VERSION 5.7 ;
  NOWIREEXTENSIONATPIN ON ;
  DIVIDERCHAR "/" ;
  BUSBITCHARS "[]" ;
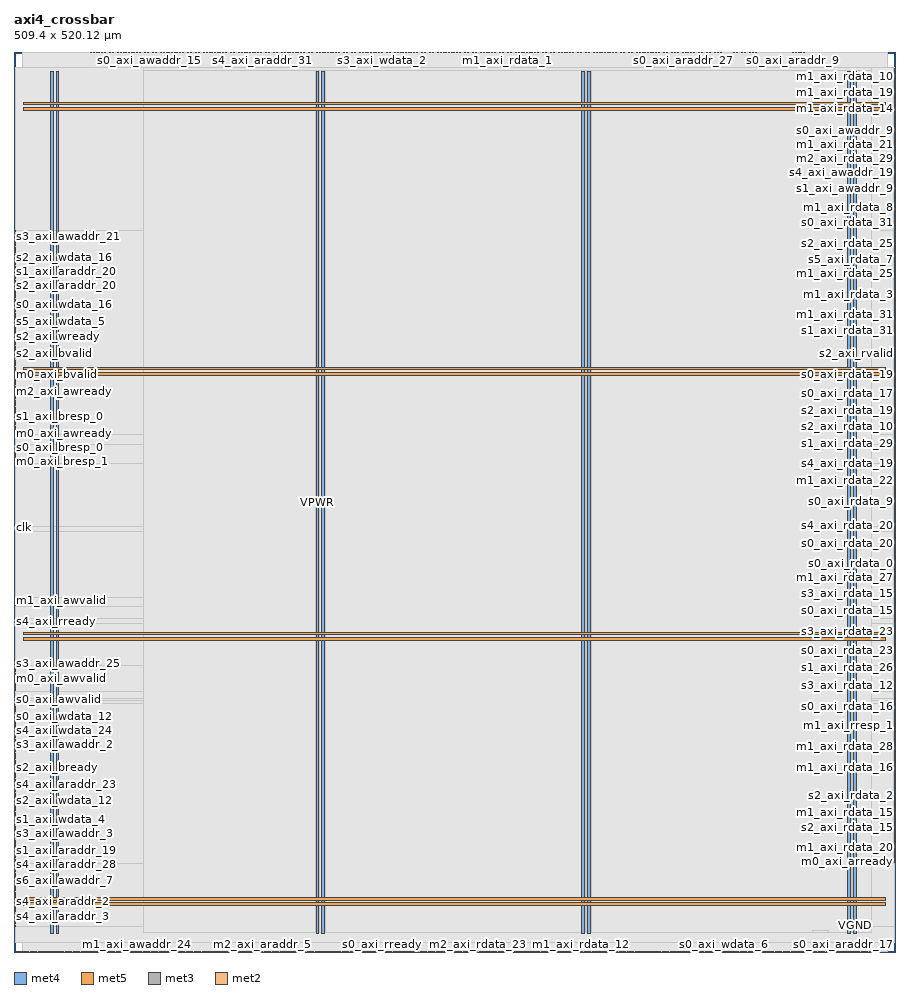
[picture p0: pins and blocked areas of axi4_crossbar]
MACRO axi4_crossbar
  CLASS BLOCK ;
  FOREIGN axi4_crossbar ;
  ORIGIN 0.000 0.000 ;
  SIZE 509.400 BY 520.120 ;
  PIN VGND
    DIRECTION INOUT ;
    USE GROUND ;
    PORT
      LAYER met4 ;
        RECT 24.340 10.640 25.940 508.880 ;
    END
    PORT
      LAYER met4 ;
        RECT 177.940 10.640 179.540 508.880 ;
    END
    PORT
      LAYER met4 ;
        RECT 331.540 10.640 333.140 508.880 ;
    END
    PORT
      LAYER met4 ;
        RECT 485.140 10.640 486.740 508.880 ;
    END
    PORT
      LAYER met5 ;
        RECT 5.520 30.030 503.700 31.630 ;
    END
    PORT
      LAYER met5 ;
        RECT 5.520 183.210 503.700 184.810 ;
    END
    PORT
      LAYER met5 ;
        RECT 5.520 336.390 503.700 337.990 ;
    END
    PORT
      LAYER met5 ;
        RECT 5.520 489.570 503.700 491.170 ;
    END
  END VGND
  PIN VPWR
    DIRECTION INOUT ;
    USE POWER ;
    PORT
      LAYER met4 ;
        RECT 21.040 10.640 22.640 508.880 ;
    END
    PORT
      LAYER met4 ;
        RECT 174.640 10.640 176.240 508.880 ;
    END
    PORT
      LAYER met4 ;
        RECT 328.240 10.640 329.840 508.880 ;
    END
    PORT
      LAYER met4 ;
        RECT 481.840 10.640 483.440 508.880 ;
    END
    PORT
      LAYER met5 ;
        RECT 5.520 26.730 503.700 28.330 ;
    END
    PORT
      LAYER met5 ;
        RECT 5.520 179.910 503.700 181.510 ;
    END
    PORT
      LAYER met5 ;
        RECT 5.520 333.090 503.700 334.690 ;
    END
    PORT
      LAYER met5 ;
        RECT 5.520 486.270 503.700 487.870 ;
    END
  END VPWR
  PIN clk
    DIRECTION INPUT ;
    USE SIGNAL ;
    ANTENNAGATEAREA 1.286700 ;
    ANTENNADIFFAREA 0.434700 ;
    PORT
      LAYER met3 ;
        RECT 0.000 244.840 0.600 245.440 ;
    END
  END clk
  PIN m0_axi_araddr_0
    DIRECTION INPUT ;
    USE SIGNAL ;
    PORT
      LAYER met2 ;
        RECT 1.930 0.000 2.210 0.280 ;
    END
  END m0_axi_araddr_0
  PIN m0_axi_araddr_1
    DIRECTION INPUT ;
    USE SIGNAL ;
    PORT
      LAYER met2 ;
        RECT 2.850 0.000 3.130 0.280 ;
    END
  END m0_axi_araddr_1
  PIN m0_axi_araddr_10
    DIRECTION INPUT ;
    USE SIGNAL ;
    PORT
      LAYER met2 ;
        RECT 3.770 0.000 4.050 0.280 ;
    END
  END m0_axi_araddr_10
  PIN m0_axi_araddr_11
    DIRECTION INPUT ;
    USE SIGNAL ;
    PORT
      LAYER met2 ;
        RECT 4.690 0.000 4.970 0.280 ;
    END
  END m0_axi_araddr_11
  PIN m0_axi_araddr_12
    DIRECTION INPUT ;
    USE SIGNAL ;
    PORT
      LAYER met2 ;
        RECT 5.610 0.000 5.890 0.280 ;
    END
  END m0_axi_araddr_12
  PIN m0_axi_araddr_13
    DIRECTION INPUT ;
    USE SIGNAL ;
    PORT
      LAYER met2 ;
        RECT 6.530 0.000 6.810 0.280 ;
    END
  END m0_axi_araddr_13
  PIN m0_axi_araddr_14
    DIRECTION INPUT ;
    USE SIGNAL ;
    PORT
      LAYER met2 ;
        RECT 7.450 0.000 7.730 0.280 ;
    END
  END m0_axi_araddr_14
  PIN m0_axi_araddr_15
    DIRECTION INPUT ;
    USE SIGNAL ;
    PORT
      LAYER met2 ;
        RECT 8.370 0.000 8.650 0.280 ;
    END
  END m0_axi_araddr_15
  PIN m0_axi_araddr_16
    DIRECTION INPUT ;
    USE SIGNAL ;
    PORT
      LAYER met2 ;
        RECT 9.290 0.000 9.570 0.280 ;
    END
  END m0_axi_araddr_16
  PIN m0_axi_araddr_17
    DIRECTION INPUT ;
    USE SIGNAL ;
    PORT
      LAYER met2 ;
        RECT 10.210 0.000 10.490 0.280 ;
    END
  END m0_axi_araddr_17
  PIN m0_axi_araddr_18
    DIRECTION INPUT ;
    USE SIGNAL ;
    PORT
      LAYER met2 ;
        RECT 11.130 0.000 11.410 0.280 ;
    END
  END m0_axi_araddr_18
  PIN m0_axi_araddr_19
    DIRECTION INPUT ;
    USE SIGNAL ;
    PORT
      LAYER met2 ;
        RECT 12.050 0.000 12.330 0.280 ;
    END
  END m0_axi_araddr_19
  PIN m0_axi_araddr_2
    DIRECTION INPUT ;
    USE SIGNAL ;
    PORT
      LAYER met2 ;
        RECT 12.970 0.000 13.250 0.280 ;
    END
  END m0_axi_araddr_2
  PIN m0_axi_araddr_20
    DIRECTION INPUT ;
    USE SIGNAL ;
    PORT
      LAYER met2 ;
        RECT 13.890 0.000 14.170 0.280 ;
    END
  END m0_axi_araddr_20
  PIN m0_axi_araddr_21
    DIRECTION INPUT ;
    USE SIGNAL ;
    PORT
      LAYER met2 ;
        RECT 14.810 0.000 15.090 0.280 ;
    END
  END m0_axi_araddr_21
  PIN m0_axi_araddr_22
    DIRECTION INPUT ;
    USE SIGNAL ;
    PORT
      LAYER met2 ;
        RECT 15.730 0.000 16.010 0.280 ;
    END
  END m0_axi_araddr_22
  PIN m0_axi_araddr_23
    DIRECTION INPUT ;
    USE SIGNAL ;
    PORT
      LAYER met2 ;
        RECT 16.650 0.000 16.930 0.280 ;
    END
  END m0_axi_araddr_23
  PIN m0_axi_araddr_24
    DIRECTION INPUT ;
    USE SIGNAL ;
    PORT
      LAYER met2 ;
        RECT 17.570 0.000 17.850 0.280 ;
    END
  END m0_axi_araddr_24
  PIN m0_axi_araddr_25
    DIRECTION INPUT ;
    USE SIGNAL ;
    PORT
      LAYER met2 ;
        RECT 18.490 0.000 18.770 0.280 ;
    END
  END m0_axi_araddr_25
  PIN m0_axi_araddr_26
    DIRECTION INPUT ;
    USE SIGNAL ;
    PORT
      LAYER met2 ;
        RECT 19.410 0.000 19.690 0.280 ;
    END
  END m0_axi_araddr_26
  PIN m0_axi_araddr_27
    DIRECTION INPUT ;
    USE SIGNAL ;
    PORT
      LAYER met2 ;
        RECT 20.330 0.000 20.610 0.280 ;
    END
  END m0_axi_araddr_27
  PIN m0_axi_araddr_28
    DIRECTION INPUT ;
    USE SIGNAL ;
    PORT
      LAYER met2 ;
        RECT 21.250 0.000 21.530 0.280 ;
    END
  END m0_axi_araddr_28
  PIN m0_axi_araddr_29
    DIRECTION INPUT ;
    USE SIGNAL ;
    PORT
      LAYER met2 ;
        RECT 22.170 0.000 22.450 0.280 ;
    END
  END m0_axi_araddr_29
  PIN m0_axi_araddr_3
    DIRECTION INPUT ;
    USE SIGNAL ;
    PORT
      LAYER met2 ;
        RECT 23.090 0.000 23.370 0.280 ;
    END
  END m0_axi_araddr_3
  PIN m0_axi_araddr_30
    DIRECTION INPUT ;
    USE SIGNAL ;
    PORT
      LAYER met2 ;
        RECT 24.010 0.000 24.290 0.280 ;
    END
  END m0_axi_araddr_30
  PIN m0_axi_araddr_31
    DIRECTION INPUT ;
    USE SIGNAL ;
    PORT
      LAYER met2 ;
        RECT 24.930 0.000 25.210 0.280 ;
    END
  END m0_axi_araddr_31
  PIN m0_axi_araddr_4
    DIRECTION INPUT ;
    USE SIGNAL ;
    PORT
      LAYER met2 ;
        RECT 25.850 0.000 26.130 0.280 ;
    END
  END m0_axi_araddr_4
  PIN m0_axi_araddr_5
    DIRECTION INPUT ;
    USE SIGNAL ;
    PORT
      LAYER met2 ;
        RECT 26.770 0.000 27.050 0.280 ;
    END
  END m0_axi_araddr_5
  PIN m0_axi_araddr_6
    DIRECTION INPUT ;
    USE SIGNAL ;
    PORT
      LAYER met2 ;
        RECT 27.690 0.000 27.970 0.280 ;
    END
  END m0_axi_araddr_6
  PIN m0_axi_araddr_7
    DIRECTION INPUT ;
    USE SIGNAL ;
    PORT
      LAYER met2 ;
        RECT 28.610 0.000 28.890 0.280 ;
    END
  END m0_axi_araddr_7
  PIN m0_axi_araddr_8
    DIRECTION INPUT ;
    USE SIGNAL ;
    PORT
      LAYER met2 ;
        RECT 29.530 0.000 29.810 0.280 ;
    END
  END m0_axi_araddr_8
  PIN m0_axi_araddr_9
    DIRECTION INPUT ;
    USE SIGNAL ;
    PORT
      LAYER met2 ;
        RECT 30.450 0.000 30.730 0.280 ;
    END
  END m0_axi_araddr_9
  PIN m0_axi_arready
    DIRECTION OUTPUT ;
    USE SIGNAL ;
    ANTENNAGATEAREA 0.434700 ;
    ANTENNADIFFAREA 0.434700 ;
    PORT
      LAYER met3 ;
        RECT 508.800 51.720 509.400 52.320 ;
    END
  END m0_axi_arready
  PIN m0_axi_arvalid
    DIRECTION INPUT ;
    USE SIGNAL ;
    ANTENNAGATEAREA 0.647700 ;
    ANTENNADIFFAREA 0.434700 ;
    PORT
      LAYER met2 ;
        RECT 167.530 519.840 167.810 520.120 ;
    END
  END m0_axi_arvalid
  PIN m0_axi_awready
    DIRECTION OUTPUT ;
    USE SIGNAL ;
    ANTENNAGATEAREA 0.434700 ;
    ANTENNADIFFAREA 1.137600 ;
    PORT
      LAYER met3 ;
        RECT 0.000 299.240 0.600 299.840 ;
    END
  END m0_axi_awready
  PIN m0_axi_awvalid
    DIRECTION INPUT ;
    USE SIGNAL ;
    ANTENNAGATEAREA 0.647700 ;
    ANTENNADIFFAREA 0.434700 ;
    PORT
      LAYER met3 ;
        RECT 0.000 157.800 0.600 158.400 ;
    END
  END m0_axi_awvalid
  PIN m0_axi_bresp_0
    DIRECTION OUTPUT ;
    USE SIGNAL ;
    ANTENNAGATEAREA 0.434700 ;
    ANTENNADIFFAREA 1.137600 ;
    PORT
      LAYER met3 ;
        RECT 0.000 292.440 0.600 293.040 ;
    END
  END m0_axi_bresp_0
  PIN m0_axi_bresp_1
    DIRECTION OUTPUT ;
    USE SIGNAL ;
    ANTENNAGATEAREA 0.434700 ;
    ANTENNADIFFAREA 1.137600 ;
    PORT
      LAYER met3 ;
        RECT 0.000 282.920 0.600 283.520 ;
    END
  END m0_axi_bresp_1
  PIN m0_axi_bvalid
    DIRECTION OUTPUT ;
    USE SIGNAL ;
    ANTENNAGATEAREA 0.434700 ;
    ANTENNADIFFAREA 1.137600 ;
    PORT
      LAYER met3 ;
        RECT 0.000 333.240 0.600 333.840 ;
    END
  END m0_axi_bvalid
  PIN m0_axi_rdata_0
    DIRECTION OUTPUT ;
    USE SIGNAL ;
    PORT
      LAYER met2 ;
        RECT 31.370 0.000 31.650 0.280 ;
    END
  END m0_axi_rdata_0
  PIN m0_axi_rdata_1
    DIRECTION OUTPUT ;
    USE SIGNAL ;
    PORT
      LAYER met2 ;
        RECT 32.290 0.000 32.570 0.280 ;
    END
  END m0_axi_rdata_1
  PIN m0_axi_rdata_10
    DIRECTION OUTPUT ;
    USE SIGNAL ;
    PORT
      LAYER met2 ;
        RECT 33.210 0.000 33.490 0.280 ;
    END
  END m0_axi_rdata_10
  PIN m0_axi_rdata_11
    DIRECTION OUTPUT ;
    USE SIGNAL ;
    PORT
      LAYER met2 ;
        RECT 34.130 0.000 34.410 0.280 ;
    END
  END m0_axi_rdata_11
  PIN m0_axi_rdata_12
    DIRECTION OUTPUT ;
    USE SIGNAL ;
    PORT
      LAYER met2 ;
        RECT 35.050 0.000 35.330 0.280 ;
    END
  END m0_axi_rdata_12
  PIN m0_axi_rdata_13
    DIRECTION OUTPUT ;
    USE SIGNAL ;
    PORT
      LAYER met2 ;
        RECT 35.970 0.000 36.250 0.280 ;
    END
  END m0_axi_rdata_13
  PIN m0_axi_rdata_14
    DIRECTION OUTPUT ;
    USE SIGNAL ;
    ANTENNAGATEAREA 0.434700 ;
    ANTENNADIFFAREA 0.775300 ;
    PORT
      LAYER met2 ;
        RECT 254.930 519.840 255.210 520.120 ;
    END
  END m0_axi_rdata_14
  PIN m0_axi_rdata_15
    DIRECTION OUTPUT ;
    USE SIGNAL ;
    PORT
      LAYER met2 ;
        RECT 36.890 0.000 37.170 0.280 ;
    END
  END m0_axi_rdata_15
  PIN m0_axi_rdata_16
    DIRECTION OUTPUT ;
    USE SIGNAL ;
    PORT
      LAYER met2 ;
        RECT 37.810 0.000 38.090 0.280 ;
    END
  END m0_axi_rdata_16
  PIN m0_axi_rdata_17
    DIRECTION OUTPUT ;
    USE SIGNAL ;
    ANTENNAGATEAREA 0.434700 ;
    ANTENNADIFFAREA 0.775300 ;
    PORT
      LAYER met2 ;
        RECT 249.410 519.840 249.690 520.120 ;
    END
  END m0_axi_rdata_17
  PIN m0_axi_rdata_18
    DIRECTION OUTPUT ;
    USE SIGNAL ;
    PORT
      LAYER met2 ;
        RECT 38.730 0.000 39.010 0.280 ;
    END
  END m0_axi_rdata_18
  PIN m0_axi_rdata_19
    DIRECTION OUTPUT ;
    USE SIGNAL ;
    PORT
      LAYER met2 ;
        RECT 39.650 0.000 39.930 0.280 ;
    END
  END m0_axi_rdata_19
  PIN m0_axi_rdata_2
    DIRECTION OUTPUT ;
    USE SIGNAL ;
    PORT
      LAYER met2 ;
        RECT 40.570 0.000 40.850 0.280 ;
    END
  END m0_axi_rdata_2
  PIN m0_axi_rdata_20
    DIRECTION OUTPUT ;
    USE SIGNAL ;
    ANTENNAGATEAREA 0.434700 ;
    ANTENNADIFFAREA 0.775300 ;
    PORT
      LAYER met2 ;
        RECT 247.570 519.840 247.850 520.120 ;
    END
  END m0_axi_rdata_20
  PIN m0_axi_rdata_21
    DIRECTION OUTPUT ;
    USE SIGNAL ;
    PORT
      LAYER met2 ;
        RECT 41.490 0.000 41.770 0.280 ;
    END
  END m0_axi_rdata_21
  PIN m0_axi_rdata_22
    DIRECTION OUTPUT ;
    USE SIGNAL ;
    ANTENNAGATEAREA 0.434700 ;
    ANTENNADIFFAREA 0.775300 ;
    PORT
      LAYER met2 ;
        RECT 243.890 519.840 244.170 520.120 ;
    END
  END m0_axi_rdata_22
  PIN m0_axi_rdata_23
    DIRECTION OUTPUT ;
    USE SIGNAL ;
    PORT
      LAYER met2 ;
        RECT 42.410 0.000 42.690 0.280 ;
    END
  END m0_axi_rdata_23
  PIN m0_axi_rdata_24
    DIRECTION OUTPUT ;
    USE SIGNAL ;
    ANTENNAGATEAREA 0.434700 ;
    ANTENNADIFFAREA 0.775300 ;
    PORT
      LAYER met2 ;
        RECT 245.730 519.840 246.010 520.120 ;
    END
  END m0_axi_rdata_24
  PIN m0_axi_rdata_25
    DIRECTION OUTPUT ;
    USE SIGNAL ;
    PORT
      LAYER met2 ;
        RECT 43.330 0.000 43.610 0.280 ;
    END
  END m0_axi_rdata_25
  PIN m0_axi_rdata_26
    DIRECTION OUTPUT ;
    USE SIGNAL ;
    PORT
      LAYER met2 ;
        RECT 44.250 0.000 44.530 0.280 ;
    END
  END m0_axi_rdata_26
  PIN m0_axi_rdata_27
    DIRECTION OUTPUT ;
    USE SIGNAL ;
    PORT
      LAYER met2 ;
        RECT 45.170 0.000 45.450 0.280 ;
    END
  END m0_axi_rdata_27
  PIN m0_axi_rdata_28
    DIRECTION OUTPUT ;
    USE SIGNAL ;
    PORT
      LAYER met2 ;
        RECT 46.090 0.000 46.370 0.280 ;
    END
  END m0_axi_rdata_28
  PIN m0_axi_rdata_29
    DIRECTION OUTPUT ;
    USE SIGNAL ;
    ANTENNAGATEAREA 0.434700 ;
    ANTENNADIFFAREA 0.775300 ;
    PORT
      LAYER met2 ;
        RECT 242.050 519.840 242.330 520.120 ;
    END
  END m0_axi_rdata_29
  PIN m0_axi_rdata_3
    DIRECTION OUTPUT ;
    USE SIGNAL ;
    PORT
      LAYER met2 ;
        RECT 47.010 0.000 47.290 0.280 ;
    END
  END m0_axi_rdata_3
  PIN m0_axi_rdata_30
    DIRECTION OUTPUT ;
    USE SIGNAL ;
    PORT
      LAYER met2 ;
        RECT 47.930 0.000 48.210 0.280 ;
    END
  END m0_axi_rdata_30
  PIN m0_axi_rdata_31
    DIRECTION OUTPUT ;
    USE SIGNAL ;
    PORT
      LAYER met2 ;
        RECT 48.850 0.000 49.130 0.280 ;
    END
  END m0_axi_rdata_31
  PIN m0_axi_rdata_4
    DIRECTION OUTPUT ;
    USE SIGNAL ;
    ANTENNAGATEAREA 0.434700 ;
    ANTENNADIFFAREA 0.775300 ;
    PORT
      LAYER met2 ;
        RECT 252.170 519.840 252.450 520.120 ;
    END
  END m0_axi_rdata_4
  PIN m0_axi_rdata_5
    DIRECTION OUTPUT ;
    USE SIGNAL ;
    PORT
      LAYER met2 ;
        RECT 49.770 0.000 50.050 0.280 ;
    END
  END m0_axi_rdata_5
  PIN m0_axi_rdata_6
    DIRECTION OUTPUT ;
    USE SIGNAL ;
    PORT
      LAYER met2 ;
        RECT 50.690 0.000 50.970 0.280 ;
    END
  END m0_axi_rdata_6
  PIN m0_axi_rdata_7
    DIRECTION OUTPUT ;
    USE SIGNAL ;
    PORT
      LAYER met2 ;
        RECT 51.610 0.000 51.890 0.280 ;
    END
  END m0_axi_rdata_7
  PIN m0_axi_rdata_8
    DIRECTION OUTPUT ;
    USE SIGNAL ;
    ANTENNAGATEAREA 0.434700 ;
    ANTENNADIFFAREA 0.775300 ;
    PORT
      LAYER met2 ;
        RECT 246.650 519.840 246.930 520.120 ;
    END
  END m0_axi_rdata_8
  PIN m0_axi_rdata_9
    DIRECTION OUTPUT ;
    USE SIGNAL ;
    PORT
      LAYER met2 ;
        RECT 52.530 0.000 52.810 0.280 ;
    END
  END m0_axi_rdata_9
  PIN m0_axi_rready
    DIRECTION INPUT ;
    USE SIGNAL ;
    ANTENNAGATEAREA 0.647700 ;
    ANTENNADIFFAREA 0.434700 ;
    PORT
      LAYER met2 ;
        RECT 236.530 0.000 236.810 0.280 ;
    END
  END m0_axi_rready
  PIN m0_axi_rresp_0
    DIRECTION OUTPUT ;
    USE SIGNAL ;
    PORT
      LAYER met2 ;
        RECT 53.450 0.000 53.730 0.280 ;
    END
  END m0_axi_rresp_0
  PIN m0_axi_rresp_1
    DIRECTION OUTPUT ;
    USE SIGNAL ;
    PORT
      LAYER met2 ;
        RECT 54.370 0.000 54.650 0.280 ;
    END
  END m0_axi_rresp_1
  PIN m0_axi_rvalid
    DIRECTION OUTPUT ;
    USE SIGNAL ;
    ANTENNAGATEAREA 0.434700 ;
    ANTENNADIFFAREA 1.137600 ;
    PORT
      LAYER met2 ;
        RECT 249.410 0.000 249.690 0.280 ;
    END
  END m0_axi_rvalid
  PIN m0_axi_wready
    DIRECTION OUTPUT ;
    USE SIGNAL ;
    ANTENNAGATEAREA 0.434700 ;
    ANTENNADIFFAREA 1.137600 ;
    PORT
      LAYER met3 ;
        RECT 0.000 346.840 0.600 347.440 ;
    END
  END m0_axi_wready
  PIN m0_axi_wvalid
    DIRECTION INPUT ;
    USE SIGNAL ;
    ANTENNAGATEAREA 0.647700 ;
    ANTENNADIFFAREA 0.434700 ;
    PORT
      LAYER met3 ;
        RECT 0.000 155.080 0.600 155.680 ;
    END
  END m0_axi_wvalid
  PIN m1_axi_arready
    DIRECTION OUTPUT ;
    USE SIGNAL ;
    ANTENNAGATEAREA 0.434700 ;
    ANTENNADIFFAREA 1.137600 ;
    PORT
      LAYER met2 ;
        RECT 255.850 519.840 256.130 520.120 ;
    END
  END m1_axi_arready
  PIN m1_axi_awaddr_0
    DIRECTION INPUT ;
    USE SIGNAL ;
    PORT
      LAYER met2 ;
        RECT 55.290 0.000 55.570 0.280 ;
    END
  END m1_axi_awaddr_0
  PIN m1_axi_awaddr_1
    DIRECTION INPUT ;
    USE SIGNAL ;
    PORT
      LAYER met2 ;
        RECT 56.210 0.000 56.490 0.280 ;
    END
  END m1_axi_awaddr_1
  PIN m1_axi_awaddr_10
    DIRECTION INPUT ;
    USE SIGNAL ;
    PORT
      LAYER met2 ;
        RECT 57.130 0.000 57.410 0.280 ;
    END
  END m1_axi_awaddr_10
  PIN m1_axi_awaddr_11
    DIRECTION INPUT ;
    USE SIGNAL ;
    PORT
      LAYER met2 ;
        RECT 58.050 0.000 58.330 0.280 ;
    END
  END m1_axi_awaddr_11
  PIN m1_axi_awaddr_12
    DIRECTION INPUT ;
    USE SIGNAL ;
    PORT
      LAYER met2 ;
        RECT 58.970 0.000 59.250 0.280 ;
    END
  END m1_axi_awaddr_12
  PIN m1_axi_awaddr_13
    DIRECTION INPUT ;
    USE SIGNAL ;
    PORT
      LAYER met2 ;
        RECT 59.890 0.000 60.170 0.280 ;
    END
  END m1_axi_awaddr_13
  PIN m1_axi_awaddr_14
    DIRECTION INPUT ;
    USE SIGNAL ;
    PORT
      LAYER met2 ;
        RECT 60.810 0.000 61.090 0.280 ;
    END
  END m1_axi_awaddr_14
  PIN m1_axi_awaddr_15
    DIRECTION INPUT ;
    USE SIGNAL ;
    PORT
      LAYER met2 ;
        RECT 61.730 0.000 62.010 0.280 ;
    END
  END m1_axi_awaddr_15
  PIN m1_axi_awaddr_16
    DIRECTION INPUT ;
    USE SIGNAL ;
    PORT
      LAYER met2 ;
        RECT 62.650 0.000 62.930 0.280 ;
    END
  END m1_axi_awaddr_16
  PIN m1_axi_awaddr_17
    DIRECTION INPUT ;
    USE SIGNAL ;
    PORT
      LAYER met2 ;
        RECT 63.570 0.000 63.850 0.280 ;
    END
  END m1_axi_awaddr_17
  PIN m1_axi_awaddr_18
    DIRECTION INPUT ;
    USE SIGNAL ;
    PORT
      LAYER met2 ;
        RECT 64.490 0.000 64.770 0.280 ;
    END
  END m1_axi_awaddr_18
  PIN m1_axi_awaddr_19
    DIRECTION INPUT ;
    USE SIGNAL ;
    PORT
      LAYER met2 ;
        RECT 65.410 0.000 65.690 0.280 ;
    END
  END m1_axi_awaddr_19
  PIN m1_axi_awaddr_2
    DIRECTION INPUT ;
    USE SIGNAL ;
    PORT
      LAYER met2 ;
        RECT 66.330 0.000 66.610 0.280 ;
    END
  END m1_axi_awaddr_2
  PIN m1_axi_awaddr_20
    DIRECTION INPUT ;
    USE SIGNAL ;
    PORT
      LAYER met2 ;
        RECT 67.250 0.000 67.530 0.280 ;
    END
  END m1_axi_awaddr_20
  PIN m1_axi_awaddr_21
    DIRECTION INPUT ;
    USE SIGNAL ;
    PORT
      LAYER met2 ;
        RECT 68.170 0.000 68.450 0.280 ;
    END
  END m1_axi_awaddr_21
  PIN m1_axi_awaddr_22
    DIRECTION INPUT ;
    USE SIGNAL ;
    PORT
      LAYER met2 ;
        RECT 69.090 0.000 69.370 0.280 ;
    END
  END m1_axi_awaddr_22
  PIN m1_axi_awaddr_23
    DIRECTION INPUT ;
    USE SIGNAL ;
    PORT
      LAYER met2 ;
        RECT 70.010 0.000 70.290 0.280 ;
    END
  END m1_axi_awaddr_23
  PIN m1_axi_awaddr_24
    DIRECTION INPUT ;
    USE SIGNAL ;
    PORT
      LAYER met2 ;
        RECT 70.930 0.000 71.210 0.280 ;
    END
  END m1_axi_awaddr_24
  PIN m1_axi_awaddr_25
    DIRECTION INPUT ;
    USE SIGNAL ;
    PORT
      LAYER met2 ;
        RECT 71.850 0.000 72.130 0.280 ;
    END
  END m1_axi_awaddr_25
  PIN m1_axi_awaddr_26
    DIRECTION INPUT ;
    USE SIGNAL ;
    PORT
      LAYER met2 ;
        RECT 72.770 0.000 73.050 0.280 ;
    END
  END m1_axi_awaddr_26
  PIN m1_axi_awaddr_27
    DIRECTION INPUT ;
    USE SIGNAL ;
    PORT
      LAYER met2 ;
        RECT 73.690 0.000 73.970 0.280 ;
    END
  END m1_axi_awaddr_27
  PIN m1_axi_awaddr_28
    DIRECTION INPUT ;
    USE SIGNAL ;
    PORT
      LAYER met2 ;
        RECT 74.610 0.000 74.890 0.280 ;
    END
  END m1_axi_awaddr_28
  PIN m1_axi_awaddr_29
    DIRECTION INPUT ;
    USE SIGNAL ;
    PORT
      LAYER met2 ;
        RECT 75.530 0.000 75.810 0.280 ;
    END
  END m1_axi_awaddr_29
  PIN m1_axi_awaddr_3
    DIRECTION INPUT ;
    USE SIGNAL ;
    PORT
      LAYER met2 ;
        RECT 76.450 0.000 76.730 0.280 ;
    END
  END m1_axi_awaddr_3
  PIN m1_axi_awaddr_30
    DIRECTION INPUT ;
    USE SIGNAL ;
    PORT
      LAYER met2 ;
        RECT 77.370 0.000 77.650 0.280 ;
    END
  END m1_axi_awaddr_30
  PIN m1_axi_awaddr_31
    DIRECTION INPUT ;
    USE SIGNAL ;
    PORT
      LAYER met2 ;
        RECT 78.290 0.000 78.570 0.280 ;
    END
  END m1_axi_awaddr_31
  PIN m1_axi_awaddr_4
    DIRECTION INPUT ;
    USE SIGNAL ;
    PORT
      LAYER met2 ;
        RECT 79.210 0.000 79.490 0.280 ;
    END
  END m1_axi_awaddr_4
  PIN m1_axi_awaddr_5
    DIRECTION INPUT ;
    USE SIGNAL ;
    PORT
      LAYER met2 ;
        RECT 80.130 0.000 80.410 0.280 ;
    END
  END m1_axi_awaddr_5
  PIN m1_axi_awaddr_6
    DIRECTION INPUT ;
    USE SIGNAL ;
    PORT
      LAYER met2 ;
        RECT 81.050 0.000 81.330 0.280 ;
    END
  END m1_axi_awaddr_6
  PIN m1_axi_awaddr_7
    DIRECTION INPUT ;
    USE SIGNAL ;
    PORT
      LAYER met2 ;
        RECT 81.970 0.000 82.250 0.280 ;
    END
  END m1_axi_awaddr_7
  PIN m1_axi_awaddr_8
    DIRECTION INPUT ;
    USE SIGNAL ;
    PORT
      LAYER met2 ;
        RECT 82.890 0.000 83.170 0.280 ;
    END
  END m1_axi_awaddr_8
  PIN m1_axi_awaddr_9
    DIRECTION INPUT ;
    USE SIGNAL ;
    PORT
      LAYER met2 ;
        RECT 83.810 0.000 84.090 0.280 ;
    END
  END m1_axi_awaddr_9
  PIN m1_axi_awready
    DIRECTION OUTPUT ;
    USE SIGNAL ;
    ANTENNAGATEAREA 0.434700 ;
    ANTENNADIFFAREA 1.137600 ;
    PORT
      LAYER met3 ;
        RECT 0.000 344.120 0.600 344.720 ;
    END
  END m1_axi_awready
  PIN m1_axi_awvalid
    DIRECTION INPUT ;
    USE SIGNAL ;
    ANTENNAGATEAREA 0.647700 ;
    ANTENNADIFFAREA 0.434700 ;
    PORT
      LAYER met3 ;
        RECT 0.000 202.680 0.600 203.280 ;
    END
  END m1_axi_awvalid
  PIN m1_axi_bready
    DIRECTION INPUT ;
    USE SIGNAL ;
    PORT
      LAYER met2 ;
        RECT 84.730 0.000 85.010 0.280 ;
    END
  END m1_axi_bready
  PIN m1_axi_bresp_0
    DIRECTION OUTPUT ;
    USE SIGNAL ;
    ANTENNAGATEAREA 0.434700 ;
    ANTENNADIFFAREA 1.137600 ;
    PORT
      LAYER met3 ;
        RECT 0.000 287.000 0.600 287.600 ;
    END
  END m1_axi_bresp_0
  PIN m1_axi_bresp_1
    DIRECTION OUTPUT ;
    USE SIGNAL ;
    ANTENNAGATEAREA 0.434700 ;
    ANTENNADIFFAREA 1.137600 ;
    PORT
      LAYER met3 ;
        RECT 0.000 284.280 0.600 284.880 ;
    END
  END m1_axi_bresp_1
  PIN m1_axi_bvalid
    DIRECTION OUTPUT ;
    USE SIGNAL ;
    ANTENNAGATEAREA 0.434700 ;
    ANTENNADIFFAREA 1.137600 ;
    PORT
      LAYER met3 ;
        RECT 0.000 331.880 0.600 332.480 ;
    END
  END m1_axi_bvalid
  PIN m1_axi_rdata_0
    DIRECTION OUTPUT ;
    USE SIGNAL ;
    ANTENNAGATEAREA 0.434700 ;
    ANTENNADIFFAREA 0.880200 ;
    PORT
      LAYER met3 ;
        RECT 508.800 65.320 509.400 65.920 ;
    END
  END m1_axi_rdata_0
  PIN m1_axi_rdata_1
    DIRECTION OUTPUT ;
    USE SIGNAL ;
    ANTENNAGATEAREA 0.434700 ;
    ANTENNADIFFAREA 1.137600 ;
    PORT
      LAYER met2 ;
        RECT 285.290 519.840 285.570 520.120 ;
    END
  END m1_axi_rdata_1
  PIN m1_axi_rdata_10
    DIRECTION OUTPUT ;
    USE SIGNAL ;
    ANTENNAGATEAREA 0.560700 ;
    ANTENNADIFFAREA 0.863700 ;
    PORT
      LAYER met3 ;
        RECT 508.800 510.040 509.400 510.640 ;
    END
  END m1_axi_rdata_10
  PIN m1_axi_rdata_11
    DIRECTION OUTPUT ;
    USE SIGNAL ;
    ANTENNAGATEAREA 0.560700 ;
    ANTENNADIFFAREA 0.863700 ;
    PORT
      LAYER met2 ;
        RECT 283.450 0.000 283.730 0.280 ;
    END
  END m1_axi_rdata_11
  PIN m1_axi_rdata_12
    DIRECTION OUTPUT ;
    USE SIGNAL ;
    ANTENNAGATEAREA 0.560700 ;
    ANTENNADIFFAREA 0.863700 ;
    PORT
      LAYER met2 ;
        RECT 327.610 0.000 327.890 0.280 ;
    END
  END m1_axi_rdata_12
  PIN m1_axi_rdata_13
    DIRECTION OUTPUT ;
    USE SIGNAL ;
    ANTENNAGATEAREA 0.560700 ;
    ANTENNADIFFAREA 0.863700 ;
    PORT
      LAYER met3 ;
        RECT 508.800 62.600 509.400 63.200 ;
    END
  END m1_axi_rdata_13
  PIN m1_axi_rdata_14
    DIRECTION OUTPUT ;
    USE SIGNAL ;
    ANTENNAGATEAREA 0.434700 ;
    ANTENNADIFFAREA 1.137600 ;
    PORT
      LAYER met3 ;
        RECT 508.800 486.920 509.400 487.520 ;
    END
  END m1_axi_rdata_14
  PIN m1_axi_rdata_15
    DIRECTION OUTPUT ;
    USE SIGNAL ;
    ANTENNAGATEAREA 0.560700 ;
    ANTENNADIFFAREA 0.863700 ;
    PORT
      LAYER met3 ;
        RECT 508.800 80.280 509.400 80.880 ;
    END
  END m1_axi_rdata_15
  PIN m1_axi_rdata_16
    DIRECTION OUTPUT ;
    USE SIGNAL ;
    ANTENNAGATEAREA 0.560700 ;
    ANTENNADIFFAREA 0.863700 ;
    PORT
      LAYER met3 ;
        RECT 508.800 106.120 509.400 106.720 ;
    END
  END m1_axi_rdata_16
  PIN m1_axi_rdata_17
    DIRECTION OUTPUT ;
    USE SIGNAL ;
    ANTENNAGATEAREA 0.434700 ;
    ANTENNADIFFAREA 1.137600 ;
    PORT
      LAYER met3 ;
        RECT 508.800 503.240 509.400 503.840 ;
    END
  END m1_axi_rdata_17
  PIN m1_axi_rdata_18
    DIRECTION OUTPUT ;
    USE SIGNAL ;
    ANTENNAGATEAREA 0.560700 ;
    ANTENNADIFFAREA 0.863700 ;
    PORT
      LAYER met2 ;
        RECT 275.170 0.000 275.450 0.280 ;
    END
  END m1_axi_rdata_18
  PIN m1_axi_rdata_19
    DIRECTION OUTPUT ;
    USE SIGNAL ;
    ANTENNAGATEAREA 0.434700 ;
    ANTENNADIFFAREA 0.832300 ;
    PORT
      LAYER met3 ;
        RECT 508.800 492.360 509.400 492.960 ;
    END
  END m1_axi_rdata_19
  PIN m1_axi_rdata_2
    DIRECTION OUTPUT ;
    USE SIGNAL ;
    ANTENNAGATEAREA 0.560700 ;
    ANTENNADIFFAREA 0.863700 ;
    PORT
      LAYER met3 ;
        RECT 508.800 88.440 509.400 89.040 ;
    END
  END m1_axi_rdata_2
  PIN m1_axi_rdata_20
    DIRECTION OUTPUT ;
    USE SIGNAL ;
    ANTENNAGATEAREA 0.560700 ;
    ANTENNADIFFAREA 0.863700 ;
    PORT
      LAYER met3 ;
        RECT 508.800 59.880 509.400 60.480 ;
    END
  END m1_axi_rdata_20
  PIN m1_axi_rdata_21
    DIRECTION OUTPUT ;
    USE SIGNAL ;
    ANTENNAGATEAREA 0.560700 ;
    ANTENNADIFFAREA 0.863700 ;
    PORT
      LAYER met3 ;
        RECT 508.800 466.520 509.400 467.120 ;
    END
  END m1_axi_rdata_21
  PIN m1_axi_rdata_22
    DIRECTION OUTPUT ;
    USE SIGNAL ;
    ANTENNAGATEAREA 0.434700 ;
    ANTENNADIFFAREA 1.137600 ;
    PORT
      LAYER met3 ;
        RECT 508.800 272.040 509.400 272.640 ;
    END
  END m1_axi_rdata_22
  PIN m1_axi_rdata_23
    DIRECTION OUTPUT ;
    USE SIGNAL ;
    ANTENNAGATEAREA 0.560700 ;
    ANTENNADIFFAREA 0.863700 ;
    PORT
      LAYER met3 ;
        RECT 508.800 89.800 509.400 90.400 ;
    END
  END m1_axi_rdata_23
  PIN m1_axi_rdata_24
    DIRECTION OUTPUT ;
    USE SIGNAL ;
    ANTENNAGATEAREA 0.560700 ;
    ANTENNADIFFAREA 0.863700 ;
    PORT
      LAYER met2 ;
        RECT 286.210 0.000 286.490 0.280 ;
    END
  END m1_axi_rdata_24
  PIN m1_axi_rdata_25
    DIRECTION OUTPUT ;
    USE SIGNAL ;
    ANTENNAGATEAREA 0.560700 ;
    ANTENNADIFFAREA 0.863700 ;
    PORT
      LAYER met3 ;
        RECT 508.800 391.720 509.400 392.320 ;
    END
  END m1_axi_rdata_25
  PIN m1_axi_rdata_26
    DIRECTION OUTPUT ;
    USE SIGNAL ;
    ANTENNAGATEAREA 0.560700 ;
    ANTENNADIFFAREA 0.863700 ;
    PORT
      LAYER met3 ;
        RECT 508.800 97.960 509.400 98.560 ;
    END
  END m1_axi_rdata_26
  PIN m1_axi_rdata_27
    DIRECTION OUTPUT ;
    USE SIGNAL ;
    ANTENNAGATEAREA 0.560700 ;
    ANTENNADIFFAREA 0.863700 ;
    PORT
      LAYER met3 ;
        RECT 508.800 216.280 509.400 216.880 ;
    END
  END m1_axi_rdata_27
  PIN m1_axi_rdata_28
    DIRECTION OUTPUT ;
    USE SIGNAL ;
    ANTENNAGATEAREA 0.560700 ;
    ANTENNADIFFAREA 0.863700 ;
    PORT
      LAYER met3 ;
        RECT 508.800 118.360 509.400 118.960 ;
    END
  END m1_axi_rdata_28
  PIN m1_axi_rdata_29
    DIRECTION OUTPUT ;
    USE SIGNAL ;
    ANTENNAGATEAREA 0.434700 ;
    ANTENNADIFFAREA 1.137600 ;
    PORT
      LAYER met3 ;
        RECT 508.800 364.520 509.400 365.120 ;
    END
  END m1_axi_rdata_29
  PIN m1_axi_rdata_3
    DIRECTION OUTPUT ;
    USE SIGNAL ;
    ANTENNAGATEAREA 0.560700 ;
    ANTENNADIFFAREA 0.863700 ;
    PORT
      LAYER met3 ;
        RECT 508.800 379.480 509.400 380.080 ;
    END
  END m1_axi_rdata_3
  PIN m1_axi_rdata_30
    DIRECTION OUTPUT ;
    USE SIGNAL ;
    ANTENNAGATEAREA 0.560700 ;
    ANTENNADIFFAREA 0.863700 ;
    PORT
      LAYER met3 ;
        RECT 508.800 121.080 509.400 121.680 ;
    END
  END m1_axi_rdata_30
  PIN m1_axi_rdata_31
    DIRECTION OUTPUT ;
    USE SIGNAL ;
    ANTENNAGATEAREA 0.434700 ;
    ANTENNADIFFAREA 1.137600 ;
    PORT
      LAYER met3 ;
        RECT 508.800 372.680 509.400 373.280 ;
    END
  END m1_axi_rdata_31
  PIN m1_axi_rdata_4
    DIRECTION OUTPUT ;
    USE SIGNAL ;
    ANTENNAGATEAREA 0.434700 ;
    ANTENNADIFFAREA 1.137600 ;
    PORT
      LAYER met2 ;
        RECT 272.410 519.840 272.690 520.120 ;
    END
  END m1_axi_rdata_4
  PIN m1_axi_rdata_5
    DIRECTION OUTPUT ;
    USE SIGNAL ;
    ANTENNAGATEAREA 0.434700 ;
    ANTENNADIFFAREA 0.880200 ;
    PORT
      LAYER met3 ;
        RECT 508.800 61.240 509.400 61.840 ;
    END
  END m1_axi_rdata_5
  PIN m1_axi_rdata_6
    DIRECTION OUTPUT ;
    USE SIGNAL ;
    ANTENNAGATEAREA 0.434700 ;
    ANTENNADIFFAREA 0.832300 ;
    PORT
      LAYER met3 ;
        RECT 508.800 496.440 509.400 497.040 ;
    END
  END m1_axi_rdata_6
  PIN m1_axi_rdata_7
    DIRECTION OUTPUT ;
    USE SIGNAL ;
    ANTENNAGATEAREA 0.560700 ;
    ANTENNADIFFAREA 0.863700 ;
    PORT
      LAYER met3 ;
        RECT 508.800 390.360 509.400 390.960 ;
    END
  END m1_axi_rdata_7
  PIN m1_axi_rdata_8
    DIRECTION OUTPUT ;
    USE SIGNAL ;
    ANTENNAGATEAREA 0.434700 ;
    ANTENNADIFFAREA 1.137600 ;
    PORT
      LAYER met3 ;
        RECT 508.800 429.800 509.400 430.400 ;
    END
  END m1_axi_rdata_8
  PIN m1_axi_rdata_9
    DIRECTION OUTPUT ;
    USE SIGNAL ;
    ANTENNAGATEAREA 0.434700 ;
    ANTENNADIFFAREA 0.832300 ;
    PORT
      LAYER met3 ;
        RECT 508.800 267.960 509.400 268.560 ;
    END
  END m1_axi_rdata_9
  PIN m1_axi_rresp_0
    DIRECTION OUTPUT ;
    USE SIGNAL ;
    ANTENNAGATEAREA 0.434700 ;
    ANTENNADIFFAREA 1.137600 ;
    PORT
      LAYER met3 ;
        RECT 508.800 318.280 509.400 318.880 ;
    END
  END m1_axi_rresp_0
  PIN m1_axi_rresp_1
    DIRECTION OUTPUT ;
    USE SIGNAL ;
    ANTENNAGATEAREA 0.560700 ;
    ANTENNADIFFAREA 0.863700 ;
    PORT
      LAYER met3 ;
        RECT 508.800 130.600 509.400 131.200 ;
    END
  END m1_axi_rresp_1
  PIN m1_axi_rvalid
    DIRECTION OUTPUT ;
    USE SIGNAL ;
    ANTENNAGATEAREA 0.434700 ;
    ANTENNADIFFAREA 1.137600 ;
    PORT
      LAYER met3 ;
        RECT 508.800 427.080 509.400 427.680 ;
    END
  END m1_axi_rvalid
  PIN m1_axi_wdata_0
    DIRECTION INPUT ;
    USE SIGNAL ;
    PORT
      LAYER met2 ;
        RECT 85.650 0.000 85.930 0.280 ;
    END
  END m1_axi_wdata_0
  PIN m1_axi_wdata_1
    DIRECTION INPUT ;
    USE SIGNAL ;
    PORT
      LAYER met2 ;
        RECT 86.570 0.000 86.850 0.280 ;
    END
  END m1_axi_wdata_1
  PIN m1_axi_wdata_10
    DIRECTION INPUT ;
    USE SIGNAL ;
    PORT
      LAYER met2 ;
        RECT 87.490 0.000 87.770 0.280 ;
    END
  END m1_axi_wdata_10
  PIN m1_axi_wdata_11
    DIRECTION INPUT ;
    USE SIGNAL ;
    PORT
      LAYER met2 ;
        RECT 88.410 0.000 88.690 0.280 ;
    END
  END m1_axi_wdata_11
  PIN m1_axi_wdata_12
    DIRECTION INPUT ;
    USE SIGNAL ;
    PORT
      LAYER met2 ;
        RECT 89.330 0.000 89.610 0.280 ;
    END
  END m1_axi_wdata_12
  PIN m1_axi_wdata_13
    DIRECTION INPUT ;
    USE SIGNAL ;
    PORT
      LAYER met2 ;
        RECT 90.250 0.000 90.530 0.280 ;
    END
  END m1_axi_wdata_13
  PIN m1_axi_wdata_14
    DIRECTION INPUT ;
    USE SIGNAL ;
    PORT
      LAYER met2 ;
        RECT 91.170 0.000 91.450 0.280 ;
    END
  END m1_axi_wdata_14
  PIN m1_axi_wdata_15
    DIRECTION INPUT ;
    USE SIGNAL ;
    PORT
      LAYER met2 ;
        RECT 92.090 0.000 92.370 0.280 ;
    END
  END m1_axi_wdata_15
  PIN m1_axi_wdata_16
    DIRECTION INPUT ;
    USE SIGNAL ;
    PORT
      LAYER met2 ;
        RECT 93.010 0.000 93.290 0.280 ;
    END
  END m1_axi_wdata_16
  PIN m1_axi_wdata_17
    DIRECTION INPUT ;
    USE SIGNAL ;
    PORT
      LAYER met2 ;
        RECT 93.930 0.000 94.210 0.280 ;
    END
  END m1_axi_wdata_17
  PIN m1_axi_wdata_18
    DIRECTION INPUT ;
    USE SIGNAL ;
    PORT
      LAYER met2 ;
        RECT 94.850 0.000 95.130 0.280 ;
    END
  END m1_axi_wdata_18
  PIN m1_axi_wdata_19
    DIRECTION INPUT ;
    USE SIGNAL ;
    PORT
      LAYER met2 ;
        RECT 95.770 0.000 96.050 0.280 ;
    END
  END m1_axi_wdata_19
  PIN m1_axi_wdata_2
    DIRECTION INPUT ;
    USE SIGNAL ;
    PORT
      LAYER met2 ;
        RECT 96.690 0.000 96.970 0.280 ;
    END
  END m1_axi_wdata_2
  PIN m1_axi_wdata_20
    DIRECTION INPUT ;
    USE SIGNAL ;
    PORT
      LAYER met2 ;
        RECT 97.610 0.000 97.890 0.280 ;
    END
  END m1_axi_wdata_20
  PIN m1_axi_wdata_21
    DIRECTION INPUT ;
    USE SIGNAL ;
    PORT
      LAYER met2 ;
        RECT 98.530 0.000 98.810 0.280 ;
    END
  END m1_axi_wdata_21
  PIN m1_axi_wdata_22
    DIRECTION INPUT ;
    USE SIGNAL ;
    PORT
      LAYER met2 ;
        RECT 99.450 0.000 99.730 0.280 ;
    END
  END m1_axi_wdata_22
  PIN m1_axi_wdata_23
    DIRECTION INPUT ;
    USE SIGNAL ;
    PORT
      LAYER met2 ;
        RECT 100.370 0.000 100.650 0.280 ;
    END
  END m1_axi_wdata_23
  PIN m1_axi_wdata_24
    DIRECTION INPUT ;
    USE SIGNAL ;
    PORT
      LAYER met2 ;
        RECT 101.290 0.000 101.570 0.280 ;
    END
  END m1_axi_wdata_24
  PIN m1_axi_wdata_25
    DIRECTION INPUT ;
    USE SIGNAL ;
    PORT
      LAYER met2 ;
        RECT 102.210 0.000 102.490 0.280 ;
    END
  END m1_axi_wdata_25
  PIN m1_axi_wdata_26
    DIRECTION INPUT ;
    USE SIGNAL ;
    PORT
      LAYER met2 ;
        RECT 103.130 0.000 103.410 0.280 ;
    END
  END m1_axi_wdata_26
  PIN m1_axi_wdata_27
    DIRECTION INPUT ;
    USE SIGNAL ;
    PORT
      LAYER met2 ;
        RECT 104.050 0.000 104.330 0.280 ;
    END
  END m1_axi_wdata_27
  PIN m1_axi_wdata_28
    DIRECTION INPUT ;
    USE SIGNAL ;
    PORT
      LAYER met2 ;
        RECT 104.970 0.000 105.250 0.280 ;
    END
  END m1_axi_wdata_28
  PIN m1_axi_wdata_29
    DIRECTION INPUT ;
    USE SIGNAL ;
    PORT
      LAYER met2 ;
        RECT 105.890 0.000 106.170 0.280 ;
    END
  END m1_axi_wdata_29
  PIN m1_axi_wdata_3
    DIRECTION INPUT ;
    USE SIGNAL ;
    PORT
      LAYER met2 ;
        RECT 106.810 0.000 107.090 0.280 ;
    END
  END m1_axi_wdata_3
  PIN m1_axi_wdata_30
    DIRECTION INPUT ;
    USE SIGNAL ;
    PORT
      LAYER met2 ;
        RECT 107.730 0.000 108.010 0.280 ;
    END
  END m1_axi_wdata_30
  PIN m1_axi_wdata_31
    DIRECTION INPUT ;
    USE SIGNAL ;
    PORT
      LAYER met2 ;
        RECT 108.650 0.000 108.930 0.280 ;
    END
  END m1_axi_wdata_31
  PIN m1_axi_wdata_4
    DIRECTION INPUT ;
    USE SIGNAL ;
    PORT
      LAYER met2 ;
        RECT 109.570 0.000 109.850 0.280 ;
    END
  END m1_axi_wdata_4
  PIN m1_axi_wdata_5
    DIRECTION INPUT ;
    USE SIGNAL ;
    PORT
      LAYER met2 ;
        RECT 110.490 0.000 110.770 0.280 ;
    END
  END m1_axi_wdata_5
  PIN m1_axi_wdata_6
    DIRECTION INPUT ;
    USE SIGNAL ;
    PORT
      LAYER met2 ;
        RECT 111.410 0.000 111.690 0.280 ;
    END
  END m1_axi_wdata_6
  PIN m1_axi_wdata_7
    DIRECTION INPUT ;
    USE SIGNAL ;
    PORT
      LAYER met2 ;
        RECT 112.330 0.000 112.610 0.280 ;
    END
  END m1_axi_wdata_7
  PIN m1_axi_wdata_8
    DIRECTION INPUT ;
    USE SIGNAL ;
    PORT
      LAYER met2 ;
        RECT 113.250 0.000 113.530 0.280 ;
    END
  END m1_axi_wdata_8
  PIN m1_axi_wdata_9
    DIRECTION INPUT ;
    USE SIGNAL ;
    PORT
      LAYER met2 ;
        RECT 114.170 0.000 114.450 0.280 ;
    END
  END m1_axi_wdata_9
  PIN m1_axi_wready
    DIRECTION OUTPUT ;
    USE SIGNAL ;
    ANTENNAGATEAREA 0.434700 ;
    ANTENNADIFFAREA 1.137600 ;
    PORT
      LAYER met3 ;
        RECT 0.000 301.960 0.600 302.560 ;
    END
  END m1_axi_wready
  PIN m1_axi_wstrb_0
    DIRECTION INPUT ;
    USE SIGNAL ;
    PORT
      LAYER met2 ;
        RECT 115.090 0.000 115.370 0.280 ;
    END
  END m1_axi_wstrb_0
  PIN m1_axi_wstrb_1
    DIRECTION INPUT ;
    USE SIGNAL ;
    PORT
      LAYER met2 ;
        RECT 116.010 0.000 116.290 0.280 ;
    END
  END m1_axi_wstrb_1
  PIN m1_axi_wstrb_2
    DIRECTION INPUT ;
    USE SIGNAL ;
    PORT
      LAYER met2 ;
        RECT 116.930 0.000 117.210 0.280 ;
    END
  END m1_axi_wstrb_2
  PIN m1_axi_wstrb_3
    DIRECTION INPUT ;
    USE SIGNAL ;
    PORT
      LAYER met2 ;
        RECT 117.850 0.000 118.130 0.280 ;
    END
  END m1_axi_wstrb_3
  PIN m1_axi_wvalid
    DIRECTION INPUT ;
    USE SIGNAL ;
    ANTENNAGATEAREA 0.647700 ;
    ANTENNADIFFAREA 0.434700 ;
    PORT
      LAYER met3 ;
        RECT 0.000 201.320 0.600 201.920 ;
    END
  END m1_axi_wvalid
  PIN m2_axi_araddr_0
    DIRECTION INPUT ;
    USE SIGNAL ;
    PORT
      LAYER met2 ;
        RECT 118.770 0.000 119.050 0.280 ;
    END
  END m2_axi_araddr_0
  PIN m2_axi_araddr_1
    DIRECTION INPUT ;
    USE SIGNAL ;
    PORT
      LAYER met2 ;
        RECT 119.690 0.000 119.970 0.280 ;
    END
  END m2_axi_araddr_1
  PIN m2_axi_araddr_10
    DIRECTION INPUT ;
    USE SIGNAL ;
    PORT
      LAYER met2 ;
        RECT 120.610 0.000 120.890 0.280 ;
    END
  END m2_axi_araddr_10
  PIN m2_axi_araddr_11
    DIRECTION INPUT ;
    USE SIGNAL ;
    PORT
      LAYER met2 ;
        RECT 121.530 0.000 121.810 0.280 ;
    END
  END m2_axi_araddr_11
  PIN m2_axi_araddr_12
    DIRECTION INPUT ;
    USE SIGNAL ;
    PORT
      LAYER met2 ;
        RECT 122.450 0.000 122.730 0.280 ;
    END
  END m2_axi_araddr_12
  PIN m2_axi_araddr_13
    DIRECTION INPUT ;
    USE SIGNAL ;
    PORT
      LAYER met2 ;
        RECT 123.370 0.000 123.650 0.280 ;
    END
  END m2_axi_araddr_13
  PIN m2_axi_araddr_14
    DIRECTION INPUT ;
    USE SIGNAL ;
    PORT
      LAYER met2 ;
        RECT 124.290 0.000 124.570 0.280 ;
    END
  END m2_axi_araddr_14
  PIN m2_axi_araddr_15
    DIRECTION INPUT ;
    USE SIGNAL ;
    PORT
      LAYER met2 ;
        RECT 125.210 0.000 125.490 0.280 ;
    END
  END m2_axi_araddr_15
  PIN m2_axi_araddr_16
    DIRECTION INPUT ;
    USE SIGNAL ;
    PORT
      LAYER met2 ;
        RECT 126.130 0.000 126.410 0.280 ;
    END
  END m2_axi_araddr_16
  PIN m2_axi_araddr_17
    DIRECTION INPUT ;
    USE SIGNAL ;
    PORT
      LAYER met2 ;
        RECT 127.050 0.000 127.330 0.280 ;
    END
  END m2_axi_araddr_17
  PIN m2_axi_araddr_18
    DIRECTION INPUT ;
    USE SIGNAL ;
    PORT
      LAYER met2 ;
        RECT 127.970 0.000 128.250 0.280 ;
    END
  END m2_axi_araddr_18
  PIN m2_axi_araddr_19
    DIRECTION INPUT ;
    USE SIGNAL ;
    PORT
      LAYER met2 ;
        RECT 128.890 0.000 129.170 0.280 ;
    END
  END m2_axi_araddr_19
  PIN m2_axi_araddr_2
    DIRECTION INPUT ;
    USE SIGNAL ;
    PORT
      LAYER met2 ;
        RECT 129.810 0.000 130.090 0.280 ;
    END
  END m2_axi_araddr_2
  PIN m2_axi_araddr_20
    DIRECTION INPUT ;
    USE SIGNAL ;
    PORT
      LAYER met2 ;
        RECT 130.730 0.000 131.010 0.280 ;
    END
  END m2_axi_araddr_20
  PIN m2_axi_araddr_21
    DIRECTION INPUT ;
    USE SIGNAL ;
    PORT
      LAYER met2 ;
        RECT 131.650 0.000 131.930 0.280 ;
    END
  END m2_axi_araddr_21
  PIN m2_axi_araddr_22
    DIRECTION INPUT ;
    USE SIGNAL ;
    PORT
      LAYER met2 ;
        RECT 132.570 0.000 132.850 0.280 ;
    END
  END m2_axi_araddr_22
  PIN m2_axi_araddr_23
    DIRECTION INPUT ;
    USE SIGNAL ;
    PORT
      LAYER met2 ;
        RECT 133.490 0.000 133.770 0.280 ;
    END
  END m2_axi_araddr_23
  PIN m2_axi_araddr_24
    DIRECTION INPUT ;
    USE SIGNAL ;
    PORT
      LAYER met2 ;
        RECT 134.410 0.000 134.690 0.280 ;
    END
  END m2_axi_araddr_24
  PIN m2_axi_araddr_25
    DIRECTION INPUT ;
    USE SIGNAL ;
    PORT
      LAYER met2 ;
        RECT 135.330 0.000 135.610 0.280 ;
    END
  END m2_axi_araddr_25
  PIN m2_axi_araddr_26
    DIRECTION INPUT ;
    USE SIGNAL ;
    PORT
      LAYER met2 ;
        RECT 136.250 0.000 136.530 0.280 ;
    END
  END m2_axi_araddr_26
  PIN m2_axi_araddr_27
    DIRECTION INPUT ;
    USE SIGNAL ;
    PORT
      LAYER met2 ;
        RECT 137.170 0.000 137.450 0.280 ;
    END
  END m2_axi_araddr_27
  PIN m2_axi_araddr_28
    DIRECTION INPUT ;
    USE SIGNAL ;
    PORT
      LAYER met2 ;
        RECT 138.090 0.000 138.370 0.280 ;
    END
  END m2_axi_araddr_28
  PIN m2_axi_araddr_29
    DIRECTION INPUT ;
    USE SIGNAL ;
    PORT
      LAYER met2 ;
        RECT 139.010 0.000 139.290 0.280 ;
    END
  END m2_axi_araddr_29
  PIN m2_axi_araddr_3
    DIRECTION INPUT ;
    USE SIGNAL ;
    PORT
      LAYER met2 ;
        RECT 139.930 0.000 140.210 0.280 ;
    END
  END m2_axi_araddr_3
  PIN m2_axi_araddr_30
    DIRECTION INPUT ;
    USE SIGNAL ;
    PORT
      LAYER met2 ;
        RECT 140.850 0.000 141.130 0.280 ;
    END
  END m2_axi_araddr_30
  PIN m2_axi_araddr_31
    DIRECTION INPUT ;
    USE SIGNAL ;
    PORT
      LAYER met2 ;
        RECT 141.770 0.000 142.050 0.280 ;
    END
  END m2_axi_araddr_31
  PIN m2_axi_araddr_4
    DIRECTION INPUT ;
    USE SIGNAL ;
    PORT
      LAYER met2 ;
        RECT 142.690 0.000 142.970 0.280 ;
    END
  END m2_axi_araddr_4
  PIN m2_axi_araddr_5
    DIRECTION INPUT ;
    USE SIGNAL ;
    PORT
      LAYER met2 ;
        RECT 143.610 0.000 143.890 0.280 ;
    END
  END m2_axi_araddr_5
  PIN m2_axi_araddr_6
    DIRECTION INPUT ;
    USE SIGNAL ;
    PORT
      LAYER met2 ;
        RECT 144.530 0.000 144.810 0.280 ;
    END
  END m2_axi_araddr_6
  PIN m2_axi_araddr_7
    DIRECTION INPUT ;
    USE SIGNAL ;
    PORT
      LAYER met2 ;
        RECT 145.450 0.000 145.730 0.280 ;
    END
  END m2_axi_araddr_7
  PIN m2_axi_araddr_8
    DIRECTION INPUT ;
    USE SIGNAL ;
    PORT
      LAYER met2 ;
        RECT 146.370 0.000 146.650 0.280 ;
    END
  END m2_axi_araddr_8
  PIN m2_axi_araddr_9
    DIRECTION INPUT ;
    USE SIGNAL ;
    PORT
      LAYER met2 ;
        RECT 147.290 0.000 147.570 0.280 ;
    END
  END m2_axi_araddr_9
  PIN m2_axi_arready
    DIRECTION OUTPUT ;
    USE SIGNAL ;
    ANTENNAGATEAREA 0.434700 ;
    ANTENNADIFFAREA 0.775300 ;
    PORT
      LAYER met2 ;
        RECT 248.490 519.840 248.770 520.120 ;
    END
  END m2_axi_arready
  PIN m2_axi_arvalid
    DIRECTION INPUT ;
    USE SIGNAL ;
    ANTENNAGATEAREA 0.647700 ;
    ANTENNADIFFAREA 0.434700 ;
    PORT
      LAYER met2 ;
        RECT 163.850 519.840 164.130 520.120 ;
    END
  END m2_axi_arvalid
  PIN m2_axi_awaddr_0
    DIRECTION INPUT ;
    USE SIGNAL ;
    PORT
      LAYER met2 ;
        RECT 148.210 0.000 148.490 0.280 ;
    END
  END m2_axi_awaddr_0
  PIN m2_axi_awaddr_1
    DIRECTION INPUT ;
    USE SIGNAL ;
    PORT
      LAYER met2 ;
        RECT 149.130 0.000 149.410 0.280 ;
    END
  END m2_axi_awaddr_1
  PIN m2_axi_awaddr_10
    DIRECTION INPUT ;
    USE SIGNAL ;
    PORT
      LAYER met2 ;
        RECT 150.050 0.000 150.330 0.280 ;
    END
  END m2_axi_awaddr_10
  PIN m2_axi_awaddr_11
    DIRECTION INPUT ;
    USE SIGNAL ;
    PORT
      LAYER met2 ;
        RECT 150.970 0.000 151.250 0.280 ;
    END
  END m2_axi_awaddr_11
  PIN m2_axi_awaddr_12
    DIRECTION INPUT ;
    USE SIGNAL ;
    PORT
      LAYER met2 ;
        RECT 151.890 0.000 152.170 0.280 ;
    END
  END m2_axi_awaddr_12
  PIN m2_axi_awaddr_13
    DIRECTION INPUT ;
    USE SIGNAL ;
    PORT
      LAYER met2 ;
        RECT 152.810 0.000 153.090 0.280 ;
    END
  END m2_axi_awaddr_13
  PIN m2_axi_awaddr_14
    DIRECTION INPUT ;
    USE SIGNAL ;
    PORT
      LAYER met2 ;
        RECT 153.730 0.000 154.010 0.280 ;
    END
  END m2_axi_awaddr_14
  PIN m2_axi_awaddr_15
    DIRECTION INPUT ;
    USE SIGNAL ;
    PORT
      LAYER met2 ;
        RECT 154.650 0.000 154.930 0.280 ;
    END
  END m2_axi_awaddr_15
  PIN m2_axi_awaddr_16
    DIRECTION INPUT ;
    USE SIGNAL ;
    PORT
      LAYER met2 ;
        RECT 155.570 0.000 155.850 0.280 ;
    END
  END m2_axi_awaddr_16
  PIN m2_axi_awaddr_17
    DIRECTION INPUT ;
    USE SIGNAL ;
    PORT
      LAYER met2 ;
        RECT 156.490 0.000 156.770 0.280 ;
    END
  END m2_axi_awaddr_17
  PIN m2_axi_awaddr_18
    DIRECTION INPUT ;
    USE SIGNAL ;
    PORT
      LAYER met2 ;
        RECT 157.410 0.000 157.690 0.280 ;
    END
  END m2_axi_awaddr_18
  PIN m2_axi_awaddr_19
    DIRECTION INPUT ;
    USE SIGNAL ;
    PORT
      LAYER met2 ;
        RECT 158.330 0.000 158.610 0.280 ;
    END
  END m2_axi_awaddr_19
  PIN m2_axi_awaddr_2
    DIRECTION INPUT ;
    USE SIGNAL ;
    PORT
      LAYER met2 ;
        RECT 159.250 0.000 159.530 0.280 ;
    END
  END m2_axi_awaddr_2
  PIN m2_axi_awaddr_20
    DIRECTION INPUT ;
    USE SIGNAL ;
    PORT
      LAYER met2 ;
        RECT 160.170 0.000 160.450 0.280 ;
    END
  END m2_axi_awaddr_20
  PIN m2_axi_awaddr_21
    DIRECTION INPUT ;
    USE SIGNAL ;
    PORT
      LAYER met2 ;
        RECT 161.090 0.000 161.370 0.280 ;
    END
  END m2_axi_awaddr_21
  PIN m2_axi_awaddr_22
    DIRECTION INPUT ;
    USE SIGNAL ;
    PORT
      LAYER met2 ;
        RECT 162.010 0.000 162.290 0.280 ;
    END
  END m2_axi_awaddr_22
  PIN m2_axi_awaddr_23
    DIRECTION INPUT ;
    USE SIGNAL ;
    PORT
      LAYER met2 ;
        RECT 162.930 0.000 163.210 0.280 ;
    END
  END m2_axi_awaddr_23
  PIN m2_axi_awaddr_24
    DIRECTION INPUT ;
    USE SIGNAL ;
    PORT
      LAYER met2 ;
        RECT 163.850 0.000 164.130 0.280 ;
    END
  END m2_axi_awaddr_24
  PIN m2_axi_awaddr_25
    DIRECTION INPUT ;
    USE SIGNAL ;
    PORT
      LAYER met2 ;
        RECT 164.770 0.000 165.050 0.280 ;
    END
  END m2_axi_awaddr_25
  PIN m2_axi_awaddr_26
    DIRECTION INPUT ;
    USE SIGNAL ;
    PORT
      LAYER met2 ;
        RECT 165.690 0.000 165.970 0.280 ;
    END
  END m2_axi_awaddr_26
  PIN m2_axi_awaddr_27
    DIRECTION INPUT ;
    USE SIGNAL ;
    PORT
      LAYER met2 ;
        RECT 166.610 0.000 166.890 0.280 ;
    END
  END m2_axi_awaddr_27
  PIN m2_axi_awaddr_28
    DIRECTION INPUT ;
    USE SIGNAL ;
    PORT
      LAYER met2 ;
        RECT 167.530 0.000 167.810 0.280 ;
    END
  END m2_axi_awaddr_28
  PIN m2_axi_awaddr_29
    DIRECTION INPUT ;
    USE SIGNAL ;
    PORT
      LAYER met2 ;
        RECT 168.450 0.000 168.730 0.280 ;
    END
  END m2_axi_awaddr_29
  PIN m2_axi_awaddr_3
    DIRECTION INPUT ;
    USE SIGNAL ;
    PORT
      LAYER met2 ;
        RECT 169.370 0.000 169.650 0.280 ;
    END
  END m2_axi_awaddr_3
  PIN m2_axi_awaddr_30
    DIRECTION INPUT ;
    USE SIGNAL ;
    PORT
      LAYER met2 ;
        RECT 170.290 0.000 170.570 0.280 ;
    END
  END m2_axi_awaddr_30
  PIN m2_axi_awaddr_31
    DIRECTION INPUT ;
    USE SIGNAL ;
    PORT
      LAYER met2 ;
        RECT 171.210 0.000 171.490 0.280 ;
    END
  END m2_axi_awaddr_31
  PIN m2_axi_awaddr_4
    DIRECTION INPUT ;
    USE SIGNAL ;
    PORT
      LAYER met2 ;
        RECT 172.130 0.000 172.410 0.280 ;
    END
  END m2_axi_awaddr_4
  PIN m2_axi_awaddr_5
    DIRECTION INPUT ;
    USE SIGNAL ;
    PORT
      LAYER met2 ;
        RECT 173.050 0.000 173.330 0.280 ;
    END
  END m2_axi_awaddr_5
  PIN m2_axi_awaddr_6
    DIRECTION INPUT ;
    USE SIGNAL ;
    PORT
      LAYER met2 ;
        RECT 173.970 0.000 174.250 0.280 ;
    END
  END m2_axi_awaddr_6
  PIN m2_axi_awaddr_7
    DIRECTION INPUT ;
    USE SIGNAL ;
    PORT
      LAYER met2 ;
        RECT 174.890 0.000 175.170 0.280 ;
    END
  END m2_axi_awaddr_7
  PIN m2_axi_awaddr_8
    DIRECTION INPUT ;
    USE SIGNAL ;
    PORT
      LAYER met2 ;
        RECT 175.810 0.000 176.090 0.280 ;
    END
  END m2_axi_awaddr_8
  PIN m2_axi_awaddr_9
    DIRECTION INPUT ;
    USE SIGNAL ;
    PORT
      LAYER met2 ;
        RECT 176.730 0.000 177.010 0.280 ;
    END
  END m2_axi_awaddr_9
  PIN m2_axi_awready
    DIRECTION OUTPUT ;
    USE SIGNAL ;
    ANTENNAGATEAREA 0.434700 ;
    ANTENNADIFFAREA 1.137600 ;
    PORT
      LAYER met3 ;
        RECT 0.000 323.720 0.600 324.320 ;
    END
  END m2_axi_awready
  PIN m2_axi_awvalid
    DIRECTION INPUT ;
    USE SIGNAL ;
    ANTENNAGATEAREA 0.647700 ;
    ANTENNADIFFAREA 0.434700 ;
    PORT
      LAYER met3 ;
        RECT 0.000 204.040 0.600 204.640 ;
    END
  END m2_axi_awvalid
  PIN m2_axi_bready
    DIRECTION INPUT ;
    USE SIGNAL ;
    PORT
      LAYER met2 ;
        RECT 177.650 0.000 177.930 0.280 ;
    END
  END m2_axi_bready
  PIN m2_axi_bresp_0
    DIRECTION OUTPUT ;
    USE SIGNAL ;
    ANTENNAGATEAREA 0.434700 ;
    ANTENNADIFFAREA 1.137600 ;
    PORT
      LAYER met3 ;
        RECT 0.000 288.360 0.600 288.960 ;
    END
  END m2_axi_bresp_0
  PIN m2_axi_bresp_1
    DIRECTION OUTPUT ;
    USE SIGNAL ;
    ANTENNAGATEAREA 0.434700 ;
    ANTENNADIFFAREA 1.137600 ;
    PORT
      LAYER met3 ;
        RECT 0.000 285.640 0.600 286.240 ;
    END
  END m2_axi_bresp_1
  PIN m2_axi_bvalid
    DIRECTION OUTPUT ;
    USE SIGNAL ;
    ANTENNAGATEAREA 0.434700 ;
    ANTENNADIFFAREA 1.137600 ;
    PORT
      LAYER met3 ;
        RECT 0.000 322.360 0.600 322.960 ;
    END
  END m2_axi_bvalid
  PIN m2_axi_rdata_0
    DIRECTION OUTPUT ;
    USE SIGNAL ;
    PORT
      LAYER met2 ;
        RECT 178.570 0.000 178.850 0.280 ;
    END
  END m2_axi_rdata_0
  PIN m2_axi_rdata_1
    DIRECTION OUTPUT ;
    USE SIGNAL ;
    PORT
      LAYER met2 ;
        RECT 179.490 0.000 179.770 0.280 ;
    END
  END m2_axi_rdata_1
  PIN m2_axi_rdata_10
    DIRECTION OUTPUT ;
    USE SIGNAL ;
    PORT
      LAYER met2 ;
        RECT 180.410 0.000 180.690 0.280 ;
    END
  END m2_axi_rdata_10
  PIN m2_axi_rdata_11
    DIRECTION OUTPUT ;
    USE SIGNAL ;
    PORT
      LAYER met2 ;
        RECT 181.330 0.000 181.610 0.280 ;
    END
  END m2_axi_rdata_11
  PIN m2_axi_rdata_12
    DIRECTION OUTPUT ;
    USE SIGNAL ;
    PORT
      LAYER met2 ;
        RECT 182.250 0.000 182.530 0.280 ;
    END
  END m2_axi_rdata_12
  PIN m2_axi_rdata_13
    DIRECTION OUTPUT ;
    USE SIGNAL ;
    PORT
      LAYER met2 ;
        RECT 183.170 0.000 183.450 0.280 ;
    END
  END m2_axi_rdata_13
  PIN m2_axi_rdata_14
    DIRECTION OUTPUT ;
    USE SIGNAL ;
    ANTENNAGATEAREA 0.434700 ;
    ANTENNADIFFAREA 0.775300 ;
    PORT
      LAYER met2 ;
        RECT 242.970 519.840 243.250 520.120 ;
    END
  END m2_axi_rdata_14
  PIN m2_axi_rdata_15
    DIRECTION OUTPUT ;
    USE SIGNAL ;
    PORT
      LAYER met2 ;
        RECT 184.090 0.000 184.370 0.280 ;
    END
  END m2_axi_rdata_15
  PIN m2_axi_rdata_16
    DIRECTION OUTPUT ;
    USE SIGNAL ;
    PORT
      LAYER met2 ;
        RECT 185.010 0.000 185.290 0.280 ;
    END
  END m2_axi_rdata_16
  PIN m2_axi_rdata_17
    DIRECTION OUTPUT ;
    USE SIGNAL ;
    ANTENNAGATEAREA 0.434700 ;
    ANTENNADIFFAREA 0.775300 ;
    PORT
      LAYER met2 ;
        RECT 241.130 519.840 241.410 520.120 ;
    END
  END m2_axi_rdata_17
  PIN m2_axi_rdata_18
    DIRECTION OUTPUT ;
    USE SIGNAL ;
    PORT
      LAYER met2 ;
        RECT 269.650 0.000 269.930 0.280 ;
    END
  END m2_axi_rdata_18
  PIN m2_axi_rdata_19
    DIRECTION OUTPUT ;
    USE SIGNAL ;
    PORT
      LAYER met2 ;
        RECT 350.610 0.000 350.890 0.280 ;
    END
  END m2_axi_rdata_19
  PIN m2_axi_rdata_2
    DIRECTION OUTPUT ;
    USE SIGNAL ;
    PORT
      LAYER met2 ;
        RECT 357.970 0.000 358.250 0.280 ;
    END
  END m2_axi_rdata_2
  PIN m2_axi_rdata_20
    DIRECTION OUTPUT ;
    USE SIGNAL ;
    ANTENNAGATEAREA 0.434700 ;
    ANTENNADIFFAREA 0.775300 ;
    PORT
      LAYER met2 ;
        RECT 244.810 519.840 245.090 520.120 ;
    END
  END m2_axi_rdata_20
  PIN m2_axi_rdata_21
    DIRECTION OUTPUT ;
    USE SIGNAL ;
    PORT
      LAYER met2 ;
        RECT 314.730 0.000 315.010 0.280 ;
    END
  END m2_axi_rdata_21
  PIN m2_axi_rdata_22
    DIRECTION OUTPUT ;
    USE SIGNAL ;
    ANTENNAGATEAREA 0.434700 ;
    ANTENNADIFFAREA 0.775300 ;
    PORT
      LAYER met2 ;
        RECT 254.010 519.840 254.290 520.120 ;
    END
  END m2_axi_rdata_22
  PIN m2_axi_rdata_23
    DIRECTION OUTPUT ;
    USE SIGNAL ;
    PORT
      LAYER met2 ;
        RECT 267.810 0.000 268.090 0.280 ;
    END
  END m2_axi_rdata_23
  PIN m2_axi_rdata_24
    DIRECTION OUTPUT ;
    USE SIGNAL ;
    ANTENNAGATEAREA 0.434700 ;
    ANTENNADIFFAREA 0.775300 ;
    PORT
      LAYER met2 ;
        RECT 250.330 519.840 250.610 520.120 ;
    END
  END m2_axi_rdata_24
  PIN m2_axi_rdata_25
    DIRECTION OUTPUT ;
    USE SIGNAL ;
    PORT
      LAYER met2 ;
        RECT 247.570 0.000 247.850 0.280 ;
    END
  END m2_axi_rdata_25
  PIN m2_axi_rdata_26
    DIRECTION OUTPUT ;
    USE SIGNAL ;
    PORT
      LAYER met2 ;
        RECT 258.610 0.000 258.890 0.280 ;
    END
  END m2_axi_rdata_26
  PIN m2_axi_rdata_27
    DIRECTION OUTPUT ;
    USE SIGNAL ;
    PORT
      LAYER met2 ;
        RECT 268.730 0.000 269.010 0.280 ;
    END
  END m2_axi_rdata_27
  PIN m2_axi_rdata_28
    DIRECTION OUTPUT ;
    USE SIGNAL ;
    PORT
      LAYER met2 ;
        RECT 259.530 0.000 259.810 0.280 ;
    END
  END m2_axi_rdata_28
  PIN m2_axi_rdata_29
    DIRECTION OUTPUT ;
    USE SIGNAL ;
    ANTENNAGATEAREA 0.434700 ;
    ANTENNADIFFAREA 0.775300 ;
    PORT
      LAYER met3 ;
        RECT 508.800 458.360 509.400 458.960 ;
    END
  END m2_axi_rdata_29
  PIN m2_axi_rdata_3
    DIRECTION OUTPUT ;
    USE SIGNAL ;
    PORT
      LAYER met2 ;
        RECT 334.970 0.000 335.250 0.280 ;
    END
  END m2_axi_rdata_3
  PIN m2_axi_rdata_30
    DIRECTION OUTPUT ;
    USE SIGNAL ;
    PORT
      LAYER met2 ;
        RECT 356.130 0.000 356.410 0.280 ;
    END
  END m2_axi_rdata_30
  PIN m2_axi_rdata_31
    DIRECTION OUTPUT ;
    USE SIGNAL ;
    PORT
      LAYER met2 ;
        RECT 332.210 0.000 332.490 0.280 ;
    END
  END m2_axi_rdata_31
  PIN m2_axi_rdata_4
    DIRECTION OUTPUT ;
    USE SIGNAL ;
    ANTENNAGATEAREA 0.434700 ;
    ANTENNADIFFAREA 0.775300 ;
    PORT
      LAYER met2 ;
        RECT 251.250 519.840 251.530 520.120 ;
    END
  END m2_axi_rdata_4
  PIN m2_axi_rdata_5
    DIRECTION OUTPUT ;
    USE SIGNAL ;
    PORT
      LAYER met2 ;
        RECT 366.250 0.000 366.530 0.280 ;
    END
  END m2_axi_rdata_5
  PIN m2_axi_rdata_6
    DIRECTION OUTPUT ;
    USE SIGNAL ;
    PORT
      LAYER met2 ;
        RECT 346.930 0.000 347.210 0.280 ;
    END
  END m2_axi_rdata_6
  PIN m2_axi_rdata_7
    DIRECTION OUTPUT ;
    USE SIGNAL ;
    PORT
      LAYER met2 ;
        RECT 349.690 0.000 349.970 0.280 ;
    END
  END m2_axi_rdata_7
  PIN m2_axi_rdata_8
    DIRECTION OUTPUT ;
    USE SIGNAL ;
    ANTENNAGATEAREA 0.434700 ;
    ANTENNADIFFAREA 0.775300 ;
    PORT
      LAYER met2 ;
        RECT 253.090 519.840 253.370 520.120 ;
    END
  END m2_axi_rdata_8
  PIN m2_axi_rdata_9
    DIRECTION OUTPUT ;
    USE SIGNAL ;
    PORT
      LAYER met2 ;
        RECT 334.050 0.000 334.330 0.280 ;
    END
  END m2_axi_rdata_9
  PIN m2_axi_rready
    DIRECTION INPUT ;
    USE SIGNAL ;
    ANTENNAGATEAREA 0.647700 ;
    ANTENNADIFFAREA 0.434700 ;
    PORT
      LAYER met2 ;
        RECT 226.410 0.000 226.690 0.280 ;
    END
  END m2_axi_rready
  PIN m2_axi_rresp_0
    DIRECTION OUTPUT ;
    USE SIGNAL ;
    PORT
      LAYER met2 ;
        RECT 325.770 0.000 326.050 0.280 ;
    END
  END m2_axi_rresp_0
  PIN m2_axi_rresp_1
    DIRECTION OUTPUT ;
    USE SIGNAL ;
    PORT
      LAYER met2 ;
        RECT 333.130 0.000 333.410 0.280 ;
    END
  END m2_axi_rresp_1
  PIN m2_axi_rvalid
    DIRECTION OUTPUT ;
    USE SIGNAL ;
    ANTENNAGATEAREA 0.434700 ;
    ANTENNADIFFAREA 1.137600 ;
    PORT
      LAYER met2 ;
        RECT 248.490 0.000 248.770 0.280 ;
    END
  END m2_axi_rvalid
  PIN m2_axi_wdata_0
    DIRECTION INPUT ;
    USE SIGNAL ;
    PORT
      LAYER met2 ;
        RECT 300.930 0.000 301.210 0.280 ;
    END
  END m2_axi_wdata_0
  PIN m2_axi_wdata_1
    DIRECTION INPUT ;
    USE SIGNAL ;
    PORT
      LAYER met2 ;
        RECT 257.690 0.000 257.970 0.280 ;
    END
  END m2_axi_wdata_1
  PIN m2_axi_wdata_10
    DIRECTION INPUT ;
    USE SIGNAL ;
    PORT
      LAYER met2 ;
        RECT 364.410 0.000 364.690 0.280 ;
    END
  END m2_axi_wdata_10
  PIN m2_axi_wdata_11
    DIRECTION INPUT ;
    USE SIGNAL ;
    PORT
      LAYER met2 ;
        RECT 263.210 0.000 263.490 0.280 ;
    END
  END m2_axi_wdata_11
  PIN m2_axi_wdata_12
    DIRECTION INPUT ;
    USE SIGNAL ;
    PORT
      LAYER met2 ;
        RECT 301.850 0.000 302.130 0.280 ;
    END
  END m2_axi_wdata_12
  PIN m2_axi_wdata_13
    DIRECTION INPUT ;
    USE SIGNAL ;
    PORT
      LAYER met2 ;
        RECT 359.810 0.000 360.090 0.280 ;
    END
  END m2_axi_wdata_13
  PIN m2_axi_wdata_14
    DIRECTION INPUT ;
    USE SIGNAL ;
    PORT
      LAYER met2 ;
        RECT 363.490 0.000 363.770 0.280 ;
    END
  END m2_axi_wdata_14
  PIN m2_axi_wdata_15
    DIRECTION INPUT ;
    USE SIGNAL ;
    PORT
      LAYER met2 ;
        RECT 264.130 0.000 264.410 0.280 ;
    END
  END m2_axi_wdata_15
  PIN m2_axi_wdata_16
    DIRECTION INPUT ;
    USE SIGNAL ;
    PORT
      LAYER met2 ;
        RECT 358.890 0.000 359.170 0.280 ;
    END
  END m2_axi_wdata_16
  PIN m2_axi_wdata_17
    DIRECTION INPUT ;
    USE SIGNAL ;
    PORT
      LAYER met2 ;
        RECT 345.090 0.000 345.370 0.280 ;
    END
  END m2_axi_wdata_17
  PIN m2_axi_wdata_18
    DIRECTION INPUT ;
    USE SIGNAL ;
    PORT
      LAYER met2 ;
        RECT 331.290 0.000 331.570 0.280 ;
    END
  END m2_axi_wdata_18
  PIN m2_axi_wdata_19
    DIRECTION INPUT ;
    USE SIGNAL ;
    PORT
      LAYER met2 ;
        RECT 323.930 0.000 324.210 0.280 ;
    END
  END m2_axi_wdata_19
  PIN m2_axi_wdata_2
    DIRECTION INPUT ;
    USE SIGNAL ;
    PORT
      LAYER met2 ;
        RECT 343.250 0.000 343.530 0.280 ;
    END
  END m2_axi_wdata_2
  PIN m2_axi_wdata_20
    DIRECTION INPUT ;
    USE SIGNAL ;
    PORT
      LAYER met2 ;
        RECT 246.650 0.000 246.930 0.280 ;
    END
  END m2_axi_wdata_20
  PIN m2_axi_wdata_21
    DIRECTION INPUT ;
    USE SIGNAL ;
    PORT
      LAYER met2 ;
        RECT 362.570 0.000 362.850 0.280 ;
    END
  END m2_axi_wdata_21
  PIN m2_axi_wdata_22
    DIRECTION INPUT ;
    USE SIGNAL ;
    PORT
      LAYER met2 ;
        RECT 344.170 0.000 344.450 0.280 ;
    END
  END m2_axi_wdata_22
  PIN m2_axi_wdata_23
    DIRECTION INPUT ;
    USE SIGNAL ;
    PORT
      LAYER met2 ;
        RECT 369.010 0.000 369.290 0.280 ;
    END
  END m2_axi_wdata_23
  PIN m2_axi_wdata_24
    DIRECTION INPUT ;
    USE SIGNAL ;
    PORT
      LAYER met2 ;
        RECT 338.650 0.000 338.930 0.280 ;
    END
  END m2_axi_wdata_24
  PIN m2_axi_wdata_25
    DIRECTION INPUT ;
    USE SIGNAL ;
    PORT
      LAYER met2 ;
        RECT 360.730 0.000 361.010 0.280 ;
    END
  END m2_axi_wdata_25
  PIN m2_axi_wdata_26
    DIRECTION INPUT ;
    USE SIGNAL ;
    PORT
      LAYER met2 ;
        RECT 367.170 0.000 367.450 0.280 ;
    END
  END m2_axi_wdata_26
  PIN m2_axi_wdata_27
    DIRECTION INPUT ;
    USE SIGNAL ;
    PORT
      LAYER met2 ;
        RECT 256.770 0.000 257.050 0.280 ;
    END
  END m2_axi_wdata_27
  PIN m2_axi_wdata_28
    DIRECTION INPUT ;
    USE SIGNAL ;
    PORT
      LAYER met2 ;
        RECT 321.170 0.000 321.450 0.280 ;
    END
  END m2_axi_wdata_28
  PIN m2_axi_wdata_29
    DIRECTION INPUT ;
    USE SIGNAL ;
    PORT
      LAYER met2 ;
        RECT 361.650 0.000 361.930 0.280 ;
    END
  END m2_axi_wdata_29
  PIN m2_axi_wdata_3
    DIRECTION INPUT ;
    USE SIGNAL ;
    PORT
      LAYER met2 ;
        RECT 365.330 0.000 365.610 0.280 ;
    END
  END m2_axi_wdata_3
  PIN m2_axi_wdata_30
    DIRECTION INPUT ;
    USE SIGNAL ;
    PORT
      LAYER met2 ;
        RECT 323.010 0.000 323.290 0.280 ;
    END
  END m2_axi_wdata_30
  PIN m2_axi_wdata_31
    DIRECTION INPUT ;
    USE SIGNAL ;
    PORT
      LAYER met2 ;
        RECT 355.210 0.000 355.490 0.280 ;
    END
  END m2_axi_wdata_31
  PIN m2_axi_wdata_4
    DIRECTION INPUT ;
    USE SIGNAL ;
    PORT
      LAYER met2 ;
        RECT 357.050 0.000 357.330 0.280 ;
    END
  END m2_axi_wdata_4
  PIN m2_axi_wdata_5
    DIRECTION INPUT ;
    USE SIGNAL ;
    PORT
      LAYER met2 ;
        RECT 274.250 0.000 274.530 0.280 ;
    END
  END m2_axi_wdata_5
  PIN m2_axi_wdata_6
    DIRECTION INPUT ;
    USE SIGNAL ;
    PORT
      LAYER met2 ;
        RECT 322.090 0.000 322.370 0.280 ;
    END
  END m2_axi_wdata_6
  PIN m2_axi_wdata_7
    DIRECTION INPUT ;
    USE SIGNAL ;
    PORT
      LAYER met2 ;
        RECT 320.250 0.000 320.530 0.280 ;
    END
  END m2_axi_wdata_7
  PIN m2_axi_wdata_8
    DIRECTION INPUT ;
    USE SIGNAL ;
    PORT
      LAYER met2 ;
        RECT 346.010 0.000 346.290 0.280 ;
    END
  END m2_axi_wdata_8
  PIN m2_axi_wdata_9
    DIRECTION INPUT ;
    USE SIGNAL ;
    PORT
      LAYER met2 ;
        RECT 347.850 0.000 348.130 0.280 ;
    END
  END m2_axi_wdata_9
  PIN m2_axi_wready
    DIRECTION OUTPUT ;
    USE SIGNAL ;
    ANTENNAGATEAREA 0.434700 ;
    ANTENNADIFFAREA 1.137600 ;
    PORT
      LAYER met3 ;
        RECT 0.000 300.600 0.600 301.200 ;
    END
  END m2_axi_wready
  PIN m2_axi_wstrb_0
    DIRECTION INPUT ;
    USE SIGNAL ;
    PORT
      LAYER met2 ;
        RECT 348.770 0.000 349.050 0.280 ;
    END
  END m2_axi_wstrb_0
  PIN m2_axi_wstrb_1
    DIRECTION INPUT ;
    USE SIGNAL ;
    PORT
      LAYER met2 ;
        RECT 315.650 0.000 315.930 0.280 ;
    END
  END m2_axi_wstrb_1
  PIN m2_axi_wstrb_2
    DIRECTION INPUT ;
    USE SIGNAL ;
    PORT
      LAYER met2 ;
        RECT 313.810 0.000 314.090 0.280 ;
    END
  END m2_axi_wstrb_2
  PIN m2_axi_wstrb_3
    DIRECTION INPUT ;
    USE SIGNAL ;
    PORT
      LAYER met2 ;
        RECT 368.090 0.000 368.370 0.280 ;
    END
  END m2_axi_wstrb_3
  PIN m2_axi_wvalid
    DIRECTION INPUT ;
    USE SIGNAL ;
    ANTENNAGATEAREA 0.647700 ;
    ANTENNADIFFAREA 0.434700 ;
    PORT
      LAYER met3 ;
        RECT 0.000 199.960 0.600 200.560 ;
    END
  END m2_axi_wvalid
  PIN rst_n
    DIRECTION INPUT ;
    USE SIGNAL ;
    ANTENNAGATEAREA 0.647700 ;
    ANTENNADIFFAREA 0.434700 ;
    PORT
      LAYER met3 ;
        RECT 0.000 243.480 0.600 244.080 ;
    END
  END rst_n
  PIN s0_axi_araddr_0
    DIRECTION OUTPUT ;
    USE SIGNAL ;
    ANTENNAGATEAREA 0.434700 ;
    ANTENNADIFFAREA 1.137600 ;
    PORT
      LAYER met2 ;
        RECT 351.530 0.000 351.810 0.280 ;
    END
  END s0_axi_araddr_0
  PIN s0_axi_araddr_1
    DIRECTION OUTPUT ;
    USE SIGNAL ;
    ANTENNAGATEAREA 0.434700 ;
    ANTENNADIFFAREA 1.137600 ;
    PORT
      LAYER met2 ;
        RECT 402.130 519.840 402.410 520.120 ;
    END
  END s0_axi_araddr_1
  PIN s0_axi_araddr_10
    DIRECTION OUTPUT ;
    USE SIGNAL ;
    ANTENNAGATEAREA 0.434700 ;
    ANTENNADIFFAREA 1.137600 ;
    PORT
      LAYER met2 ;
        RECT 196.050 519.840 196.330 520.120 ;
    END
  END s0_axi_araddr_10
  PIN s0_axi_araddr_11
    DIRECTION OUTPUT ;
    USE SIGNAL ;
    ANTENNAGATEAREA 0.434700 ;
    ANTENNADIFFAREA 1.137600 ;
    PORT
      LAYER met2 ;
        RECT 321.170 519.840 321.450 520.120 ;
    END
  END s0_axi_araddr_11
  PIN s0_axi_araddr_12
    DIRECTION OUTPUT ;
    USE SIGNAL ;
    ANTENNAGATEAREA 0.434700 ;
    ANTENNADIFFAREA 1.137600 ;
    PORT
      LAYER met2 ;
        RECT 73.690 519.840 73.970 520.120 ;
    END
  END s0_axi_araddr_12
  PIN s0_axi_araddr_13
    DIRECTION OUTPUT ;
    USE SIGNAL ;
    ANTENNAGATEAREA 0.434700 ;
    ANTENNADIFFAREA 1.137600 ;
    PORT
      LAYER met2 ;
        RECT 297.250 0.000 297.530 0.280 ;
    END
  END s0_axi_araddr_13
  PIN s0_axi_araddr_14
    DIRECTION OUTPUT ;
    USE SIGNAL ;
    ANTENNAGATEAREA 0.434700 ;
    ANTENNADIFFAREA 1.137600 ;
    PORT
      LAYER met2 ;
        RECT 227.330 0.000 227.610 0.280 ;
    END
  END s0_axi_araddr_14
  PIN s0_axi_araddr_15
    DIRECTION OUTPUT ;
    USE SIGNAL ;
    ANTENNAGATEAREA 0.434700 ;
    ANTENNADIFFAREA 1.137600 ;
    PORT
      LAYER met2 ;
        RECT 101.290 519.840 101.570 520.120 ;
    END
  END s0_axi_araddr_15
  PIN s0_axi_araddr_16
    DIRECTION OUTPUT ;
    USE SIGNAL ;
    ANTENNAGATEAREA 0.434700 ;
    ANTENNADIFFAREA 1.137600 ;
    PORT
      LAYER met2 ;
        RECT 141.770 519.840 142.050 520.120 ;
    END
  END s0_axi_araddr_16
  PIN s0_axi_araddr_17
    DIRECTION OUTPUT ;
    USE SIGNAL ;
    ANTENNAGATEAREA 0.434700 ;
    ANTENNADIFFAREA 1.137600 ;
    PORT
      LAYER met2 ;
        RECT 498.730 0.000 499.010 0.280 ;
    END
  END s0_axi_araddr_17
  PIN s0_axi_araddr_18
    DIRECTION OUTPUT ;
    USE SIGNAL ;
    ANTENNAGATEAREA 0.434700 ;
    ANTENNADIFFAREA 1.137600 ;
    PORT
      LAYER met2 ;
        RECT 245.730 0.000 246.010 0.280 ;
    END
  END s0_axi_araddr_18
  PIN s0_axi_araddr_19
    DIRECTION OUTPUT ;
    USE SIGNAL ;
    ANTENNAGATEAREA 0.434700 ;
    ANTENNADIFFAREA 1.137600 ;
    PORT
      LAYER met3 ;
        RECT 0.000 15.000 0.600 15.600 ;
    END
  END s0_axi_araddr_19
  PIN s0_axi_araddr_2
    DIRECTION OUTPUT ;
    USE SIGNAL ;
    ANTENNAGATEAREA 0.434700 ;
    ANTENNADIFFAREA 1.137600 ;
    PORT
      LAYER met2 ;
        RECT 222.730 0.000 223.010 0.280 ;
    END
  END s0_axi_araddr_2
  PIN s0_axi_araddr_20
    DIRECTION OUTPUT ;
    USE SIGNAL ;
    ANTENNAGATEAREA 0.434700 ;
    ANTENNADIFFAREA 1.137600 ;
    PORT
      LAYER met3 ;
        RECT 0.000 403.960 0.600 404.560 ;
    END
  END s0_axi_araddr_20
  PIN s0_axi_araddr_21
    DIRECTION OUTPUT ;
    USE SIGNAL ;
    ANTENNAGATEAREA 0.434700 ;
    ANTENNADIFFAREA 1.137600 ;
    PORT
      LAYER met2 ;
        RECT 185.930 519.840 186.210 520.120 ;
    END
  END s0_axi_araddr_21
  PIN s0_axi_araddr_22
    DIRECTION OUTPUT ;
    USE SIGNAL ;
    ANTENNAGATEAREA 0.434700 ;
    ANTENNADIFFAREA 1.137600 ;
    PORT
      LAYER met2 ;
        RECT 324.850 519.840 325.130 520.120 ;
    END
  END s0_axi_araddr_22
  PIN s0_axi_araddr_23
    DIRECTION OUTPUT ;
    USE SIGNAL ;
    ANTENNAGATEAREA 0.434700 ;
    ANTENNADIFFAREA 1.137600 ;
    PORT
      LAYER met2 ;
        RECT 250.330 0.000 250.610 0.280 ;
    END
  END s0_axi_araddr_23
  PIN s0_axi_araddr_24
    DIRECTION OUTPUT ;
    USE SIGNAL ;
    ANTENNAGATEAREA 0.434700 ;
    ANTENNADIFFAREA 1.137600 ;
    PORT
      LAYER met2 ;
        RECT 139.930 519.840 140.210 520.120 ;
    END
  END s0_axi_araddr_24
  PIN s0_axi_araddr_25
    DIRECTION OUTPUT ;
    USE SIGNAL ;
    ANTENNAGATEAREA 0.434700 ;
    ANTENNADIFFAREA 1.137600 ;
    PORT
      LAYER met2 ;
        RECT 44.250 519.840 44.530 520.120 ;
    END
  END s0_axi_araddr_25
  PIN s0_axi_araddr_26
    DIRECTION OUTPUT ;
    USE SIGNAL ;
    ANTENNAGATEAREA 0.434700 ;
    ANTENNADIFFAREA 1.137600 ;
    PORT
      LAYER met2 ;
        RECT 211.690 0.000 211.970 0.280 ;
    END
  END s0_axi_araddr_26
  PIN s0_axi_araddr_27
    DIRECTION OUTPUT ;
    USE SIGNAL ;
    ANTENNAGATEAREA 0.434700 ;
    ANTENNADIFFAREA 1.137600 ;
    PORT
      LAYER met2 ;
        RECT 386.490 519.840 386.770 520.120 ;
    END
  END s0_axi_araddr_27
  PIN s0_axi_araddr_28
    DIRECTION OUTPUT ;
    USE SIGNAL ;
    ANTENNAGATEAREA 0.434700 ;
    ANTENNADIFFAREA 1.137600 ;
    PORT
      LAYER met2 ;
        RECT 185.930 0.000 186.210 0.280 ;
    END
  END s0_axi_araddr_28
  PIN s0_axi_araddr_29
    DIRECTION OUTPUT ;
    USE SIGNAL ;
    ANTENNAGATEAREA 0.434700 ;
    ANTENNADIFFAREA 1.137600 ;
    PORT
      LAYER met2 ;
        RECT 90.250 519.840 90.530 520.120 ;
    END
  END s0_axi_araddr_29
  PIN s0_axi_araddr_3
    DIRECTION OUTPUT ;
    USE SIGNAL ;
    ANTENNAGATEAREA 0.434700 ;
    ANTENNADIFFAREA 1.137600 ;
    PORT
      LAYER met2 ;
        RECT 203.410 0.000 203.690 0.280 ;
    END
  END s0_axi_araddr_3
  PIN s0_axi_araddr_30
    DIRECTION OUTPUT ;
    USE SIGNAL ;
    ANTENNAGATEAREA 0.434700 ;
    ANTENNADIFFAREA 1.137600 ;
    PORT
      LAYER met2 ;
        RECT 66.330 519.840 66.610 520.120 ;
    END
  END s0_axi_araddr_30
  PIN s0_axi_araddr_31
    DIRECTION OUTPUT ;
    USE SIGNAL ;
    ANTENNAGATEAREA 0.434700 ;
    ANTENNADIFFAREA 1.137600 ;
    PORT
      LAYER met2 ;
        RECT 151.890 519.840 152.170 520.120 ;
    END
  END s0_axi_araddr_31
  PIN s0_axi_araddr_4
    DIRECTION OUTPUT ;
    USE SIGNAL ;
    ANTENNAGATEAREA 0.434700 ;
    ANTENNADIFFAREA 1.137600 ;
    PORT
      LAYER met2 ;
        RECT 310.130 519.840 310.410 520.120 ;
    END
  END s0_axi_araddr_4
  PIN s0_axi_araddr_5
    DIRECTION OUTPUT ;
    USE SIGNAL ;
    ANTENNAGATEAREA 0.434700 ;
    ANTENNADIFFAREA 1.137600 ;
    PORT
      LAYER met2 ;
        RECT 378.210 519.840 378.490 520.120 ;
    END
  END s0_axi_araddr_5
  PIN s0_axi_araddr_6
    DIRECTION OUTPUT ;
    USE SIGNAL ;
    ANTENNAGATEAREA 0.434700 ;
    ANTENNADIFFAREA 1.137600 ;
    PORT
      LAYER met2 ;
        RECT 306.450 0.000 306.730 0.280 ;
    END
  END s0_axi_araddr_6
  PIN s0_axi_araddr_7
    DIRECTION OUTPUT ;
    USE SIGNAL ;
    ANTENNAGATEAREA 0.434700 ;
    ANTENNADIFFAREA 1.137600 ;
    PORT
      LAYER met2 ;
        RECT 191.450 0.000 191.730 0.280 ;
    END
  END s0_axi_araddr_7
  PIN s0_axi_araddr_8
    DIRECTION OUTPUT ;
    USE SIGNAL ;
    ANTENNAGATEAREA 0.434700 ;
    ANTENNADIFFAREA 1.137600 ;
    PORT
      LAYER met2 ;
        RECT 196.050 0.000 196.330 0.280 ;
    END
  END s0_axi_araddr_8
  PIN s0_axi_araddr_9
    DIRECTION OUTPUT ;
    USE SIGNAL ;
    ANTENNAGATEAREA 0.434700 ;
    ANTENNADIFFAREA 1.137600 ;
    PORT
      LAYER met2 ;
        RECT 449.970 519.840 450.250 520.120 ;
    END
  END s0_axi_araddr_9
  PIN s0_axi_arready
    DIRECTION INPUT ;
    USE SIGNAL ;
    ANTENNAGATEAREA 0.647700 ;
    ANTENNADIFFAREA 0.434700 ;
    PORT
      LAYER met2 ;
        RECT 284.370 519.840 284.650 520.120 ;
    END
  END s0_axi_arready
  PIN s0_axi_arvalid
    DIRECTION OUTPUT ;
    USE SIGNAL ;
    ANTENNAGATEAREA 0.434700 ;
    ANTENNADIFFAREA 1.137600 ;
    PORT
      LAYER met2 ;
        RECT 162.930 519.840 163.210 520.120 ;
    END
  END s0_axi_arvalid
  PIN s0_axi_awaddr_0
    DIRECTION OUTPUT ;
    USE SIGNAL ;
    ANTENNAGATEAREA 0.434700 ;
    ANTENNADIFFAREA 1.137600 ;
    PORT
      LAYER met2 ;
        RECT 432.490 0.000 432.770 0.280 ;
    END
  END s0_axi_awaddr_0
  PIN s0_axi_awaddr_1
    DIRECTION OUTPUT ;
    USE SIGNAL ;
    ANTENNAGATEAREA 0.434700 ;
    ANTENNADIFFAREA 1.137600 ;
    PORT
      LAYER met2 ;
        RECT 270.570 0.000 270.850 0.280 ;
    END
  END s0_axi_awaddr_1
  PIN s0_axi_awaddr_10
    DIRECTION OUTPUT ;
    USE SIGNAL ;
    ANTENNAGATEAREA 0.434700 ;
    ANTENNADIFFAREA 1.137600 ;
    PORT
      LAYER met2 ;
        RECT 339.570 0.000 339.850 0.280 ;
    END
  END s0_axi_awaddr_10
  PIN s0_axi_awaddr_11
    DIRECTION OUTPUT ;
    USE SIGNAL ;
    ANTENNAGATEAREA 0.434700 ;
    ANTENNADIFFAREA 1.137600 ;
    PORT
      LAYER met2 ;
        RECT 316.570 0.000 316.850 0.280 ;
    END
  END s0_axi_awaddr_11
  PIN s0_axi_awaddr_12
    DIRECTION OUTPUT ;
    USE SIGNAL ;
    ANTENNAGATEAREA 0.434700 ;
    ANTENNADIFFAREA 1.137600 ;
    PORT
      LAYER met2 ;
        RECT 289.890 519.840 290.170 520.120 ;
    END
  END s0_axi_awaddr_12
  PIN s0_axi_awaddr_13
    DIRECTION OUTPUT ;
    USE SIGNAL ;
    ANTENNAGATEAREA 0.434700 ;
    ANTENNADIFFAREA 1.137600 ;
    PORT
      LAYER met2 ;
        RECT 302.770 0.000 303.050 0.280 ;
    END
  END s0_axi_awaddr_13
  PIN s0_axi_awaddr_14
    DIRECTION OUTPUT ;
    USE SIGNAL ;
    ANTENNAGATEAREA 0.434700 ;
    ANTENNADIFFAREA 1.137600 ;
    PORT
      LAYER met2 ;
        RECT 379.130 0.000 379.410 0.280 ;
    END
  END s0_axi_awaddr_14
  PIN s0_axi_awaddr_15
    DIRECTION OUTPUT ;
    USE SIGNAL ;
    ANTENNAGATEAREA 0.434700 ;
    ANTENNADIFFAREA 1.137600 ;
    PORT
      LAYER met2 ;
        RECT 78.290 519.840 78.570 520.120 ;
    END
  END s0_axi_awaddr_15
  PIN s0_axi_awaddr_16
    DIRECTION OUTPUT ;
    USE SIGNAL ;
    ANTENNAGATEAREA 0.434700 ;
    ANTENNADIFFAREA 1.137600 ;
    PORT
      LAYER met2 ;
        RECT 310.130 0.000 310.410 0.280 ;
    END
  END s0_axi_awaddr_16
  PIN s0_axi_awaddr_17
    DIRECTION OUTPUT ;
    USE SIGNAL ;
    ANTENNAGATEAREA 0.434700 ;
    ANTENNADIFFAREA 1.137600 ;
    PORT
      LAYER met2 ;
        RECT 354.290 519.840 354.570 520.120 ;
    END
  END s0_axi_awaddr_17
  PIN s0_axi_awaddr_18
    DIRECTION OUTPUT ;
    USE SIGNAL ;
    ANTENNAGATEAREA 0.434700 ;
    ANTENNADIFFAREA 1.137600 ;
    PORT
      LAYER met2 ;
        RECT 329.450 519.840 329.730 520.120 ;
    END
  END s0_axi_awaddr_18
  PIN s0_axi_awaddr_19
    DIRECTION OUTPUT ;
    USE SIGNAL ;
    ANTENNAGATEAREA 0.434700 ;
    ANTENNADIFFAREA 1.137600 ;
    PORT
      LAYER met3 ;
        RECT 508.800 448.840 509.400 449.440 ;
    END
  END s0_axi_awaddr_19
  PIN s0_axi_awaddr_2
    DIRECTION OUTPUT ;
    USE SIGNAL ;
    ANTENNAGATEAREA 0.434700 ;
    ANTENNADIFFAREA 1.137600 ;
    PORT
      LAYER met2 ;
        RECT 254.010 0.000 254.290 0.280 ;
    END
  END s0_axi_awaddr_2
  PIN s0_axi_awaddr_20
    DIRECTION OUTPUT ;
    USE SIGNAL ;
    ANTENNAGATEAREA 0.434700 ;
    ANTENNADIFFAREA 1.137600 ;
    PORT
      LAYER met2 ;
        RECT 221.810 0.000 222.090 0.280 ;
    END
  END s0_axi_awaddr_20
  PIN s0_axi_awaddr_21
    DIRECTION OUTPUT ;
    USE SIGNAL ;
    ANTENNAGATEAREA 0.434700 ;
    ANTENNADIFFAREA 1.137600 ;
    PORT
      LAYER met3 ;
        RECT 0.000 416.200 0.600 416.800 ;
    END
  END s0_axi_awaddr_21
  PIN s0_axi_awaddr_22
    DIRECTION OUTPUT ;
    USE SIGNAL ;
    ANTENNAGATEAREA 0.434700 ;
    ANTENNADIFFAREA 1.137600 ;
    PORT
      LAYER met2 ;
        RECT 473.890 0.000 474.170 0.280 ;
    END
  END s0_axi_awaddr_22
  PIN s0_axi_awaddr_23
    DIRECTION OUTPUT ;
    USE SIGNAL ;
    ANTENNAGATEAREA 0.434700 ;
    ANTENNADIFFAREA 1.137600 ;
    PORT
      LAYER met2 ;
        RECT 347.850 519.840 348.130 520.120 ;
    END
  END s0_axi_awaddr_23
  PIN s0_axi_awaddr_24
    DIRECTION OUTPUT ;
    USE SIGNAL ;
    ANTENNAGATEAREA 0.434700 ;
    ANTENNADIFFAREA 1.137600 ;
    PORT
      LAYER met2 ;
        RECT 171.210 519.840 171.490 520.120 ;
    END
  END s0_axi_awaddr_24
  PIN s0_axi_awaddr_25
    DIRECTION OUTPUT ;
    USE SIGNAL ;
    ANTENNAGATEAREA 0.434700 ;
    ANTENNADIFFAREA 1.137600 ;
    PORT
      LAYER met2 ;
        RECT 237.450 0.000 237.730 0.280 ;
    END
  END s0_axi_awaddr_25
  PIN s0_axi_awaddr_26
    DIRECTION OUTPUT ;
    USE SIGNAL ;
    ANTENNAGATEAREA 0.434700 ;
    ANTENNADIFFAREA 1.137600 ;
    PORT
      LAYER met2 ;
        RECT 196.970 519.840 197.250 520.120 ;
    END
  END s0_axi_awaddr_26
  PIN s0_axi_awaddr_27
    DIRECTION OUTPUT ;
    USE SIGNAL ;
    ANTENNAGATEAREA 0.434700 ;
    ANTENNADIFFAREA 1.137600 ;
    PORT
      LAYER met2 ;
        RECT 335.890 0.000 336.170 0.280 ;
    END
  END s0_axi_awaddr_27
  PIN s0_axi_awaddr_28
    DIRECTION OUTPUT ;
    USE SIGNAL ;
    ANTENNAGATEAREA 0.434700 ;
    ANTENNADIFFAREA 1.137600 ;
    PORT
      LAYER met2 ;
        RECT 207.090 0.000 207.370 0.280 ;
    END
  END s0_axi_awaddr_28
  PIN s0_axi_awaddr_29
    DIRECTION OUTPUT ;
    USE SIGNAL ;
    ANTENNAGATEAREA 0.434700 ;
    ANTENNADIFFAREA 1.137600 ;
    PORT
      LAYER met2 ;
        RECT 388.330 519.840 388.610 520.120 ;
    END
  END s0_axi_awaddr_29
  PIN s0_axi_awaddr_3
    DIRECTION OUTPUT ;
    USE SIGNAL ;
    ANTENNAGATEAREA 0.434700 ;
    ANTENNADIFFAREA 1.137600 ;
    PORT
      LAYER met2 ;
        RECT 199.730 0.000 200.010 0.280 ;
    END
  END s0_axi_awaddr_3
  PIN s0_axi_awaddr_30
    DIRECTION OUTPUT ;
    USE SIGNAL ;
    ANTENNAGATEAREA 0.434700 ;
    ANTENNADIFFAREA 1.137600 ;
    PORT
      LAYER met2 ;
        RECT 260.450 0.000 260.730 0.280 ;
    END
  END s0_axi_awaddr_30
  PIN s0_axi_awaddr_31
    DIRECTION OUTPUT ;
    USE SIGNAL ;
    ANTENNAGATEAREA 0.434700 ;
    ANTENNADIFFAREA 1.137600 ;
    PORT
      LAYER met2 ;
        RECT 257.690 519.840 257.970 520.120 ;
    END
  END s0_axi_awaddr_31
  PIN s0_axi_awaddr_4
    DIRECTION OUTPUT ;
    USE SIGNAL ;
    ANTENNAGATEAREA 0.434700 ;
    ANTENNADIFFAREA 1.137600 ;
    PORT
      LAYER met2 ;
        RECT 340.490 519.840 340.770 520.120 ;
    END
  END s0_axi_awaddr_4
  PIN s0_axi_awaddr_5
    DIRECTION OUTPUT ;
    USE SIGNAL ;
    ANTENNAGATEAREA 0.434700 ;
    ANTENNADIFFAREA 1.137600 ;
    PORT
      LAYER met2 ;
        RECT 293.570 0.000 293.850 0.280 ;
    END
  END s0_axi_awaddr_5
  PIN s0_axi_awaddr_6
    DIRECTION OUTPUT ;
    USE SIGNAL ;
    ANTENNAGATEAREA 0.434700 ;
    ANTENNADIFFAREA 1.137600 ;
    PORT
      LAYER met2 ;
        RECT 294.490 0.000 294.770 0.280 ;
    END
  END s0_axi_awaddr_6
  PIN s0_axi_awaddr_7
    DIRECTION OUTPUT ;
    USE SIGNAL ;
    ANTENNAGATEAREA 0.434700 ;
    ANTENNADIFFAREA 1.137600 ;
    PORT
      LAYER met2 ;
        RECT 217.210 0.000 217.490 0.280 ;
    END
  END s0_axi_awaddr_7
  PIN s0_axi_awaddr_8
    DIRECTION OUTPUT ;
    USE SIGNAL ;
    ANTENNAGATEAREA 0.434700 ;
    ANTENNADIFFAREA 1.137600 ;
    PORT
      LAYER met2 ;
        RECT 242.970 0.000 243.250 0.280 ;
    END
  END s0_axi_awaddr_8
  PIN s0_axi_awaddr_9
    DIRECTION OUTPUT ;
    USE SIGNAL ;
    ANTENNAGATEAREA 0.434700 ;
    ANTENNADIFFAREA 1.137600 ;
    PORT
      LAYER met3 ;
        RECT 508.800 474.680 509.400 475.280 ;
    END
  END s0_axi_awaddr_9
  PIN s0_axi_awready
    DIRECTION INPUT ;
    USE SIGNAL ;
    ANTENNAGATEAREA 0.647700 ;
    ANTENNADIFFAREA 0.434700 ;
    PORT
      LAYER met3 ;
        RECT 0.000 335.960 0.600 336.560 ;
    END
  END s0_axi_awready
  PIN s0_axi_awvalid
    DIRECTION OUTPUT ;
    USE SIGNAL ;
    ANTENNAGATEAREA 0.434700 ;
    ANTENNADIFFAREA 1.137600 ;
    PORT
      LAYER met3 ;
        RECT 0.000 145.560 0.600 146.160 ;
    END
  END s0_axi_awvalid
  PIN s0_axi_bready
    DIRECTION OUTPUT ;
    USE SIGNAL ;
    ANTENNAGATEAREA 0.434700 ;
    ANTENNADIFFAREA 1.137600 ;
    PORT
      LAYER met3 ;
        RECT 0.000 138.760 0.600 139.360 ;
    END
  END s0_axi_bready
  PIN s0_axi_bresp_0
    DIRECTION INPUT ;
    USE SIGNAL ;
    ANTENNAGATEAREA 0.647700 ;
    ANTENNADIFFAREA 0.434700 ;
    PORT
      LAYER met3 ;
        RECT 0.000 291.080 0.600 291.680 ;
    END
  END s0_axi_bresp_0
  PIN s0_axi_bresp_1
    DIRECTION INPUT ;
    USE SIGNAL ;
    ANTENNAGATEAREA 0.647700 ;
    ANTENNADIFFAREA 0.434700 ;
    PORT
      LAYER met3 ;
        RECT 0.000 289.720 0.600 290.320 ;
    END
  END s0_axi_bresp_1
  PIN s0_axi_bvalid
    DIRECTION INPUT ;
    USE SIGNAL ;
    ANTENNAGATEAREA 0.647700 ;
    ANTENNADIFFAREA 0.434700 ;
    PORT
      LAYER met3 ;
        RECT 0.000 337.320 0.600 337.920 ;
    END
  END s0_axi_bvalid
  PIN s0_axi_rdata_0
    DIRECTION INPUT ;
    USE SIGNAL ;
    ANTENNAGATEAREA 0.647700 ;
    ANTENNADIFFAREA 0.434700 ;
    PORT
      LAYER met3 ;
        RECT 508.800 224.440 509.400 225.040 ;
    END
  END s0_axi_rdata_0
  PIN s0_axi_rdata_1
    DIRECTION INPUT ;
    USE SIGNAL ;
    ANTENNAGATEAREA 0.647700 ;
    ANTENNADIFFAREA 0.434700 ;
    PORT
      LAYER met2 ;
        RECT 299.090 519.840 299.370 520.120 ;
    END
  END s0_axi_rdata_1
  PIN s0_axi_rdata_10
    DIRECTION INPUT ;
    USE SIGNAL ;
    ANTENNAGATEAREA 0.647700 ;
    ANTENNADIFFAREA 0.434700 ;
    PORT
      LAYER met3 ;
        RECT 508.800 312.840 509.400 313.440 ;
    END
  END s0_axi_rdata_10
  PIN s0_axi_rdata_11
    DIRECTION INPUT ;
    USE SIGNAL ;
    ANTENNAGATEAREA 0.647700 ;
    ANTENNADIFFAREA 0.434700 ;
    PORT
      LAYER met2 ;
        RECT 284.370 0.000 284.650 0.280 ;
    END
  END s0_axi_rdata_11
  PIN s0_axi_rdata_12
    DIRECTION INPUT ;
    USE SIGNAL ;
    ANTENNAGATEAREA 0.647700 ;
    ANTENNADIFFAREA 0.434700 ;
    PORT
      LAYER met2 ;
        RECT 330.370 0.000 330.650 0.280 ;
    END
  END s0_axi_rdata_12
  PIN s0_axi_rdata_13
    DIRECTION INPUT ;
    USE SIGNAL ;
    ANTENNAGATEAREA 0.647700 ;
    ANTENNADIFFAREA 0.434700 ;
    PORT
      LAYER met3 ;
        RECT 508.800 63.960 509.400 64.560 ;
    END
  END s0_axi_rdata_13
  PIN s0_axi_rdata_14
    DIRECTION INPUT ;
    USE SIGNAL ;
    ANTENNAGATEAREA 0.647700 ;
    ANTENNADIFFAREA 0.434700 ;
    PORT
      LAYER met3 ;
        RECT 508.800 437.960 509.400 438.560 ;
    END
  END s0_axi_rdata_14
  PIN s0_axi_rdata_15
    DIRECTION INPUT ;
    USE SIGNAL ;
    ANTENNAGATEAREA 0.647700 ;
    ANTENNADIFFAREA 0.434700 ;
    PORT
      LAYER met3 ;
        RECT 508.800 197.240 509.400 197.840 ;
    END
  END s0_axi_rdata_15
  PIN s0_axi_rdata_16
    DIRECTION INPUT ;
    USE SIGNAL ;
    ANTENNAGATEAREA 0.647700 ;
    ANTENNADIFFAREA 0.434700 ;
    PORT
      LAYER met3 ;
        RECT 508.800 137.400 509.400 138.000 ;
    END
  END s0_axi_rdata_16
  PIN s0_axi_rdata_17
    DIRECTION INPUT ;
    USE SIGNAL ;
    ANTENNAGATEAREA 0.647700 ;
    ANTENNADIFFAREA 0.434700 ;
    PORT
      LAYER met3 ;
        RECT 508.800 322.360 509.400 322.960 ;
    END
  END s0_axi_rdata_17
  PIN s0_axi_rdata_18
    DIRECTION INPUT ;
    USE SIGNAL ;
    ANTENNAGATEAREA 0.647700 ;
    ANTENNADIFFAREA 0.434700 ;
    PORT
      LAYER met2 ;
        RECT 278.850 0.000 279.130 0.280 ;
    END
  END s0_axi_rdata_18
  PIN s0_axi_rdata_19
    DIRECTION INPUT ;
    USE SIGNAL ;
    ANTENNAGATEAREA 0.647700 ;
    ANTENNADIFFAREA 0.434700 ;
    PORT
      LAYER met3 ;
        RECT 508.800 333.240 509.400 333.840 ;
    END
  END s0_axi_rdata_19
  PIN s0_axi_rdata_2
    DIRECTION INPUT ;
    USE SIGNAL ;
    ANTENNAGATEAREA 0.647700 ;
    ANTENNADIFFAREA 0.434700 ;
    PORT
      LAYER met3 ;
        RECT 508.800 183.640 509.400 184.240 ;
    END
  END s0_axi_rdata_2
  PIN s0_axi_rdata_20
    DIRECTION INPUT ;
    USE SIGNAL ;
    ANTENNAGATEAREA 0.647700 ;
    ANTENNADIFFAREA 0.434700 ;
    PORT
      LAYER met3 ;
        RECT 508.800 231.240 509.400 231.840 ;
    END
  END s0_axi_rdata_20
  PIN s0_axi_rdata_21
    DIRECTION INPUT ;
    USE SIGNAL ;
    ANTENNAGATEAREA 0.647700 ;
    ANTENNADIFFAREA 0.434700 ;
    PORT
      LAYER met3 ;
        RECT 508.800 459.720 509.400 460.320 ;
    END
  END s0_axi_rdata_21
  PIN s0_axi_rdata_22
    DIRECTION INPUT ;
    USE SIGNAL ;
    ANTENNAGATEAREA 0.647700 ;
    ANTENNADIFFAREA 0.434700 ;
    PORT
      LAYER met3 ;
        RECT 508.800 263.880 509.400 264.480 ;
    END
  END s0_axi_rdata_22
  PIN s0_axi_rdata_23
    DIRECTION INPUT ;
    USE SIGNAL ;
    ANTENNAGATEAREA 0.647700 ;
    ANTENNADIFFAREA 0.434700 ;
    PORT
      LAYER met3 ;
        RECT 508.800 174.120 509.400 174.720 ;
    END
  END s0_axi_rdata_23
  PIN s0_axi_rdata_24
    DIRECTION INPUT ;
    USE SIGNAL ;
    ANTENNAGATEAREA 0.647700 ;
    ANTENNADIFFAREA 0.434700 ;
    PORT
      LAYER met2 ;
        RECT 288.050 0.000 288.330 0.280 ;
    END
  END s0_axi_rdata_24
  PIN s0_axi_rdata_25
    DIRECTION INPUT ;
    USE SIGNAL ;
    ANTENNAGATEAREA 0.647700 ;
    ANTENNADIFFAREA 0.434700 ;
    PORT
      LAYER met3 ;
        RECT 508.800 484.200 509.400 484.800 ;
    END
  END s0_axi_rdata_25
  PIN s0_axi_rdata_26
    DIRECTION INPUT ;
    USE SIGNAL ;
    ANTENNAGATEAREA 0.647700 ;
    ANTENNADIFFAREA 0.434700 ;
    PORT
      LAYER met3 ;
        RECT 508.800 99.320 509.400 99.920 ;
    END
  END s0_axi_rdata_26
  PIN s0_axi_rdata_27
    DIRECTION INPUT ;
    USE SIGNAL ;
    ANTENNAGATEAREA 0.647700 ;
    ANTENNADIFFAREA 0.434700 ;
    PORT
      LAYER met3 ;
        RECT 508.800 228.520 509.400 229.120 ;
    END
  END s0_axi_rdata_27
  PIN s0_axi_rdata_28
    DIRECTION INPUT ;
    USE SIGNAL ;
    ANTENNAGATEAREA 0.647700 ;
    ANTENNADIFFAREA 0.434700 ;
    PORT
      LAYER met3 ;
        RECT 508.800 127.880 509.400 128.480 ;
    END
  END s0_axi_rdata_28
  PIN s0_axi_rdata_29
    DIRECTION INPUT ;
    USE SIGNAL ;
    ANTENNAGATEAREA 0.647700 ;
    ANTENNADIFFAREA 0.434700 ;
    PORT
      LAYER met3 ;
        RECT 508.800 281.560 509.400 282.160 ;
    END
  END s0_axi_rdata_29
  PIN s0_axi_rdata_3
    DIRECTION INPUT ;
    USE SIGNAL ;
    ANTENNAGATEAREA 0.647700 ;
    ANTENNADIFFAREA 0.434700 ;
    PORT
      LAYER met3 ;
        RECT 508.800 384.920 509.400 385.520 ;
    END
  END s0_axi_rdata_3
  PIN s0_axi_rdata_30
    DIRECTION INPUT ;
    USE SIGNAL ;
    ANTENNAGATEAREA 0.647700 ;
    ANTENNADIFFAREA 0.434700 ;
    PORT
      LAYER met3 ;
        RECT 508.800 129.240 509.400 129.840 ;
    END
  END s0_axi_rdata_30
  PIN s0_axi_rdata_31
    DIRECTION INPUT ;
    USE SIGNAL ;
    ANTENNAGATEAREA 0.647700 ;
    ANTENNADIFFAREA 0.434700 ;
    PORT
      LAYER met3 ;
        RECT 508.800 425.720 509.400 426.320 ;
    END
  END s0_axi_rdata_31
  PIN s0_axi_rdata_4
    DIRECTION INPUT ;
    USE SIGNAL ;
    ANTENNAGATEAREA 0.647700 ;
    ANTENNADIFFAREA 0.434700 ;
    PORT
      LAYER met2 ;
        RECT 282.530 519.840 282.810 520.120 ;
    END
  END s0_axi_rdata_4
  PIN s0_axi_rdata_5
    DIRECTION INPUT ;
    USE SIGNAL ;
    ANTENNAGATEAREA 0.647700 ;
    ANTENNADIFFAREA 0.434700 ;
    PORT
      LAYER met3 ;
        RECT 508.800 232.600 509.400 233.200 ;
    END
  END s0_axi_rdata_5
  PIN s0_axi_rdata_6
    DIRECTION INPUT ;
    USE SIGNAL ;
    ANTENNAGATEAREA 0.647700 ;
    ANTENNADIFFAREA 0.434700 ;
    PORT
      LAYER met3 ;
        RECT 508.800 378.120 509.400 378.720 ;
    END
  END s0_axi_rdata_6
  PIN s0_axi_rdata_7
    DIRECTION INPUT ;
    USE SIGNAL ;
    ANTENNAGATEAREA 0.647700 ;
    ANTENNADIFFAREA 0.434700 ;
    PORT
      LAYER met3 ;
        RECT 508.800 375.400 509.400 376.000 ;
    END
  END s0_axi_rdata_7
  PIN s0_axi_rdata_8
    DIRECTION INPUT ;
    USE SIGNAL ;
    ANTENNAGATEAREA 0.647700 ;
    ANTENNADIFFAREA 0.434700 ;
    PORT
      LAYER met3 ;
        RECT 508.800 314.200 509.400 314.800 ;
    END
  END s0_axi_rdata_8
  PIN s0_axi_rdata_9
    DIRECTION INPUT ;
    USE SIGNAL ;
    ANTENNAGATEAREA 0.647700 ;
    ANTENNADIFFAREA 0.434700 ;
    PORT
      LAYER met3 ;
        RECT 508.800 259.800 509.400 260.400 ;
    END
  END s0_axi_rdata_9
  PIN s0_axi_rready
    DIRECTION OUTPUT ;
    USE SIGNAL ;
    ANTENNAGATEAREA 0.434700 ;
    ANTENNADIFFAREA 1.137600 ;
    PORT
      LAYER met2 ;
        RECT 212.610 0.000 212.890 0.280 ;
    END
  END s0_axi_rready
  PIN s0_axi_rresp_0
    DIRECTION INPUT ;
    USE SIGNAL ;
    ANTENNAGATEAREA 0.647700 ;
    ANTENNADIFFAREA 0.434700 ;
    PORT
      LAYER met3 ;
        RECT 508.800 341.400 509.400 342.000 ;
    END
  END s0_axi_rresp_0
  PIN s0_axi_rresp_1
    DIRECTION INPUT ;
    USE SIGNAL ;
    ANTENNAGATEAREA 0.647700 ;
    ANTENNADIFFAREA 0.434700 ;
    PORT
      LAYER met3 ;
        RECT 508.800 131.960 509.400 132.560 ;
    END
  END s0_axi_rresp_1
  PIN s0_axi_rvalid
    DIRECTION INPUT ;
    USE SIGNAL ;
    ANTENNAGATEAREA 0.647700 ;
    ANTENNADIFFAREA 0.434700 ;
    PORT
      LAYER met3 ;
        RECT 508.800 325.080 509.400 325.680 ;
    END
  END s0_axi_rvalid
  PIN s0_axi_wdata_0
    DIRECTION OUTPUT ;
    USE SIGNAL ;
    ANTENNAGATEAREA 0.434700 ;
    ANTENNADIFFAREA 1.137600 ;
    PORT
      LAYER met2 ;
        RECT 209.850 0.000 210.130 0.280 ;
    END
  END s0_axi_wdata_0
  PIN s0_axi_wdata_1
    DIRECTION OUTPUT ;
    USE SIGNAL ;
    ANTENNAGATEAREA 0.434700 ;
    ANTENNADIFFAREA 1.137600 ;
    PORT
      LAYER met2 ;
        RECT 277.010 0.000 277.290 0.280 ;
    END
  END s0_axi_wdata_1
  PIN s0_axi_wdata_10
    DIRECTION OUTPUT ;
    USE SIGNAL ;
    ANTENNAGATEAREA 0.434700 ;
    ANTENNADIFFAREA 1.137600 ;
    PORT
      LAYER met2 ;
        RECT 193.290 519.840 193.570 520.120 ;
    END
  END s0_axi_wdata_10
  PIN s0_axi_wdata_11
    DIRECTION OUTPUT ;
    USE SIGNAL ;
    ANTENNAGATEAREA 0.434700 ;
    ANTENNADIFFAREA 1.137600 ;
    PORT
      LAYER met2 ;
        RECT 104.050 519.840 104.330 520.120 ;
    END
  END s0_axi_wdata_11
  PIN s0_axi_wdata_12
    DIRECTION OUTPUT ;
    USE SIGNAL ;
    ANTENNAGATEAREA 0.434700 ;
    ANTENNADIFFAREA 1.137600 ;
    PORT
      LAYER met3 ;
        RECT 0.000 136.040 0.600 136.640 ;
    END
  END s0_axi_wdata_12
  PIN s0_axi_wdata_13
    DIRECTION OUTPUT ;
    USE SIGNAL ;
    ANTENNAGATEAREA 0.434700 ;
    ANTENNADIFFAREA 1.137600 ;
    PORT
      LAYER met2 ;
        RECT 226.410 519.840 226.690 520.120 ;
    END
  END s0_axi_wdata_13
  PIN s0_axi_wdata_14
    DIRECTION OUTPUT ;
    USE SIGNAL ;
    ANTENNAGATEAREA 0.434700 ;
    ANTENNADIFFAREA 1.137600 ;
    PORT
      LAYER met2 ;
        RECT 361.650 519.840 361.930 520.120 ;
    END
  END s0_axi_wdata_14
  PIN s0_axi_wdata_15
    DIRECTION OUTPUT ;
    USE SIGNAL ;
    ANTENNAGATEAREA 0.434700 ;
    ANTENNADIFFAREA 1.137600 ;
    PORT
      LAYER met2 ;
        RECT 75.530 519.840 75.810 520.120 ;
    END
  END s0_axi_wdata_15
  PIN s0_axi_wdata_16
    DIRECTION OUTPUT ;
    USE SIGNAL ;
    ANTENNAGATEAREA 0.434700 ;
    ANTENNADIFFAREA 1.137600 ;
    PORT
      LAYER met3 ;
        RECT 0.000 374.040 0.600 374.640 ;
    END
  END s0_axi_wdata_16
  PIN s0_axi_wdata_17
    DIRECTION OUTPUT ;
    USE SIGNAL ;
    ANTENNAGATEAREA 0.434700 ;
    ANTENNADIFFAREA 1.137600 ;
    PORT
      LAYER met2 ;
        RECT 149.130 519.840 149.410 520.120 ;
    END
  END s0_axi_wdata_17
  PIN s0_axi_wdata_18
    DIRECTION OUTPUT ;
    USE SIGNAL ;
    ANTENNAGATEAREA 0.434700 ;
    ANTENNADIFFAREA 1.137600 ;
    PORT
      LAYER met2 ;
        RECT 326.690 0.000 326.970 0.280 ;
    END
  END s0_axi_wdata_18
  PIN s0_axi_wdata_19
    DIRECTION OUTPUT ;
    USE SIGNAL ;
    ANTENNAGATEAREA 0.434700 ;
    ANTENNADIFFAREA 1.137600 ;
    PORT
      LAYER met2 ;
        RECT 233.770 519.840 234.050 520.120 ;
    END
  END s0_axi_wdata_19
  PIN s0_axi_wdata_2
    DIRECTION OUTPUT ;
    USE SIGNAL ;
    ANTENNAGATEAREA 0.434700 ;
    ANTENNADIFFAREA 1.137600 ;
    PORT
      LAYER met2 ;
        RECT 210.770 519.840 211.050 520.120 ;
    END
  END s0_axi_wdata_2
  PIN s0_axi_wdata_20
    DIRECTION OUTPUT ;
    USE SIGNAL ;
    ANTENNAGATEAREA 0.434700 ;
    ANTENNADIFFAREA 1.137600 ;
    PORT
      LAYER met2 ;
        RECT 279.770 0.000 280.050 0.280 ;
    END
  END s0_axi_wdata_20
  PIN s0_axi_wdata_21
    DIRECTION OUTPUT ;
    USE SIGNAL ;
    ANTENNAGATEAREA 0.434700 ;
    ANTENNADIFFAREA 1.137600 ;
    PORT
      LAYER met2 ;
        RECT 92.090 519.840 92.370 520.120 ;
    END
  END s0_axi_wdata_21
  PIN s0_axi_wdata_22
    DIRECTION OUTPUT ;
    USE SIGNAL ;
    ANTENNAGATEAREA 0.434700 ;
    ANTENNADIFFAREA 1.137600 ;
    PORT
      LAYER met2 ;
        RECT 422.370 519.840 422.650 520.120 ;
    END
  END s0_axi_wdata_22
  PIN s0_axi_wdata_23
    DIRECTION OUTPUT ;
    USE SIGNAL ;
    ANTENNAGATEAREA 0.434700 ;
    ANTENNADIFFAREA 1.137600 ;
    PORT
      LAYER met3 ;
        RECT 0.000 398.520 0.600 399.120 ;
    END
  END s0_axi_wdata_23
  PIN s0_axi_wdata_24
    DIRECTION OUTPUT ;
    USE SIGNAL ;
    ANTENNAGATEAREA 0.434700 ;
    ANTENNADIFFAREA 1.137600 ;
    PORT
      LAYER met2 ;
        RECT 235.610 0.000 235.890 0.280 ;
    END
  END s0_axi_wdata_24
  PIN s0_axi_wdata_25
    DIRECTION OUTPUT ;
    USE SIGNAL ;
    ANTENNAGATEAREA 0.434700 ;
    ANTENNADIFFAREA 1.137600 ;
    PORT
      LAYER met2 ;
        RECT 51.610 519.840 51.890 520.120 ;
    END
  END s0_axi_wdata_25
  PIN s0_axi_wdata_26
    DIRECTION OUTPUT ;
    USE SIGNAL ;
    ANTENNAGATEAREA 0.434700 ;
    ANTENNADIFFAREA 1.137600 ;
    PORT
      LAYER met2 ;
        RECT 188.690 0.000 188.970 0.280 ;
    END
  END s0_axi_wdata_26
  PIN s0_axi_wdata_27
    DIRECTION OUTPUT ;
    USE SIGNAL ;
    ANTENNAGATEAREA 0.434700 ;
    ANTENNADIFFAREA 1.137600 ;
    PORT
      LAYER met2 ;
        RECT 116.010 519.840 116.290 520.120 ;
    END
  END s0_axi_wdata_27
  PIN s0_axi_wdata_28
    DIRECTION OUTPUT ;
    USE SIGNAL ;
    ANTENNAGATEAREA 0.434700 ;
    ANTENNADIFFAREA 1.137600 ;
    PORT
      LAYER met2 ;
        RECT 219.050 519.840 219.330 520.120 ;
    END
  END s0_axi_wdata_28
  PIN s0_axi_wdata_29
    DIRECTION OUTPUT ;
    USE SIGNAL ;
    ANTENNAGATEAREA 0.434700 ;
    ANTENNADIFFAREA 1.137600 ;
    PORT
      LAYER met2 ;
        RECT 448.130 0.000 448.410 0.280 ;
    END
  END s0_axi_wdata_29
  PIN s0_axi_wdata_3
    DIRECTION OUTPUT ;
    USE SIGNAL ;
    ANTENNAGATEAREA 0.434700 ;
    ANTENNADIFFAREA 1.137600 ;
    PORT
      LAYER met2 ;
        RECT 133.490 519.840 133.770 520.120 ;
    END
  END s0_axi_wdata_3
  PIN s0_axi_wdata_30
    DIRECTION OUTPUT ;
    USE SIGNAL ;
    ANTENNAGATEAREA 0.434700 ;
    ANTENNADIFFAREA 1.137600 ;
    PORT
      LAYER met2 ;
        RECT 265.050 0.000 265.330 0.280 ;
    END
  END s0_axi_wdata_30
  PIN s0_axi_wdata_31
    DIRECTION OUTPUT ;
    USE SIGNAL ;
    ANTENNAGATEAREA 0.434700 ;
    ANTENNADIFFAREA 1.137600 ;
    PORT
      LAYER met2 ;
        RECT 276.090 519.840 276.370 520.120 ;
    END
  END s0_axi_wdata_31
  PIN s0_axi_wdata_4
    DIRECTION OUTPUT ;
    USE SIGNAL ;
    ANTENNAGATEAREA 0.434700 ;
    ANTENNADIFFAREA 1.137600 ;
    PORT
      LAYER met3 ;
        RECT 0.000 65.320 0.600 65.920 ;
    END
  END s0_axi_wdata_4
  PIN s0_axi_wdata_5
    DIRECTION OUTPUT ;
    USE SIGNAL ;
    ANTENNAGATEAREA 0.434700 ;
    ANTENNADIFFAREA 1.137600 ;
    PORT
      LAYER met3 ;
        RECT 0.000 372.680 0.600 373.280 ;
    END
  END s0_axi_wdata_5
  PIN s0_axi_wdata_6
    DIRECTION OUTPUT ;
    USE SIGNAL ;
    ANTENNAGATEAREA 0.434700 ;
    ANTENNADIFFAREA 1.137600 ;
    PORT
      LAYER met2 ;
        RECT 410.410 0.000 410.690 0.280 ;
    END
  END s0_axi_wdata_6
  PIN s0_axi_wdata_7
    DIRECTION OUTPUT ;
    USE SIGNAL ;
    ANTENNAGATEAREA 0.434700 ;
    ANTENNADIFFAREA 1.137600 ;
    PORT
      LAYER met2 ;
        RECT 375.450 519.840 375.730 520.120 ;
    END
  END s0_axi_wdata_7
  PIN s0_axi_wdata_8
    DIRECTION OUTPUT ;
    USE SIGNAL ;
    ANTENNAGATEAREA 0.434700 ;
    ANTENNADIFFAREA 1.137600 ;
    PORT
      LAYER met2 ;
        RECT 437.090 0.000 437.370 0.280 ;
    END
  END s0_axi_wdata_8
  PIN s0_axi_wdata_9
    DIRECTION OUTPUT ;
    USE SIGNAL ;
    ANTENNAGATEAREA 0.434700 ;
    ANTENNADIFFAREA 1.137600 ;
    PORT
      LAYER met3 ;
        RECT 508.800 471.960 509.400 472.560 ;
    END
  END s0_axi_wdata_9
  PIN s0_axi_wready
    DIRECTION INPUT ;
    USE SIGNAL ;
    ANTENNAGATEAREA 0.647700 ;
    ANTENNADIFFAREA 0.434700 ;
    PORT
      LAYER met3 ;
        RECT 0.000 329.160 0.600 329.760 ;
    END
  END s0_axi_wready
  PIN s0_axi_wstrb_0
    DIRECTION OUTPUT ;
    USE SIGNAL ;
    ANTENNAGATEAREA 0.434700 ;
    ANTENNADIFFAREA 1.137600 ;
    PORT
      LAYER met2 ;
        RECT 258.610 519.840 258.890 520.120 ;
    END
  END s0_axi_wstrb_0
  PIN s0_axi_wstrb_1
    DIRECTION OUTPUT ;
    USE SIGNAL ;
    ANTENNAGATEAREA 0.434700 ;
    ANTENNADIFFAREA 1.137600 ;
    PORT
      LAYER met2 ;
        RECT 233.770 0.000 234.050 0.280 ;
    END
  END s0_axi_wstrb_1
  PIN s0_axi_wstrb_2
    DIRECTION OUTPUT ;
    USE SIGNAL ;
    ANTENNAGATEAREA 0.434700 ;
    ANTENNADIFFAREA 1.137600 ;
    PORT
      LAYER met2 ;
        RECT 415.010 519.840 415.290 520.120 ;
    END
  END s0_axi_wstrb_2
  PIN s0_axi_wstrb_3
    DIRECTION OUTPUT ;
    USE SIGNAL ;
    ANTENNAGATEAREA 0.434700 ;
    ANTENNADIFFAREA 1.137600 ;
    PORT
      LAYER met2 ;
        RECT 62.650 519.840 62.930 520.120 ;
    END
  END s0_axi_wstrb_3
  PIN s0_axi_wvalid
    DIRECTION OUTPUT ;
    USE SIGNAL ;
    ANTENNAGATEAREA 0.434700 ;
    ANTENNADIFFAREA 1.137600 ;
    PORT
      LAYER met3 ;
        RECT 0.000 156.440 0.600 157.040 ;
    END
  END s0_axi_wvalid
  PIN s1_axi_araddr_0
    DIRECTION OUTPUT ;
    USE SIGNAL ;
    ANTENNAGATEAREA 0.434700 ;
    ANTENNADIFFAREA 1.137600 ;
    PORT
      LAYER met2 ;
        RECT 354.290 0.000 354.570 0.280 ;
    END
  END s1_axi_araddr_0
  PIN s1_axi_araddr_1
    DIRECTION OUTPUT ;
    USE SIGNAL ;
    ANTENNAGATEAREA 0.434700 ;
    ANTENNADIFFAREA 1.137600 ;
    PORT
      LAYER met2 ;
        RECT 406.730 519.840 407.010 520.120 ;
    END
  END s1_axi_araddr_1
  PIN s1_axi_araddr_10
    DIRECTION OUTPUT ;
    USE SIGNAL ;
    ANTENNAGATEAREA 0.434700 ;
    ANTENNADIFFAREA 1.137600 ;
    PORT
      LAYER met2 ;
        RECT 213.530 519.840 213.810 520.120 ;
    END
  END s1_axi_araddr_10
  PIN s1_axi_araddr_11
    DIRECTION OUTPUT ;
    USE SIGNAL ;
    ANTENNAGATEAREA 0.434700 ;
    ANTENNADIFFAREA 1.137600 ;
    PORT
      LAYER met2 ;
        RECT 315.650 519.840 315.930 520.120 ;
    END
  END s1_axi_araddr_11
  PIN s1_axi_araddr_12
    DIRECTION OUTPUT ;
    USE SIGNAL ;
    ANTENNAGATEAREA 0.434700 ;
    ANTENNADIFFAREA 1.137600 ;
    PORT
      LAYER met2 ;
        RECT 86.570 519.840 86.850 520.120 ;
    END
  END s1_axi_araddr_12
  PIN s1_axi_araddr_13
    DIRECTION OUTPUT ;
    USE SIGNAL ;
    ANTENNAGATEAREA 0.434700 ;
    ANTENNADIFFAREA 1.137600 ;
    PORT
      LAYER met2 ;
        RECT 300.010 0.000 300.290 0.280 ;
    END
  END s1_axi_araddr_13
  PIN s1_axi_araddr_14
    DIRECTION OUTPUT ;
    USE SIGNAL ;
    ANTENNAGATEAREA 0.434700 ;
    ANTENNADIFFAREA 1.137600 ;
    PORT
      LAYER met2 ;
        RECT 229.170 0.000 229.450 0.280 ;
    END
  END s1_axi_araddr_14
  PIN s1_axi_araddr_15
    DIRECTION OUTPUT ;
    USE SIGNAL ;
    ANTENNAGATEAREA 0.434700 ;
    ANTENNADIFFAREA 1.137600 ;
    PORT
      LAYER met2 ;
        RECT 121.530 519.840 121.810 520.120 ;
    END
  END s1_axi_araddr_15
  PIN s1_axi_araddr_16
    DIRECTION OUTPUT ;
    USE SIGNAL ;
    ANTENNAGATEAREA 0.434700 ;
    ANTENNADIFFAREA 1.137600 ;
    PORT
      LAYER met2 ;
        RECT 182.250 519.840 182.530 520.120 ;
    END
  END s1_axi_araddr_16
  PIN s1_axi_araddr_17
    DIRECTION OUTPUT ;
    USE SIGNAL ;
    ANTENNAGATEAREA 0.434700 ;
    ANTENNADIFFAREA 1.137600 ;
    PORT
      LAYER met2 ;
        RECT 375.450 0.000 375.730 0.280 ;
    END
  END s1_axi_araddr_17
  PIN s1_axi_araddr_18
    DIRECTION OUTPUT ;
    USE SIGNAL ;
    ANTENNAGATEAREA 0.434700 ;
    ANTENNADIFFAREA 1.137600 ;
    PORT
      LAYER met2 ;
        RECT 241.130 0.000 241.410 0.280 ;
    END
  END s1_axi_araddr_18
  PIN s1_axi_araddr_19
    DIRECTION OUTPUT ;
    USE SIGNAL ;
    ANTENNAGATEAREA 0.434700 ;
    ANTENNADIFFAREA 1.137600 ;
    PORT
      LAYER met3 ;
        RECT 0.000 58.520 0.600 59.120 ;
    END
  END s1_axi_araddr_19
  PIN s1_axi_araddr_2
    DIRECTION OUTPUT ;
    USE SIGNAL ;
    ANTENNAGATEAREA 0.434700 ;
    ANTENNADIFFAREA 1.137600 ;
    PORT
      LAYER met2 ;
        RECT 214.450 0.000 214.730 0.280 ;
    END
  END s1_axi_araddr_2
  PIN s1_axi_araddr_20
    DIRECTION OUTPUT ;
    USE SIGNAL ;
    ANTENNAGATEAREA 0.434700 ;
    ANTENNADIFFAREA 1.137600 ;
    PORT
      LAYER met3 ;
        RECT 0.000 393.080 0.600 393.680 ;
    END
  END s1_axi_araddr_20
  PIN s1_axi_araddr_21
    DIRECTION OUTPUT ;
    USE SIGNAL ;
    ANTENNAGATEAREA 0.434700 ;
    ANTENNADIFFAREA 1.137600 ;
    PORT
      LAYER met2 ;
        RECT 183.170 519.840 183.450 520.120 ;
    END
  END s1_axi_araddr_21
  PIN s1_axi_araddr_22
    DIRECTION OUTPUT ;
    USE SIGNAL ;
    ANTENNAGATEAREA 0.434700 ;
    ANTENNADIFFAREA 1.137600 ;
    PORT
      LAYER met2 ;
        RECT 332.210 519.840 332.490 520.120 ;
    END
  END s1_axi_araddr_22
  PIN s1_axi_araddr_23
    DIRECTION OUTPUT ;
    USE SIGNAL ;
    ANTENNAGATEAREA 0.434700 ;
    ANTENNADIFFAREA 1.137600 ;
    PORT
      LAYER met2 ;
        RECT 253.090 0.000 253.370 0.280 ;
    END
  END s1_axi_araddr_23
  PIN s1_axi_araddr_24
    DIRECTION OUTPUT ;
    USE SIGNAL ;
    ANTENNAGATEAREA 0.434700 ;
    ANTENNADIFFAREA 1.137600 ;
    PORT
      LAYER met2 ;
        RECT 155.570 519.840 155.850 520.120 ;
    END
  END s1_axi_araddr_24
  PIN s1_axi_araddr_25
    DIRECTION OUTPUT ;
    USE SIGNAL ;
    ANTENNAGATEAREA 0.434700 ;
    ANTENNADIFFAREA 1.137600 ;
    PORT
      LAYER met2 ;
        RECT 49.770 519.840 50.050 520.120 ;
    END
  END s1_axi_araddr_25
  PIN s1_axi_araddr_26
    DIRECTION OUTPUT ;
    USE SIGNAL ;
    ANTENNAGATEAREA 0.434700 ;
    ANTENNADIFFAREA 1.137600 ;
    PORT
      LAYER met2 ;
        RECT 224.570 0.000 224.850 0.280 ;
    END
  END s1_axi_araddr_26
  PIN s1_axi_araddr_27
    DIRECTION OUTPUT ;
    USE SIGNAL ;
    ANTENNAGATEAREA 0.434700 ;
    ANTENNADIFFAREA 1.137600 ;
    PORT
      LAYER met2 ;
        RECT 400.290 519.840 400.570 520.120 ;
    END
  END s1_axi_araddr_27
  PIN s1_axi_araddr_28
    DIRECTION OUTPUT ;
    USE SIGNAL ;
    ANTENNAGATEAREA 0.434700 ;
    ANTENNADIFFAREA 1.137600 ;
    PORT
      LAYER met2 ;
        RECT 190.530 0.000 190.810 0.280 ;
    END
  END s1_axi_araddr_28
  PIN s1_axi_araddr_29
    DIRECTION OUTPUT ;
    USE SIGNAL ;
    ANTENNAGATEAREA 0.434700 ;
    ANTENNADIFFAREA 1.137600 ;
    PORT
      LAYER met2 ;
        RECT 81.970 519.840 82.250 520.120 ;
    END
  END s1_axi_araddr_29
  PIN s1_axi_araddr_3
    DIRECTION OUTPUT ;
    USE SIGNAL ;
    ANTENNAGATEAREA 0.434700 ;
    ANTENNADIFFAREA 1.137600 ;
    PORT
      LAYER met2 ;
        RECT 205.250 0.000 205.530 0.280 ;
    END
  END s1_axi_araddr_3
  PIN s1_axi_araddr_30
    DIRECTION OUTPUT ;
    USE SIGNAL ;
    ANTENNAGATEAREA 0.434700 ;
    ANTENNADIFFAREA 1.137600 ;
    PORT
      LAYER met2 ;
        RECT 69.090 519.840 69.370 520.120 ;
    END
  END s1_axi_araddr_30
  PIN s1_axi_araddr_31
    DIRECTION OUTPUT ;
    USE SIGNAL ;
    ANTENNAGATEAREA 0.434700 ;
    ANTENNADIFFAREA 1.137600 ;
    PORT
      LAYER met2 ;
        RECT 162.010 519.840 162.290 520.120 ;
    END
  END s1_axi_araddr_31
  PIN s1_axi_araddr_4
    DIRECTION OUTPUT ;
    USE SIGNAL ;
    ANTENNAGATEAREA 0.434700 ;
    ANTENNADIFFAREA 1.137600 ;
    PORT
      LAYER met2 ;
        RECT 311.970 519.840 312.250 520.120 ;
    END
  END s1_axi_araddr_4
  PIN s1_axi_araddr_5
    DIRECTION OUTPUT ;
    USE SIGNAL ;
    ANTENNAGATEAREA 0.434700 ;
    ANTENNADIFFAREA 1.137600 ;
    PORT
      LAYER met2 ;
        RECT 383.730 519.840 384.010 520.120 ;
    END
  END s1_axi_araddr_5
  PIN s1_axi_araddr_6
    DIRECTION OUTPUT ;
    USE SIGNAL ;
    ANTENNAGATEAREA 0.434700 ;
    ANTENNADIFFAREA 1.137600 ;
    PORT
      LAYER met2 ;
        RECT 309.210 0.000 309.490 0.280 ;
    END
  END s1_axi_araddr_6
  PIN s1_axi_araddr_7
    DIRECTION OUTPUT ;
    USE SIGNAL ;
    ANTENNAGATEAREA 0.434700 ;
    ANTENNADIFFAREA 1.137600 ;
    PORT
      LAYER met2 ;
        RECT 189.610 0.000 189.890 0.280 ;
    END
  END s1_axi_araddr_7
  PIN s1_axi_araddr_8
    DIRECTION OUTPUT ;
    USE SIGNAL ;
    ANTENNAGATEAREA 0.434700 ;
    ANTENNADIFFAREA 1.137600 ;
    PORT
      LAYER met2 ;
        RECT 201.570 0.000 201.850 0.280 ;
    END
  END s1_axi_araddr_8
  PIN s1_axi_araddr_9
    DIRECTION OUTPUT ;
    USE SIGNAL ;
    ANTENNAGATEAREA 0.434700 ;
    ANTENNADIFFAREA 1.137600 ;
    PORT
      LAYER met2 ;
        RECT 451.810 519.840 452.090 520.120 ;
    END
  END s1_axi_araddr_9
  PIN s1_axi_arready
    DIRECTION INPUT ;
    USE SIGNAL ;
    ANTENNAGATEAREA 0.647700 ;
    ANTENNADIFFAREA 0.434700 ;
    PORT
      LAYER met2 ;
        RECT 286.210 519.840 286.490 520.120 ;
    END
  END s1_axi_arready
  PIN s1_axi_arvalid
    DIRECTION OUTPUT ;
    USE SIGNAL ;
    ANTENNAGATEAREA 0.434700 ;
    ANTENNADIFFAREA 0.775300 ;
    PORT
      LAYER met3 ;
        RECT 508.800 409.400 509.400 410.000 ;
    END
  END s1_axi_arvalid
  PIN s1_axi_awaddr_0
    DIRECTION OUTPUT ;
    USE SIGNAL ;
    ANTENNAGATEAREA 0.434700 ;
    ANTENNADIFFAREA 1.137600 ;
    PORT
      LAYER met2 ;
        RECT 438.930 0.000 439.210 0.280 ;
    END
  END s1_axi_awaddr_0
  PIN s1_axi_awaddr_1
    DIRECTION OUTPUT ;
    USE SIGNAL ;
    ANTENNAGATEAREA 0.434700 ;
    ANTENNADIFFAREA 1.137600 ;
    PORT
      LAYER met2 ;
        RECT 273.330 0.000 273.610 0.280 ;
    END
  END s1_axi_awaddr_1
  PIN s1_axi_awaddr_10
    DIRECTION OUTPUT ;
    USE SIGNAL ;
    ANTENNAGATEAREA 0.434700 ;
    ANTENNADIFFAREA 1.137600 ;
    PORT
      LAYER met2 ;
        RECT 342.330 0.000 342.610 0.280 ;
    END
  END s1_axi_awaddr_10
  PIN s1_axi_awaddr_11
    DIRECTION OUTPUT ;
    USE SIGNAL ;
    ANTENNAGATEAREA 0.434700 ;
    ANTENNADIFFAREA 1.137600 ;
    PORT
      LAYER met2 ;
        RECT 317.490 0.000 317.770 0.280 ;
    END
  END s1_axi_awaddr_11
  PIN s1_axi_awaddr_12
    DIRECTION OUTPUT ;
    USE SIGNAL ;
    ANTENNAGATEAREA 0.434700 ;
    ANTENNADIFFAREA 1.137600 ;
    PORT
      LAYER met2 ;
        RECT 271.490 519.840 271.770 520.120 ;
    END
  END s1_axi_awaddr_12
  PIN s1_axi_awaddr_13
    DIRECTION OUTPUT ;
    USE SIGNAL ;
    ANTENNAGATEAREA 0.434700 ;
    ANTENNADIFFAREA 1.137600 ;
    PORT
      LAYER met2 ;
        RECT 303.690 0.000 303.970 0.280 ;
    END
  END s1_axi_awaddr_13
  PIN s1_axi_awaddr_14
    DIRECTION OUTPUT ;
    USE SIGNAL ;
    ANTENNAGATEAREA 0.434700 ;
    ANTENNADIFFAREA 1.137600 ;
    PORT
      LAYER met2 ;
        RECT 398.450 0.000 398.730 0.280 ;
    END
  END s1_axi_awaddr_14
  PIN s1_axi_awaddr_15
    DIRECTION OUTPUT ;
    USE SIGNAL ;
    ANTENNAGATEAREA 0.434700 ;
    ANTENNADIFFAREA 1.137600 ;
    PORT
      LAYER met2 ;
        RECT 132.570 519.840 132.850 520.120 ;
    END
  END s1_axi_awaddr_15
  PIN s1_axi_awaddr_16
    DIRECTION OUTPUT ;
    USE SIGNAL ;
    ANTENNAGATEAREA 0.434700 ;
    ANTENNADIFFAREA 1.137600 ;
    PORT
      LAYER met2 ;
        RECT 312.890 0.000 313.170 0.280 ;
    END
  END s1_axi_awaddr_16
  PIN s1_axi_awaddr_17
    DIRECTION OUTPUT ;
    USE SIGNAL ;
    ANTENNAGATEAREA 0.434700 ;
    ANTENNADIFFAREA 1.137600 ;
    PORT
      LAYER met2 ;
        RECT 359.810 519.840 360.090 520.120 ;
    END
  END s1_axi_awaddr_17
  PIN s1_axi_awaddr_18
    DIRECTION OUTPUT ;
    USE SIGNAL ;
    ANTENNAGATEAREA 0.434700 ;
    ANTENNADIFFAREA 1.137600 ;
    PORT
      LAYER met2 ;
        RECT 334.050 519.840 334.330 520.120 ;
    END
  END s1_axi_awaddr_18
  PIN s1_axi_awaddr_19
    DIRECTION OUTPUT ;
    USE SIGNAL ;
    ANTENNAGATEAREA 0.434700 ;
    ANTENNADIFFAREA 1.137600 ;
    PORT
      LAYER met3 ;
        RECT 508.800 457.000 509.400 457.600 ;
    END
  END s1_axi_awaddr_19
  PIN s1_axi_awaddr_2
    DIRECTION OUTPUT ;
    USE SIGNAL ;
    ANTENNAGATEAREA 0.434700 ;
    ANTENNADIFFAREA 1.137600 ;
    PORT
      LAYER met2 ;
        RECT 254.930 0.000 255.210 0.280 ;
    END
  END s1_axi_awaddr_2
  PIN s1_axi_awaddr_20
    DIRECTION OUTPUT ;
    USE SIGNAL ;
    ANTENNAGATEAREA 0.434700 ;
    ANTENNADIFFAREA 1.137600 ;
    PORT
      LAYER met2 ;
        RECT 208.010 0.000 208.290 0.280 ;
    END
  END s1_axi_awaddr_20
  PIN s1_axi_awaddr_21
    DIRECTION OUTPUT ;
    USE SIGNAL ;
    ANTENNAGATEAREA 0.434700 ;
    ANTENNADIFFAREA 1.137600 ;
    PORT
      LAYER met3 ;
        RECT 0.000 414.840 0.600 415.440 ;
    END
  END s1_axi_awaddr_21
  PIN s1_axi_awaddr_22
    DIRECTION OUTPUT ;
    USE SIGNAL ;
    ANTENNAGATEAREA 0.434700 ;
    ANTENNADIFFAREA 1.137600 ;
    PORT
      LAYER met2 ;
        RECT 474.810 0.000 475.090 0.280 ;
    END
  END s1_axi_awaddr_22
  PIN s1_axi_awaddr_23
    DIRECTION OUTPUT ;
    USE SIGNAL ;
    ANTENNAGATEAREA 0.434700 ;
    ANTENNADIFFAREA 1.137600 ;
    PORT
      LAYER met2 ;
        RECT 349.690 519.840 349.970 520.120 ;
    END
  END s1_axi_awaddr_23
  PIN s1_axi_awaddr_24
    DIRECTION OUTPUT ;
    USE SIGNAL ;
    ANTENNAGATEAREA 0.434700 ;
    ANTENNADIFFAREA 1.137600 ;
    PORT
      LAYER met2 ;
        RECT 173.970 519.840 174.250 520.120 ;
    END
  END s1_axi_awaddr_24
  PIN s1_axi_awaddr_25
    DIRECTION OUTPUT ;
    USE SIGNAL ;
    ANTENNAGATEAREA 0.434700 ;
    ANTENNADIFFAREA 1.137600 ;
    PORT
      LAYER met2 ;
        RECT 239.290 0.000 239.570 0.280 ;
    END
  END s1_axi_awaddr_25
  PIN s1_axi_awaddr_26
    DIRECTION OUTPUT ;
    USE SIGNAL ;
    ANTENNAGATEAREA 0.434700 ;
    ANTENNADIFFAREA 1.137600 ;
    PORT
      LAYER met2 ;
        RECT 140.850 519.840 141.130 520.120 ;
    END
  END s1_axi_awaddr_26
  PIN s1_axi_awaddr_27
    DIRECTION OUTPUT ;
    USE SIGNAL ;
    ANTENNAGATEAREA 0.434700 ;
    ANTENNADIFFAREA 1.137600 ;
    PORT
      LAYER met2 ;
        RECT 337.730 0.000 338.010 0.280 ;
    END
  END s1_axi_awaddr_27
  PIN s1_axi_awaddr_28
    DIRECTION OUTPUT ;
    USE SIGNAL ;
    ANTENNAGATEAREA 0.434700 ;
    ANTENNADIFFAREA 1.137600 ;
    PORT
      LAYER met2 ;
        RECT 225.490 0.000 225.770 0.280 ;
    END
  END s1_axi_awaddr_28
  PIN s1_axi_awaddr_29
    DIRECTION OUTPUT ;
    USE SIGNAL ;
    ANTENNAGATEAREA 0.434700 ;
    ANTENNADIFFAREA 1.137600 ;
    PORT
      LAYER met2 ;
        RECT 391.090 519.840 391.370 520.120 ;
    END
  END s1_axi_awaddr_29
  PIN s1_axi_awaddr_3
    DIRECTION OUTPUT ;
    USE SIGNAL ;
    ANTENNAGATEAREA 0.434700 ;
    ANTENNADIFFAREA 1.137600 ;
    PORT
      LAYER met2 ;
        RECT 218.130 0.000 218.410 0.280 ;
    END
  END s1_axi_awaddr_3
  PIN s1_axi_awaddr_30
    DIRECTION OUTPUT ;
    USE SIGNAL ;
    ANTENNAGATEAREA 0.434700 ;
    ANTENNADIFFAREA 1.137600 ;
    PORT
      LAYER met2 ;
        RECT 262.290 0.000 262.570 0.280 ;
    END
  END s1_axi_awaddr_30
  PIN s1_axi_awaddr_31
    DIRECTION OUTPUT ;
    USE SIGNAL ;
    ANTENNAGATEAREA 0.434700 ;
    ANTENNADIFFAREA 1.137600 ;
    PORT
      LAYER met2 ;
        RECT 268.730 519.840 269.010 520.120 ;
    END
  END s1_axi_awaddr_31
  PIN s1_axi_awaddr_4
    DIRECTION OUTPUT ;
    USE SIGNAL ;
    ANTENNAGATEAREA 0.434700 ;
    ANTENNADIFFAREA 1.137600 ;
    PORT
      LAYER met2 ;
        RECT 343.250 519.840 343.530 520.120 ;
    END
  END s1_axi_awaddr_4
  PIN s1_axi_awaddr_5
    DIRECTION OUTPUT ;
    USE SIGNAL ;
    ANTENNAGATEAREA 0.434700 ;
    ANTENNADIFFAREA 1.137600 ;
    PORT
      LAYER met2 ;
        RECT 291.730 0.000 292.010 0.280 ;
    END
  END s1_axi_awaddr_5
  PIN s1_axi_awaddr_6
    DIRECTION OUTPUT ;
    USE SIGNAL ;
    ANTENNAGATEAREA 0.434700 ;
    ANTENNADIFFAREA 1.137600 ;
    PORT
      LAYER met2 ;
        RECT 296.330 0.000 296.610 0.280 ;
    END
  END s1_axi_awaddr_6
  PIN s1_axi_awaddr_7
    DIRECTION OUTPUT ;
    USE SIGNAL ;
    ANTENNAGATEAREA 0.434700 ;
    ANTENNADIFFAREA 1.137600 ;
    PORT
      LAYER met2 ;
        RECT 220.890 0.000 221.170 0.280 ;
    END
  END s1_axi_awaddr_7
  PIN s1_axi_awaddr_8
    DIRECTION OUTPUT ;
    USE SIGNAL ;
    ANTENNAGATEAREA 0.434700 ;
    ANTENNADIFFAREA 1.137600 ;
    PORT
      LAYER met2 ;
        RECT 244.810 0.000 245.090 0.280 ;
    END
  END s1_axi_awaddr_8
  PIN s1_axi_awaddr_9
    DIRECTION OUTPUT ;
    USE SIGNAL ;
    ANTENNAGATEAREA 0.434700 ;
    ANTENNADIFFAREA 1.137600 ;
    PORT
      LAYER met3 ;
        RECT 508.800 436.600 509.400 437.200 ;
    END
  END s1_axi_awaddr_9
  PIN s1_axi_awready
    DIRECTION INPUT ;
    USE SIGNAL ;
    ANTENNAGATEAREA 0.647700 ;
    ANTENNADIFFAREA 0.434700 ;
    PORT
      LAYER met3 ;
        RECT 0.000 330.520 0.600 331.120 ;
    END
  END s1_axi_awready
  PIN s1_axi_awvalid
    DIRECTION OUTPUT ;
    USE SIGNAL ;
    ANTENNAGATEAREA 0.434700 ;
    ANTENNADIFFAREA 0.775300 ;
    PORT
      LAYER met3 ;
        RECT 508.800 493.720 509.400 494.320 ;
    END
  END s1_axi_awvalid
  PIN s1_axi_bready
    DIRECTION OUTPUT ;
    USE SIGNAL ;
    ANTENNAGATEAREA 0.434700 ;
    ANTENNADIFFAREA 0.775300 ;
    PORT
      LAYER met3 ;
        RECT 508.800 477.400 509.400 478.000 ;
    END
  END s1_axi_bready
  PIN s1_axi_bresp_0
    DIRECTION INPUT ;
    USE SIGNAL ;
    ANTENNAGATEAREA 0.647700 ;
    ANTENNADIFFAREA 0.434700 ;
    PORT
      LAYER met3 ;
        RECT 0.000 304.680 0.600 305.280 ;
    END
  END s1_axi_bresp_0
  PIN s1_axi_bresp_1
    DIRECTION INPUT ;
    USE SIGNAL ;
    ANTENNAGATEAREA 0.647700 ;
    ANTENNADIFFAREA 0.434700 ;
    PORT
      LAYER met3 ;
        RECT 0.000 308.760 0.600 309.360 ;
    END
  END s1_axi_bresp_1
  PIN s1_axi_bvalid
    DIRECTION INPUT ;
    USE SIGNAL ;
    ANTENNAGATEAREA 0.647700 ;
    ANTENNADIFFAREA 0.434700 ;
    PORT
      LAYER met3 ;
        RECT 0.000 342.760 0.600 343.360 ;
    END
  END s1_axi_bvalid
  PIN s1_axi_rdata_0
    DIRECTION INPUT ;
    USE SIGNAL ;
    ANTENNAGATEAREA 0.647700 ;
    ANTENNADIFFAREA 0.434700 ;
    PORT
      LAYER met3 ;
        RECT 508.800 221.720 509.400 222.320 ;
    END
  END s1_axi_rdata_0
  PIN s1_axi_rdata_1
    DIRECTION INPUT ;
    USE SIGNAL ;
    ANTENNAGATEAREA 0.647700 ;
    ANTENNADIFFAREA 0.434700 ;
    PORT
      LAYER met2 ;
        RECT 292.650 519.840 292.930 520.120 ;
    END
  END s1_axi_rdata_1
  PIN s1_axi_rdata_10
    DIRECTION INPUT ;
    USE SIGNAL ;
    ANTENNAGATEAREA 0.647700 ;
    ANTENNADIFFAREA 0.434700 ;
    PORT
      LAYER met3 ;
        RECT 508.800 440.680 509.400 441.280 ;
    END
  END s1_axi_rdata_10
  PIN s1_axi_rdata_11
    DIRECTION INPUT ;
    USE SIGNAL ;
    ANTENNAGATEAREA 0.647700 ;
    ANTENNADIFFAREA 0.434700 ;
    PORT
      LAYER met2 ;
        RECT 285.290 0.000 285.570 0.280 ;
    END
  END s1_axi_rdata_11
  PIN s1_axi_rdata_12
    DIRECTION INPUT ;
    USE SIGNAL ;
    ANTENNAGATEAREA 0.647700 ;
    ANTENNADIFFAREA 0.434700 ;
    PORT
      LAYER met3 ;
        RECT 508.800 134.680 509.400 135.280 ;
    END
  END s1_axi_rdata_12
  PIN s1_axi_rdata_13
    DIRECTION INPUT ;
    USE SIGNAL ;
    ANTENNAGATEAREA 0.647700 ;
    ANTENNADIFFAREA 0.434700 ;
    PORT
      LAYER met3 ;
        RECT 508.800 227.160 509.400 227.760 ;
    END
  END s1_axi_rdata_13
  PIN s1_axi_rdata_14
    DIRECTION INPUT ;
    USE SIGNAL ;
    ANTENNAGATEAREA 0.647700 ;
    ANTENNADIFFAREA 0.434700 ;
    PORT
      LAYER met3 ;
        RECT 508.800 315.560 509.400 316.160 ;
    END
  END s1_axi_rdata_14
  PIN s1_axi_rdata_15
    DIRECTION INPUT ;
    USE SIGNAL ;
    ANTENNAGATEAREA 0.647700 ;
    ANTENNADIFFAREA 0.434700 ;
    PORT
      LAYER met3 ;
        RECT 508.800 78.920 509.400 79.520 ;
    END
  END s1_axi_rdata_15
  PIN s1_axi_rdata_16
    DIRECTION INPUT ;
    USE SIGNAL ;
    ANTENNAGATEAREA 0.647700 ;
    ANTENNADIFFAREA 0.434700 ;
    PORT
      LAYER met3 ;
        RECT 508.800 117.000 509.400 117.600 ;
    END
  END s1_axi_rdata_16
  PIN s1_axi_rdata_17
    DIRECTION INPUT ;
    USE SIGNAL ;
    ANTENNAGATEAREA 0.647700 ;
    ANTENNADIFFAREA 0.434700 ;
    PORT
      LAYER met3 ;
        RECT 508.800 371.320 509.400 371.920 ;
    END
  END s1_axi_rdata_17
  PIN s1_axi_rdata_18
    DIRECTION INPUT ;
    USE SIGNAL ;
    ANTENNAGATEAREA 0.647700 ;
    ANTENNADIFFAREA 0.434700 ;
    PORT
      LAYER met2 ;
        RECT 280.690 0.000 280.970 0.280 ;
    END
  END s1_axi_rdata_18
  PIN s1_axi_rdata_19
    DIRECTION INPUT ;
    USE SIGNAL ;
    ANTENNAGATEAREA 0.647700 ;
    ANTENNADIFFAREA 0.434700 ;
    PORT
      LAYER met3 ;
        RECT 508.800 308.760 509.400 309.360 ;
    END
  END s1_axi_rdata_19
  PIN s1_axi_rdata_2
    DIRECTION INPUT ;
    USE SIGNAL ;
    ANTENNAGATEAREA 0.647700 ;
    ANTENNADIFFAREA 0.434700 ;
    PORT
      LAYER met3 ;
        RECT 508.800 87.080 509.400 87.680 ;
    END
  END s1_axi_rdata_2
  PIN s1_axi_rdata_20
    DIRECTION INPUT ;
    USE SIGNAL ;
    ANTENNAGATEAREA 0.647700 ;
    ANTENNADIFFAREA 0.434700 ;
    PORT
      LAYER met3 ;
        RECT 508.800 58.520 509.400 59.120 ;
    END
  END s1_axi_rdata_20
  PIN s1_axi_rdata_21
    DIRECTION INPUT ;
    USE SIGNAL ;
    ANTENNAGATEAREA 0.647700 ;
    ANTENNADIFFAREA 0.434700 ;
    PORT
      LAYER met3 ;
        RECT 508.800 394.440 509.400 395.040 ;
    END
  END s1_axi_rdata_21
  PIN s1_axi_rdata_22
    DIRECTION INPUT ;
    USE SIGNAL ;
    ANTENNAGATEAREA 0.647700 ;
    ANTENNADIFFAREA 0.434700 ;
    PORT
      LAYER met3 ;
        RECT 508.800 262.520 509.400 263.120 ;
    END
  END s1_axi_rdata_22
  PIN s1_axi_rdata_23
    DIRECTION INPUT ;
    USE SIGNAL ;
    ANTENNAGATEAREA 0.647700 ;
    ANTENNADIFFAREA 0.434700 ;
    PORT
      LAYER met3 ;
        RECT 508.800 178.200 509.400 178.800 ;
    END
  END s1_axi_rdata_23
  PIN s1_axi_rdata_24
    DIRECTION INPUT ;
    USE SIGNAL ;
    ANTENNAGATEAREA 0.647700 ;
    ANTENNADIFFAREA 0.434700 ;
    PORT
      LAYER met2 ;
        RECT 288.970 0.000 289.250 0.280 ;
    END
  END s1_axi_rdata_24
  PIN s1_axi_rdata_25
    DIRECTION INPUT ;
    USE SIGNAL ;
    ANTENNAGATEAREA 0.647700 ;
    ANTENNADIFFAREA 0.434700 ;
    PORT
      LAYER met3 ;
        RECT 508.800 476.040 509.400 476.640 ;
    END
  END s1_axi_rdata_25
  PIN s1_axi_rdata_26
    DIRECTION INPUT ;
    USE SIGNAL ;
    ANTENNAGATEAREA 0.647700 ;
    ANTENNADIFFAREA 0.434700 ;
    PORT
      LAYER met3 ;
        RECT 508.800 168.680 509.400 169.280 ;
    END
  END s1_axi_rdata_26
  PIN s1_axi_rdata_27
    DIRECTION INPUT ;
    USE SIGNAL ;
    ANTENNAGATEAREA 0.647700 ;
    ANTENNADIFFAREA 0.434700 ;
    PORT
      LAYER met3 ;
        RECT 508.800 219.000 509.400 219.600 ;
    END
  END s1_axi_rdata_27
  PIN s1_axi_rdata_28
    DIRECTION INPUT ;
    USE SIGNAL ;
    ANTENNAGATEAREA 0.647700 ;
    ANTENNADIFFAREA 0.434700 ;
    PORT
      LAYER met3 ;
        RECT 508.800 136.040 509.400 136.640 ;
    END
  END s1_axi_rdata_28
  PIN s1_axi_rdata_29
    DIRECTION INPUT ;
    USE SIGNAL ;
    ANTENNAGATEAREA 0.647700 ;
    ANTENNADIFFAREA 0.434700 ;
    PORT
      LAYER met3 ;
        RECT 508.800 293.800 509.400 294.400 ;
    END
  END s1_axi_rdata_29
  PIN s1_axi_rdata_3
    DIRECTION INPUT ;
    USE SIGNAL ;
    ANTENNAGATEAREA 0.647700 ;
    ANTENNADIFFAREA 0.434700 ;
    PORT
      LAYER met3 ;
        RECT 508.800 480.120 509.400 480.720 ;
    END
  END s1_axi_rdata_3
  PIN s1_axi_rdata_30
    DIRECTION INPUT ;
    USE SIGNAL ;
    ANTENNAGATEAREA 0.647700 ;
    ANTENNADIFFAREA 0.434700 ;
    PORT
      LAYER met3 ;
        RECT 508.800 119.720 509.400 120.320 ;
    END
  END s1_axi_rdata_30
  PIN s1_axi_rdata_31
    DIRECTION INPUT ;
    USE SIGNAL ;
    ANTENNAGATEAREA 0.647700 ;
    ANTENNADIFFAREA 0.434700 ;
    PORT
      LAYER met3 ;
        RECT 508.800 363.160 509.400 363.760 ;
    END
  END s1_axi_rdata_31
  PIN s1_axi_rdata_4
    DIRECTION INPUT ;
    USE SIGNAL ;
    ANTENNAGATEAREA 0.647700 ;
    ANTENNADIFFAREA 0.434700 ;
    PORT
      LAYER met2 ;
        RECT 283.450 519.840 283.730 520.120 ;
    END
  END s1_axi_rdata_4
  PIN s1_axi_rdata_5
    DIRECTION INPUT ;
    USE SIGNAL ;
    ANTENNAGATEAREA 0.647700 ;
    ANTENNADIFFAREA 0.434700 ;
    PORT
      LAYER met3 ;
        RECT 508.800 233.960 509.400 234.560 ;
    END
  END s1_axi_rdata_5
  PIN s1_axi_rdata_6
    DIRECTION INPUT ;
    USE SIGNAL ;
    ANTENNAGATEAREA 0.647700 ;
    ANTENNADIFFAREA 0.434700 ;
    PORT
      LAYER met3 ;
        RECT 508.800 387.640 509.400 388.240 ;
    END
  END s1_axi_rdata_6
  PIN s1_axi_rdata_7
    DIRECTION INPUT ;
    USE SIGNAL ;
    ANTENNAGATEAREA 0.647700 ;
    ANTENNADIFFAREA 0.434700 ;
    PORT
      LAYER met3 ;
        RECT 508.800 386.280 509.400 386.880 ;
    END
  END s1_axi_rdata_7
  PIN s1_axi_rdata_8
    DIRECTION INPUT ;
    USE SIGNAL ;
    ANTENNAGATEAREA 0.647700 ;
    ANTENNADIFFAREA 0.434700 ;
    PORT
      LAYER met3 ;
        RECT 508.800 504.600 509.400 505.200 ;
    END
  END s1_axi_rdata_8
  PIN s1_axi_rdata_9
    DIRECTION INPUT ;
    USE SIGNAL ;
    ANTENNAGATEAREA 0.647700 ;
    ANTENNADIFFAREA 0.434700 ;
    PORT
      LAYER met3 ;
        RECT 508.800 258.440 509.400 259.040 ;
    END
  END s1_axi_rdata_9
  PIN s1_axi_rready
    DIRECTION OUTPUT ;
    USE SIGNAL ;
    ANTENNAGATEAREA 0.434700 ;
    ANTENNADIFFAREA 0.775300 ;
    PORT
      LAYER met3 ;
        RECT 508.800 410.760 509.400 411.360 ;
    END
  END s1_axi_rready
  PIN s1_axi_rresp_0
    DIRECTION INPUT ;
    USE SIGNAL ;
    ANTENNAGATEAREA 0.647700 ;
    ANTENNADIFFAREA 0.434700 ;
    PORT
      LAYER met3 ;
        RECT 508.800 352.280 509.400 352.880 ;
    END
  END s1_axi_rresp_0
  PIN s1_axi_rresp_1
    DIRECTION INPUT ;
    USE SIGNAL ;
    ANTENNAGATEAREA 0.647700 ;
    ANTENNADIFFAREA 0.434700 ;
    PORT
      LAYER met3 ;
        RECT 508.800 133.320 509.400 133.920 ;
    END
  END s1_axi_rresp_1
  PIN s1_axi_rvalid
    DIRECTION INPUT ;
    USE SIGNAL ;
    ANTENNAGATEAREA 0.647700 ;
    ANTENNADIFFAREA 0.434700 ;
    PORT
      LAYER met3 ;
        RECT 508.800 374.040 509.400 374.640 ;
    END
  END s1_axi_rvalid
  PIN s1_axi_wdata_0
    DIRECTION OUTPUT ;
    USE SIGNAL ;
    ANTENNAGATEAREA 0.434700 ;
    ANTENNADIFFAREA 1.137600 ;
    PORT
      LAYER met2 ;
        RECT 186.850 0.000 187.130 0.280 ;
    END
  END s1_axi_wdata_0
  PIN s1_axi_wdata_1
    DIRECTION OUTPUT ;
    USE SIGNAL ;
    ANTENNAGATEAREA 0.434700 ;
    ANTENNADIFFAREA 1.137600 ;
    PORT
      LAYER met2 ;
        RECT 276.090 0.000 276.370 0.280 ;
    END
  END s1_axi_wdata_1
  PIN s1_axi_wdata_10
    DIRECTION OUTPUT ;
    USE SIGNAL ;
    ANTENNAGATEAREA 0.434700 ;
    ANTENNADIFFAREA 1.137600 ;
    PORT
      LAYER met2 ;
        RECT 175.810 519.840 176.090 520.120 ;
    END
  END s1_axi_wdata_10
  PIN s1_axi_wdata_11
    DIRECTION OUTPUT ;
    USE SIGNAL ;
    ANTENNAGATEAREA 0.434700 ;
    ANTENNADIFFAREA 1.137600 ;
    PORT
      LAYER met2 ;
        RECT 117.850 519.840 118.130 520.120 ;
    END
  END s1_axi_wdata_11
  PIN s1_axi_wdata_12
    DIRECTION OUTPUT ;
    USE SIGNAL ;
    ANTENNAGATEAREA 0.434700 ;
    ANTENNADIFFAREA 1.137600 ;
    PORT
      LAYER met3 ;
        RECT 0.000 91.160 0.600 91.760 ;
    END
  END s1_axi_wdata_12
  PIN s1_axi_wdata_13
    DIRECTION OUTPUT ;
    USE SIGNAL ;
    ANTENNAGATEAREA 0.434700 ;
    ANTENNADIFFAREA 1.137600 ;
    PORT
      LAYER met2 ;
        RECT 230.090 519.840 230.370 520.120 ;
    END
  END s1_axi_wdata_13
  PIN s1_axi_wdata_14
    DIRECTION OUTPUT ;
    USE SIGNAL ;
    ANTENNAGATEAREA 0.434700 ;
    ANTENNADIFFAREA 1.137600 ;
    PORT
      LAYER met2 ;
        RECT 374.530 519.840 374.810 520.120 ;
    END
  END s1_axi_wdata_14
  PIN s1_axi_wdata_15
    DIRECTION OUTPUT ;
    USE SIGNAL ;
    ANTENNAGATEAREA 0.434700 ;
    ANTENNADIFFAREA 1.137600 ;
    PORT
      LAYER met2 ;
        RECT 110.490 519.840 110.770 520.120 ;
    END
  END s1_axi_wdata_15
  PIN s1_axi_wdata_16
    DIRECTION OUTPUT ;
    USE SIGNAL ;
    ANTENNAGATEAREA 0.434700 ;
    ANTENNADIFFAREA 1.137600 ;
    PORT
      LAYER met3 ;
        RECT 0.000 378.120 0.600 378.720 ;
    END
  END s1_axi_wdata_16
  PIN s1_axi_wdata_17
    DIRECTION OUTPUT ;
    USE SIGNAL ;
    ANTENNAGATEAREA 0.434700 ;
    ANTENNADIFFAREA 1.137600 ;
    PORT
      LAYER met2 ;
        RECT 165.690 519.840 165.970 520.120 ;
    END
  END s1_axi_wdata_17
  PIN s1_axi_wdata_18
    DIRECTION OUTPUT ;
    USE SIGNAL ;
    ANTENNAGATEAREA 0.434700 ;
    ANTENNADIFFAREA 1.137600 ;
    PORT
      LAYER met2 ;
        RECT 329.450 0.000 329.730 0.280 ;
    END
  END s1_axi_wdata_18
  PIN s1_axi_wdata_19
    DIRECTION OUTPUT ;
    USE SIGNAL ;
    ANTENNAGATEAREA 0.434700 ;
    ANTENNADIFFAREA 1.137600 ;
    PORT
      LAYER met2 ;
        RECT 236.530 519.840 236.810 520.120 ;
    END
  END s1_axi_wdata_19
  PIN s1_axi_wdata_2
    DIRECTION OUTPUT ;
    USE SIGNAL ;
    ANTENNAGATEAREA 0.434700 ;
    ANTENNADIFFAREA 1.137600 ;
    PORT
      LAYER met2 ;
        RECT 204.330 519.840 204.610 520.120 ;
    END
  END s1_axi_wdata_2
  PIN s1_axi_wdata_20
    DIRECTION OUTPUT ;
    USE SIGNAL ;
    ANTENNAGATEAREA 0.434700 ;
    ANTENNADIFFAREA 1.137600 ;
    PORT
      LAYER met2 ;
        RECT 282.530 0.000 282.810 0.280 ;
    END
  END s1_axi_wdata_20
  PIN s1_axi_wdata_21
    DIRECTION OUTPUT ;
    USE SIGNAL ;
    ANTENNAGATEAREA 0.434700 ;
    ANTENNADIFFAREA 1.137600 ;
    PORT
      LAYER met2 ;
        RECT 97.610 519.840 97.890 520.120 ;
    END
  END s1_axi_wdata_21
  PIN s1_axi_wdata_22
    DIRECTION OUTPUT ;
    USE SIGNAL ;
    ANTENNAGATEAREA 0.434700 ;
    ANTENNADIFFAREA 1.137600 ;
    PORT
      LAYER met2 ;
        RECT 428.810 519.840 429.090 520.120 ;
    END
  END s1_axi_wdata_22
  PIN s1_axi_wdata_23
    DIRECTION OUTPUT ;
    USE SIGNAL ;
    ANTENNAGATEAREA 0.434700 ;
    ANTENNADIFFAREA 1.137600 ;
    PORT
      LAYER met3 ;
        RECT 0.000 382.200 0.600 382.800 ;
    END
  END s1_axi_wdata_23
  PIN s1_axi_wdata_24
    DIRECTION OUTPUT ;
    USE SIGNAL ;
    ANTENNAGATEAREA 0.434700 ;
    ANTENNADIFFAREA 1.137600 ;
    PORT
      LAYER met2 ;
        RECT 231.930 0.000 232.210 0.280 ;
    END
  END s1_axi_wdata_24
  PIN s1_axi_wdata_25
    DIRECTION OUTPUT ;
    USE SIGNAL ;
    ANTENNAGATEAREA 0.434700 ;
    ANTENNADIFFAREA 1.137600 ;
    PORT
      LAYER met2 ;
        RECT 54.370 519.840 54.650 520.120 ;
    END
  END s1_axi_wdata_25
  PIN s1_axi_wdata_26
    DIRECTION OUTPUT ;
    USE SIGNAL ;
    ANTENNAGATEAREA 0.434700 ;
    ANTENNADIFFAREA 1.137600 ;
    PORT
      LAYER met2 ;
        RECT 219.970 0.000 220.250 0.280 ;
    END
  END s1_axi_wdata_26
  PIN s1_axi_wdata_27
    DIRECTION OUTPUT ;
    USE SIGNAL ;
    ANTENNAGATEAREA 0.434700 ;
    ANTENNADIFFAREA 1.137600 ;
    PORT
      LAYER met2 ;
        RECT 128.890 519.840 129.170 520.120 ;
    END
  END s1_axi_wdata_27
  PIN s1_axi_wdata_28
    DIRECTION OUTPUT ;
    USE SIGNAL ;
    ANTENNAGATEAREA 0.434700 ;
    ANTENNADIFFAREA 1.137600 ;
    PORT
      LAYER met2 ;
        RECT 224.570 519.840 224.850 520.120 ;
    END
  END s1_axi_wdata_28
  PIN s1_axi_wdata_29
    DIRECTION OUTPUT ;
    USE SIGNAL ;
    ANTENNAGATEAREA 0.434700 ;
    ANTENNADIFFAREA 1.137600 ;
    PORT
      LAYER met2 ;
        RECT 454.570 0.000 454.850 0.280 ;
    END
  END s1_axi_wdata_29
  PIN s1_axi_wdata_3
    DIRECTION OUTPUT ;
    USE SIGNAL ;
    ANTENNAGATEAREA 0.434700 ;
    ANTENNADIFFAREA 1.137600 ;
    PORT
      LAYER met2 ;
        RECT 103.130 519.840 103.410 520.120 ;
    END
  END s1_axi_wdata_3
  PIN s1_axi_wdata_30
    DIRECTION OUTPUT ;
    USE SIGNAL ;
    ANTENNAGATEAREA 0.434700 ;
    ANTENNADIFFAREA 1.137600 ;
    PORT
      LAYER met2 ;
        RECT 266.890 0.000 267.170 0.280 ;
    END
  END s1_axi_wdata_30
  PIN s1_axi_wdata_31
    DIRECTION OUTPUT ;
    USE SIGNAL ;
    ANTENNAGATEAREA 0.434700 ;
    ANTENNADIFFAREA 1.137600 ;
    PORT
      LAYER met2 ;
        RECT 277.930 519.840 278.210 520.120 ;
    END
  END s1_axi_wdata_31
  PIN s1_axi_wdata_4
    DIRECTION OUTPUT ;
    USE SIGNAL ;
    ANTENNAGATEAREA 0.434700 ;
    ANTENNADIFFAREA 1.137600 ;
    PORT
      LAYER met3 ;
        RECT 0.000 76.200 0.600 76.800 ;
    END
  END s1_axi_wdata_4
  PIN s1_axi_wdata_5
    DIRECTION OUTPUT ;
    USE SIGNAL ;
    ANTENNAGATEAREA 0.434700 ;
    ANTENNADIFFAREA 1.137600 ;
    PORT
      LAYER met3 ;
        RECT 0.000 359.080 0.600 359.680 ;
    END
  END s1_axi_wdata_5
  PIN s1_axi_wdata_6
    DIRECTION OUTPUT ;
    USE SIGNAL ;
    ANTENNAGATEAREA 0.434700 ;
    ANTENNADIFFAREA 1.137600 ;
    PORT
      LAYER met2 ;
        RECT 496.890 0.000 497.170 0.280 ;
    END
  END s1_axi_wdata_6
  PIN s1_axi_wdata_7
    DIRECTION OUTPUT ;
    USE SIGNAL ;
    ANTENNAGATEAREA 0.434700 ;
    ANTENNADIFFAREA 1.137600 ;
    PORT
      LAYER met2 ;
        RECT 372.690 519.840 372.970 520.120 ;
    END
  END s1_axi_wdata_7
  PIN s1_axi_wdata_8
    DIRECTION OUTPUT ;
    USE SIGNAL ;
    ANTENNAGATEAREA 0.434700 ;
    ANTENNADIFFAREA 1.137600 ;
    PORT
      LAYER met2 ;
        RECT 422.370 0.000 422.650 0.280 ;
    END
  END s1_axi_wdata_8
  PIN s1_axi_wdata_9
    DIRECTION OUTPUT ;
    USE SIGNAL ;
    ANTENNAGATEAREA 0.434700 ;
    ANTENNADIFFAREA 1.137600 ;
    PORT
      LAYER met3 ;
        RECT 508.800 470.600 509.400 471.200 ;
    END
  END s1_axi_wdata_9
  PIN s1_axi_wready
    DIRECTION INPUT ;
    USE SIGNAL ;
    ANTENNAGATEAREA 0.647700 ;
    ANTENNADIFFAREA 0.434700 ;
    PORT
      LAYER met3 ;
        RECT 0.000 349.560 0.600 350.160 ;
    END
  END s1_axi_wready
  PIN s1_axi_wstrb_0
    DIRECTION OUTPUT ;
    USE SIGNAL ;
    ANTENNAGATEAREA 0.434700 ;
    ANTENNADIFFAREA 1.137600 ;
    PORT
      LAYER met2 ;
        RECT 264.130 519.840 264.410 520.120 ;
    END
  END s1_axi_wstrb_0
  PIN s1_axi_wstrb_1
    DIRECTION OUTPUT ;
    USE SIGNAL ;
    ANTENNAGATEAREA 0.434700 ;
    ANTENNADIFFAREA 1.137600 ;
    PORT
      LAYER met2 ;
        RECT 234.690 0.000 234.970 0.280 ;
    END
  END s1_axi_wstrb_1
  PIN s1_axi_wstrb_2
    DIRECTION OUTPUT ;
    USE SIGNAL ;
    ANTENNAGATEAREA 0.434700 ;
    ANTENNADIFFAREA 1.137600 ;
    PORT
      LAYER met2 ;
        RECT 418.690 519.840 418.970 520.120 ;
    END
  END s1_axi_wstrb_2
  PIN s1_axi_wstrb_3
    DIRECTION OUTPUT ;
    USE SIGNAL ;
    ANTENNAGATEAREA 0.434700 ;
    ANTENNADIFFAREA 1.137600 ;
    PORT
      LAYER met2 ;
        RECT 60.810 519.840 61.090 520.120 ;
    END
  END s1_axi_wstrb_3
  PIN s1_axi_wvalid
    DIRECTION OUTPUT ;
    USE SIGNAL ;
    ANTENNAGATEAREA 0.434700 ;
    ANTENNADIFFAREA 0.775300 ;
    PORT
      LAYER met3 ;
        RECT 508.800 452.920 509.400 453.520 ;
    END
  END s1_axi_wvalid
  PIN s2_axi_araddr_0
    DIRECTION OUTPUT ;
    USE SIGNAL ;
    ANTENNAGATEAREA 0.434700 ;
    ANTENNADIFFAREA 1.137600 ;
    PORT
      LAYER met2 ;
        RECT 353.370 0.000 353.650 0.280 ;
    END
  END s2_axi_araddr_0
  PIN s2_axi_araddr_1
    DIRECTION OUTPUT ;
    USE SIGNAL ;
    ANTENNAGATEAREA 0.434700 ;
    ANTENNADIFFAREA 1.137600 ;
    PORT
      LAYER met2 ;
        RECT 403.970 519.840 404.250 520.120 ;
    END
  END s2_axi_araddr_1
  PIN s2_axi_araddr_10
    DIRECTION OUTPUT ;
    USE SIGNAL ;
    ANTENNAGATEAREA 0.434700 ;
    ANTENNADIFFAREA 1.137600 ;
    PORT
      LAYER met2 ;
        RECT 202.490 519.840 202.770 520.120 ;
    END
  END s2_axi_araddr_10
  PIN s2_axi_araddr_11
    DIRECTION OUTPUT ;
    USE SIGNAL ;
    ANTENNAGATEAREA 0.434700 ;
    ANTENNADIFFAREA 1.137600 ;
    PORT
      LAYER met2 ;
        RECT 317.490 519.840 317.770 520.120 ;
    END
  END s2_axi_araddr_11
  PIN s2_axi_araddr_12
    DIRECTION OUTPUT ;
    USE SIGNAL ;
    ANTENNAGATEAREA 0.434700 ;
    ANTENNADIFFAREA 1.137600 ;
    PORT
      LAYER met2 ;
        RECT 87.490 519.840 87.770 520.120 ;
    END
  END s2_axi_araddr_12
  PIN s2_axi_araddr_13
    DIRECTION OUTPUT ;
    USE SIGNAL ;
    ANTENNAGATEAREA 0.434700 ;
    ANTENNADIFFAREA 1.137600 ;
    PORT
      LAYER met2 ;
        RECT 299.090 0.000 299.370 0.280 ;
    END
  END s2_axi_araddr_13
  PIN s2_axi_araddr_14
    DIRECTION OUTPUT ;
    USE SIGNAL ;
    ANTENNAGATEAREA 0.434700 ;
    ANTENNADIFFAREA 1.137600 ;
    PORT
      LAYER met2 ;
        RECT 228.250 0.000 228.530 0.280 ;
    END
  END s2_axi_araddr_14
  PIN s2_axi_araddr_15
    DIRECTION OUTPUT ;
    USE SIGNAL ;
    ANTENNAGATEAREA 0.434700 ;
    ANTENNADIFFAREA 1.137600 ;
    PORT
      LAYER met2 ;
        RECT 116.930 519.840 117.210 520.120 ;
    END
  END s2_axi_araddr_15
  PIN s2_axi_araddr_16
    DIRECTION OUTPUT ;
    USE SIGNAL ;
    ANTENNAGATEAREA 0.434700 ;
    ANTENNADIFFAREA 1.137600 ;
    PORT
      LAYER met2 ;
        RECT 178.570 519.840 178.850 520.120 ;
    END
  END s2_axi_araddr_16
  PIN s2_axi_araddr_17
    DIRECTION OUTPUT ;
    USE SIGNAL ;
    ANTENNAGATEAREA 0.434700 ;
    ANTENNADIFFAREA 1.137600 ;
    PORT
      LAYER met2 ;
        RECT 415.930 0.000 416.210 0.280 ;
    END
  END s2_axi_araddr_17
  PIN s2_axi_araddr_18
    DIRECTION OUTPUT ;
    USE SIGNAL ;
    ANTENNAGATEAREA 0.434700 ;
    ANTENNADIFFAREA 1.137600 ;
    PORT
      LAYER met2 ;
        RECT 240.210 0.000 240.490 0.280 ;
    END
  END s2_axi_araddr_18
  PIN s2_axi_araddr_19
    DIRECTION OUTPUT ;
    USE SIGNAL ;
    ANTENNAGATEAREA 0.434700 ;
    ANTENNADIFFAREA 1.137600 ;
    PORT
      LAYER met3 ;
        RECT 0.000 55.800 0.600 56.400 ;
    END
  END s2_axi_araddr_19
  PIN s2_axi_araddr_2
    DIRECTION OUTPUT ;
    USE SIGNAL ;
    ANTENNAGATEAREA 0.434700 ;
    ANTENNADIFFAREA 1.137600 ;
    PORT
      LAYER met2 ;
        RECT 213.530 0.000 213.810 0.280 ;
    END
  END s2_axi_araddr_2
  PIN s2_axi_araddr_20
    DIRECTION OUTPUT ;
    USE SIGNAL ;
    ANTENNAGATEAREA 0.434700 ;
    ANTENNADIFFAREA 1.137600 ;
    PORT
      LAYER met3 ;
        RECT 0.000 384.920 0.600 385.520 ;
    END
  END s2_axi_araddr_20
  PIN s2_axi_araddr_21
    DIRECTION OUTPUT ;
    USE SIGNAL ;
    ANTENNAGATEAREA 0.434700 ;
    ANTENNADIFFAREA 1.137600 ;
    PORT
      LAYER met2 ;
        RECT 179.490 519.840 179.770 520.120 ;
    END
  END s2_axi_araddr_21
  PIN s2_axi_araddr_22
    DIRECTION OUTPUT ;
    USE SIGNAL ;
    ANTENNAGATEAREA 0.434700 ;
    ANTENNADIFFAREA 1.137600 ;
    PORT
      LAYER met2 ;
        RECT 330.370 519.840 330.650 520.120 ;
    END
  END s2_axi_araddr_22
  PIN s2_axi_araddr_23
    DIRECTION OUTPUT ;
    USE SIGNAL ;
    ANTENNAGATEAREA 0.434700 ;
    ANTENNADIFFAREA 1.137600 ;
    PORT
      LAYER met2 ;
        RECT 251.250 0.000 251.530 0.280 ;
    END
  END s2_axi_araddr_23
  PIN s2_axi_araddr_24
    DIRECTION OUTPUT ;
    USE SIGNAL ;
    ANTENNAGATEAREA 0.434700 ;
    ANTENNADIFFAREA 1.137600 ;
    PORT
      LAYER met2 ;
        RECT 150.050 519.840 150.330 520.120 ;
    END
  END s2_axi_araddr_24
  PIN s2_axi_araddr_25
    DIRECTION OUTPUT ;
    USE SIGNAL ;
    ANTENNAGATEAREA 0.434700 ;
    ANTENNADIFFAREA 1.137600 ;
    PORT
      LAYER met2 ;
        RECT 47.930 519.840 48.210 520.120 ;
    END
  END s2_axi_araddr_25
  PIN s2_axi_araddr_26
    DIRECTION OUTPUT ;
    USE SIGNAL ;
    ANTENNAGATEAREA 0.434700 ;
    ANTENNADIFFAREA 1.137600 ;
    PORT
      LAYER met2 ;
        RECT 216.290 0.000 216.570 0.280 ;
    END
  END s2_axi_araddr_26
  PIN s2_axi_araddr_27
    DIRECTION OUTPUT ;
    USE SIGNAL ;
    ANTENNAGATEAREA 0.434700 ;
    ANTENNADIFFAREA 1.137600 ;
    PORT
      LAYER met2 ;
        RECT 399.370 519.840 399.650 520.120 ;
    END
  END s2_axi_araddr_27
  PIN s2_axi_araddr_28
    DIRECTION OUTPUT ;
    USE SIGNAL ;
    ANTENNAGATEAREA 0.434700 ;
    ANTENNADIFFAREA 1.137600 ;
    PORT
      LAYER met2 ;
        RECT 194.210 0.000 194.490 0.280 ;
    END
  END s2_axi_araddr_28
  PIN s2_axi_araddr_29
    DIRECTION OUTPUT ;
    USE SIGNAL ;
    ANTENNAGATEAREA 0.434700 ;
    ANTENNADIFFAREA 1.137600 ;
    PORT
      LAYER met2 ;
        RECT 99.450 519.840 99.730 520.120 ;
    END
  END s2_axi_araddr_29
  PIN s2_axi_araddr_3
    DIRECTION OUTPUT ;
    USE SIGNAL ;
    ANTENNAGATEAREA 0.434700 ;
    ANTENNADIFFAREA 1.137600 ;
    PORT
      LAYER met2 ;
        RECT 206.170 0.000 206.450 0.280 ;
    END
  END s2_axi_araddr_3
  PIN s2_axi_araddr_30
    DIRECTION OUTPUT ;
    USE SIGNAL ;
    ANTENNAGATEAREA 0.434700 ;
    ANTENNADIFFAREA 1.137600 ;
    PORT
      LAYER met2 ;
        RECT 71.850 519.840 72.130 520.120 ;
    END
  END s2_axi_araddr_30
  PIN s2_axi_araddr_31
    DIRECTION OUTPUT ;
    USE SIGNAL ;
    ANTENNAGATEAREA 0.434700 ;
    ANTENNADIFFAREA 1.137600 ;
    PORT
      LAYER met2 ;
        RECT 146.370 519.840 146.650 520.120 ;
    END
  END s2_axi_araddr_31
  PIN s2_axi_araddr_4
    DIRECTION OUTPUT ;
    USE SIGNAL ;
    ANTENNAGATEAREA 0.434700 ;
    ANTENNADIFFAREA 1.137600 ;
    PORT
      LAYER met2 ;
        RECT 314.730 519.840 315.010 520.120 ;
    END
  END s2_axi_araddr_4
  PIN s2_axi_araddr_5
    DIRECTION OUTPUT ;
    USE SIGNAL ;
    ANTENNAGATEAREA 0.434700 ;
    ANTENNADIFFAREA 1.137600 ;
    PORT
      LAYER met2 ;
        RECT 380.050 519.840 380.330 520.120 ;
    END
  END s2_axi_araddr_5
  PIN s2_axi_araddr_6
    DIRECTION OUTPUT ;
    USE SIGNAL ;
    ANTENNAGATEAREA 0.434700 ;
    ANTENNADIFFAREA 1.137600 ;
    PORT
      LAYER met2 ;
        RECT 308.290 0.000 308.570 0.280 ;
    END
  END s2_axi_araddr_6
  PIN s2_axi_araddr_7
    DIRECTION OUTPUT ;
    USE SIGNAL ;
    ANTENNAGATEAREA 0.434700 ;
    ANTENNADIFFAREA 1.137600 ;
    PORT
      LAYER met2 ;
        RECT 192.370 0.000 192.650 0.280 ;
    END
  END s2_axi_araddr_7
  PIN s2_axi_araddr_8
    DIRECTION OUTPUT ;
    USE SIGNAL ;
    ANTENNAGATEAREA 0.434700 ;
    ANTENNADIFFAREA 1.137600 ;
    PORT
      LAYER met2 ;
        RECT 193.290 0.000 193.570 0.280 ;
    END
  END s2_axi_araddr_8
  PIN s2_axi_araddr_9
    DIRECTION OUTPUT ;
    USE SIGNAL ;
    ANTENNAGATEAREA 0.434700 ;
    ANTENNADIFFAREA 1.137600 ;
    PORT
      LAYER met2 ;
        RECT 453.650 519.840 453.930 520.120 ;
    END
  END s2_axi_araddr_9
  PIN s2_axi_arready
    DIRECTION INPUT ;
    USE SIGNAL ;
    ANTENNAGATEAREA 0.647700 ;
    ANTENNADIFFAREA 0.434700 ;
    PORT
      LAYER met2 ;
        RECT 280.690 519.840 280.970 520.120 ;
    END
  END s2_axi_arready
  PIN s2_axi_arvalid
    DIRECTION OUTPUT ;
    USE SIGNAL ;
    ANTENNAGATEAREA 0.434700 ;
    ANTENNADIFFAREA 1.137600 ;
    PORT
      LAYER met2 ;
        RECT 216.290 519.840 216.570 520.120 ;
    END
  END s2_axi_arvalid
  PIN s2_axi_awaddr_0
    DIRECTION OUTPUT ;
    USE SIGNAL ;
    ANTENNAGATEAREA 0.434700 ;
    ANTENNADIFFAREA 1.137600 ;
    PORT
      LAYER met2 ;
        RECT 438.010 0.000 438.290 0.280 ;
    END
  END s2_axi_awaddr_0
  PIN s2_axi_awaddr_1
    DIRECTION OUTPUT ;
    USE SIGNAL ;
    ANTENNAGATEAREA 0.434700 ;
    ANTENNADIFFAREA 1.137600 ;
    PORT
      LAYER met2 ;
        RECT 272.410 0.000 272.690 0.280 ;
    END
  END s2_axi_awaddr_1
  PIN s2_axi_awaddr_10
    DIRECTION OUTPUT ;
    USE SIGNAL ;
    ANTENNAGATEAREA 0.434700 ;
    ANTENNADIFFAREA 1.137600 ;
    PORT
      LAYER met2 ;
        RECT 341.410 0.000 341.690 0.280 ;
    END
  END s2_axi_awaddr_10
  PIN s2_axi_awaddr_11
    DIRECTION OUTPUT ;
    USE SIGNAL ;
    ANTENNAGATEAREA 0.434700 ;
    ANTENNADIFFAREA 1.137600 ;
    PORT
      LAYER met2 ;
        RECT 319.330 0.000 319.610 0.280 ;
    END
  END s2_axi_awaddr_11
  PIN s2_axi_awaddr_12
    DIRECTION OUTPUT ;
    USE SIGNAL ;
    ANTENNAGATEAREA 0.434700 ;
    ANTENNADIFFAREA 1.137600 ;
    PORT
      LAYER met2 ;
        RECT 270.570 519.840 270.850 520.120 ;
    END
  END s2_axi_awaddr_12
  PIN s2_axi_awaddr_13
    DIRECTION OUTPUT ;
    USE SIGNAL ;
    ANTENNAGATEAREA 0.434700 ;
    ANTENNADIFFAREA 1.137600 ;
    PORT
      LAYER met2 ;
        RECT 305.530 0.000 305.810 0.280 ;
    END
  END s2_axi_awaddr_13
  PIN s2_axi_awaddr_14
    DIRECTION OUTPUT ;
    USE SIGNAL ;
    ANTENNAGATEAREA 0.434700 ;
    ANTENNADIFFAREA 1.137600 ;
    PORT
      LAYER met2 ;
        RECT 475.730 0.000 476.010 0.280 ;
    END
  END s2_axi_awaddr_14
  PIN s2_axi_awaddr_15
    DIRECTION OUTPUT ;
    USE SIGNAL ;
    ANTENNAGATEAREA 0.434700 ;
    ANTENNADIFFAREA 1.137600 ;
    PORT
      LAYER met2 ;
        RECT 123.370 519.840 123.650 520.120 ;
    END
  END s2_axi_awaddr_15
  PIN s2_axi_awaddr_16
    DIRECTION OUTPUT ;
    USE SIGNAL ;
    ANTENNAGATEAREA 0.434700 ;
    ANTENNADIFFAREA 1.137600 ;
    PORT
      LAYER met2 ;
        RECT 311.970 0.000 312.250 0.280 ;
    END
  END s2_axi_awaddr_16
  PIN s2_axi_awaddr_17
    DIRECTION OUTPUT ;
    USE SIGNAL ;
    ANTENNAGATEAREA 0.434700 ;
    ANTENNADIFFAREA 1.137600 ;
    PORT
      LAYER met2 ;
        RECT 355.210 519.840 355.490 520.120 ;
    END
  END s2_axi_awaddr_17
  PIN s2_axi_awaddr_18
    DIRECTION OUTPUT ;
    USE SIGNAL ;
    ANTENNAGATEAREA 0.434700 ;
    ANTENNADIFFAREA 1.137600 ;
    PORT
      LAYER met2 ;
        RECT 334.970 519.840 335.250 520.120 ;
    END
  END s2_axi_awaddr_18
  PIN s2_axi_awaddr_19
    DIRECTION OUTPUT ;
    USE SIGNAL ;
    ANTENNAGATEAREA 0.434700 ;
    ANTENNADIFFAREA 1.137600 ;
    PORT
      LAYER met3 ;
        RECT 508.800 442.040 509.400 442.640 ;
    END
  END s2_axi_awaddr_19
  PIN s2_axi_awaddr_2
    DIRECTION OUTPUT ;
    USE SIGNAL ;
    ANTENNAGATEAREA 0.434700 ;
    ANTENNADIFFAREA 1.137600 ;
    PORT
      LAYER met2 ;
        RECT 255.850 0.000 256.130 0.280 ;
    END
  END s2_axi_awaddr_2
  PIN s2_axi_awaddr_20
    DIRECTION OUTPUT ;
    USE SIGNAL ;
    ANTENNAGATEAREA 0.434700 ;
    ANTENNADIFFAREA 1.137600 ;
    PORT
      LAYER met2 ;
        RECT 223.650 0.000 223.930 0.280 ;
    END
  END s2_axi_awaddr_20
  PIN s2_axi_awaddr_21
    DIRECTION OUTPUT ;
    USE SIGNAL ;
    ANTENNAGATEAREA 0.434700 ;
    ANTENNADIFFAREA 1.137600 ;
    PORT
      LAYER met3 ;
        RECT 0.000 410.760 0.600 411.360 ;
    END
  END s2_axi_awaddr_21
  PIN s2_axi_awaddr_22
    DIRECTION OUTPUT ;
    USE SIGNAL ;
    ANTENNAGATEAREA 0.434700 ;
    ANTENNADIFFAREA 1.137600 ;
    PORT
      LAYER met2 ;
        RECT 430.650 0.000 430.930 0.280 ;
    END
  END s2_axi_awaddr_22
  PIN s2_axi_awaddr_23
    DIRECTION OUTPUT ;
    USE SIGNAL ;
    ANTENNAGATEAREA 0.434700 ;
    ANTENNADIFFAREA 1.137600 ;
    PORT
      LAYER met2 ;
        RECT 353.370 519.840 353.650 520.120 ;
    END
  END s2_axi_awaddr_23
  PIN s2_axi_awaddr_24
    DIRECTION OUTPUT ;
    USE SIGNAL ;
    ANTENNAGATEAREA 0.434700 ;
    ANTENNADIFFAREA 1.137600 ;
    PORT
      LAYER met2 ;
        RECT 154.650 519.840 154.930 520.120 ;
    END
  END s2_axi_awaddr_24
  PIN s2_axi_awaddr_25
    DIRECTION OUTPUT ;
    USE SIGNAL ;
    ANTENNAGATEAREA 0.434700 ;
    ANTENNADIFFAREA 1.137600 ;
    PORT
      LAYER met2 ;
        RECT 238.370 0.000 238.650 0.280 ;
    END
  END s2_axi_awaddr_25
  PIN s2_axi_awaddr_26
    DIRECTION OUTPUT ;
    USE SIGNAL ;
    ANTENNAGATEAREA 0.434700 ;
    ANTENNADIFFAREA 1.137600 ;
    PORT
      LAYER met2 ;
        RECT 201.570 519.840 201.850 520.120 ;
    END
  END s2_axi_awaddr_26
  PIN s2_axi_awaddr_27
    DIRECTION OUTPUT ;
    USE SIGNAL ;
    ANTENNAGATEAREA 0.434700 ;
    ANTENNADIFFAREA 1.137600 ;
    PORT
      LAYER met2 ;
        RECT 336.810 0.000 337.090 0.280 ;
    END
  END s2_axi_awaddr_27
  PIN s2_axi_awaddr_28
    DIRECTION OUTPUT ;
    USE SIGNAL ;
    ANTENNAGATEAREA 0.434700 ;
    ANTENNADIFFAREA 1.137600 ;
    PORT
      LAYER met2 ;
        RECT 215.370 0.000 215.650 0.280 ;
    END
  END s2_axi_awaddr_28
  PIN s2_axi_awaddr_29
    DIRECTION OUTPUT ;
    USE SIGNAL ;
    ANTENNAGATEAREA 0.434700 ;
    ANTENNADIFFAREA 1.137600 ;
    PORT
      LAYER met2 ;
        RECT 390.170 519.840 390.450 520.120 ;
    END
  END s2_axi_awaddr_29
  PIN s2_axi_awaddr_3
    DIRECTION OUTPUT ;
    USE SIGNAL ;
    ANTENNAGATEAREA 0.434700 ;
    ANTENNADIFFAREA 1.137600 ;
    PORT
      LAYER met2 ;
        RECT 196.970 0.000 197.250 0.280 ;
    END
  END s2_axi_awaddr_3
  PIN s2_axi_awaddr_30
    DIRECTION OUTPUT ;
    USE SIGNAL ;
    ANTENNAGATEAREA 0.434700 ;
    ANTENNADIFFAREA 1.137600 ;
    PORT
      LAYER met2 ;
        RECT 261.370 0.000 261.650 0.280 ;
    END
  END s2_axi_awaddr_30
  PIN s2_axi_awaddr_31
    DIRECTION OUTPUT ;
    USE SIGNAL ;
    ANTENNAGATEAREA 0.434700 ;
    ANTENNADIFFAREA 1.137600 ;
    PORT
      LAYER met2 ;
        RECT 269.650 519.840 269.930 520.120 ;
    END
  END s2_axi_awaddr_31
  PIN s2_axi_awaddr_4
    DIRECTION OUTPUT ;
    USE SIGNAL ;
    ANTENNAGATEAREA 0.434700 ;
    ANTENNADIFFAREA 1.137600 ;
    PORT
      LAYER met2 ;
        RECT 342.330 519.840 342.610 520.120 ;
    END
  END s2_axi_awaddr_4
  PIN s2_axi_awaddr_5
    DIRECTION OUTPUT ;
    USE SIGNAL ;
    ANTENNAGATEAREA 0.434700 ;
    ANTENNADIFFAREA 1.137600 ;
    PORT
      LAYER met2 ;
        RECT 289.890 0.000 290.170 0.280 ;
    END
  END s2_axi_awaddr_5
  PIN s2_axi_awaddr_6
    DIRECTION OUTPUT ;
    USE SIGNAL ;
    ANTENNAGATEAREA 0.434700 ;
    ANTENNADIFFAREA 1.137600 ;
    PORT
      LAYER met2 ;
        RECT 295.410 0.000 295.690 0.280 ;
    END
  END s2_axi_awaddr_6
  PIN s2_axi_awaddr_7
    DIRECTION OUTPUT ;
    USE SIGNAL ;
    ANTENNAGATEAREA 0.434700 ;
    ANTENNADIFFAREA 1.137600 ;
    PORT
      LAYER met2 ;
        RECT 197.890 0.000 198.170 0.280 ;
    END
  END s2_axi_awaddr_7
  PIN s2_axi_awaddr_8
    DIRECTION OUTPUT ;
    USE SIGNAL ;
    ANTENNAGATEAREA 0.434700 ;
    ANTENNADIFFAREA 1.137600 ;
    PORT
      LAYER met2 ;
        RECT 243.890 0.000 244.170 0.280 ;
    END
  END s2_axi_awaddr_8
  PIN s2_axi_awaddr_9
    DIRECTION OUTPUT ;
    USE SIGNAL ;
    ANTENNAGATEAREA 0.434700 ;
    ANTENNADIFFAREA 1.137600 ;
    PORT
      LAYER met3 ;
        RECT 508.800 499.160 509.400 499.760 ;
    END
  END s2_axi_awaddr_9
  PIN s2_axi_awready
    DIRECTION INPUT ;
    USE SIGNAL ;
    ANTENNAGATEAREA 0.647700 ;
    ANTENNADIFFAREA 0.434700 ;
    PORT
      LAYER met3 ;
        RECT 0.000 326.440 0.600 327.040 ;
    END
  END s2_axi_awready
  PIN s2_axi_awvalid
    DIRECTION OUTPUT ;
    USE SIGNAL ;
    ANTENNAGATEAREA 0.434700 ;
    ANTENNADIFFAREA 1.137600 ;
    PORT
      LAYER met3 ;
        RECT 0.000 142.840 0.600 143.440 ;
    END
  END s2_axi_awvalid
  PIN s2_axi_bready
    DIRECTION OUTPUT ;
    USE SIGNAL ;
    ANTENNAGATEAREA 0.434700 ;
    ANTENNADIFFAREA 1.137600 ;
    PORT
      LAYER met3 ;
        RECT 0.000 106.120 0.600 106.720 ;
    END
  END s2_axi_bready
  PIN s2_axi_bresp_0
    DIRECTION INPUT ;
    USE SIGNAL ;
    ANTENNAGATEAREA 0.647700 ;
    ANTENNADIFFAREA 0.434700 ;
    PORT
      LAYER met3 ;
        RECT 0.000 310.120 0.600 310.720 ;
    END
  END s2_axi_bresp_0
  PIN s2_axi_bresp_1
    DIRECTION INPUT ;
    USE SIGNAL ;
    ANTENNAGATEAREA 0.647700 ;
    ANTENNADIFFAREA 0.434700 ;
    PORT
      LAYER met3 ;
        RECT 0.000 318.280 0.600 318.880 ;
    END
  END s2_axi_bresp_1
  PIN s2_axi_bvalid
    DIRECTION INPUT ;
    USE SIGNAL ;
    ANTENNAGATEAREA 0.647700 ;
    ANTENNADIFFAREA 0.434700 ;
    PORT
      LAYER met3 ;
        RECT 0.000 345.480 0.600 346.080 ;
    END
  END s2_axi_bvalid
  PIN s2_axi_rdata_0
    DIRECTION INPUT ;
    USE SIGNAL ;
    ANTENNAGATEAREA 0.647700 ;
    ANTENNADIFFAREA 0.434700 ;
    PORT
      LAYER met3 ;
        RECT 508.800 213.560 509.400 214.160 ;
    END
  END s2_axi_rdata_0
  PIN s2_axi_rdata_1
    DIRECTION INPUT ;
    USE SIGNAL ;
    ANTENNAGATEAREA 0.647700 ;
    ANTENNADIFFAREA 0.434700 ;
    PORT
      LAYER met2 ;
        RECT 273.330 519.840 273.610 520.120 ;
    END
  END s2_axi_rdata_1
  PIN s2_axi_rdata_10
    DIRECTION INPUT ;
    USE SIGNAL ;
    ANTENNAGATEAREA 0.647700 ;
    ANTENNADIFFAREA 0.434700 ;
    PORT
      LAYER met3 ;
        RECT 508.800 299.240 509.400 299.840 ;
    END
  END s2_axi_rdata_10
  PIN s2_axi_rdata_11
    DIRECTION INPUT ;
    USE SIGNAL ;
    ANTENNAGATEAREA 0.647700 ;
    ANTENNADIFFAREA 0.434700 ;
    PORT
      LAYER met2 ;
        RECT 292.650 0.000 292.930 0.280 ;
    END
  END s2_axi_rdata_11
  PIN s2_axi_rdata_12
    DIRECTION INPUT ;
    USE SIGNAL ;
    ANTENNAGATEAREA 0.647700 ;
    ANTENNADIFFAREA 0.434700 ;
    PORT
      LAYER met2 ;
        RECT 324.850 0.000 325.130 0.280 ;
    END
  END s2_axi_rdata_12
  PIN s2_axi_rdata_13
    DIRECTION INPUT ;
    USE SIGNAL ;
    ANTENNAGATEAREA 0.647700 ;
    ANTENNADIFFAREA 0.434700 ;
    PORT
      LAYER met3 ;
        RECT 508.800 220.360 509.400 220.960 ;
    END
  END s2_axi_rdata_13
  PIN s2_axi_rdata_14
    DIRECTION INPUT ;
    USE SIGNAL ;
    ANTENNAGATEAREA 0.647700 ;
    ANTENNADIFFAREA 0.434700 ;
    PORT
      LAYER met3 ;
        RECT 508.800 491.000 509.400 491.600 ;
    END
  END s2_axi_rdata_14
  PIN s2_axi_rdata_15
    DIRECTION INPUT ;
    USE SIGNAL ;
    ANTENNAGATEAREA 0.647700 ;
    ANTENNADIFFAREA 0.434700 ;
    PORT
      LAYER met3 ;
        RECT 508.800 76.200 509.400 76.800 ;
    END
  END s2_axi_rdata_15
  PIN s2_axi_rdata_16
    DIRECTION INPUT ;
    USE SIGNAL ;
    ANTENNAGATEAREA 0.647700 ;
    ANTENNADIFFAREA 0.434700 ;
    PORT
      LAYER met3 ;
        RECT 508.800 138.760 509.400 139.360 ;
    END
  END s2_axi_rdata_16
  PIN s2_axi_rdata_17
    DIRECTION INPUT ;
    USE SIGNAL ;
    ANTENNAGATEAREA 0.647700 ;
    ANTENNADIFFAREA 0.434700 ;
    PORT
      LAYER met3 ;
        RECT 508.800 331.880 509.400 332.480 ;
    END
  END s2_axi_rdata_17
  PIN s2_axi_rdata_18
    DIRECTION INPUT ;
    USE SIGNAL ;
    ANTENNAGATEAREA 0.647700 ;
    ANTENNADIFFAREA 0.434700 ;
    PORT
      LAYER met2 ;
        RECT 287.130 0.000 287.410 0.280 ;
    END
  END s2_axi_rdata_18
  PIN s2_axi_rdata_19
    DIRECTION INPUT ;
    USE SIGNAL ;
    ANTENNAGATEAREA 0.647700 ;
    ANTENNADIFFAREA 0.434700 ;
    PORT
      LAYER met3 ;
        RECT 508.800 316.920 509.400 317.520 ;
    END
  END s2_axi_rdata_19
  PIN s2_axi_rdata_2
    DIRECTION INPUT ;
    USE SIGNAL ;
    ANTENNAGATEAREA 0.647700 ;
    ANTENNADIFFAREA 0.434700 ;
    PORT
      LAYER met3 ;
        RECT 508.800 85.720 509.400 86.320 ;
    END
  END s2_axi_rdata_2
  PIN s2_axi_rdata_20
    DIRECTION INPUT ;
    USE SIGNAL ;
    ANTENNAGATEAREA 0.647700 ;
    ANTENNADIFFAREA 0.434700 ;
    PORT
      LAYER met3 ;
        RECT 508.800 235.320 509.400 235.920 ;
    END
  END s2_axi_rdata_20
  PIN s2_axi_rdata_21
    DIRECTION INPUT ;
    USE SIGNAL ;
    ANTENNAGATEAREA 0.647700 ;
    ANTENNADIFFAREA 0.434700 ;
    PORT
      LAYER met3 ;
        RECT 508.800 361.800 509.400 362.400 ;
    END
  END s2_axi_rdata_21
  PIN s2_axi_rdata_22
    DIRECTION INPUT ;
    USE SIGNAL ;
    ANTENNAGATEAREA 0.647700 ;
    ANTENNADIFFAREA 0.434700 ;
    PORT
      LAYER met3 ;
        RECT 508.800 266.600 509.400 267.200 ;
    END
  END s2_axi_rdata_22
  PIN s2_axi_rdata_23
    DIRECTION INPUT ;
    USE SIGNAL ;
    ANTENNAGATEAREA 0.647700 ;
    ANTENNADIFFAREA 0.434700 ;
    PORT
      LAYER met3 ;
        RECT 508.800 176.840 509.400 177.440 ;
    END
  END s2_axi_rdata_23
  PIN s2_axi_rdata_24
    DIRECTION INPUT ;
    USE SIGNAL ;
    ANTENNAGATEAREA 0.647700 ;
    ANTENNADIFFAREA 0.434700 ;
    PORT
      LAYER met2 ;
        RECT 290.810 0.000 291.090 0.280 ;
    END
  END s2_axi_rdata_24
  PIN s2_axi_rdata_25
    DIRECTION INPUT ;
    USE SIGNAL ;
    ANTENNAGATEAREA 0.647700 ;
    ANTENNADIFFAREA 0.434700 ;
    PORT
      LAYER met3 ;
        RECT 508.800 413.480 509.400 414.080 ;
    END
  END s2_axi_rdata_25
  PIN s2_axi_rdata_26
    DIRECTION INPUT ;
    USE SIGNAL ;
    ANTENNAGATEAREA 0.647700 ;
    ANTENNADIFFAREA 0.434700 ;
    PORT
      LAYER met3 ;
        RECT 508.800 93.880 509.400 94.480 ;
    END
  END s2_axi_rdata_26
  PIN s2_axi_rdata_27
    DIRECTION INPUT ;
    USE SIGNAL ;
    ANTENNAGATEAREA 0.647700 ;
    ANTENNADIFFAREA 0.434700 ;
    PORT
      LAYER met3 ;
        RECT 508.800 225.800 509.400 226.400 ;
    END
  END s2_axi_rdata_27
  PIN s2_axi_rdata_28
    DIRECTION INPUT ;
    USE SIGNAL ;
    ANTENNAGATEAREA 0.647700 ;
    ANTENNADIFFAREA 0.434700 ;
    PORT
      LAYER met3 ;
        RECT 508.800 140.120 509.400 140.720 ;
    END
  END s2_axi_rdata_28
  PIN s2_axi_rdata_29
    DIRECTION INPUT ;
    USE SIGNAL ;
    ANTENNAGATEAREA 0.647700 ;
    ANTENNADIFFAREA 0.434700 ;
    PORT
      LAYER met3 ;
        RECT 508.800 329.160 509.400 329.760 ;
    END
  END s2_axi_rdata_29
  PIN s2_axi_rdata_3
    DIRECTION INPUT ;
    USE SIGNAL ;
    ANTENNAGATEAREA 0.647700 ;
    ANTENNADIFFAREA 0.434700 ;
    PORT
      LAYER met3 ;
        RECT 508.800 507.320 509.400 507.920 ;
    END
  END s2_axi_rdata_3
  PIN s2_axi_rdata_30
    DIRECTION INPUT ;
    USE SIGNAL ;
    ANTENNAGATEAREA 0.647700 ;
    ANTENNADIFFAREA 0.434700 ;
    PORT
      LAYER met3 ;
        RECT 508.800 142.840 509.400 143.440 ;
    END
  END s2_axi_rdata_30
  PIN s2_axi_rdata_31
    DIRECTION INPUT ;
    USE SIGNAL ;
    ANTENNAGATEAREA 0.647700 ;
    ANTENNADIFFAREA 0.434700 ;
    PORT
      LAYER met3 ;
        RECT 508.800 376.760 509.400 377.360 ;
    END
  END s2_axi_rdata_31
  PIN s2_axi_rdata_4
    DIRECTION INPUT ;
    USE SIGNAL ;
    ANTENNAGATEAREA 0.647700 ;
    ANTENNADIFFAREA 0.434700 ;
    PORT
      LAYER met2 ;
        RECT 287.130 519.840 287.410 520.120 ;
    END
  END s2_axi_rdata_4
  PIN s2_axi_rdata_5
    DIRECTION INPUT ;
    USE SIGNAL ;
    ANTENNAGATEAREA 0.647700 ;
    ANTENNADIFFAREA 0.434700 ;
    PORT
      LAYER met3 ;
        RECT 508.800 236.680 509.400 237.280 ;
    END
  END s2_axi_rdata_5
  PIN s2_axi_rdata_6
    DIRECTION INPUT ;
    USE SIGNAL ;
    ANTENNAGATEAREA 0.647700 ;
    ANTENNADIFFAREA 0.434700 ;
    PORT
      LAYER met3 ;
        RECT 508.800 368.600 509.400 369.200 ;
    END
  END s2_axi_rdata_6
  PIN s2_axi_rdata_7
    DIRECTION INPUT ;
    USE SIGNAL ;
    ANTENNAGATEAREA 0.647700 ;
    ANTENNADIFFAREA 0.434700 ;
    PORT
      LAYER met3 ;
        RECT 508.800 393.080 509.400 393.680 ;
    END
  END s2_axi_rdata_7
  PIN s2_axi_rdata_8
    DIRECTION INPUT ;
    USE SIGNAL ;
    ANTENNAGATEAREA 0.647700 ;
    ANTENNADIFFAREA 0.434700 ;
    PORT
      LAYER met3 ;
        RECT 508.800 307.400 509.400 308.000 ;
    END
  END s2_axi_rdata_8
  PIN s2_axi_rdata_9
    DIRECTION INPUT ;
    USE SIGNAL ;
    ANTENNAGATEAREA 0.647700 ;
    ANTENNADIFFAREA 0.434700 ;
    PORT
      LAYER met3 ;
        RECT 508.800 257.080 509.400 257.680 ;
    END
  END s2_axi_rdata_9
  PIN s2_axi_rready
    DIRECTION OUTPUT ;
    USE SIGNAL ;
    ANTENNAGATEAREA 0.434700 ;
    ANTENNADIFFAREA 1.137600 ;
    PORT
      LAYER met2 ;
        RECT 208.930 0.000 209.210 0.280 ;
    END
  END s2_axi_rready
  PIN s2_axi_rresp_0
    DIRECTION INPUT ;
    USE SIGNAL ;
    ANTENNAGATEAREA 0.647700 ;
    ANTENNADIFFAREA 0.434700 ;
    PORT
      LAYER met3 ;
        RECT 508.800 383.560 509.400 384.160 ;
    END
  END s2_axi_rresp_0
  PIN s2_axi_rresp_1
    DIRECTION INPUT ;
    USE SIGNAL ;
    ANTENNAGATEAREA 0.647700 ;
    ANTENNADIFFAREA 0.434700 ;
    PORT
      LAYER met3 ;
        RECT 508.800 141.480 509.400 142.080 ;
    END
  END s2_axi_rresp_1
  PIN s2_axi_rvalid
    DIRECTION INPUT ;
    USE SIGNAL ;
    ANTENNAGATEAREA 0.647700 ;
    ANTENNADIFFAREA 0.434700 ;
    PORT
      LAYER met3 ;
        RECT 508.800 345.480 509.400 346.080 ;
    END
  END s2_axi_rvalid
  PIN s2_axi_wdata_0
    DIRECTION OUTPUT ;
    USE SIGNAL ;
    ANTENNAGATEAREA 0.434700 ;
    ANTENNADIFFAREA 1.137600 ;
    PORT
      LAYER met2 ;
        RECT 202.490 0.000 202.770 0.280 ;
    END
  END s2_axi_wdata_0
  PIN s2_axi_wdata_1
    DIRECTION OUTPUT ;
    USE SIGNAL ;
    ANTENNAGATEAREA 0.434700 ;
    ANTENNADIFFAREA 1.137600 ;
    PORT
      LAYER met2 ;
        RECT 277.930 0.000 278.210 0.280 ;
    END
  END s2_axi_wdata_1
  PIN s2_axi_wdata_10
    DIRECTION OUTPUT ;
    USE SIGNAL ;
    ANTENNAGATEAREA 0.434700 ;
    ANTENNADIFFAREA 1.137600 ;
    PORT
      LAYER met2 ;
        RECT 191.450 519.840 191.730 520.120 ;
    END
  END s2_axi_wdata_10
  PIN s2_axi_wdata_11
    DIRECTION OUTPUT ;
    USE SIGNAL ;
    ANTENNAGATEAREA 0.434700 ;
    ANTENNADIFFAREA 1.137600 ;
    PORT
      LAYER met2 ;
        RECT 77.370 519.840 77.650 520.120 ;
    END
  END s2_axi_wdata_11
  PIN s2_axi_wdata_12
    DIRECTION OUTPUT ;
    USE SIGNAL ;
    ANTENNAGATEAREA 0.434700 ;
    ANTENNADIFFAREA 1.137600 ;
    PORT
      LAYER met3 ;
        RECT 0.000 83.000 0.600 83.600 ;
    END
  END s2_axi_wdata_12
  PIN s2_axi_wdata_13
    DIRECTION OUTPUT ;
    USE SIGNAL ;
    ANTENNAGATEAREA 0.434700 ;
    ANTENNADIFFAREA 1.137600 ;
    PORT
      LAYER met2 ;
        RECT 231.010 519.840 231.290 520.120 ;
    END
  END s2_axi_wdata_13
  PIN s2_axi_wdata_14
    DIRECTION OUTPUT ;
    USE SIGNAL ;
    ANTENNAGATEAREA 0.434700 ;
    ANTENNADIFFAREA 1.137600 ;
    PORT
      LAYER met2 ;
        RECT 363.490 519.840 363.770 520.120 ;
    END
  END s2_axi_wdata_14
  PIN s2_axi_wdata_15
    DIRECTION OUTPUT ;
    USE SIGNAL ;
    ANTENNAGATEAREA 0.434700 ;
    ANTENNADIFFAREA 1.137600 ;
    PORT
      LAYER met2 ;
        RECT 102.210 519.840 102.490 520.120 ;
    END
  END s2_axi_wdata_15
  PIN s2_axi_wdata_16
    DIRECTION OUTPUT ;
    USE SIGNAL ;
    ANTENNAGATEAREA 0.434700 ;
    ANTENNADIFFAREA 1.137600 ;
    PORT
      LAYER met3 ;
        RECT 0.000 401.240 0.600 401.840 ;
    END
  END s2_axi_wdata_16
  PIN s2_axi_wdata_17
    DIRECTION OUTPUT ;
    USE SIGNAL ;
    ANTENNAGATEAREA 0.434700 ;
    ANTENNADIFFAREA 1.137600 ;
    PORT
      LAYER met2 ;
        RECT 160.170 519.840 160.450 520.120 ;
    END
  END s2_axi_wdata_17
  PIN s2_axi_wdata_18
    DIRECTION OUTPUT ;
    USE SIGNAL ;
    ANTENNAGATEAREA 0.434700 ;
    ANTENNADIFFAREA 1.137600 ;
    PORT
      LAYER met2 ;
        RECT 328.530 0.000 328.810 0.280 ;
    END
  END s2_axi_wdata_18
  PIN s2_axi_wdata_19
    DIRECTION OUTPUT ;
    USE SIGNAL ;
    ANTENNAGATEAREA 0.434700 ;
    ANTENNADIFFAREA 1.137600 ;
    PORT
      LAYER met2 ;
        RECT 229.170 519.840 229.450 520.120 ;
    END
  END s2_axi_wdata_19
  PIN s2_axi_wdata_2
    DIRECTION OUTPUT ;
    USE SIGNAL ;
    ANTENNAGATEAREA 0.434700 ;
    ANTENNADIFFAREA 1.137600 ;
    PORT
      LAYER met2 ;
        RECT 207.090 519.840 207.370 520.120 ;
    END
  END s2_axi_wdata_2
  PIN s2_axi_wdata_20
    DIRECTION OUTPUT ;
    USE SIGNAL ;
    ANTENNAGATEAREA 0.434700 ;
    ANTENNADIFFAREA 1.137600 ;
    PORT
      LAYER met2 ;
        RECT 281.610 0.000 281.890 0.280 ;
    END
  END s2_axi_wdata_20
  PIN s2_axi_wdata_21
    DIRECTION OUTPUT ;
    USE SIGNAL ;
    ANTENNAGATEAREA 0.434700 ;
    ANTENNADIFFAREA 1.137600 ;
    PORT
      LAYER met2 ;
        RECT 83.810 519.840 84.090 520.120 ;
    END
  END s2_axi_wdata_21
  PIN s2_axi_wdata_22
    DIRECTION OUTPUT ;
    USE SIGNAL ;
    ANTENNAGATEAREA 0.434700 ;
    ANTENNADIFFAREA 1.137600 ;
    PORT
      LAYER met2 ;
        RECT 423.290 519.840 423.570 520.120 ;
    END
  END s2_axi_wdata_22
  PIN s2_axi_wdata_23
    DIRECTION OUTPUT ;
    USE SIGNAL ;
    ANTENNAGATEAREA 0.434700 ;
    ANTENNADIFFAREA 1.137600 ;
    PORT
      LAYER met3 ;
        RECT 0.000 380.840 0.600 381.440 ;
    END
  END s2_axi_wdata_23
  PIN s2_axi_wdata_24
    DIRECTION OUTPUT ;
    USE SIGNAL ;
    ANTENNAGATEAREA 0.434700 ;
    ANTENNADIFFAREA 1.137600 ;
    PORT
      LAYER met2 ;
        RECT 231.010 0.000 231.290 0.280 ;
    END
  END s2_axi_wdata_24
  PIN s2_axi_wdata_25
    DIRECTION OUTPUT ;
    USE SIGNAL ;
    ANTENNAGATEAREA 0.434700 ;
    ANTENNADIFFAREA 1.137600 ;
    PORT
      LAYER met2 ;
        RECT 58.050 519.840 58.330 520.120 ;
    END
  END s2_axi_wdata_25
  PIN s2_axi_wdata_26
    DIRECTION OUTPUT ;
    USE SIGNAL ;
    ANTENNAGATEAREA 0.434700 ;
    ANTENNADIFFAREA 1.137600 ;
    PORT
      LAYER met2 ;
        RECT 198.810 0.000 199.090 0.280 ;
    END
  END s2_axi_wdata_26
  PIN s2_axi_wdata_27
    DIRECTION OUTPUT ;
    USE SIGNAL ;
    ANTENNAGATEAREA 0.434700 ;
    ANTENNADIFFAREA 1.137600 ;
    PORT
      LAYER met2 ;
        RECT 112.330 519.840 112.610 520.120 ;
    END
  END s2_axi_wdata_27
  PIN s2_axi_wdata_28
    DIRECTION OUTPUT ;
    USE SIGNAL ;
    ANTENNAGATEAREA 0.434700 ;
    ANTENNADIFFAREA 1.137600 ;
    PORT
      LAYER met2 ;
        RECT 221.810 519.840 222.090 520.120 ;
    END
  END s2_axi_wdata_28
  PIN s2_axi_wdata_29
    DIRECTION OUTPUT ;
    USE SIGNAL ;
    ANTENNAGATEAREA 0.434700 ;
    ANTENNADIFFAREA 1.137600 ;
    PORT
      LAYER met2 ;
        RECT 449.050 0.000 449.330 0.280 ;
    END
  END s2_axi_wdata_29
  PIN s2_axi_wdata_3
    DIRECTION OUTPUT ;
    USE SIGNAL ;
    ANTENNAGATEAREA 0.434700 ;
    ANTENNADIFFAREA 1.137600 ;
    PORT
      LAYER met2 ;
        RECT 109.570 519.840 109.850 520.120 ;
    END
  END s2_axi_wdata_3
  PIN s2_axi_wdata_30
    DIRECTION OUTPUT ;
    USE SIGNAL ;
    ANTENNAGATEAREA 0.434700 ;
    ANTENNADIFFAREA 1.137600 ;
    PORT
      LAYER met2 ;
        RECT 265.970 0.000 266.250 0.280 ;
    END
  END s2_axi_wdata_30
  PIN s2_axi_wdata_31
    DIRECTION OUTPUT ;
    USE SIGNAL ;
    ANTENNAGATEAREA 0.434700 ;
    ANTENNADIFFAREA 1.137600 ;
    PORT
      LAYER met2 ;
        RECT 277.010 519.840 277.290 520.120 ;
    END
  END s2_axi_wdata_31
  PIN s2_axi_wdata_4
    DIRECTION OUTPUT ;
    USE SIGNAL ;
    ANTENNAGATEAREA 0.434700 ;
    ANTENNADIFFAREA 1.137600 ;
    PORT
      LAYER met3 ;
        RECT 0.000 73.480 0.600 74.080 ;
    END
  END s2_axi_wdata_4
  PIN s2_axi_wdata_5
    DIRECTION OUTPUT ;
    USE SIGNAL ;
    ANTENNAGATEAREA 0.434700 ;
    ANTENNADIFFAREA 1.137600 ;
    PORT
      LAYER met3 ;
        RECT 0.000 360.440 0.600 361.040 ;
    END
  END s2_axi_wdata_5
  PIN s2_axi_wdata_6
    DIRECTION OUTPUT ;
    USE SIGNAL ;
    ANTENNAGATEAREA 0.434700 ;
    ANTENNADIFFAREA 1.137600 ;
    PORT
      LAYER met2 ;
        RECT 413.170 0.000 413.450 0.280 ;
    END
  END s2_axi_wdata_6
  PIN s2_axi_wdata_7
    DIRECTION OUTPUT ;
    USE SIGNAL ;
    ANTENNAGATEAREA 0.434700 ;
    ANTENNADIFFAREA 1.137600 ;
    PORT
      LAYER met2 ;
        RECT 368.090 519.840 368.370 520.120 ;
    END
  END s2_axi_wdata_7
  PIN s2_axi_wdata_8
    DIRECTION OUTPUT ;
    USE SIGNAL ;
    ANTENNAGATEAREA 0.434700 ;
    ANTENNADIFFAREA 1.137600 ;
    PORT
      LAYER met2 ;
        RECT 476.650 0.000 476.930 0.280 ;
    END
  END s2_axi_wdata_8
  PIN s2_axi_wdata_9
    DIRECTION OUTPUT ;
    USE SIGNAL ;
    ANTENNAGATEAREA 0.434700 ;
    ANTENNADIFFAREA 1.137600 ;
    PORT
      LAYER met3 ;
        RECT 508.800 417.560 509.400 418.160 ;
    END
  END s2_axi_wdata_9
  PIN s2_axi_wready
    DIRECTION INPUT ;
    USE SIGNAL ;
    ANTENNAGATEAREA 0.647700 ;
    ANTENNADIFFAREA 0.434700 ;
    PORT
      LAYER met3 ;
        RECT 0.000 350.920 0.600 351.520 ;
    END
  END s2_axi_wready
  PIN s2_axi_wstrb_0
    DIRECTION OUTPUT ;
    USE SIGNAL ;
    ANTENNAGATEAREA 0.434700 ;
    ANTENNADIFFAREA 1.137600 ;
    PORT
      LAYER met2 ;
        RECT 262.290 519.840 262.570 520.120 ;
    END
  END s2_axi_wstrb_0
  PIN s2_axi_wstrb_1
    DIRECTION OUTPUT ;
    USE SIGNAL ;
    ANTENNAGATEAREA 0.434700 ;
    ANTENNADIFFAREA 1.137600 ;
    PORT
      LAYER met2 ;
        RECT 230.090 0.000 230.370 0.280 ;
    END
  END s2_axi_wstrb_1
  PIN s2_axi_wstrb_2
    DIRECTION OUTPUT ;
    USE SIGNAL ;
    ANTENNAGATEAREA 0.434700 ;
    ANTENNADIFFAREA 1.137600 ;
    PORT
      LAYER met2 ;
        RECT 416.850 519.840 417.130 520.120 ;
    END
  END s2_axi_wstrb_2
  PIN s2_axi_wstrb_3
    DIRECTION OUTPUT ;
    USE SIGNAL ;
    ANTENNAGATEAREA 0.434700 ;
    ANTENNADIFFAREA 1.137600 ;
    PORT
      LAYER met2 ;
        RECT 55.290 519.840 55.570 520.120 ;
    END
  END s2_axi_wstrb_3
  PIN s2_axi_wvalid
    DIRECTION OUTPUT ;
    USE SIGNAL ;
    ANTENNAGATEAREA 0.434700 ;
    ANTENNADIFFAREA 1.137600 ;
    PORT
      LAYER met3 ;
        RECT 0.000 152.360 0.600 152.960 ;
    END
  END s2_axi_wvalid
  PIN s3_axi_araddr_0
    DIRECTION OUTPUT ;
    USE SIGNAL ;
    ANTENNAGATEAREA 0.434700 ;
    ANTENNADIFFAREA 1.137600 ;
    PORT
      LAYER met2 ;
        RECT 352.450 0.000 352.730 0.280 ;
    END
  END s3_axi_araddr_0
  PIN s3_axi_araddr_1
    DIRECTION OUTPUT ;
    USE SIGNAL ;
    ANTENNAGATEAREA 0.434700 ;
    ANTENNADIFFAREA 1.137600 ;
    PORT
      LAYER met2 ;
        RECT 404.890 519.840 405.170 520.120 ;
    END
  END s3_axi_araddr_1
  PIN s3_axi_araddr_10
    DIRECTION OUTPUT ;
    USE SIGNAL ;
    ANTENNAGATEAREA 0.434700 ;
    ANTENNADIFFAREA 1.137600 ;
    PORT
      LAYER met2 ;
        RECT 214.450 519.840 214.730 520.120 ;
    END
  END s3_axi_araddr_10
  PIN s3_axi_araddr_11
    DIRECTION OUTPUT ;
    USE SIGNAL ;
    ANTENNAGATEAREA 0.434700 ;
    ANTENNADIFFAREA 1.137600 ;
    PORT
      LAYER met2 ;
        RECT 320.250 519.840 320.530 520.120 ;
    END
  END s3_axi_araddr_11
  PIN s3_axi_araddr_12
    DIRECTION OUTPUT ;
    USE SIGNAL ;
    ANTENNAGATEAREA 0.434700 ;
    ANTENNADIFFAREA 1.137600 ;
    PORT
      LAYER met2 ;
        RECT 82.890 519.840 83.170 520.120 ;
    END
  END s3_axi_araddr_12
  PIN s3_axi_araddr_13
    DIRECTION OUTPUT ;
    USE SIGNAL ;
    ANTENNAGATEAREA 0.434700 ;
    ANTENNADIFFAREA 1.137600 ;
    PORT
      LAYER met2 ;
        RECT 298.170 0.000 298.450 0.280 ;
    END
  END s3_axi_araddr_13
  PIN s3_axi_araddr_14
    DIRECTION OUTPUT ;
    USE SIGNAL ;
    ANTENNAGATEAREA 0.434700 ;
    ANTENNADIFFAREA 1.137600 ;
    PORT
      LAYER met2 ;
        RECT 232.850 0.000 233.130 0.280 ;
    END
  END s3_axi_araddr_14
  PIN s3_axi_araddr_15
    DIRECTION OUTPUT ;
    USE SIGNAL ;
    ANTENNAGATEAREA 0.434700 ;
    ANTENNADIFFAREA 1.137600 ;
    PORT
      LAYER met2 ;
        RECT 125.210 519.840 125.490 520.120 ;
    END
  END s3_axi_araddr_15
  PIN s3_axi_araddr_16
    DIRECTION OUTPUT ;
    USE SIGNAL ;
    ANTENNAGATEAREA 0.434700 ;
    ANTENNADIFFAREA 1.137600 ;
    PORT
      LAYER met2 ;
        RECT 187.770 519.840 188.050 520.120 ;
    END
  END s3_axi_araddr_16
  PIN s3_axi_araddr_17
    DIRECTION OUTPUT ;
    USE SIGNAL ;
    ANTENNAGATEAREA 0.434700 ;
    ANTENNADIFFAREA 1.137600 ;
    PORT
      LAYER met2 ;
        RECT 395.690 0.000 395.970 0.280 ;
    END
  END s3_axi_araddr_17
  PIN s3_axi_araddr_18
    DIRECTION OUTPUT ;
    USE SIGNAL ;
    ANTENNAGATEAREA 0.434700 ;
    ANTENNADIFFAREA 1.137600 ;
    PORT
      LAYER met2 ;
        RECT 242.050 0.000 242.330 0.280 ;
    END
  END s3_axi_araddr_18
  PIN s3_axi_araddr_19
    DIRECTION OUTPUT ;
    USE SIGNAL ;
    ANTENNAGATEAREA 0.434700 ;
    ANTENNADIFFAREA 1.137600 ;
    PORT
      LAYER met3 ;
        RECT 0.000 57.160 0.600 57.760 ;
    END
  END s3_axi_araddr_19
  PIN s3_axi_araddr_2
    DIRECTION OUTPUT ;
    USE SIGNAL ;
    ANTENNAGATEAREA 0.434700 ;
    ANTENNADIFFAREA 1.137600 ;
    PORT
      LAYER met2 ;
        RECT 219.050 0.000 219.330 0.280 ;
    END
  END s3_axi_araddr_2
  PIN s3_axi_araddr_20
    DIRECTION OUTPUT ;
    USE SIGNAL ;
    ANTENNAGATEAREA 0.434700 ;
    ANTENNADIFFAREA 1.137600 ;
    PORT
      LAYER met3 ;
        RECT 0.000 391.720 0.600 392.320 ;
    END
  END s3_axi_araddr_20
  PIN s3_axi_araddr_21
    DIRECTION OUTPUT ;
    USE SIGNAL ;
    ANTENNAGATEAREA 0.434700 ;
    ANTENNADIFFAREA 1.137600 ;
    PORT
      LAYER met2 ;
        RECT 184.090 519.840 184.370 520.120 ;
    END
  END s3_axi_araddr_21
  PIN s3_axi_araddr_22
    DIRECTION OUTPUT ;
    USE SIGNAL ;
    ANTENNAGATEAREA 0.434700 ;
    ANTENNADIFFAREA 1.137600 ;
    PORT
      LAYER met2 ;
        RECT 328.530 519.840 328.810 520.120 ;
    END
  END s3_axi_araddr_22
  PIN s3_axi_araddr_23
    DIRECTION OUTPUT ;
    USE SIGNAL ;
    ANTENNAGATEAREA 0.434700 ;
    ANTENNADIFFAREA 1.137600 ;
    PORT
      LAYER met2 ;
        RECT 252.170 0.000 252.450 0.280 ;
    END
  END s3_axi_araddr_23
  PIN s3_axi_araddr_24
    DIRECTION OUTPUT ;
    USE SIGNAL ;
    ANTENNAGATEAREA 0.434700 ;
    ANTENNADIFFAREA 1.137600 ;
    PORT
      LAYER met2 ;
        RECT 152.810 519.840 153.090 520.120 ;
    END
  END s3_axi_araddr_24
  PIN s3_axi_araddr_25
    DIRECTION OUTPUT ;
    USE SIGNAL ;
    ANTENNAGATEAREA 0.434700 ;
    ANTENNADIFFAREA 1.137600 ;
    PORT
      LAYER met2 ;
        RECT 46.090 519.840 46.370 520.120 ;
    END
  END s3_axi_araddr_25
  PIN s3_axi_araddr_26
    DIRECTION OUTPUT ;
    USE SIGNAL ;
    ANTENNAGATEAREA 0.434700 ;
    ANTENNADIFFAREA 1.137600 ;
    PORT
      LAYER met2 ;
        RECT 204.330 0.000 204.610 0.280 ;
    END
  END s3_axi_araddr_26
  PIN s3_axi_araddr_27
    DIRECTION OUTPUT ;
    USE SIGNAL ;
    ANTENNAGATEAREA 0.434700 ;
    ANTENNADIFFAREA 1.137600 ;
    PORT
      LAYER met2 ;
        RECT 394.770 519.840 395.050 520.120 ;
    END
  END s3_axi_araddr_27
  PIN s3_axi_araddr_28
    DIRECTION OUTPUT ;
    USE SIGNAL ;
    ANTENNAGATEAREA 0.434700 ;
    ANTENNADIFFAREA 1.137600 ;
    PORT
      LAYER met2 ;
        RECT 187.770 0.000 188.050 0.280 ;
    END
  END s3_axi_araddr_28
  PIN s3_axi_araddr_29
    DIRECTION OUTPUT ;
    USE SIGNAL ;
    ANTENNAGATEAREA 0.434700 ;
    ANTENNADIFFAREA 1.137600 ;
    PORT
      LAYER met2 ;
        RECT 95.770 519.840 96.050 520.120 ;
    END
  END s3_axi_araddr_29
  PIN s3_axi_araddr_3
    DIRECTION OUTPUT ;
    USE SIGNAL ;
    ANTENNAGATEAREA 0.434700 ;
    ANTENNADIFFAREA 1.137600 ;
    PORT
      LAYER met2 ;
        RECT 210.770 0.000 211.050 0.280 ;
    END
  END s3_axi_araddr_3
  PIN s3_axi_araddr_30
    DIRECTION OUTPUT ;
    USE SIGNAL ;
    ANTENNAGATEAREA 0.434700 ;
    ANTENNADIFFAREA 1.137600 ;
    PORT
      LAYER met2 ;
        RECT 67.250 519.840 67.530 520.120 ;
    END
  END s3_axi_araddr_30
  PIN s3_axi_araddr_31
    DIRECTION OUTPUT ;
    USE SIGNAL ;
    ANTENNAGATEAREA 0.434700 ;
    ANTENNADIFFAREA 1.137600 ;
    PORT
      LAYER met2 ;
        RECT 157.410 519.840 157.690 520.120 ;
    END
  END s3_axi_araddr_31
  PIN s3_axi_araddr_4
    DIRECTION OUTPUT ;
    USE SIGNAL ;
    ANTENNAGATEAREA 0.434700 ;
    ANTENNADIFFAREA 1.137600 ;
    PORT
      LAYER met2 ;
        RECT 309.210 519.840 309.490 520.120 ;
    END
  END s3_axi_araddr_4
  PIN s3_axi_araddr_5
    DIRECTION OUTPUT ;
    USE SIGNAL ;
    ANTENNAGATEAREA 0.434700 ;
    ANTENNADIFFAREA 1.137600 ;
    PORT
      LAYER met2 ;
        RECT 380.970 519.840 381.250 520.120 ;
    END
  END s3_axi_araddr_5
  PIN s3_axi_araddr_6
    DIRECTION OUTPUT ;
    USE SIGNAL ;
    ANTENNAGATEAREA 0.434700 ;
    ANTENNADIFFAREA 1.137600 ;
    PORT
      LAYER met2 ;
        RECT 307.370 0.000 307.650 0.280 ;
    END
  END s3_axi_araddr_6
  PIN s3_axi_araddr_7
    DIRECTION OUTPUT ;
    USE SIGNAL ;
    ANTENNAGATEAREA 0.434700 ;
    ANTENNADIFFAREA 1.137600 ;
    PORT
      LAYER met2 ;
        RECT 195.130 0.000 195.410 0.280 ;
    END
  END s3_axi_araddr_7
  PIN s3_axi_araddr_8
    DIRECTION OUTPUT ;
    USE SIGNAL ;
    ANTENNAGATEAREA 0.434700 ;
    ANTENNADIFFAREA 1.137600 ;
    PORT
      LAYER met2 ;
        RECT 200.650 0.000 200.930 0.280 ;
    END
  END s3_axi_araddr_8
  PIN s3_axi_araddr_9
    DIRECTION OUTPUT ;
    USE SIGNAL ;
    ANTENNAGATEAREA 0.434700 ;
    ANTENNADIFFAREA 1.137600 ;
    PORT
      LAYER met2 ;
        RECT 455.490 519.840 455.770 520.120 ;
    END
  END s3_axi_araddr_9
  PIN s3_axi_arready
    DIRECTION INPUT ;
    USE SIGNAL ;
    ANTENNAGATEAREA 0.647700 ;
    ANTENNADIFFAREA 0.434700 ;
    PORT
      LAYER met2 ;
        RECT 296.330 519.840 296.610 520.120 ;
    END
  END s3_axi_arready
  PIN s3_axi_arvalid
    DIRECTION OUTPUT ;
    USE SIGNAL ;
    ANTENNAGATEAREA 0.434700 ;
    ANTENNADIFFAREA 0.775300 ;
    PORT
      LAYER met3 ;
        RECT 508.800 485.560 509.400 486.160 ;
    END
  END s3_axi_arvalid
  PIN s3_axi_awaddr_0
    DIRECTION OUTPUT ;
    USE SIGNAL ;
    ANTENNAGATEAREA 0.434700 ;
    ANTENNADIFFAREA 1.137600 ;
    PORT
      LAYER met2 ;
        RECT 495.970 0.000 496.250 0.280 ;
    END
  END s3_axi_awaddr_0
  PIN s3_axi_awaddr_1
    DIRECTION OUTPUT ;
    USE SIGNAL ;
    ANTENNAGATEAREA 0.434700 ;
    ANTENNADIFFAREA 1.137600 ;
    PORT
      LAYER met2 ;
        RECT 271.490 0.000 271.770 0.280 ;
    END
  END s3_axi_awaddr_1
  PIN s3_axi_awaddr_10
    DIRECTION OUTPUT ;
    USE SIGNAL ;
    ANTENNAGATEAREA 0.434700 ;
    ANTENNADIFFAREA 1.137600 ;
    PORT
      LAYER met2 ;
        RECT 340.490 0.000 340.770 0.280 ;
    END
  END s3_axi_awaddr_10
  PIN s3_axi_awaddr_11
    DIRECTION OUTPUT ;
    USE SIGNAL ;
    ANTENNAGATEAREA 0.434700 ;
    ANTENNADIFFAREA 1.137600 ;
    PORT
      LAYER met2 ;
        RECT 318.410 0.000 318.690 0.280 ;
    END
  END s3_axi_awaddr_11
  PIN s3_axi_awaddr_12
    DIRECTION OUTPUT ;
    USE SIGNAL ;
    ANTENNAGATEAREA 0.434700 ;
    ANTENNADIFFAREA 1.137600 ;
    PORT
      LAYER met2 ;
        RECT 293.570 519.840 293.850 520.120 ;
    END
  END s3_axi_awaddr_12
  PIN s3_axi_awaddr_13
    DIRECTION OUTPUT ;
    USE SIGNAL ;
    ANTENNAGATEAREA 0.434700 ;
    ANTENNADIFFAREA 1.137600 ;
    PORT
      LAYER met2 ;
        RECT 304.610 0.000 304.890 0.280 ;
    END
  END s3_axi_awaddr_13
  PIN s3_axi_awaddr_14
    DIRECTION OUTPUT ;
    USE SIGNAL ;
    ANTENNAGATEAREA 0.434700 ;
    ANTENNADIFFAREA 1.137600 ;
    PORT
      LAYER met2 ;
        RECT 389.250 0.000 389.530 0.280 ;
    END
  END s3_axi_awaddr_14
  PIN s3_axi_awaddr_15
    DIRECTION OUTPUT ;
    USE SIGNAL ;
    ANTENNAGATEAREA 0.434700 ;
    ANTENNADIFFAREA 1.137600 ;
    PORT
      LAYER met2 ;
        RECT 79.210 519.840 79.490 520.120 ;
    END
  END s3_axi_awaddr_15
  PIN s3_axi_awaddr_16
    DIRECTION OUTPUT ;
    USE SIGNAL ;
    ANTENNAGATEAREA 0.434700 ;
    ANTENNADIFFAREA 1.137600 ;
    PORT
      LAYER met2 ;
        RECT 311.050 0.000 311.330 0.280 ;
    END
  END s3_axi_awaddr_16
  PIN s3_axi_awaddr_17
    DIRECTION OUTPUT ;
    USE SIGNAL ;
    ANTENNAGATEAREA 0.434700 ;
    ANTENNADIFFAREA 1.137600 ;
    PORT
      LAYER met2 ;
        RECT 357.970 519.840 358.250 520.120 ;
    END
  END s3_axi_awaddr_17
  PIN s3_axi_awaddr_18
    DIRECTION OUTPUT ;
    USE SIGNAL ;
    ANTENNAGATEAREA 0.434700 ;
    ANTENNADIFFAREA 1.137600 ;
    PORT
      LAYER met2 ;
        RECT 335.890 519.840 336.170 520.120 ;
    END
  END s3_axi_awaddr_18
  PIN s3_axi_awaddr_19
    DIRECTION OUTPUT ;
    USE SIGNAL ;
    ANTENNAGATEAREA 0.434700 ;
    ANTENNADIFFAREA 1.137600 ;
    PORT
      LAYER met3 ;
        RECT 508.800 446.120 509.400 446.720 ;
    END
  END s3_axi_awaddr_19
  PIN s3_axi_awaddr_2
    DIRECTION OUTPUT ;
    USE SIGNAL ;
    ANTENNAGATEAREA 0.434700 ;
    ANTENNADIFFAREA 1.137600 ;
    PORT
      LAYER met3 ;
        RECT 0.000 119.720 0.600 120.320 ;
    END
  END s3_axi_awaddr_2
  PIN s3_axi_awaddr_20
    DIRECTION OUTPUT ;
    USE SIGNAL ;
    ANTENNAGATEAREA 0.434700 ;
    ANTENNADIFFAREA 1.137600 ;
    PORT
      LAYER met3 ;
        RECT 0.000 118.360 0.600 118.960 ;
    END
  END s3_axi_awaddr_20
  PIN s3_axi_awaddr_21
    DIRECTION OUTPUT ;
    USE SIGNAL ;
    ANTENNAGATEAREA 0.434700 ;
    ANTENNADIFFAREA 1.137600 ;
    PORT
      LAYER met3 ;
        RECT 0.000 413.480 0.600 414.080 ;
    END
  END s3_axi_awaddr_21
  PIN s3_axi_awaddr_22
    DIRECTION OUTPUT ;
    USE SIGNAL ;
    ANTENNAGATEAREA 0.434700 ;
    ANTENNADIFFAREA 1.137600 ;
    PORT
      LAYER met2 ;
        RECT 439.850 0.000 440.130 0.280 ;
    END
  END s3_axi_awaddr_22
  PIN s3_axi_awaddr_23
    DIRECTION OUTPUT ;
    USE SIGNAL ;
    ANTENNAGATEAREA 0.434700 ;
    ANTENNADIFFAREA 1.137600 ;
    PORT
      LAYER met2 ;
        RECT 351.530 519.840 351.810 520.120 ;
    END
  END s3_axi_awaddr_23
  PIN s3_axi_awaddr_24
    DIRECTION OUTPUT ;
    USE SIGNAL ;
    ANTENNAGATEAREA 0.434700 ;
    ANTENNADIFFAREA 1.137600 ;
    PORT
      LAYER met2 ;
        RECT 170.290 519.840 170.570 520.120 ;
    END
  END s3_axi_awaddr_24
  PIN s3_axi_awaddr_25
    DIRECTION OUTPUT ;
    USE SIGNAL ;
    ANTENNAGATEAREA 0.434700 ;
    ANTENNADIFFAREA 1.137600 ;
    PORT
      LAYER met3 ;
        RECT 0.000 161.880 0.600 162.480 ;
    END
  END s3_axi_awaddr_25
  PIN s3_axi_awaddr_26
    DIRECTION OUTPUT ;
    USE SIGNAL ;
    ANTENNAGATEAREA 0.434700 ;
    ANTENNADIFFAREA 1.137600 ;
    PORT
      LAYER met2 ;
        RECT 205.250 519.840 205.530 520.120 ;
    END
  END s3_axi_awaddr_26
  PIN s3_axi_awaddr_27
    DIRECTION OUTPUT ;
    USE SIGNAL ;
    ANTENNAGATEAREA 0.434700 ;
    ANTENNADIFFAREA 1.137600 ;
    PORT
      LAYER met2 ;
        RECT 477.570 0.000 477.850 0.280 ;
    END
  END s3_axi_awaddr_27
  PIN s3_axi_awaddr_28
    DIRECTION OUTPUT ;
    USE SIGNAL ;
    ANTENNAGATEAREA 0.434700 ;
    ANTENNADIFFAREA 1.137600 ;
    PORT
      LAYER met2 ;
        RECT 405.810 0.000 406.090 0.280 ;
    END
  END s3_axi_awaddr_28
  PIN s3_axi_awaddr_29
    DIRECTION OUTPUT ;
    USE SIGNAL ;
    ANTENNAGATEAREA 0.434700 ;
    ANTENNADIFFAREA 1.137600 ;
    PORT
      LAYER met2 ;
        RECT 392.010 519.840 392.290 520.120 ;
    END
  END s3_axi_awaddr_29
  PIN s3_axi_awaddr_3
    DIRECTION OUTPUT ;
    USE SIGNAL ;
    ANTENNAGATEAREA 0.434700 ;
    ANTENNADIFFAREA 1.137600 ;
    PORT
      LAYER met3 ;
        RECT 0.000 68.040 0.600 68.640 ;
    END
  END s3_axi_awaddr_3
  PIN s3_axi_awaddr_30
    DIRECTION OUTPUT ;
    USE SIGNAL ;
    ANTENNAGATEAREA 0.434700 ;
    ANTENNADIFFAREA 1.137600 ;
    PORT
      LAYER met2 ;
        RECT 440.770 0.000 441.050 0.280 ;
    END
  END s3_axi_awaddr_30
  PIN s3_axi_awaddr_31
    DIRECTION OUTPUT ;
    USE SIGNAL ;
    ANTENNAGATEAREA 0.434700 ;
    ANTENNADIFFAREA 1.137600 ;
    PORT
      LAYER met2 ;
        RECT 265.970 519.840 266.250 520.120 ;
    END
  END s3_axi_awaddr_31
  PIN s3_axi_awaddr_4
    DIRECTION OUTPUT ;
    USE SIGNAL ;
    ANTENNAGATEAREA 0.434700 ;
    ANTENNADIFFAREA 1.137600 ;
    PORT
      LAYER met2 ;
        RECT 346.010 519.840 346.290 520.120 ;
    END
  END s3_axi_awaddr_4
  PIN s3_axi_awaddr_5
    DIRECTION OUTPUT ;
    USE SIGNAL ;
    ANTENNAGATEAREA 0.434700 ;
    ANTENNADIFFAREA 1.137600 ;
    PORT
      LAYER met2 ;
        RECT 378.210 0.000 378.490 0.280 ;
    END
  END s3_axi_awaddr_5
  PIN s3_axi_awaddr_6
    DIRECTION OUTPUT ;
    USE SIGNAL ;
    ANTENNAGATEAREA 0.434700 ;
    ANTENNADIFFAREA 1.137600 ;
    PORT
      LAYER met2 ;
        RECT 382.810 0.000 383.090 0.280 ;
    END
  END s3_axi_awaddr_6
  PIN s3_axi_awaddr_7
    DIRECTION OUTPUT ;
    USE SIGNAL ;
    ANTENNAGATEAREA 0.434700 ;
    ANTENNADIFFAREA 1.137600 ;
    PORT
      LAYER met3 ;
        RECT 0.000 34.040 0.600 34.640 ;
    END
  END s3_axi_awaddr_7
  PIN s3_axi_awaddr_8
    DIRECTION OUTPUT ;
    USE SIGNAL ;
    ANTENNAGATEAREA 0.434700 ;
    ANTENNADIFFAREA 1.137600 ;
    PORT
      LAYER met2 ;
        RECT 478.490 0.000 478.770 0.280 ;
    END
  END s3_axi_awaddr_8
  PIN s3_axi_awaddr_9
    DIRECTION OUTPUT ;
    USE SIGNAL ;
    ANTENNAGATEAREA 0.434700 ;
    ANTENNADIFFAREA 1.137600 ;
    PORT
      LAYER met3 ;
        RECT 508.800 421.640 509.400 422.240 ;
    END
  END s3_axi_awaddr_9
  PIN s3_axi_awready
    DIRECTION INPUT ;
    USE SIGNAL ;
    ANTENNAGATEAREA 0.647700 ;
    ANTENNADIFFAREA 0.434700 ;
    PORT
      LAYER met3 ;
        RECT 0.000 352.280 0.600 352.880 ;
    END
  END s3_axi_awready
  PIN s3_axi_awvalid
    DIRECTION OUTPUT ;
    USE SIGNAL ;
    ANTENNAGATEAREA 0.434700 ;
    ANTENNADIFFAREA 0.775300 ;
    PORT
      LAYER met3 ;
        RECT 508.800 399.880 509.400 400.480 ;
    END
  END s3_axi_awvalid
  PIN s3_axi_bready
    DIRECTION OUTPUT ;
    USE SIGNAL ;
    ANTENNAGATEAREA 0.434700 ;
    ANTENNADIFFAREA 0.775300 ;
    PORT
      LAYER met3 ;
        RECT 508.800 462.440 509.400 463.040 ;
    END
  END s3_axi_bready
  PIN s3_axi_bresp_0
    DIRECTION INPUT ;
    USE SIGNAL ;
    ANTENNAGATEAREA 0.647700 ;
    ANTENNADIFFAREA 0.434700 ;
    PORT
      LAYER met3 ;
        RECT 0.000 321.000 0.600 321.600 ;
    END
  END s3_axi_bresp_0
  PIN s3_axi_bresp_1
    DIRECTION INPUT ;
    USE SIGNAL ;
    ANTENNAGATEAREA 0.647700 ;
    ANTENNADIFFAREA 0.434700 ;
    PORT
      LAYER met3 ;
        RECT 0.000 319.640 0.600 320.240 ;
    END
  END s3_axi_bresp_1
  PIN s3_axi_bvalid
    DIRECTION INPUT ;
    USE SIGNAL ;
    ANTENNAGATEAREA 0.647700 ;
    ANTENNADIFFAREA 0.434700 ;
    PORT
      LAYER met3 ;
        RECT 0.000 353.640 0.600 354.240 ;
    END
  END s3_axi_bvalid
  PIN s3_axi_rdata_0
    DIRECTION INPUT ;
    USE SIGNAL ;
    ANTENNAGATEAREA 0.647700 ;
    ANTENNADIFFAREA 0.434700 ;
    PORT
      LAYER met3 ;
        RECT 508.800 74.840 509.400 75.440 ;
    END
  END s3_axi_rdata_0
  PIN s3_axi_rdata_1
    DIRECTION INPUT ;
    USE SIGNAL ;
    ANTENNAGATEAREA 0.647700 ;
    ANTENNADIFFAREA 0.434700 ;
    PORT
      LAYER met2 ;
        RECT 295.410 519.840 295.690 520.120 ;
    END
  END s3_axi_rdata_1
  PIN s3_axi_rdata_10
    DIRECTION INPUT ;
    USE SIGNAL ;
    ANTENNAGATEAREA 0.647700 ;
    ANTENNADIFFAREA 0.434700 ;
    PORT
      LAYER met3 ;
        RECT 508.800 292.440 509.400 293.040 ;
    END
  END s3_axi_rdata_10
  PIN s3_axi_rdata_11
    DIRECTION INPUT ;
    USE SIGNAL ;
    ANTENNAGATEAREA 0.647700 ;
    ANTENNADIFFAREA 0.434700 ;
    PORT
      LAYER met3 ;
        RECT 508.800 144.200 509.400 144.800 ;
    END
  END s3_axi_rdata_11
  PIN s3_axi_rdata_12
    DIRECTION INPUT ;
    USE SIGNAL ;
    ANTENNAGATEAREA 0.647700 ;
    ANTENNADIFFAREA 0.434700 ;
    PORT
      LAYER met3 ;
        RECT 508.800 153.720 509.400 154.320 ;
    END
  END s3_axi_rdata_12
  PIN s3_axi_rdata_13
    DIRECTION INPUT ;
    USE SIGNAL ;
    ANTENNAGATEAREA 0.647700 ;
    ANTENNADIFFAREA 0.434700 ;
    PORT
      LAYER met3 ;
        RECT 508.800 70.760 509.400 71.360 ;
    END
  END s3_axi_rdata_13
  PIN s3_axi_rdata_14
    DIRECTION INPUT ;
    USE SIGNAL ;
    ANTENNAGATEAREA 0.647700 ;
    ANTENNADIFFAREA 0.434700 ;
    PORT
      LAYER met3 ;
        RECT 508.800 497.800 509.400 498.400 ;
    END
  END s3_axi_rdata_14
  PIN s3_axi_rdata_15
    DIRECTION INPUT ;
    USE SIGNAL ;
    ANTENNAGATEAREA 0.647700 ;
    ANTENNADIFFAREA 0.434700 ;
    PORT
      LAYER met3 ;
        RECT 508.800 202.680 509.400 203.280 ;
    END
  END s3_axi_rdata_15
  PIN s3_axi_rdata_16
    DIRECTION INPUT ;
    USE SIGNAL ;
    ANTENNAGATEAREA 0.647700 ;
    ANTENNADIFFAREA 0.434700 ;
    PORT
      LAYER met3 ;
        RECT 508.800 149.640 509.400 150.240 ;
    END
  END s3_axi_rdata_16
  PIN s3_axi_rdata_17
    DIRECTION INPUT ;
    USE SIGNAL ;
    ANTENNAGATEAREA 0.647700 ;
    ANTENNADIFFAREA 0.434700 ;
    PORT
      LAYER met3 ;
        RECT 508.800 360.440 509.400 361.040 ;
    END
  END s3_axi_rdata_17
  PIN s3_axi_rdata_18
    DIRECTION INPUT ;
    USE SIGNAL ;
    ANTENNAGATEAREA 0.647700 ;
    ANTENNADIFFAREA 0.434700 ;
    PORT
      LAYER met3 ;
        RECT 508.800 84.360 509.400 84.960 ;
    END
  END s3_axi_rdata_18
  PIN s3_axi_rdata_19
    DIRECTION INPUT ;
    USE SIGNAL ;
    ANTENNAGATEAREA 0.647700 ;
    ANTENNADIFFAREA 0.434700 ;
    PORT
      LAYER met3 ;
        RECT 508.800 285.640 509.400 286.240 ;
    END
  END s3_axi_rdata_19
  PIN s3_axi_rdata_2
    DIRECTION INPUT ;
    USE SIGNAL ;
    ANTENNAGATEAREA 0.647700 ;
    ANTENNADIFFAREA 0.434700 ;
    PORT
      LAYER met3 ;
        RECT 508.800 204.040 509.400 204.640 ;
    END
  END s3_axi_rdata_2
  PIN s3_axi_rdata_20
    DIRECTION INPUT ;
    USE SIGNAL ;
    ANTENNAGATEAREA 0.647700 ;
    ANTENNADIFFAREA 0.434700 ;
    PORT
      LAYER met3 ;
        RECT 508.800 238.040 509.400 238.640 ;
    END
  END s3_axi_rdata_20
  PIN s3_axi_rdata_21
    DIRECTION INPUT ;
    USE SIGNAL ;
    ANTENNAGATEAREA 0.647700 ;
    ANTENNADIFFAREA 0.434700 ;
    PORT
      LAYER met3 ;
        RECT 508.800 365.880 509.400 366.480 ;
    END
  END s3_axi_rdata_21
  PIN s3_axi_rdata_22
    DIRECTION INPUT ;
    USE SIGNAL ;
    ANTENNAGATEAREA 0.647700 ;
    ANTENNADIFFAREA 0.434700 ;
    PORT
      LAYER met3 ;
        RECT 508.800 265.240 509.400 265.840 ;
    END
  END s3_axi_rdata_22
  PIN s3_axi_rdata_23
    DIRECTION INPUT ;
    USE SIGNAL ;
    ANTENNAGATEAREA 0.647700 ;
    ANTENNADIFFAREA 0.434700 ;
    PORT
      LAYER met3 ;
        RECT 508.800 185.000 509.400 185.600 ;
    END
  END s3_axi_rdata_23
  PIN s3_axi_rdata_24
    DIRECTION INPUT ;
    USE SIGNAL ;
    ANTENNAGATEAREA 0.647700 ;
    ANTENNADIFFAREA 0.434700 ;
    PORT
      LAYER met2 ;
        RECT 300.930 519.840 301.210 520.120 ;
    END
  END s3_axi_rdata_24
  PIN s3_axi_rdata_25
    DIRECTION INPUT ;
    USE SIGNAL ;
    ANTENNAGATEAREA 0.647700 ;
    ANTENNADIFFAREA 0.434700 ;
    PORT
      LAYER met3 ;
        RECT 508.800 495.080 509.400 495.680 ;
    END
  END s3_axi_rdata_25
  PIN s3_axi_rdata_26
    DIRECTION INPUT ;
    USE SIGNAL ;
    ANTENNAGATEAREA 0.647700 ;
    ANTENNADIFFAREA 0.434700 ;
    PORT
      LAYER met3 ;
        RECT 508.800 172.760 509.400 173.360 ;
    END
  END s3_axi_rdata_26
  PIN s3_axi_rdata_27
    DIRECTION INPUT ;
    USE SIGNAL ;
    ANTENNAGATEAREA 0.647700 ;
    ANTENNADIFFAREA 0.434700 ;
    PORT
      LAYER met3 ;
        RECT 508.800 223.080 509.400 223.680 ;
    END
  END s3_axi_rdata_27
  PIN s3_axi_rdata_28
    DIRECTION INPUT ;
    USE SIGNAL ;
    ANTENNAGATEAREA 0.647700 ;
    ANTENNADIFFAREA 0.434700 ;
    PORT
      LAYER met3 ;
        RECT 508.800 148.280 509.400 148.880 ;
    END
  END s3_axi_rdata_28
  PIN s3_axi_rdata_29
    DIRECTION INPUT ;
    USE SIGNAL ;
    ANTENNAGATEAREA 0.647700 ;
    ANTENNADIFFAREA 0.434700 ;
    PORT
      LAYER met3 ;
        RECT 508.800 278.840 509.400 279.440 ;
    END
  END s3_axi_rdata_29
  PIN s3_axi_rdata_3
    DIRECTION INPUT ;
    USE SIGNAL ;
    ANTENNAGATEAREA 0.647700 ;
    ANTENNADIFFAREA 0.434700 ;
    PORT
      LAYER met3 ;
        RECT 508.800 353.640 509.400 354.240 ;
    END
  END s3_axi_rdata_3
  PIN s3_axi_rdata_30
    DIRECTION INPUT ;
    USE SIGNAL ;
    ANTENNAGATEAREA 0.647700 ;
    ANTENNADIFFAREA 0.434700 ;
    PORT
      LAYER met3 ;
        RECT 508.800 152.360 509.400 152.960 ;
    END
  END s3_axi_rdata_30
  PIN s3_axi_rdata_31
    DIRECTION INPUT ;
    USE SIGNAL ;
    ANTENNAGATEAREA 0.647700 ;
    ANTENNADIFFAREA 0.434700 ;
    PORT
      LAYER met3 ;
        RECT 508.800 348.200 509.400 348.800 ;
    END
  END s3_axi_rdata_31
  PIN s3_axi_rdata_4
    DIRECTION INPUT ;
    USE SIGNAL ;
    ANTENNAGATEAREA 0.647700 ;
    ANTENNADIFFAREA 0.434700 ;
    PORT
      LAYER met2 ;
        RECT 288.970 519.840 289.250 520.120 ;
    END
  END s3_axi_rdata_4
  PIN s3_axi_rdata_5
    DIRECTION INPUT ;
    USE SIGNAL ;
    ANTENNAGATEAREA 0.647700 ;
    ANTENNADIFFAREA 0.434700 ;
    PORT
      LAYER met3 ;
        RECT 508.800 240.760 509.400 241.360 ;
    END
  END s3_axi_rdata_5
  PIN s3_axi_rdata_6
    DIRECTION INPUT ;
    USE SIGNAL ;
    ANTENNAGATEAREA 0.647700 ;
    ANTENNADIFFAREA 0.434700 ;
    PORT
      LAYER met3 ;
        RECT 508.800 357.720 509.400 358.320 ;
    END
  END s3_axi_rdata_6
  PIN s3_axi_rdata_7
    DIRECTION INPUT ;
    USE SIGNAL ;
    ANTENNAGATEAREA 0.647700 ;
    ANTENNADIFFAREA 0.434700 ;
    PORT
      LAYER met3 ;
        RECT 508.800 355.000 509.400 355.600 ;
    END
  END s3_axi_rdata_7
  PIN s3_axi_rdata_8
    DIRECTION INPUT ;
    USE SIGNAL ;
    ANTENNAGATEAREA 0.647700 ;
    ANTENNADIFFAREA 0.434700 ;
    PORT
      LAYER met3 ;
        RECT 508.800 304.680 509.400 305.280 ;
    END
  END s3_axi_rdata_8
  PIN s3_axi_rdata_9
    DIRECTION INPUT ;
    USE SIGNAL ;
    ANTENNAGATEAREA 0.647700 ;
    ANTENNADIFFAREA 0.434700 ;
    PORT
      LAYER met3 ;
        RECT 508.800 53.080 509.400 53.680 ;
    END
  END s3_axi_rdata_9
  PIN s3_axi_rready
    DIRECTION OUTPUT ;
    USE SIGNAL ;
    ANTENNAGATEAREA 0.434700 ;
    ANTENNADIFFAREA 0.775300 ;
    PORT
      LAYER met3 ;
        RECT 508.800 433.880 509.400 434.480 ;
    END
  END s3_axi_rready
  PIN s3_axi_rresp_0
    DIRECTION INPUT ;
    USE SIGNAL ;
    ANTENNAGATEAREA 0.647700 ;
    ANTENNADIFFAREA 0.434700 ;
    PORT
      LAYER met3 ;
        RECT 508.800 326.440 509.400 327.040 ;
    END
  END s3_axi_rresp_0
  PIN s3_axi_rresp_1
    DIRECTION INPUT ;
    USE SIGNAL ;
    ANTENNAGATEAREA 0.647700 ;
    ANTENNADIFFAREA 0.434700 ;
    PORT
      LAYER met3 ;
        RECT 508.800 151.000 509.400 151.600 ;
    END
  END s3_axi_rresp_1
  PIN s3_axi_rvalid
    DIRECTION INPUT ;
    USE SIGNAL ;
    ANTENNAGATEAREA 0.647700 ;
    ANTENNADIFFAREA 0.434700 ;
    PORT
      LAYER met3 ;
        RECT 508.800 342.760 509.400 343.360 ;
    END
  END s3_axi_rvalid
  PIN s3_axi_wdata_0
    DIRECTION OUTPUT ;
    USE SIGNAL ;
    ANTENNAGATEAREA 0.434700 ;
    ANTENNADIFFAREA 1.137600 ;
    PORT
      LAYER met3 ;
        RECT 0.000 130.600 0.600 131.200 ;
    END
  END s3_axi_wdata_0
  PIN s3_axi_wdata_1
    DIRECTION OUTPUT ;
    USE SIGNAL ;
    ANTENNAGATEAREA 0.434700 ;
    ANTENNADIFFAREA 1.137600 ;
    PORT
      LAYER met2 ;
        RECT 491.370 0.000 491.650 0.280 ;
    END
  END s3_axi_wdata_1
  PIN s3_axi_wdata_10
    DIRECTION OUTPUT ;
    USE SIGNAL ;
    ANTENNAGATEAREA 0.434700 ;
    ANTENNADIFFAREA 1.137600 ;
    PORT
      LAYER met2 ;
        RECT 192.370 519.840 192.650 520.120 ;
    END
  END s3_axi_wdata_10
  PIN s3_axi_wdata_11
    DIRECTION OUTPUT ;
    USE SIGNAL ;
    ANTENNAGATEAREA 0.434700 ;
    ANTENNADIFFAREA 1.137600 ;
    PORT
      LAYER met2 ;
        RECT 119.690 519.840 119.970 520.120 ;
    END
  END s3_axi_wdata_11
  PIN s3_axi_wdata_12
    DIRECTION OUTPUT ;
    USE SIGNAL ;
    ANTENNAGATEAREA 0.434700 ;
    ANTENNADIFFAREA 1.137600 ;
    PORT
      LAYER met3 ;
        RECT 0.000 84.360 0.600 84.960 ;
    END
  END s3_axi_wdata_12
  PIN s3_axi_wdata_13
    DIRECTION OUTPUT ;
    USE SIGNAL ;
    ANTENNAGATEAREA 0.434700 ;
    ANTENNADIFFAREA 1.137600 ;
    PORT
      LAYER met2 ;
        RECT 232.850 519.840 233.130 520.120 ;
    END
  END s3_axi_wdata_13
  PIN s3_axi_wdata_14
    DIRECTION OUTPUT ;
    USE SIGNAL ;
    ANTENNAGATEAREA 0.434700 ;
    ANTENNADIFFAREA 1.137600 ;
    PORT
      LAYER met2 ;
        RECT 366.250 519.840 366.530 520.120 ;
    END
  END s3_axi_wdata_14
  PIN s3_axi_wdata_15
    DIRECTION OUTPUT ;
    USE SIGNAL ;
    ANTENNAGATEAREA 0.434700 ;
    ANTENNADIFFAREA 1.137600 ;
    PORT
      LAYER met2 ;
        RECT 115.090 519.840 115.370 520.120 ;
    END
  END s3_axi_wdata_15
  PIN s3_axi_wdata_16
    DIRECTION OUTPUT ;
    USE SIGNAL ;
    ANTENNAGATEAREA 0.434700 ;
    ANTENNADIFFAREA 1.137600 ;
    PORT
      LAYER met3 ;
        RECT 0.000 402.600 0.600 403.200 ;
    END
  END s3_axi_wdata_16
  PIN s3_axi_wdata_17
    DIRECTION OUTPUT ;
    USE SIGNAL ;
    ANTENNAGATEAREA 0.434700 ;
    ANTENNADIFFAREA 1.137600 ;
    PORT
      LAYER met2 ;
        RECT 142.690 519.840 142.970 520.120 ;
    END
  END s3_axi_wdata_17
  PIN s3_axi_wdata_18
    DIRECTION OUTPUT ;
    USE SIGNAL ;
    ANTENNAGATEAREA 0.434700 ;
    ANTENNADIFFAREA 1.137600 ;
    PORT
      LAYER met2 ;
        RECT 385.570 0.000 385.850 0.280 ;
    END
  END s3_axi_wdata_18
  PIN s3_axi_wdata_19
    DIRECTION OUTPUT ;
    USE SIGNAL ;
    ANTENNAGATEAREA 0.434700 ;
    ANTENNADIFFAREA 1.137600 ;
    PORT
      LAYER met2 ;
        RECT 228.250 519.840 228.530 520.120 ;
    END
  END s3_axi_wdata_19
  PIN s3_axi_wdata_2
    DIRECTION OUTPUT ;
    USE SIGNAL ;
    ANTENNAGATEAREA 0.434700 ;
    ANTENNADIFFAREA 1.137600 ;
    PORT
      LAYER met2 ;
        RECT 212.610 519.840 212.890 520.120 ;
    END
  END s3_axi_wdata_2
  PIN s3_axi_wdata_20
    DIRECTION OUTPUT ;
    USE SIGNAL ;
    ANTENNAGATEAREA 0.434700 ;
    ANTENNADIFFAREA 1.137600 ;
    PORT
      LAYER met3 ;
        RECT 508.800 107.480 509.400 108.080 ;
    END
  END s3_axi_wdata_20
  PIN s3_axi_wdata_21
    DIRECTION OUTPUT ;
    USE SIGNAL ;
    ANTENNAGATEAREA 0.434700 ;
    ANTENNADIFFAREA 1.137600 ;
    PORT
      LAYER met2 ;
        RECT 96.690 519.840 96.970 520.120 ;
    END
  END s3_axi_wdata_21
  PIN s3_axi_wdata_22
    DIRECTION OUTPUT ;
    USE SIGNAL ;
    ANTENNAGATEAREA 0.434700 ;
    ANTENNADIFFAREA 1.137600 ;
    PORT
      LAYER met2 ;
        RECT 424.210 519.840 424.490 520.120 ;
    END
  END s3_axi_wdata_22
  PIN s3_axi_wdata_23
    DIRECTION OUTPUT ;
    USE SIGNAL ;
    ANTENNAGATEAREA 0.434700 ;
    ANTENNADIFFAREA 1.137600 ;
    PORT
      LAYER met3 ;
        RECT 0.000 383.560 0.600 384.160 ;
    END
  END s3_axi_wdata_23
  PIN s3_axi_wdata_24
    DIRECTION OUTPUT ;
    USE SIGNAL ;
    ANTENNAGATEAREA 0.434700 ;
    ANTENNADIFFAREA 1.137600 ;
    PORT
      LAYER met3 ;
        RECT 0.000 129.240 0.600 129.840 ;
    END
  END s3_axi_wdata_24
  PIN s3_axi_wdata_25
    DIRECTION OUTPUT ;
    USE SIGNAL ;
    ANTENNAGATEAREA 0.434700 ;
    ANTENNADIFFAREA 1.137600 ;
    PORT
      LAYER met2 ;
        RECT 65.410 519.840 65.690 520.120 ;
    END
  END s3_axi_wdata_25
  PIN s3_axi_wdata_26
    DIRECTION OUTPUT ;
    USE SIGNAL ;
    ANTENNAGATEAREA 0.434700 ;
    ANTENNADIFFAREA 1.137600 ;
    PORT
      LAYER met3 ;
        RECT 0.000 16.360 0.600 16.960 ;
    END
  END s3_axi_wdata_26
  PIN s3_axi_wdata_27
    DIRECTION OUTPUT ;
    USE SIGNAL ;
    ANTENNAGATEAREA 0.434700 ;
    ANTENNADIFFAREA 1.137600 ;
    PORT
      LAYER met2 ;
        RECT 139.010 519.840 139.290 520.120 ;
    END
  END s3_axi_wdata_27
  PIN s3_axi_wdata_28
    DIRECTION OUTPUT ;
    USE SIGNAL ;
    ANTENNAGATEAREA 0.434700 ;
    ANTENNADIFFAREA 1.137600 ;
    PORT
      LAYER met2 ;
        RECT 223.650 519.840 223.930 520.120 ;
    END
  END s3_axi_wdata_28
  PIN s3_axi_wdata_29
    DIRECTION OUTPUT ;
    USE SIGNAL ;
    ANTENNAGATEAREA 0.434700 ;
    ANTENNADIFFAREA 1.137600 ;
    PORT
      LAYER met2 ;
        RECT 453.650 0.000 453.930 0.280 ;
    END
  END s3_axi_wdata_29
  PIN s3_axi_wdata_3
    DIRECTION OUTPUT ;
    USE SIGNAL ;
    ANTENNAGATEAREA 0.434700 ;
    ANTENNADIFFAREA 1.137600 ;
    PORT
      LAYER met2 ;
        RECT 126.130 519.840 126.410 520.120 ;
    END
  END s3_axi_wdata_3
  PIN s3_axi_wdata_30
    DIRECTION OUTPUT ;
    USE SIGNAL ;
    ANTENNAGATEAREA 0.434700 ;
    ANTENNADIFFAREA 1.137600 ;
    PORT
      LAYER met2 ;
        RECT 479.410 0.000 479.690 0.280 ;
    END
  END s3_axi_wdata_30
  PIN s3_axi_wdata_31
    DIRECTION OUTPUT ;
    USE SIGNAL ;
    ANTENNAGATEAREA 0.434700 ;
    ANTENNADIFFAREA 1.137600 ;
    PORT
      LAYER met2 ;
        RECT 278.850 519.840 279.130 520.120 ;
    END
  END s3_axi_wdata_31
  PIN s3_axi_wdata_4
    DIRECTION OUTPUT ;
    USE SIGNAL ;
    ANTENNAGATEAREA 0.434700 ;
    ANTENNADIFFAREA 1.137600 ;
    PORT
      LAYER met3 ;
        RECT 0.000 77.560 0.600 78.160 ;
    END
  END s3_axi_wdata_4
  PIN s3_axi_wdata_5
    DIRECTION OUTPUT ;
    USE SIGNAL ;
    ANTENNAGATEAREA 0.434700 ;
    ANTENNADIFFAREA 1.137600 ;
    PORT
      LAYER met3 ;
        RECT 0.000 365.880 0.600 366.480 ;
    END
  END s3_axi_wdata_5
  PIN s3_axi_wdata_6
    DIRECTION OUTPUT ;
    USE SIGNAL ;
    ANTENNAGATEAREA 0.434700 ;
    ANTENNADIFFAREA 1.137600 ;
    PORT
      LAYER met2 ;
        RECT 414.090 0.000 414.370 0.280 ;
    END
  END s3_axi_wdata_6
  PIN s3_axi_wdata_7
    DIRECTION OUTPUT ;
    USE SIGNAL ;
    ANTENNAGATEAREA 0.434700 ;
    ANTENNADIFFAREA 1.137600 ;
    PORT
      LAYER met2 ;
        RECT 369.010 519.840 369.290 520.120 ;
    END
  END s3_axi_wdata_7
  PIN s3_axi_wdata_8
    DIRECTION OUTPUT ;
    USE SIGNAL ;
    ANTENNAGATEAREA 0.434700 ;
    ANTENNADIFFAREA 1.137600 ;
    PORT
      LAYER met2 ;
        RECT 421.450 0.000 421.730 0.280 ;
    END
  END s3_axi_wdata_8
  PIN s3_axi_wdata_9
    DIRECTION OUTPUT ;
    USE SIGNAL ;
    ANTENNAGATEAREA 0.434700 ;
    ANTENNADIFFAREA 1.137600 ;
    PORT
      LAYER met3 ;
        RECT 508.800 439.320 509.400 439.920 ;
    END
  END s3_axi_wdata_9
  PIN s3_axi_wready
    DIRECTION INPUT ;
    USE SIGNAL ;
    ANTENNAGATEAREA 0.647700 ;
    ANTENNADIFFAREA 0.434700 ;
    PORT
      LAYER met3 ;
        RECT 0.000 348.200 0.600 348.800 ;
    END
  END s3_axi_wready
  PIN s3_axi_wstrb_0
    DIRECTION OUTPUT ;
    USE SIGNAL ;
    ANTENNAGATEAREA 0.434700 ;
    ANTENNADIFFAREA 1.137600 ;
    PORT
      LAYER met2 ;
        RECT 256.770 519.840 257.050 520.120 ;
    END
  END s3_axi_wstrb_0
  PIN s3_axi_wstrb_1
    DIRECTION OUTPUT ;
    USE SIGNAL ;
    ANTENNAGATEAREA 0.434700 ;
    ANTENNADIFFAREA 1.137600 ;
    PORT
      LAYER met3 ;
        RECT 0.000 133.320 0.600 133.920 ;
    END
  END s3_axi_wstrb_1
  PIN s3_axi_wstrb_2
    DIRECTION OUTPUT ;
    USE SIGNAL ;
    ANTENNAGATEAREA 0.434700 ;
    ANTENNADIFFAREA 1.137600 ;
    PORT
      LAYER met2 ;
        RECT 420.530 519.840 420.810 520.120 ;
    END
  END s3_axi_wstrb_2
  PIN s3_axi_wstrb_3
    DIRECTION OUTPUT ;
    USE SIGNAL ;
    ANTENNAGATEAREA 0.434700 ;
    ANTENNADIFFAREA 1.137600 ;
    PORT
      LAYER met2 ;
        RECT 57.130 519.840 57.410 520.120 ;
    END
  END s3_axi_wstrb_3
  PIN s3_axi_wvalid
    DIRECTION OUTPUT ;
    USE SIGNAL ;
    ANTENNAGATEAREA 0.434700 ;
    ANTENNADIFFAREA 0.775300 ;
    PORT
      LAYER met3 ;
        RECT 508.800 403.960 509.400 404.560 ;
    END
  END s3_axi_wvalid
  PIN s4_axi_araddr_0
    DIRECTION OUTPUT ;
    USE SIGNAL ;
    ANTENNAGATEAREA 0.434700 ;
    ANTENNADIFFAREA 1.137600 ;
    PORT
      LAYER met2 ;
        RECT 391.090 0.000 391.370 0.280 ;
    END
  END s4_axi_araddr_0
  PIN s4_axi_araddr_1
    DIRECTION OUTPUT ;
    USE SIGNAL ;
    ANTENNAGATEAREA 0.434700 ;
    ANTENNADIFFAREA 1.137600 ;
    PORT
      LAYER met2 ;
        RECT 407.650 519.840 407.930 520.120 ;
    END
  END s4_axi_araddr_1
  PIN s4_axi_araddr_10
    DIRECTION OUTPUT ;
    USE SIGNAL ;
    ANTENNAGATEAREA 0.434700 ;
    ANTENNADIFFAREA 1.137600 ;
    PORT
      LAYER met2 ;
        RECT 215.370 519.840 215.650 520.120 ;
    END
  END s4_axi_araddr_10
  PIN s4_axi_araddr_11
    DIRECTION OUTPUT ;
    USE SIGNAL ;
    ANTENNAGATEAREA 0.434700 ;
    ANTENNADIFFAREA 1.137600 ;
    PORT
      LAYER met2 ;
        RECT 322.090 519.840 322.370 520.120 ;
    END
  END s4_axi_araddr_11
  PIN s4_axi_araddr_12
    DIRECTION OUTPUT ;
    USE SIGNAL ;
    ANTENNAGATEAREA 0.434700 ;
    ANTENNADIFFAREA 1.137600 ;
    PORT
      LAYER met2 ;
        RECT 89.330 519.840 89.610 520.120 ;
    END
  END s4_axi_araddr_12
  PIN s4_axi_araddr_13
    DIRECTION OUTPUT ;
    USE SIGNAL ;
    ANTENNAGATEAREA 0.434700 ;
    ANTENNADIFFAREA 1.137600 ;
    PORT
      LAYER met2 ;
        RECT 415.010 0.000 415.290 0.280 ;
    END
  END s4_axi_araddr_13
  PIN s4_axi_araddr_14
    DIRECTION OUTPUT ;
    USE SIGNAL ;
    ANTENNAGATEAREA 0.434700 ;
    ANTENNADIFFAREA 1.137600 ;
    PORT
      LAYER met2 ;
        RECT 480.330 0.000 480.610 0.280 ;
    END
  END s4_axi_araddr_14
  PIN s4_axi_araddr_15
    DIRECTION OUTPUT ;
    USE SIGNAL ;
    ANTENNAGATEAREA 0.434700 ;
    ANTENNADIFFAREA 1.137600 ;
    PORT
      LAYER met2 ;
        RECT 76.450 519.840 76.730 520.120 ;
    END
  END s4_axi_araddr_15
  PIN s4_axi_araddr_16
    DIRECTION OUTPUT ;
    USE SIGNAL ;
    ANTENNAGATEAREA 0.434700 ;
    ANTENNADIFFAREA 1.137600 ;
    PORT
      LAYER met2 ;
        RECT 181.330 519.840 181.610 520.120 ;
    END
  END s4_axi_araddr_16
  PIN s4_axi_araddr_17
    DIRECTION OUTPUT ;
    USE SIGNAL ;
    ANTENNAGATEAREA 0.434700 ;
    ANTENNADIFFAREA 1.137600 ;
    PORT
      LAYER met2 ;
        RECT 427.890 0.000 428.170 0.280 ;
    END
  END s4_axi_araddr_17
  PIN s4_axi_araddr_18
    DIRECTION OUTPUT ;
    USE SIGNAL ;
    ANTENNAGATEAREA 0.434700 ;
    ANTENNADIFFAREA 1.137600 ;
    PORT
      LAYER met2 ;
        RECT 492.290 0.000 492.570 0.280 ;
    END
  END s4_axi_araddr_18
  PIN s4_axi_araddr_19
    DIRECTION OUTPUT ;
    USE SIGNAL ;
    ANTENNAGATEAREA 0.434700 ;
    ANTENNADIFFAREA 1.137600 ;
    PORT
      LAYER met3 ;
        RECT 0.000 51.720 0.600 52.320 ;
    END
  END s4_axi_araddr_19
  PIN s4_axi_araddr_2
    DIRECTION OUTPUT ;
    USE SIGNAL ;
    ANTENNAGATEAREA 0.434700 ;
    ANTENNADIFFAREA 1.137600 ;
    PORT
      LAYER met3 ;
        RECT 0.000 28.600 0.600 29.200 ;
    END
  END s4_axi_araddr_2
  PIN s4_axi_araddr_20
    DIRECTION OUTPUT ;
    USE SIGNAL ;
    ANTENNAGATEAREA 0.434700 ;
    ANTENNADIFFAREA 1.137600 ;
    PORT
      LAYER met3 ;
        RECT 0.000 386.280 0.600 386.880 ;
    END
  END s4_axi_araddr_20
  PIN s4_axi_araddr_21
    DIRECTION OUTPUT ;
    USE SIGNAL ;
    ANTENNAGATEAREA 0.434700 ;
    ANTENNADIFFAREA 1.137600 ;
    PORT
      LAYER met2 ;
        RECT 144.530 519.840 144.810 520.120 ;
    END
  END s4_axi_araddr_21
  PIN s4_axi_araddr_22
    DIRECTION OUTPUT ;
    USE SIGNAL ;
    ANTENNAGATEAREA 0.434700 ;
    ANTENNADIFFAREA 1.137600 ;
    PORT
      LAYER met2 ;
        RECT 326.690 519.840 326.970 520.120 ;
    END
  END s4_axi_araddr_22
  PIN s4_axi_araddr_23
    DIRECTION OUTPUT ;
    USE SIGNAL ;
    ANTENNAGATEAREA 0.434700 ;
    ANTENNADIFFAREA 1.137600 ;
    PORT
      LAYER met3 ;
        RECT 0.000 100.680 0.600 101.280 ;
    END
  END s4_axi_araddr_23
  PIN s4_axi_araddr_24
    DIRECTION OUTPUT ;
    USE SIGNAL ;
    ANTENNAGATEAREA 0.434700 ;
    ANTENNADIFFAREA 1.137600 ;
    PORT
      LAYER met2 ;
        RECT 150.970 519.840 151.250 520.120 ;
    END
  END s4_axi_araddr_24
  PIN s4_axi_araddr_25
    DIRECTION OUTPUT ;
    USE SIGNAL ;
    ANTENNAGATEAREA 0.434700 ;
    ANTENNADIFFAREA 1.137600 ;
    PORT
      LAYER met2 ;
        RECT 50.690 519.840 50.970 520.120 ;
    END
  END s4_axi_araddr_25
  PIN s4_axi_araddr_26
    DIRECTION OUTPUT ;
    USE SIGNAL ;
    ANTENNAGATEAREA 0.434700 ;
    ANTENNADIFFAREA 1.137600 ;
    PORT
      LAYER met3 ;
        RECT 0.000 78.920 0.600 79.520 ;
    END
  END s4_axi_araddr_26
  PIN s4_axi_araddr_27
    DIRECTION OUTPUT ;
    USE SIGNAL ;
    ANTENNAGATEAREA 0.434700 ;
    ANTENNADIFFAREA 1.137600 ;
    PORT
      LAYER met2 ;
        RECT 395.690 519.840 395.970 520.120 ;
    END
  END s4_axi_araddr_27
  PIN s4_axi_araddr_28
    DIRECTION OUTPUT ;
    USE SIGNAL ;
    ANTENNAGATEAREA 0.434700 ;
    ANTENNADIFFAREA 1.137600 ;
    PORT
      LAYER met3 ;
        RECT 0.000 50.360 0.600 50.960 ;
    END
  END s4_axi_araddr_28
  PIN s4_axi_araddr_29
    DIRECTION OUTPUT ;
    USE SIGNAL ;
    ANTENNAGATEAREA 0.434700 ;
    ANTENNADIFFAREA 1.137600 ;
    PORT
      LAYER met2 ;
        RECT 100.370 519.840 100.650 520.120 ;
    END
  END s4_axi_araddr_29
  PIN s4_axi_araddr_3
    DIRECTION OUTPUT ;
    USE SIGNAL ;
    ANTENNAGATEAREA 0.434700 ;
    ANTENNADIFFAREA 1.137600 ;
    PORT
      LAYER met3 ;
        RECT 0.000 20.440 0.600 21.040 ;
    END
  END s4_axi_araddr_3
  PIN s4_axi_araddr_30
    DIRECTION OUTPUT ;
    USE SIGNAL ;
    ANTENNAGATEAREA 0.434700 ;
    ANTENNADIFFAREA 1.137600 ;
    PORT
      LAYER met2 ;
        RECT 68.170 519.840 68.450 520.120 ;
    END
  END s4_axi_araddr_30
  PIN s4_axi_araddr_31
    DIRECTION OUTPUT ;
    USE SIGNAL ;
    ANTENNAGATEAREA 0.434700 ;
    ANTENNADIFFAREA 1.137600 ;
    PORT
      LAYER met2 ;
        RECT 143.610 519.840 143.890 520.120 ;
    END
  END s4_axi_araddr_31
  PIN s4_axi_araddr_4
    DIRECTION OUTPUT ;
    USE SIGNAL ;
    ANTENNAGATEAREA 0.434700 ;
    ANTENNADIFFAREA 1.137600 ;
    PORT
      LAYER met2 ;
        RECT 312.890 519.840 313.170 520.120 ;
    END
  END s4_axi_araddr_4
  PIN s4_axi_araddr_5
    DIRECTION OUTPUT ;
    USE SIGNAL ;
    ANTENNAGATEAREA 0.434700 ;
    ANTENNADIFFAREA 1.137600 ;
    PORT
      LAYER met2 ;
        RECT 381.890 519.840 382.170 520.120 ;
    END
  END s4_axi_araddr_5
  PIN s4_axi_araddr_6
    DIRECTION OUTPUT ;
    USE SIGNAL ;
    ANTENNAGATEAREA 0.434700 ;
    ANTENNADIFFAREA 1.137600 ;
    PORT
      LAYER met2 ;
        RECT 444.450 0.000 444.730 0.280 ;
    END
  END s4_axi_araddr_6
  PIN s4_axi_araddr_7
    DIRECTION OUTPUT ;
    USE SIGNAL ;
    ANTENNAGATEAREA 0.434700 ;
    ANTENNADIFFAREA 1.137600 ;
    PORT
      LAYER met3 ;
        RECT 0.000 29.960 0.600 30.560 ;
    END
  END s4_axi_araddr_7
  PIN s4_axi_araddr_8
    DIRECTION OUTPUT ;
    USE SIGNAL ;
    ANTENNAGATEAREA 0.434700 ;
    ANTENNADIFFAREA 1.137600 ;
    PORT
      LAYER met2 ;
        RECT 376.370 0.000 376.650 0.280 ;
    END
  END s4_axi_araddr_8
  PIN s4_axi_araddr_9
    DIRECTION OUTPUT ;
    USE SIGNAL ;
    ANTENNAGATEAREA 0.434700 ;
    ANTENNADIFFAREA 1.137600 ;
    PORT
      LAYER met2 ;
        RECT 456.410 519.840 456.690 520.120 ;
    END
  END s4_axi_araddr_9
  PIN s4_axi_arready
    DIRECTION INPUT ;
    USE SIGNAL ;
    ANTENNAGATEAREA 0.647700 ;
    ANTENNADIFFAREA 0.434700 ;
    PORT
      LAYER met2 ;
        RECT 300.010 519.840 300.290 520.120 ;
    END
  END s4_axi_arready
  PIN s4_axi_arvalid
    DIRECTION OUTPUT ;
    USE SIGNAL ;
    ANTENNAGATEAREA 0.434700 ;
    ANTENNADIFFAREA 1.137600 ;
    PORT
      LAYER met2 ;
        RECT 218.130 519.840 218.410 520.120 ;
    END
  END s4_axi_arvalid
  PIN s4_axi_awaddr_0
    DIRECTION OUTPUT ;
    USE SIGNAL ;
    ANTENNAGATEAREA 0.434700 ;
    ANTENNADIFFAREA 1.137600 ;
    PORT
      LAYER met2 ;
        RECT 481.250 0.000 481.530 0.280 ;
    END
  END s4_axi_awaddr_0
  PIN s4_axi_awaddr_1
    DIRECTION OUTPUT ;
    USE SIGNAL ;
    ANTENNAGATEAREA 0.434700 ;
    ANTENNADIFFAREA 1.137600 ;
    PORT
      LAYER met2 ;
        RECT 445.370 0.000 445.650 0.280 ;
    END
  END s4_axi_awaddr_1
  PIN s4_axi_awaddr_10
    DIRECTION OUTPUT ;
    USE SIGNAL ;
    ANTENNAGATEAREA 0.434700 ;
    ANTENNADIFFAREA 1.137600 ;
    PORT
      LAYER met2 ;
        RECT 372.690 0.000 372.970 0.280 ;
    END
  END s4_axi_awaddr_10
  PIN s4_axi_awaddr_11
    DIRECTION OUTPUT ;
    USE SIGNAL ;
    ANTENNAGATEAREA 0.434700 ;
    ANTENNADIFFAREA 1.137600 ;
    PORT
      LAYER met2 ;
        RECT 423.290 0.000 423.570 0.280 ;
    END
  END s4_axi_awaddr_11
  PIN s4_axi_awaddr_12
    DIRECTION OUTPUT ;
    USE SIGNAL ;
    ANTENNAGATEAREA 0.434700 ;
    ANTENNADIFFAREA 1.137600 ;
    PORT
      LAYER met2 ;
        RECT 288.050 519.840 288.330 520.120 ;
    END
  END s4_axi_awaddr_12
  PIN s4_axi_awaddr_13
    DIRECTION OUTPUT ;
    USE SIGNAL ;
    ANTENNAGATEAREA 0.434700 ;
    ANTENNADIFFAREA 1.137600 ;
    PORT
      LAYER met3 ;
        RECT 508.800 122.440 509.400 123.040 ;
    END
  END s4_axi_awaddr_13
  PIN s4_axi_awaddr_14
    DIRECTION OUTPUT ;
    USE SIGNAL ;
    ANTENNAGATEAREA 0.434700 ;
    ANTENNADIFFAREA 1.137600 ;
    PORT
      LAYER met2 ;
        RECT 446.290 0.000 446.570 0.280 ;
    END
  END s4_axi_awaddr_14
  PIN s4_axi_awaddr_15
    DIRECTION OUTPUT ;
    USE SIGNAL ;
    ANTENNAGATEAREA 0.434700 ;
    ANTENNADIFFAREA 1.137600 ;
    PORT
      LAYER met2 ;
        RECT 74.610 519.840 74.890 520.120 ;
    END
  END s4_axi_awaddr_15
  PIN s4_axi_awaddr_16
    DIRECTION OUTPUT ;
    USE SIGNAL ;
    ANTENNAGATEAREA 0.434700 ;
    ANTENNADIFFAREA 1.137600 ;
    PORT
      LAYER met2 ;
        RECT 482.170 0.000 482.450 0.280 ;
    END
  END s4_axi_awaddr_16
  PIN s4_axi_awaddr_17
    DIRECTION OUTPUT ;
    USE SIGNAL ;
    ANTENNAGATEAREA 0.434700 ;
    ANTENNADIFFAREA 1.137600 ;
    PORT
      LAYER met2 ;
        RECT 360.730 519.840 361.010 520.120 ;
    END
  END s4_axi_awaddr_17
  PIN s4_axi_awaddr_18
    DIRECTION OUTPUT ;
    USE SIGNAL ;
    ANTENNAGATEAREA 0.434700 ;
    ANTENNADIFFAREA 1.137600 ;
    PORT
      LAYER met2 ;
        RECT 336.810 519.840 337.090 520.120 ;
    END
  END s4_axi_awaddr_18
  PIN s4_axi_awaddr_19
    DIRECTION OUTPUT ;
    USE SIGNAL ;
    ANTENNAGATEAREA 0.434700 ;
    ANTENNADIFFAREA 1.137600 ;
    PORT
      LAYER met3 ;
        RECT 508.800 450.200 509.400 450.800 ;
    END
  END s4_axi_awaddr_19
  PIN s4_axi_awaddr_2
    DIRECTION OUTPUT ;
    USE SIGNAL ;
    ANTENNAGATEAREA 0.434700 ;
    ANTENNADIFFAREA 1.137600 ;
    PORT
      LAYER met3 ;
        RECT 0.000 115.640 0.600 116.240 ;
    END
  END s4_axi_awaddr_2
  PIN s4_axi_awaddr_20
    DIRECTION OUTPUT ;
    USE SIGNAL ;
    ANTENNAGATEAREA 0.434700 ;
    ANTENNADIFFAREA 1.137600 ;
    PORT
      LAYER met3 ;
        RECT 0.000 107.480 0.600 108.080 ;
    END
  END s4_axi_awaddr_20
  PIN s4_axi_awaddr_21
    DIRECTION OUTPUT ;
    USE SIGNAL ;
    ANTENNAGATEAREA 0.434700 ;
    ANTENNADIFFAREA 1.137600 ;
    PORT
      LAYER met3 ;
        RECT 0.000 409.400 0.600 410.000 ;
    END
  END s4_axi_awaddr_21
  PIN s4_axi_awaddr_22
    DIRECTION OUTPUT ;
    USE SIGNAL ;
    ANTENNAGATEAREA 0.434700 ;
    ANTENNADIFFAREA 1.137600 ;
    PORT
      LAYER met2 ;
        RECT 392.010 0.000 392.290 0.280 ;
    END
  END s4_axi_awaddr_22
  PIN s4_axi_awaddr_23
    DIRECTION OUTPUT ;
    USE SIGNAL ;
    ANTENNAGATEAREA 0.434700 ;
    ANTENNADIFFAREA 1.137600 ;
    PORT
      LAYER met2 ;
        RECT 348.770 519.840 349.050 520.120 ;
    END
  END s4_axi_awaddr_23
  PIN s4_axi_awaddr_24
    DIRECTION OUTPUT ;
    USE SIGNAL ;
    ANTENNAGATEAREA 0.434700 ;
    ANTENNADIFFAREA 1.137600 ;
    PORT
      LAYER met2 ;
        RECT 174.890 519.840 175.170 520.120 ;
    END
  END s4_axi_awaddr_24
  PIN s4_axi_awaddr_25
    DIRECTION OUTPUT ;
    USE SIGNAL ;
    ANTENNAGATEAREA 0.434700 ;
    ANTENNADIFFAREA 1.137600 ;
    PORT
      LAYER met3 ;
        RECT 0.000 159.160 0.600 159.760 ;
    END
  END s4_axi_awaddr_25
  PIN s4_axi_awaddr_26
    DIRECTION OUTPUT ;
    USE SIGNAL ;
    ANTENNAGATEAREA 0.434700 ;
    ANTENNADIFFAREA 1.137600 ;
    PORT
      LAYER met2 ;
        RECT 168.450 519.840 168.730 520.120 ;
    END
  END s4_axi_awaddr_26
  PIN s4_axi_awaddr_27
    DIRECTION OUTPUT ;
    USE SIGNAL ;
    ANTENNAGATEAREA 0.434700 ;
    ANTENNADIFFAREA 1.137600 ;
    PORT
      LAYER met2 ;
        RECT 417.770 0.000 418.050 0.280 ;
    END
  END s4_axi_awaddr_27
  PIN s4_axi_awaddr_28
    DIRECTION OUTPUT ;
    USE SIGNAL ;
    ANTENNAGATEAREA 0.434700 ;
    ANTENNADIFFAREA 1.137600 ;
    PORT
      LAYER met2 ;
        RECT 380.970 0.000 381.250 0.280 ;
    END
  END s4_axi_awaddr_28
  PIN s4_axi_awaddr_29
    DIRECTION OUTPUT ;
    USE SIGNAL ;
    ANTENNAGATEAREA 0.434700 ;
    ANTENNADIFFAREA 1.137600 ;
    PORT
      LAYER met2 ;
        RECT 392.930 519.840 393.210 520.120 ;
    END
  END s4_axi_awaddr_29
  PIN s4_axi_awaddr_3
    DIRECTION OUTPUT ;
    USE SIGNAL ;
    ANTENNAGATEAREA 0.434700 ;
    ANTENNADIFFAREA 1.137600 ;
    PORT
      LAYER met3 ;
        RECT 0.000 72.120 0.600 72.720 ;
    END
  END s4_axi_awaddr_3
  PIN s4_axi_awaddr_30
    DIRECTION OUTPUT ;
    USE SIGNAL ;
    ANTENNAGATEAREA 0.434700 ;
    ANTENNADIFFAREA 1.137600 ;
    PORT
      LAYER met2 ;
        RECT 388.330 0.000 388.610 0.280 ;
    END
  END s4_axi_awaddr_30
  PIN s4_axi_awaddr_31
    DIRECTION OUTPUT ;
    USE SIGNAL ;
    ANTENNAGATEAREA 0.434700 ;
    ANTENNADIFFAREA 1.137600 ;
    PORT
      LAYER met2 ;
        RECT 265.050 519.840 265.330 520.120 ;
    END
  END s4_axi_awaddr_31
  PIN s4_axi_awaddr_4
    DIRECTION OUTPUT ;
    USE SIGNAL ;
    ANTENNAGATEAREA 0.434700 ;
    ANTENNADIFFAREA 1.137600 ;
    PORT
      LAYER met2 ;
        RECT 341.410 519.840 341.690 520.120 ;
    END
  END s4_axi_awaddr_4
  PIN s4_axi_awaddr_5
    DIRECTION OUTPUT ;
    USE SIGNAL ;
    ANTENNAGATEAREA 0.434700 ;
    ANTENNADIFFAREA 1.137600 ;
    PORT
      LAYER met2 ;
        RECT 447.210 0.000 447.490 0.280 ;
    END
  END s4_axi_awaddr_5
  PIN s4_axi_awaddr_6
    DIRECTION OUTPUT ;
    USE SIGNAL ;
    ANTENNAGATEAREA 0.434700 ;
    ANTENNADIFFAREA 1.137600 ;
    PORT
      LAYER met2 ;
        RECT 483.090 0.000 483.370 0.280 ;
    END
  END s4_axi_awaddr_6
  PIN s4_axi_awaddr_7
    DIRECTION OUTPUT ;
    USE SIGNAL ;
    ANTENNAGATEAREA 0.434700 ;
    ANTENNADIFFAREA 1.137600 ;
    PORT
      LAYER met3 ;
        RECT 0.000 38.120 0.600 38.720 ;
    END
  END s4_axi_awaddr_7
  PIN s4_axi_awaddr_8
    DIRECTION OUTPUT ;
    USE SIGNAL ;
    ANTENNAGATEAREA 0.434700 ;
    ANTENNADIFFAREA 1.137600 ;
    PORT
      LAYER met2 ;
        RECT 371.770 0.000 372.050 0.280 ;
    END
  END s4_axi_awaddr_8
  PIN s4_axi_awaddr_9
    DIRECTION OUTPUT ;
    USE SIGNAL ;
    ANTENNAGATEAREA 0.434700 ;
    ANTENNADIFFAREA 1.137600 ;
    PORT
      LAYER met3 ;
        RECT 508.800 505.960 509.400 506.560 ;
    END
  END s4_axi_awaddr_9
  PIN s4_axi_awready
    DIRECTION INPUT ;
    USE SIGNAL ;
    ANTENNAGATEAREA 0.647700 ;
    ANTENNADIFFAREA 0.434700 ;
    PORT
      LAYER met3 ;
        RECT 0.000 356.360 0.600 356.960 ;
    END
  END s4_axi_awready
  PIN s4_axi_awvalid
    DIRECTION OUTPUT ;
    USE SIGNAL ;
    ANTENNAGATEAREA 0.434700 ;
    ANTENNADIFFAREA 1.137600 ;
    PORT
      LAYER met3 ;
        RECT 0.000 140.120 0.600 140.720 ;
    END
  END s4_axi_awvalid
  PIN s4_axi_bready
    DIRECTION OUTPUT ;
    USE SIGNAL ;
    ANTENNAGATEAREA 0.434700 ;
    ANTENNADIFFAREA 1.137600 ;
    PORT
      LAYER met3 ;
        RECT 0.000 121.080 0.600 121.680 ;
    END
  END s4_axi_bready
  PIN s4_axi_bresp_0
    DIRECTION INPUT ;
    USE SIGNAL ;
    ANTENNAGATEAREA 0.647700 ;
    ANTENNADIFFAREA 0.434700 ;
    PORT
      LAYER met3 ;
        RECT 0.000 303.320 0.600 303.920 ;
    END
  END s4_axi_bresp_0
  PIN s4_axi_bresp_1
    DIRECTION INPUT ;
    USE SIGNAL ;
    ANTENNAGATEAREA 0.647700 ;
    ANTENNADIFFAREA 0.434700 ;
    PORT
      LAYER met3 ;
        RECT 0.000 307.400 0.600 308.000 ;
    END
  END s4_axi_bresp_1
  PIN s4_axi_bvalid
    DIRECTION INPUT ;
    USE SIGNAL ;
    ANTENNAGATEAREA 0.647700 ;
    ANTENNADIFFAREA 0.434700 ;
    PORT
      LAYER met3 ;
        RECT 0.000 355.000 0.600 355.600 ;
    END
  END s4_axi_bvalid
  PIN s4_axi_rdata_0
    DIRECTION INPUT ;
    USE SIGNAL ;
    ANTENNAGATEAREA 0.647700 ;
    ANTENNADIFFAREA 0.434700 ;
    PORT
      LAYER met3 ;
        RECT 508.800 81.640 509.400 82.240 ;
    END
  END s4_axi_rdata_0
  PIN s4_axi_rdata_1
    DIRECTION INPUT ;
    USE SIGNAL ;
    ANTENNAGATEAREA 0.647700 ;
    ANTENNADIFFAREA 0.434700 ;
    PORT
      LAYER met2 ;
        RECT 297.250 519.840 297.530 520.120 ;
    END
  END s4_axi_rdata_1
  PIN s4_axi_rdata_10
    DIRECTION INPUT ;
    USE SIGNAL ;
    ANTENNAGATEAREA 0.647700 ;
    ANTENNADIFFAREA 0.434700 ;
    PORT
      LAYER met3 ;
        RECT 508.800 291.080 509.400 291.680 ;
    END
  END s4_axi_rdata_10
  PIN s4_axi_rdata_11
    DIRECTION INPUT ;
    USE SIGNAL ;
    ANTENNAGATEAREA 0.647700 ;
    ANTENNADIFFAREA 0.434700 ;
    PORT
      LAYER met3 ;
        RECT 508.800 146.920 509.400 147.520 ;
    END
  END s4_axi_rdata_11
  PIN s4_axi_rdata_12
    DIRECTION INPUT ;
    USE SIGNAL ;
    ANTENNAGATEAREA 0.647700 ;
    ANTENNADIFFAREA 0.434700 ;
    PORT
      LAYER met3 ;
        RECT 508.800 157.800 509.400 158.400 ;
    END
  END s4_axi_rdata_12
  PIN s4_axi_rdata_13
    DIRECTION INPUT ;
    USE SIGNAL ;
    ANTENNAGATEAREA 0.647700 ;
    ANTENNADIFFAREA 0.434700 ;
    PORT
      LAYER met3 ;
        RECT 508.800 199.960 509.400 200.560 ;
    END
  END s4_axi_rdata_13
  PIN s4_axi_rdata_14
    DIRECTION INPUT ;
    USE SIGNAL ;
    ANTENNAGATEAREA 0.647700 ;
    ANTENNADIFFAREA 0.434700 ;
    PORT
      LAYER met3 ;
        RECT 508.800 435.240 509.400 435.840 ;
    END
  END s4_axi_rdata_14
  PIN s4_axi_rdata_15
    DIRECTION INPUT ;
    USE SIGNAL ;
    ANTENNAGATEAREA 0.647700 ;
    ANTENNADIFFAREA 0.434700 ;
    PORT
      LAYER met3 ;
        RECT 508.800 201.320 509.400 201.920 ;
    END
  END s4_axi_rdata_15
  PIN s4_axi_rdata_16
    DIRECTION INPUT ;
    USE SIGNAL ;
    ANTENNAGATEAREA 0.647700 ;
    ANTENNADIFFAREA 0.434700 ;
    PORT
      LAYER met3 ;
        RECT 508.800 155.080 509.400 155.680 ;
    END
  END s4_axi_rdata_16
  PIN s4_axi_rdata_17
    DIRECTION INPUT ;
    USE SIGNAL ;
    ANTENNAGATEAREA 0.647700 ;
    ANTENNADIFFAREA 0.434700 ;
    PORT
      LAYER met3 ;
        RECT 508.800 301.960 509.400 302.560 ;
    END
  END s4_axi_rdata_17
  PIN s4_axi_rdata_18
    DIRECTION INPUT ;
    USE SIGNAL ;
    ANTENNAGATEAREA 0.647700 ;
    ANTENNADIFFAREA 0.434700 ;
    PORT
      LAYER met3 ;
        RECT 508.800 195.880 509.400 196.480 ;
    END
  END s4_axi_rdata_18
  PIN s4_axi_rdata_19
    DIRECTION INPUT ;
    USE SIGNAL ;
    ANTENNAGATEAREA 0.647700 ;
    ANTENNADIFFAREA 0.434700 ;
    PORT
      LAYER met3 ;
        RECT 508.800 277.480 509.400 278.080 ;
    END
  END s4_axi_rdata_19
  PIN s4_axi_rdata_2
    DIRECTION INPUT ;
    USE SIGNAL ;
    ANTENNAGATEAREA 0.647700 ;
    ANTENNADIFFAREA 0.434700 ;
    PORT
      LAYER met3 ;
        RECT 508.800 208.120 509.400 208.720 ;
    END
  END s4_axi_rdata_2
  PIN s4_axi_rdata_20
    DIRECTION INPUT ;
    USE SIGNAL ;
    ANTENNAGATEAREA 0.647700 ;
    ANTENNADIFFAREA 0.434700 ;
    PORT
      LAYER met3 ;
        RECT 508.800 242.120 509.400 242.720 ;
    END
  END s4_axi_rdata_20
  PIN s4_axi_rdata_21
    DIRECTION INPUT ;
    USE SIGNAL ;
    ANTENNAGATEAREA 0.647700 ;
    ANTENNADIFFAREA 0.434700 ;
    PORT
      LAYER met3 ;
        RECT 508.800 349.560 509.400 350.160 ;
    END
  END s4_axi_rdata_21
  PIN s4_axi_rdata_22
    DIRECTION INPUT ;
    USE SIGNAL ;
    ANTENNAGATEAREA 0.647700 ;
    ANTENNADIFFAREA 0.434700 ;
    PORT
      LAYER met3 ;
        RECT 508.800 261.160 509.400 261.760 ;
    END
  END s4_axi_rdata_22
  PIN s4_axi_rdata_23
    DIRECTION INPUT ;
    USE SIGNAL ;
    ANTENNAGATEAREA 0.647700 ;
    ANTENNADIFFAREA 0.434700 ;
    PORT
      LAYER met3 ;
        RECT 508.800 198.600 509.400 199.200 ;
    END
  END s4_axi_rdata_23
  PIN s4_axi_rdata_24
    DIRECTION INPUT ;
    USE SIGNAL ;
    ANTENNAGATEAREA 0.647700 ;
    ANTENNADIFFAREA 0.434700 ;
    PORT
      LAYER met2 ;
        RECT 306.450 519.840 306.730 520.120 ;
    END
  END s4_axi_rdata_24
  PIN s4_axi_rdata_25
    DIRECTION INPUT ;
    USE SIGNAL ;
    ANTENNAGATEAREA 0.647700 ;
    ANTENNADIFFAREA 0.434700 ;
    PORT
      LAYER met3 ;
        RECT 508.800 398.520 509.400 399.120 ;
    END
  END s4_axi_rdata_25
  PIN s4_axi_rdata_26
    DIRECTION INPUT ;
    USE SIGNAL ;
    ANTENNAGATEAREA 0.647700 ;
    ANTENNADIFFAREA 0.434700 ;
    PORT
      LAYER met3 ;
        RECT 508.800 175.480 509.400 176.080 ;
    END
  END s4_axi_rdata_26
  PIN s4_axi_rdata_27
    DIRECTION INPUT ;
    USE SIGNAL ;
    ANTENNAGATEAREA 0.647700 ;
    ANTENNADIFFAREA 0.434700 ;
    PORT
      LAYER met3 ;
        RECT 508.800 217.640 509.400 218.240 ;
    END
  END s4_axi_rdata_27
  PIN s4_axi_rdata_28
    DIRECTION INPUT ;
    USE SIGNAL ;
    ANTENNAGATEAREA 0.647700 ;
    ANTENNADIFFAREA 0.434700 ;
    PORT
      LAYER met3 ;
        RECT 508.800 145.560 509.400 146.160 ;
    END
  END s4_axi_rdata_28
  PIN s4_axi_rdata_29
    DIRECTION INPUT ;
    USE SIGNAL ;
    ANTENNAGATEAREA 0.647700 ;
    ANTENNADIFFAREA 0.434700 ;
    PORT
      LAYER met3 ;
        RECT 508.800 311.480 509.400 312.080 ;
    END
  END s4_axi_rdata_29
  PIN s4_axi_rdata_3
    DIRECTION INPUT ;
    USE SIGNAL ;
    ANTENNAGATEAREA 0.647700 ;
    ANTENNADIFFAREA 0.434700 ;
    PORT
      LAYER met3 ;
        RECT 508.800 350.920 509.400 351.520 ;
    END
  END s4_axi_rdata_3
  PIN s4_axi_rdata_30
    DIRECTION INPUT ;
    USE SIGNAL ;
    ANTENNAGATEAREA 0.647700 ;
    ANTENNADIFFAREA 0.434700 ;
    PORT
      LAYER met3 ;
        RECT 508.800 160.520 509.400 161.120 ;
    END
  END s4_axi_rdata_30
  PIN s4_axi_rdata_31
    DIRECTION INPUT ;
    USE SIGNAL ;
    ANTENNAGATEAREA 0.647700 ;
    ANTENNADIFFAREA 0.434700 ;
    PORT
      LAYER met3 ;
        RECT 508.800 418.920 509.400 419.520 ;
    END
  END s4_axi_rdata_31
  PIN s4_axi_rdata_4
    DIRECTION INPUT ;
    USE SIGNAL ;
    ANTENNAGATEAREA 0.647700 ;
    ANTENNADIFFAREA 0.434700 ;
    PORT
      LAYER met2 ;
        RECT 298.170 519.840 298.450 520.120 ;
    END
  END s4_axi_rdata_4
  PIN s4_axi_rdata_5
    DIRECTION INPUT ;
    USE SIGNAL ;
    ANTENNAGATEAREA 0.647700 ;
    ANTENNADIFFAREA 0.434700 ;
    PORT
      LAYER met3 ;
        RECT 508.800 243.480 509.400 244.080 ;
    END
  END s4_axi_rdata_5
  PIN s4_axi_rdata_6
    DIRECTION INPUT ;
    USE SIGNAL ;
    ANTENNAGATEAREA 0.647700 ;
    ANTENNADIFFAREA 0.434700 ;
    PORT
      LAYER met3 ;
        RECT 508.800 389.000 509.400 389.600 ;
    END
  END s4_axi_rdata_6
  PIN s4_axi_rdata_7
    DIRECTION INPUT ;
    USE SIGNAL ;
    ANTENNAGATEAREA 0.647700 ;
    ANTENNADIFFAREA 0.434700 ;
    PORT
      LAYER met3 ;
        RECT 508.800 380.840 509.400 381.440 ;
    END
  END s4_axi_rdata_7
  PIN s4_axi_rdata_8
    DIRECTION INPUT ;
    USE SIGNAL ;
    ANTENNAGATEAREA 0.647700 ;
    ANTENNADIFFAREA 0.434700 ;
    PORT
      LAYER met3 ;
        RECT 508.800 327.800 509.400 328.400 ;
    END
  END s4_axi_rdata_8
  PIN s4_axi_rdata_9
    DIRECTION INPUT ;
    USE SIGNAL ;
    ANTENNAGATEAREA 0.647700 ;
    ANTENNADIFFAREA 0.434700 ;
    PORT
      LAYER met3 ;
        RECT 508.800 54.440 509.400 55.040 ;
    END
  END s4_axi_rdata_9
  PIN s4_axi_rready
    DIRECTION OUTPUT ;
    USE SIGNAL ;
    ANTENNAGATEAREA 0.434700 ;
    ANTENNADIFFAREA 1.137600 ;
    PORT
      LAYER met3 ;
        RECT 0.000 190.440 0.600 191.040 ;
    END
  END s4_axi_rready
  PIN s4_axi_rresp_0
    DIRECTION INPUT ;
    USE SIGNAL ;
    ANTENNAGATEAREA 0.647700 ;
    ANTENNADIFFAREA 0.434700 ;
    PORT
      LAYER met3 ;
        RECT 508.800 416.200 509.400 416.800 ;
    END
  END s4_axi_rresp_0
  PIN s4_axi_rresp_1
    DIRECTION INPUT ;
    USE SIGNAL ;
    ANTENNAGATEAREA 0.647700 ;
    ANTENNADIFFAREA 0.434700 ;
    PORT
      LAYER met3 ;
        RECT 508.800 156.440 509.400 157.040 ;
    END
  END s4_axi_rresp_1
  PIN s4_axi_rvalid
    DIRECTION INPUT ;
    USE SIGNAL ;
    ANTENNAGATEAREA 0.647700 ;
    ANTENNADIFFAREA 0.434700 ;
    PORT
      LAYER met3 ;
        RECT 508.800 489.640 509.400 490.240 ;
    END
  END s4_axi_rvalid
  PIN s4_axi_wdata_0
    DIRECTION OUTPUT ;
    USE SIGNAL ;
    ANTENNAGATEAREA 0.434700 ;
    ANTENNADIFFAREA 1.137600 ;
    PORT
      LAYER met3 ;
        RECT 0.000 102.040 0.600 102.640 ;
    END
  END s4_axi_wdata_0
  PIN s4_axi_wdata_1
    DIRECTION OUTPUT ;
    USE SIGNAL ;
    ANTENNAGATEAREA 0.434700 ;
    ANTENNADIFFAREA 1.137600 ;
    PORT
      LAYER met2 ;
        RECT 390.170 0.000 390.450 0.280 ;
    END
  END s4_axi_wdata_1
  PIN s4_axi_wdata_10
    DIRECTION OUTPUT ;
    USE SIGNAL ;
    ANTENNAGATEAREA 0.434700 ;
    ANTENNADIFFAREA 1.137600 ;
    PORT
      LAYER met2 ;
        RECT 190.530 519.840 190.810 520.120 ;
    END
  END s4_axi_wdata_10
  PIN s4_axi_wdata_11
    DIRECTION OUTPUT ;
    USE SIGNAL ;
    ANTENNAGATEAREA 0.434700 ;
    ANTENNADIFFAREA 1.137600 ;
    PORT
      LAYER met2 ;
        RECT 137.170 519.840 137.450 520.120 ;
    END
  END s4_axi_wdata_11
  PIN s4_axi_wdata_12
    DIRECTION OUTPUT ;
    USE SIGNAL ;
    ANTENNAGATEAREA 0.434700 ;
    ANTENNADIFFAREA 1.137600 ;
    PORT
      LAYER met3 ;
        RECT 0.000 85.720 0.600 86.320 ;
    END
  END s4_axi_wdata_12
  PIN s4_axi_wdata_13
    DIRECTION OUTPUT ;
    USE SIGNAL ;
    ANTENNAGATEAREA 0.434700 ;
    ANTENNADIFFAREA 1.137600 ;
    PORT
      LAYER met2 ;
        RECT 235.610 519.840 235.890 520.120 ;
    END
  END s4_axi_wdata_13
  PIN s4_axi_wdata_14
    DIRECTION OUTPUT ;
    USE SIGNAL ;
    ANTENNAGATEAREA 0.434700 ;
    ANTENNADIFFAREA 1.137600 ;
    PORT
      LAYER met2 ;
        RECT 362.570 519.840 362.850 520.120 ;
    END
  END s4_axi_wdata_14
  PIN s4_axi_wdata_15
    DIRECTION OUTPUT ;
    USE SIGNAL ;
    ANTENNAGATEAREA 0.434700 ;
    ANTENNADIFFAREA 1.137600 ;
    PORT
      LAYER met2 ;
        RECT 108.650 519.840 108.930 520.120 ;
    END
  END s4_axi_wdata_15
  PIN s4_axi_wdata_16
    DIRECTION OUTPUT ;
    USE SIGNAL ;
    ANTENNAGATEAREA 0.434700 ;
    ANTENNADIFFAREA 1.137600 ;
    PORT
      LAYER met3 ;
        RECT 0.000 375.400 0.600 376.000 ;
    END
  END s4_axi_wdata_16
  PIN s4_axi_wdata_17
    DIRECTION OUTPUT ;
    USE SIGNAL ;
    ANTENNAGATEAREA 0.434700 ;
    ANTENNADIFFAREA 1.137600 ;
    PORT
      LAYER met2 ;
        RECT 164.770 519.840 165.050 520.120 ;
    END
  END s4_axi_wdata_17
  PIN s4_axi_wdata_18
    DIRECTION OUTPUT ;
    USE SIGNAL ;
    ANTENNAGATEAREA 0.434700 ;
    ANTENNADIFFAREA 1.137600 ;
    PORT
      LAYER met2 ;
        RECT 380.050 0.000 380.330 0.280 ;
    END
  END s4_axi_wdata_18
  PIN s4_axi_wdata_19
    DIRECTION OUTPUT ;
    USE SIGNAL ;
    ANTENNAGATEAREA 0.434700 ;
    ANTENNADIFFAREA 1.137600 ;
    PORT
      LAYER met2 ;
        RECT 238.370 519.840 238.650 520.120 ;
    END
  END s4_axi_wdata_19
  PIN s4_axi_wdata_2
    DIRECTION OUTPUT ;
    USE SIGNAL ;
    ANTENNAGATEAREA 0.434700 ;
    ANTENNADIFFAREA 1.137600 ;
    PORT
      LAYER met2 ;
        RECT 208.010 519.840 208.290 520.120 ;
    END
  END s4_axi_wdata_2
  PIN s4_axi_wdata_20
    DIRECTION OUTPUT ;
    USE SIGNAL ;
    ANTENNAGATEAREA 0.434700 ;
    ANTENNADIFFAREA 1.137600 ;
    PORT
      LAYER met3 ;
        RECT 508.800 110.200 509.400 110.800 ;
    END
  END s4_axi_wdata_20
  PIN s4_axi_wdata_21
    DIRECTION OUTPUT ;
    USE SIGNAL ;
    ANTENNAGATEAREA 0.434700 ;
    ANTENNADIFFAREA 1.137600 ;
    PORT
      LAYER met2 ;
        RECT 80.130 519.840 80.410 520.120 ;
    END
  END s4_axi_wdata_21
  PIN s4_axi_wdata_22
    DIRECTION OUTPUT ;
    USE SIGNAL ;
    ANTENNAGATEAREA 0.434700 ;
    ANTENNADIFFAREA 1.137600 ;
    PORT
      LAYER met2 ;
        RECT 425.130 519.840 425.410 520.120 ;
    END
  END s4_axi_wdata_22
  PIN s4_axi_wdata_23
    DIRECTION OUTPUT ;
    USE SIGNAL ;
    ANTENNAGATEAREA 0.434700 ;
    ANTENNADIFFAREA 1.137600 ;
    PORT
      LAYER met3 ;
        RECT 0.000 379.480 0.600 380.080 ;
    END
  END s4_axi_wdata_23
  PIN s4_axi_wdata_24
    DIRECTION OUTPUT ;
    USE SIGNAL ;
    ANTENNAGATEAREA 0.434700 ;
    ANTENNADIFFAREA 1.137600 ;
    PORT
      LAYER met3 ;
        RECT 0.000 127.880 0.600 128.480 ;
    END
  END s4_axi_wdata_24
  PIN s4_axi_wdata_25
    DIRECTION OUTPUT ;
    USE SIGNAL ;
    ANTENNAGATEAREA 0.434700 ;
    ANTENNADIFFAREA 1.137600 ;
    PORT
      LAYER met2 ;
        RECT 58.970 519.840 59.250 520.120 ;
    END
  END s4_axi_wdata_25
  PIN s4_axi_wdata_26
    DIRECTION OUTPUT ;
    USE SIGNAL ;
    ANTENNAGATEAREA 0.434700 ;
    ANTENNADIFFAREA 1.137600 ;
    PORT
      LAYER met3 ;
        RECT 0.000 24.520 0.600 25.120 ;
    END
  END s4_axi_wdata_26
  PIN s4_axi_wdata_27
    DIRECTION OUTPUT ;
    USE SIGNAL ;
    ANTENNAGATEAREA 0.434700 ;
    ANTENNADIFFAREA 1.137600 ;
    PORT
      LAYER met2 ;
        RECT 135.330 519.840 135.610 520.120 ;
    END
  END s4_axi_wdata_27
  PIN s4_axi_wdata_28
    DIRECTION OUTPUT ;
    USE SIGNAL ;
    ANTENNAGATEAREA 0.434700 ;
    ANTENNADIFFAREA 1.137600 ;
    PORT
      LAYER met2 ;
        RECT 219.970 519.840 220.250 520.120 ;
    END
  END s4_axi_wdata_28
  PIN s4_axi_wdata_29
    DIRECTION OUTPUT ;
    USE SIGNAL ;
    ANTENNAGATEAREA 0.434700 ;
    ANTENNADIFFAREA 1.137600 ;
    PORT
      LAYER met2 ;
        RECT 451.810 0.000 452.090 0.280 ;
    END
  END s4_axi_wdata_29
  PIN s4_axi_wdata_3
    DIRECTION OUTPUT ;
    USE SIGNAL ;
    ANTENNAGATEAREA 0.434700 ;
    ANTENNADIFFAREA 1.137600 ;
    PORT
      LAYER met2 ;
        RECT 136.250 519.840 136.530 520.120 ;
    END
  END s4_axi_wdata_3
  PIN s4_axi_wdata_30
    DIRECTION OUTPUT ;
    USE SIGNAL ;
    ANTENNAGATEAREA 0.434700 ;
    ANTENNADIFFAREA 1.137600 ;
    PORT
      LAYER met2 ;
        RECT 484.010 0.000 484.290 0.280 ;
    END
  END s4_axi_wdata_30
  PIN s4_axi_wdata_31
    DIRECTION OUTPUT ;
    USE SIGNAL ;
    ANTENNAGATEAREA 0.434700 ;
    ANTENNADIFFAREA 1.137600 ;
    PORT
      LAYER met2 ;
        RECT 279.770 519.840 280.050 520.120 ;
    END
  END s4_axi_wdata_31
  PIN s4_axi_wdata_4
    DIRECTION OUTPUT ;
    USE SIGNAL ;
    ANTENNAGATEAREA 0.434700 ;
    ANTENNADIFFAREA 1.137600 ;
    PORT
      LAYER met3 ;
        RECT 0.000 63.960 0.600 64.560 ;
    END
  END s4_axi_wdata_4
  PIN s4_axi_wdata_5
    DIRECTION OUTPUT ;
    USE SIGNAL ;
    ANTENNAGATEAREA 0.434700 ;
    ANTENNADIFFAREA 1.137600 ;
    PORT
      LAYER met3 ;
        RECT 0.000 367.240 0.600 367.840 ;
    END
  END s4_axi_wdata_5
  PIN s4_axi_wdata_6
    DIRECTION OUTPUT ;
    USE SIGNAL ;
    ANTENNAGATEAREA 0.434700 ;
    ANTENNADIFFAREA 1.137600 ;
    PORT
      LAYER met2 ;
        RECT 412.250 0.000 412.530 0.280 ;
    END
  END s4_axi_wdata_6
  PIN s4_axi_wdata_7
    DIRECTION OUTPUT ;
    USE SIGNAL ;
    ANTENNAGATEAREA 0.434700 ;
    ANTENNADIFFAREA 1.137600 ;
    PORT
      LAYER met2 ;
        RECT 367.170 519.840 367.450 520.120 ;
    END
  END s4_axi_wdata_7
  PIN s4_axi_wdata_8
    DIRECTION OUTPUT ;
    USE SIGNAL ;
    ANTENNAGATEAREA 0.434700 ;
    ANTENNADIFFAREA 1.137600 ;
    PORT
      LAYER met2 ;
        RECT 426.050 0.000 426.330 0.280 ;
    END
  END s4_axi_wdata_8
  PIN s4_axi_wdata_9
    DIRECTION OUTPUT ;
    USE SIGNAL ;
    ANTENNAGATEAREA 0.434700 ;
    ANTENNADIFFAREA 1.137600 ;
    PORT
      LAYER met3 ;
        RECT 508.800 412.120 509.400 412.720 ;
    END
  END s4_axi_wdata_9
  PIN s4_axi_wready
    DIRECTION INPUT ;
    USE SIGNAL ;
    ANTENNAGATEAREA 0.647700 ;
    ANTENNADIFFAREA 0.434700 ;
    PORT
      LAYER met3 ;
        RECT 0.000 357.720 0.600 358.320 ;
    END
  END s4_axi_wready
  PIN s4_axi_wstrb_0
    DIRECTION OUTPUT ;
    USE SIGNAL ;
    ANTENNAGATEAREA 0.434700 ;
    ANTENNADIFFAREA 1.137600 ;
    PORT
      LAYER met2 ;
        RECT 261.370 519.840 261.650 520.120 ;
    END
  END s4_axi_wstrb_0
  PIN s4_axi_wstrb_1
    DIRECTION OUTPUT ;
    USE SIGNAL ;
    ANTENNAGATEAREA 0.434700 ;
    ANTENNADIFFAREA 1.137600 ;
    PORT
      LAYER met3 ;
        RECT 0.000 93.880 0.600 94.480 ;
    END
  END s4_axi_wstrb_1
  PIN s4_axi_wstrb_2
    DIRECTION OUTPUT ;
    USE SIGNAL ;
    ANTENNAGATEAREA 0.434700 ;
    ANTENNADIFFAREA 1.137600 ;
    PORT
      LAYER met2 ;
        RECT 417.770 519.840 418.050 520.120 ;
    END
  END s4_axi_wstrb_2
  PIN s4_axi_wstrb_3
    DIRECTION OUTPUT ;
    USE SIGNAL ;
    ANTENNAGATEAREA 0.434700 ;
    ANTENNADIFFAREA 1.137600 ;
    PORT
      LAYER met2 ;
        RECT 63.570 519.840 63.850 520.120 ;
    END
  END s4_axi_wstrb_3
  PIN s4_axi_wvalid
    DIRECTION OUTPUT ;
    USE SIGNAL ;
    ANTENNAGATEAREA 0.434700 ;
    ANTENNADIFFAREA 1.137600 ;
    PORT
      LAYER met3 ;
        RECT 0.000 153.720 0.600 154.320 ;
    END
  END s4_axi_wvalid
  PIN s5_axi_araddr_0
    DIRECTION OUTPUT ;
    USE SIGNAL ;
    ANTENNAGATEAREA 0.434700 ;
    ANTENNADIFFAREA 1.137600 ;
    PORT
      LAYER met2 ;
        RECT 418.690 0.000 418.970 0.280 ;
    END
  END s5_axi_araddr_0
  PIN s5_axi_araddr_1
    DIRECTION OUTPUT ;
    USE SIGNAL ;
    ANTENNAGATEAREA 0.434700 ;
    ANTENNADIFFAREA 1.137600 ;
    PORT
      LAYER met2 ;
        RECT 403.050 519.840 403.330 520.120 ;
    END
  END s5_axi_araddr_1
  PIN s5_axi_araddr_10
    DIRECTION OUTPUT ;
    USE SIGNAL ;
    ANTENNAGATEAREA 0.434700 ;
    ANTENNADIFFAREA 1.137600 ;
    PORT
      LAYER met2 ;
        RECT 211.690 519.840 211.970 520.120 ;
    END
  END s5_axi_araddr_10
  PIN s5_axi_araddr_11
    DIRECTION OUTPUT ;
    USE SIGNAL ;
    ANTENNAGATEAREA 0.434700 ;
    ANTENNADIFFAREA 1.137600 ;
    PORT
      LAYER met2 ;
        RECT 323.010 519.840 323.290 520.120 ;
    END
  END s5_axi_araddr_11
  PIN s5_axi_araddr_12
    DIRECTION OUTPUT ;
    USE SIGNAL ;
    ANTENNAGATEAREA 0.434700 ;
    ANTENNADIFFAREA 1.137600 ;
    PORT
      LAYER met2 ;
        RECT 88.410 519.840 88.690 520.120 ;
    END
  END s5_axi_araddr_12
  PIN s5_axi_araddr_13
    DIRECTION OUTPUT ;
    USE SIGNAL ;
    ANTENNAGATEAREA 0.434700 ;
    ANTENNADIFFAREA 1.137600 ;
    PORT
      LAYER met2 ;
        RECT 433.410 0.000 433.690 0.280 ;
    END
  END s5_axi_araddr_13
  PIN s5_axi_araddr_14
    DIRECTION OUTPUT ;
    USE SIGNAL ;
    ANTENNAGATEAREA 0.434700 ;
    ANTENNADIFFAREA 1.137600 ;
    PORT
      LAYER met2 ;
        RECT 484.930 0.000 485.210 0.280 ;
    END
  END s5_axi_araddr_14
  PIN s5_axi_araddr_15
    DIRECTION OUTPUT ;
    USE SIGNAL ;
    ANTENNAGATEAREA 0.434700 ;
    ANTENNADIFFAREA 1.137600 ;
    PORT
      LAYER met2 ;
        RECT 114.170 519.840 114.450 520.120 ;
    END
  END s5_axi_araddr_15
  PIN s5_axi_araddr_16
    DIRECTION OUTPUT ;
    USE SIGNAL ;
    ANTENNAGATEAREA 0.434700 ;
    ANTENNADIFFAREA 1.137600 ;
    PORT
      LAYER met2 ;
        RECT 180.410 519.840 180.690 520.120 ;
    END
  END s5_axi_araddr_16
  PIN s5_axi_araddr_17
    DIRECTION OUTPUT ;
    USE SIGNAL ;
    ANTENNAGATEAREA 0.434700 ;
    ANTENNADIFFAREA 1.137600 ;
    PORT
      LAYER met2 ;
        RECT 455.490 0.000 455.770 0.280 ;
    END
  END s5_axi_araddr_17
  PIN s5_axi_araddr_18
    DIRECTION OUTPUT ;
    USE SIGNAL ;
    ANTENNAGATEAREA 0.434700 ;
    ANTENNADIFFAREA 1.137600 ;
    PORT
      LAYER met2 ;
        RECT 384.650 0.000 384.930 0.280 ;
    END
  END s5_axi_araddr_18
  PIN s5_axi_araddr_19
    DIRECTION OUTPUT ;
    USE SIGNAL ;
    ANTENNAGATEAREA 0.434700 ;
    ANTENNADIFFAREA 1.137600 ;
    PORT
      LAYER met3 ;
        RECT 0.000 35.400 0.600 36.000 ;
    END
  END s5_axi_araddr_19
  PIN s5_axi_araddr_2
    DIRECTION OUTPUT ;
    USE SIGNAL ;
    ANTENNAGATEAREA 0.434700 ;
    ANTENNADIFFAREA 1.137600 ;
    PORT
      LAYER met3 ;
        RECT 0.000 36.760 0.600 37.360 ;
    END
  END s5_axi_araddr_2
  PIN s5_axi_araddr_20
    DIRECTION OUTPUT ;
    USE SIGNAL ;
    ANTENNAGATEAREA 0.434700 ;
    ANTENNADIFFAREA 1.137600 ;
    PORT
      LAYER met3 ;
        RECT 0.000 387.640 0.600 388.240 ;
    END
  END s5_axi_araddr_20
  PIN s5_axi_araddr_21
    DIRECTION OUTPUT ;
    USE SIGNAL ;
    ANTENNAGATEAREA 0.434700 ;
    ANTENNADIFFAREA 1.137600 ;
    PORT
      LAYER met2 ;
        RECT 185.010 519.840 185.290 520.120 ;
    END
  END s5_axi_araddr_21
  PIN s5_axi_araddr_22
    DIRECTION OUTPUT ;
    USE SIGNAL ;
    ANTENNAGATEAREA 0.434700 ;
    ANTENNADIFFAREA 1.137600 ;
    PORT
      LAYER met2 ;
        RECT 331.290 519.840 331.570 520.120 ;
    END
  END s5_axi_araddr_22
  PIN s5_axi_araddr_23
    DIRECTION OUTPUT ;
    USE SIGNAL ;
    ANTENNAGATEAREA 0.434700 ;
    ANTENNADIFFAREA 1.137600 ;
    PORT
      LAYER met3 ;
        RECT 0.000 96.600 0.600 97.200 ;
    END
  END s5_axi_araddr_23
  PIN s5_axi_araddr_24
    DIRECTION OUTPUT ;
    USE SIGNAL ;
    ANTENNAGATEAREA 0.434700 ;
    ANTENNADIFFAREA 1.137600 ;
    PORT
      LAYER met2 ;
        RECT 145.450 519.840 145.730 520.120 ;
    END
  END s5_axi_araddr_24
  PIN s5_axi_araddr_25
    DIRECTION OUTPUT ;
    USE SIGNAL ;
    ANTENNAGATEAREA 0.434700 ;
    ANTENNADIFFAREA 1.137600 ;
    PORT
      LAYER met2 ;
        RECT 48.850 519.840 49.130 520.120 ;
    END
  END s5_axi_araddr_25
  PIN s5_axi_araddr_26
    DIRECTION OUTPUT ;
    USE SIGNAL ;
    ANTENNAGATEAREA 0.434700 ;
    ANTENNADIFFAREA 1.137600 ;
    PORT
      LAYER met3 ;
        RECT 0.000 80.280 0.600 80.880 ;
    END
  END s5_axi_araddr_26
  PIN s5_axi_araddr_27
    DIRECTION OUTPUT ;
    USE SIGNAL ;
    ANTENNAGATEAREA 0.434700 ;
    ANTENNADIFFAREA 1.137600 ;
    PORT
      LAYER met2 ;
        RECT 398.450 519.840 398.730 520.120 ;
    END
  END s5_axi_araddr_27
  PIN s5_axi_araddr_28
    DIRECTION OUTPUT ;
    USE SIGNAL ;
    ANTENNAGATEAREA 0.434700 ;
    ANTENNADIFFAREA 1.137600 ;
    PORT
      LAYER met3 ;
        RECT 0.000 39.480 0.600 40.080 ;
    END
  END s5_axi_araddr_28
  PIN s5_axi_araddr_29
    DIRECTION OUTPUT ;
    USE SIGNAL ;
    ANTENNAGATEAREA 0.434700 ;
    ANTENNADIFFAREA 1.137600 ;
    PORT
      LAYER met2 ;
        RECT 91.170 519.840 91.450 520.120 ;
    END
  END s5_axi_araddr_29
  PIN s5_axi_araddr_3
    DIRECTION OUTPUT ;
    USE SIGNAL ;
    ANTENNAGATEAREA 0.434700 ;
    ANTENNADIFFAREA 1.137600 ;
    PORT
      LAYER met3 ;
        RECT 0.000 21.800 0.600 22.400 ;
    END
  END s5_axi_araddr_3
  PIN s5_axi_araddr_30
    DIRECTION OUTPUT ;
    USE SIGNAL ;
    ANTENNAGATEAREA 0.434700 ;
    ANTENNADIFFAREA 1.137600 ;
    PORT
      LAYER met2 ;
        RECT 70.010 519.840 70.290 520.120 ;
    END
  END s5_axi_araddr_30
  PIN s5_axi_araddr_31
    DIRECTION OUTPUT ;
    USE SIGNAL ;
    ANTENNAGATEAREA 0.434700 ;
    ANTENNADIFFAREA 1.137600 ;
    PORT
      LAYER met2 ;
        RECT 161.090 519.840 161.370 520.120 ;
    END
  END s5_axi_araddr_31
  PIN s5_axi_araddr_4
    DIRECTION OUTPUT ;
    USE SIGNAL ;
    ANTENNAGATEAREA 0.434700 ;
    ANTENNADIFFAREA 1.137600 ;
    PORT
      LAYER met2 ;
        RECT 313.810 519.840 314.090 520.120 ;
    END
  END s5_axi_araddr_4
  PIN s5_axi_araddr_5
    DIRECTION OUTPUT ;
    USE SIGNAL ;
    ANTENNAGATEAREA 0.434700 ;
    ANTENNADIFFAREA 1.137600 ;
    PORT
      LAYER met2 ;
        RECT 382.810 519.840 383.090 520.120 ;
    END
  END s5_axi_araddr_5
  PIN s5_axi_araddr_6
    DIRECTION OUTPUT ;
    USE SIGNAL ;
    ANTENNAGATEAREA 0.434700 ;
    ANTENNADIFFAREA 1.137600 ;
    PORT
      LAYER met2 ;
        RECT 493.210 0.000 493.490 0.280 ;
    END
  END s5_axi_araddr_6
  PIN s5_axi_araddr_7
    DIRECTION OUTPUT ;
    USE SIGNAL ;
    ANTENNAGATEAREA 0.434700 ;
    ANTENNADIFFAREA 1.137600 ;
    PORT
      LAYER met3 ;
        RECT 0.000 31.320 0.600 31.920 ;
    END
  END s5_axi_araddr_7
  PIN s5_axi_araddr_8
    DIRECTION OUTPUT ;
    USE SIGNAL ;
    ANTENNAGATEAREA 0.434700 ;
    ANTENNADIFFAREA 1.137600 ;
    PORT
      LAYER met2 ;
        RECT 456.410 0.000 456.690 0.280 ;
    END
  END s5_axi_araddr_8
  PIN s5_axi_araddr_9
    DIRECTION OUTPUT ;
    USE SIGNAL ;
    ANTENNAGATEAREA 0.434700 ;
    ANTENNADIFFAREA 1.137600 ;
    PORT
      LAYER met2 ;
        RECT 454.570 519.840 454.850 520.120 ;
    END
  END s5_axi_araddr_9
  PIN s5_axi_arready
    DIRECTION INPUT ;
    USE SIGNAL ;
    ANTENNAGATEAREA 0.647700 ;
    ANTENNADIFFAREA 0.434700 ;
    PORT
      LAYER met2 ;
        RECT 305.530 519.840 305.810 520.120 ;
    END
  END s5_axi_arready
  PIN s5_axi_arvalid
    DIRECTION OUTPUT ;
    USE SIGNAL ;
    ANTENNAGATEAREA 0.434700 ;
    ANTENNADIFFAREA 0.775300 ;
    PORT
      LAYER met3 ;
        RECT 508.800 461.080 509.400 461.680 ;
    END
  END s5_axi_arvalid
  PIN s5_axi_awaddr_0
    DIRECTION OUTPUT ;
    USE SIGNAL ;
    ANTENNAGATEAREA 0.434700 ;
    ANTENNADIFFAREA 1.137600 ;
    PORT
      LAYER met2 ;
        RECT 485.850 0.000 486.130 0.280 ;
    END
  END s5_axi_awaddr_0
  PIN s5_axi_awaddr_1
    DIRECTION OUTPUT ;
    USE SIGNAL ;
    ANTENNAGATEAREA 0.434700 ;
    ANTENNADIFFAREA 1.137600 ;
    PORT
      LAYER met2 ;
        RECT 394.770 0.000 395.050 0.280 ;
    END
  END s5_axi_awaddr_1
  PIN s5_axi_awaddr_10
    DIRECTION OUTPUT ;
    USE SIGNAL ;
    ANTENNAGATEAREA 0.434700 ;
    ANTENNADIFFAREA 1.137600 ;
    PORT
      LAYER met2 ;
        RECT 457.330 0.000 457.610 0.280 ;
    END
  END s5_axi_awaddr_10
  PIN s5_axi_awaddr_11
    DIRECTION OUTPUT ;
    USE SIGNAL ;
    ANTENNAGATEAREA 0.434700 ;
    ANTENNADIFFAREA 1.137600 ;
    PORT
      LAYER met2 ;
        RECT 420.530 0.000 420.810 0.280 ;
    END
  END s5_axi_awaddr_11
  PIN s5_axi_awaddr_12
    DIRECTION OUTPUT ;
    USE SIGNAL ;
    ANTENNAGATEAREA 0.434700 ;
    ANTENNADIFFAREA 1.137600 ;
    PORT
      LAYER met2 ;
        RECT 294.490 519.840 294.770 520.120 ;
    END
  END s5_axi_awaddr_12
  PIN s5_axi_awaddr_13
    DIRECTION OUTPUT ;
    USE SIGNAL ;
    ANTENNAGATEAREA 0.434700 ;
    ANTENNADIFFAREA 1.137600 ;
    PORT
      LAYER met3 ;
        RECT 508.800 123.800 509.400 124.400 ;
    END
  END s5_axi_awaddr_13
  PIN s5_axi_awaddr_14
    DIRECTION OUTPUT ;
    USE SIGNAL ;
    ANTENNAGATEAREA 0.434700 ;
    ANTENNADIFFAREA 1.137600 ;
    PORT
      LAYER met2 ;
        RECT 403.050 0.000 403.330 0.280 ;
    END
  END s5_axi_awaddr_14
  PIN s5_axi_awaddr_15
    DIRECTION OUTPUT ;
    USE SIGNAL ;
    ANTENNAGATEAREA 0.434700 ;
    ANTENNADIFFAREA 1.137600 ;
    PORT
      LAYER met2 ;
        RECT 127.970 519.840 128.250 520.120 ;
    END
  END s5_axi_awaddr_15
  PIN s5_axi_awaddr_16
    DIRECTION OUTPUT ;
    USE SIGNAL ;
    ANTENNAGATEAREA 0.434700 ;
    ANTENNADIFFAREA 1.137600 ;
    PORT
      LAYER met2 ;
        RECT 429.730 0.000 430.010 0.280 ;
    END
  END s5_axi_awaddr_16
  PIN s5_axi_awaddr_17
    DIRECTION OUTPUT ;
    USE SIGNAL ;
    ANTENNAGATEAREA 0.434700 ;
    ANTENNADIFFAREA 1.137600 ;
    PORT
      LAYER met2 ;
        RECT 357.050 519.840 357.330 520.120 ;
    END
  END s5_axi_awaddr_17
  PIN s5_axi_awaddr_18
    DIRECTION OUTPUT ;
    USE SIGNAL ;
    ANTENNAGATEAREA 0.434700 ;
    ANTENNADIFFAREA 1.137600 ;
    PORT
      LAYER met2 ;
        RECT 337.730 519.840 338.010 520.120 ;
    END
  END s5_axi_awaddr_18
  PIN s5_axi_awaddr_19
    DIRECTION OUTPUT ;
    USE SIGNAL ;
    ANTENNAGATEAREA 0.434700 ;
    ANTENNADIFFAREA 1.137600 ;
    PORT
      LAYER met3 ;
        RECT 508.800 444.760 509.400 445.360 ;
    END
  END s5_axi_awaddr_19
  PIN s5_axi_awaddr_2
    DIRECTION OUTPUT ;
    USE SIGNAL ;
    ANTENNAGATEAREA 0.434700 ;
    ANTENNADIFFAREA 1.137600 ;
    PORT
      LAYER met3 ;
        RECT 0.000 117.000 0.600 117.600 ;
    END
  END s5_axi_awaddr_2
  PIN s5_axi_awaddr_20
    DIRECTION OUTPUT ;
    USE SIGNAL ;
    ANTENNAGATEAREA 0.434700 ;
    ANTENNADIFFAREA 1.137600 ;
    PORT
      LAYER met3 ;
        RECT 0.000 110.200 0.600 110.800 ;
    END
  END s5_axi_awaddr_20
  PIN s5_axi_awaddr_21
    DIRECTION OUTPUT ;
    USE SIGNAL ;
    ANTENNAGATEAREA 0.434700 ;
    ANTENNADIFFAREA 1.137600 ;
    PORT
      LAYER met3 ;
        RECT 0.000 412.120 0.600 412.720 ;
    END
  END s5_axi_awaddr_21
  PIN s5_axi_awaddr_22
    DIRECTION OUTPUT ;
    USE SIGNAL ;
    ANTENNAGATEAREA 0.434700 ;
    ANTENNADIFFAREA 1.137600 ;
    PORT
      LAYER met2 ;
        RECT 458.250 0.000 458.530 0.280 ;
    END
  END s5_axi_awaddr_22
  PIN s5_axi_awaddr_23
    DIRECTION OUTPUT ;
    USE SIGNAL ;
    ANTENNAGATEAREA 0.434700 ;
    ANTENNADIFFAREA 1.137600 ;
    PORT
      LAYER met2 ;
        RECT 350.610 519.840 350.890 520.120 ;
    END
  END s5_axi_awaddr_23
  PIN s5_axi_awaddr_24
    DIRECTION OUTPUT ;
    USE SIGNAL ;
    ANTENNAGATEAREA 0.434700 ;
    ANTENNADIFFAREA 1.137600 ;
    PORT
      LAYER met2 ;
        RECT 177.650 519.840 177.930 520.120 ;
    END
  END s5_axi_awaddr_24
  PIN s5_axi_awaddr_25
    DIRECTION OUTPUT ;
    USE SIGNAL ;
    ANTENNAGATEAREA 0.434700 ;
    ANTENNADIFFAREA 1.137600 ;
    PORT
      LAYER met3 ;
        RECT 0.000 160.520 0.600 161.120 ;
    END
  END s5_axi_awaddr_25
  PIN s5_axi_awaddr_26
    DIRECTION OUTPUT ;
    USE SIGNAL ;
    ANTENNAGATEAREA 0.434700 ;
    ANTENNADIFFAREA 1.137600 ;
    PORT
      LAYER met2 ;
        RECT 200.650 519.840 200.930 520.120 ;
    END
  END s5_axi_awaddr_26
  PIN s5_axi_awaddr_27
    DIRECTION OUTPUT ;
    USE SIGNAL ;
    ANTENNAGATEAREA 0.434700 ;
    ANTENNADIFFAREA 1.137600 ;
    PORT
      LAYER met2 ;
        RECT 401.210 0.000 401.490 0.280 ;
    END
  END s5_axi_awaddr_27
  PIN s5_axi_awaddr_28
    DIRECTION OUTPUT ;
    USE SIGNAL ;
    ANTENNAGATEAREA 0.434700 ;
    ANTENNADIFFAREA 1.137600 ;
    PORT
      LAYER met2 ;
        RECT 486.770 0.000 487.050 0.280 ;
    END
  END s5_axi_awaddr_28
  PIN s5_axi_awaddr_29
    DIRECTION OUTPUT ;
    USE SIGNAL ;
    ANTENNAGATEAREA 0.434700 ;
    ANTENNADIFFAREA 1.137600 ;
    PORT
      LAYER met2 ;
        RECT 387.410 519.840 387.690 520.120 ;
    END
  END s5_axi_awaddr_29
  PIN s5_axi_awaddr_3
    DIRECTION OUTPUT ;
    USE SIGNAL ;
    ANTENNAGATEAREA 0.434700 ;
    ANTENNADIFFAREA 1.137600 ;
    PORT
      LAYER met3 ;
        RECT 0.000 69.400 0.600 70.000 ;
    END
  END s5_axi_awaddr_3
  PIN s5_axi_awaddr_30
    DIRECTION OUTPUT ;
    USE SIGNAL ;
    ANTENNAGATEAREA 0.434700 ;
    ANTENNADIFFAREA 1.137600 ;
    PORT
      LAYER met2 ;
        RECT 466.530 0.000 466.810 0.280 ;
    END
  END s5_axi_awaddr_30
  PIN s5_axi_awaddr_31
    DIRECTION OUTPUT ;
    USE SIGNAL ;
    ANTENNAGATEAREA 0.434700 ;
    ANTENNADIFFAREA 1.137600 ;
    PORT
      LAYER met2 ;
        RECT 266.890 519.840 267.170 520.120 ;
    END
  END s5_axi_awaddr_31
  PIN s5_axi_awaddr_4
    DIRECTION OUTPUT ;
    USE SIGNAL ;
    ANTENNAGATEAREA 0.434700 ;
    ANTENNADIFFAREA 1.137600 ;
    PORT
      LAYER met2 ;
        RECT 339.570 519.840 339.850 520.120 ;
    END
  END s5_axi_awaddr_4
  PIN s5_axi_awaddr_5
    DIRECTION OUTPUT ;
    USE SIGNAL ;
    ANTENNAGATEAREA 0.434700 ;
    ANTENNADIFFAREA 1.137600 ;
    PORT
      LAYER met2 ;
        RECT 373.610 0.000 373.890 0.280 ;
    END
  END s5_axi_awaddr_5
  PIN s5_axi_awaddr_6
    DIRECTION OUTPUT ;
    USE SIGNAL ;
    ANTENNAGATEAREA 0.434700 ;
    ANTENNADIFFAREA 1.137600 ;
    PORT
      LAYER met2 ;
        RECT 459.170 0.000 459.450 0.280 ;
    END
  END s5_axi_awaddr_6
  PIN s5_axi_awaddr_7
    DIRECTION OUTPUT ;
    USE SIGNAL ;
    ANTENNAGATEAREA 0.434700 ;
    ANTENNADIFFAREA 1.137600 ;
    PORT
      LAYER met3 ;
        RECT 0.000 44.920 0.600 45.520 ;
    END
  END s5_axi_awaddr_7
  PIN s5_axi_awaddr_8
    DIRECTION OUTPUT ;
    USE SIGNAL ;
    ANTENNAGATEAREA 0.434700 ;
    ANTENNADIFFAREA 1.137600 ;
    PORT
      LAYER met2 ;
        RECT 381.890 0.000 382.170 0.280 ;
    END
  END s5_axi_awaddr_8
  PIN s5_axi_awaddr_9
    DIRECTION OUTPUT ;
    USE SIGNAL ;
    ANTENNAGATEAREA 0.434700 ;
    ANTENNADIFFAREA 1.137600 ;
    PORT
      LAYER met3 ;
        RECT 508.800 424.360 509.400 424.960 ;
    END
  END s5_axi_awaddr_9
  PIN s5_axi_awready
    DIRECTION INPUT ;
    USE SIGNAL ;
    ANTENNAGATEAREA 0.647700 ;
    ANTENNADIFFAREA 0.434700 ;
    PORT
      LAYER met3 ;
        RECT 0.000 364.520 0.600 365.120 ;
    END
  END s5_axi_awready
  PIN s5_axi_awvalid
    DIRECTION OUTPUT ;
    USE SIGNAL ;
    ANTENNAGATEAREA 0.434700 ;
    ANTENNADIFFAREA 0.775300 ;
    PORT
      LAYER met3 ;
        RECT 508.800 401.240 509.400 401.840 ;
    END
  END s5_axi_awvalid
  PIN s5_axi_bready
    DIRECTION OUTPUT ;
    USE SIGNAL ;
    ANTENNAGATEAREA 0.434700 ;
    ANTENNADIFFAREA 0.775300 ;
    PORT
      LAYER met3 ;
        RECT 508.800 402.600 509.400 403.200 ;
    END
  END s5_axi_bready
  PIN s5_axi_bresp_0
    DIRECTION INPUT ;
    USE SIGNAL ;
    ANTENNAGATEAREA 0.647700 ;
    ANTENNADIFFAREA 0.434700 ;
    PORT
      LAYER met3 ;
        RECT 0.000 311.480 0.600 312.080 ;
    END
  END s5_axi_bresp_0
  PIN s5_axi_bresp_1
    DIRECTION INPUT ;
    USE SIGNAL ;
    ANTENNAGATEAREA 0.647700 ;
    ANTENNADIFFAREA 0.434700 ;
    PORT
      LAYER met3 ;
        RECT 0.000 306.040 0.600 306.640 ;
    END
  END s5_axi_bresp_1
  PIN s5_axi_bvalid
    DIRECTION INPUT ;
    USE SIGNAL ;
    ANTENNAGATEAREA 0.647700 ;
    ANTENNADIFFAREA 0.434700 ;
    PORT
      LAYER met3 ;
        RECT 0.000 363.160 0.600 363.760 ;
    END
  END s5_axi_bvalid
  PIN s5_axi_rdata_0
    DIRECTION INPUT ;
    USE SIGNAL ;
    ANTENNAGATEAREA 0.647700 ;
    ANTENNADIFFAREA 0.434700 ;
    PORT
      LAYER met3 ;
        RECT 508.800 186.360 509.400 186.960 ;
    END
  END s5_axi_rdata_0
  PIN s5_axi_rdata_1
    DIRECTION INPUT ;
    USE SIGNAL ;
    ANTENNAGATEAREA 0.647700 ;
    ANTENNADIFFAREA 0.434700 ;
    PORT
      LAYER met2 ;
        RECT 303.690 519.840 303.970 520.120 ;
    END
  END s5_axi_rdata_1
  PIN s5_axi_rdata_10
    DIRECTION INPUT ;
    USE SIGNAL ;
    ANTENNAGATEAREA 0.647700 ;
    ANTENNADIFFAREA 0.434700 ;
    PORT
      LAYER met3 ;
        RECT 508.800 282.920 509.400 283.520 ;
    END
  END s5_axi_rdata_10
  PIN s5_axi_rdata_11
    DIRECTION INPUT ;
    USE SIGNAL ;
    ANTENNAGATEAREA 0.647700 ;
    ANTENNADIFFAREA 0.434700 ;
    PORT
      LAYER met3 ;
        RECT 508.800 114.280 509.400 114.880 ;
    END
  END s5_axi_rdata_11
  PIN s5_axi_rdata_12
    DIRECTION INPUT ;
    USE SIGNAL ;
    ANTENNAGATEAREA 0.647700 ;
    ANTENNADIFFAREA 0.434700 ;
    PORT
      LAYER met3 ;
        RECT 508.800 102.040 509.400 102.640 ;
    END
  END s5_axi_rdata_12
  PIN s5_axi_rdata_13
    DIRECTION INPUT ;
    USE SIGNAL ;
    ANTENNAGATEAREA 0.647700 ;
    ANTENNADIFFAREA 0.434700 ;
    PORT
      LAYER met3 ;
        RECT 508.800 77.560 509.400 78.160 ;
    END
  END s5_axi_rdata_13
  PIN s5_axi_rdata_14
    DIRECTION INPUT ;
    USE SIGNAL ;
    ANTENNAGATEAREA 0.647700 ;
    ANTENNADIFFAREA 0.434700 ;
    PORT
      LAYER met3 ;
        RECT 508.800 500.520 509.400 501.120 ;
    END
  END s5_axi_rdata_14
  PIN s5_axi_rdata_15
    DIRECTION INPUT ;
    USE SIGNAL ;
    ANTENNAGATEAREA 0.647700 ;
    ANTENNADIFFAREA 0.434700 ;
    PORT
      LAYER met3 ;
        RECT 508.800 205.400 509.400 206.000 ;
    END
  END s5_axi_rdata_15
  PIN s5_axi_rdata_16
    DIRECTION INPUT ;
    USE SIGNAL ;
    ANTENNAGATEAREA 0.647700 ;
    ANTENNADIFFAREA 0.434700 ;
    PORT
      LAYER met3 ;
        RECT 508.800 161.880 509.400 162.480 ;
    END
  END s5_axi_rdata_16
  PIN s5_axi_rdata_17
    DIRECTION INPUT ;
    USE SIGNAL ;
    ANTENNAGATEAREA 0.647700 ;
    ANTENNADIFFAREA 0.434700 ;
    PORT
      LAYER met3 ;
        RECT 508.800 297.880 509.400 298.480 ;
    END
  END s5_axi_rdata_17
  PIN s5_axi_rdata_18
    DIRECTION INPUT ;
    USE SIGNAL ;
    ANTENNAGATEAREA 0.647700 ;
    ANTENNADIFFAREA 0.434700 ;
    PORT
      LAYER met3 ;
        RECT 508.800 83.000 509.400 83.600 ;
    END
  END s5_axi_rdata_18
  PIN s5_axi_rdata_19
    DIRECTION INPUT ;
    USE SIGNAL ;
    ANTENNAGATEAREA 0.647700 ;
    ANTENNADIFFAREA 0.434700 ;
    PORT
      LAYER met3 ;
        RECT 508.800 287.000 509.400 287.600 ;
    END
  END s5_axi_rdata_19
  PIN s5_axi_rdata_2
    DIRECTION INPUT ;
    USE SIGNAL ;
    ANTENNAGATEAREA 0.647700 ;
    ANTENNADIFFAREA 0.434700 ;
    PORT
      LAYER met3 ;
        RECT 508.800 69.400 509.400 70.000 ;
    END
  END s5_axi_rdata_2
  PIN s5_axi_rdata_20
    DIRECTION INPUT ;
    USE SIGNAL ;
    ANTENNAGATEAREA 0.647700 ;
    ANTENNADIFFAREA 0.434700 ;
    PORT
      LAYER met3 ;
        RECT 508.800 244.840 509.400 245.440 ;
    END
  END s5_axi_rdata_20
  PIN s5_axi_rdata_21
    DIRECTION INPUT ;
    USE SIGNAL ;
    ANTENNAGATEAREA 0.647700 ;
    ANTENNADIFFAREA 0.434700 ;
    PORT
      LAYER met3 ;
        RECT 508.800 359.080 509.400 359.680 ;
    END
  END s5_axi_rdata_21
  PIN s5_axi_rdata_22
    DIRECTION INPUT ;
    USE SIGNAL ;
    ANTENNAGATEAREA 0.647700 ;
    ANTENNADIFFAREA 0.434700 ;
    PORT
      LAYER met3 ;
        RECT 508.800 255.720 509.400 256.320 ;
    END
  END s5_axi_rdata_22
  PIN s5_axi_rdata_23
    DIRECTION INPUT ;
    USE SIGNAL ;
    ANTENNAGATEAREA 0.647700 ;
    ANTENNADIFFAREA 0.434700 ;
    PORT
      LAYER met3 ;
        RECT 508.800 206.760 509.400 207.360 ;
    END
  END s5_axi_rdata_23
  PIN s5_axi_rdata_24
    DIRECTION INPUT ;
    USE SIGNAL ;
    ANTENNAGATEAREA 0.647700 ;
    ANTENNADIFFAREA 0.434700 ;
    PORT
      LAYER met3 ;
        RECT 508.800 289.720 509.400 290.320 ;
    END
  END s5_axi_rdata_24
  PIN s5_axi_rdata_25
    DIRECTION INPUT ;
    USE SIGNAL ;
    ANTENNAGATEAREA 0.647700 ;
    ANTENNADIFFAREA 0.434700 ;
    PORT
      LAYER met3 ;
        RECT 508.800 382.200 509.400 382.800 ;
    END
  END s5_axi_rdata_25
  PIN s5_axi_rdata_26
    DIRECTION INPUT ;
    USE SIGNAL ;
    ANTENNAGATEAREA 0.647700 ;
    ANTENNADIFFAREA 0.434700 ;
    PORT
      LAYER met3 ;
        RECT 508.800 179.560 509.400 180.160 ;
    END
  END s5_axi_rdata_26
  PIN s5_axi_rdata_27
    DIRECTION INPUT ;
    USE SIGNAL ;
    ANTENNAGATEAREA 0.647700 ;
    ANTENNADIFFAREA 0.434700 ;
    PORT
      LAYER met3 ;
        RECT 508.800 229.880 509.400 230.480 ;
    END
  END s5_axi_rdata_27
  PIN s5_axi_rdata_28
    DIRECTION INPUT ;
    USE SIGNAL ;
    ANTENNAGATEAREA 0.647700 ;
    ANTENNADIFFAREA 0.434700 ;
    PORT
      LAYER met3 ;
        RECT 508.800 100.680 509.400 101.280 ;
    END
  END s5_axi_rdata_28
  PIN s5_axi_rdata_29
    DIRECTION INPUT ;
    USE SIGNAL ;
    ANTENNAGATEAREA 0.647700 ;
    ANTENNADIFFAREA 0.434700 ;
    PORT
      LAYER met3 ;
        RECT 508.800 276.120 509.400 276.720 ;
    END
  END s5_axi_rdata_29
  PIN s5_axi_rdata_3
    DIRECTION INPUT ;
    USE SIGNAL ;
    ANTENNAGATEAREA 0.647700 ;
    ANTENNADIFFAREA 0.434700 ;
    PORT
      LAYER met3 ;
        RECT 508.800 369.960 509.400 370.560 ;
    END
  END s5_axi_rdata_3
  PIN s5_axi_rdata_30
    DIRECTION INPUT ;
    USE SIGNAL ;
    ANTENNAGATEAREA 0.647700 ;
    ANTENNADIFFAREA 0.434700 ;
    PORT
      LAYER met3 ;
        RECT 508.800 115.640 509.400 116.240 ;
    END
  END s5_axi_rdata_30
  PIN s5_axi_rdata_31
    DIRECTION INPUT ;
    USE SIGNAL ;
    ANTENNAGATEAREA 0.647700 ;
    ANTENNADIFFAREA 0.434700 ;
    PORT
      LAYER met3 ;
        RECT 508.800 338.680 509.400 339.280 ;
    END
  END s5_axi_rdata_31
  PIN s5_axi_rdata_4
    DIRECTION INPUT ;
    USE SIGNAL ;
    ANTENNAGATEAREA 0.647700 ;
    ANTENNADIFFAREA 0.434700 ;
    PORT
      LAYER met2 ;
        RECT 304.610 519.840 304.890 520.120 ;
    END
  END s5_axi_rdata_4
  PIN s5_axi_rdata_5
    DIRECTION INPUT ;
    USE SIGNAL ;
    ANTENNAGATEAREA 0.647700 ;
    ANTENNADIFFAREA 0.434700 ;
    PORT
      LAYER met3 ;
        RECT 508.800 246.200 509.400 246.800 ;
    END
  END s5_axi_rdata_5
  PIN s5_axi_rdata_6
    DIRECTION INPUT ;
    USE SIGNAL ;
    ANTENNAGATEAREA 0.647700 ;
    ANTENNADIFFAREA 0.434700 ;
    PORT
      LAYER met3 ;
        RECT 508.800 428.440 509.400 429.040 ;
    END
  END s5_axi_rdata_6
  PIN s5_axi_rdata_7
    DIRECTION INPUT ;
    USE SIGNAL ;
    ANTENNAGATEAREA 0.647700 ;
    ANTENNADIFFAREA 0.434700 ;
    PORT
      LAYER met3 ;
        RECT 508.800 395.800 509.400 396.400 ;
    END
  END s5_axi_rdata_7
  PIN s5_axi_rdata_8
    DIRECTION INPUT ;
    USE SIGNAL ;
    ANTENNAGATEAREA 0.647700 ;
    ANTENNADIFFAREA 0.434700 ;
    PORT
      LAYER met3 ;
        RECT 508.800 300.600 509.400 301.200 ;
    END
  END s5_axi_rdata_8
  PIN s5_axi_rdata_9
    DIRECTION INPUT ;
    USE SIGNAL ;
    ANTENNAGATEAREA 0.647700 ;
    ANTENNADIFFAREA 0.434700 ;
    PORT
      LAYER met3 ;
        RECT 508.800 254.360 509.400 254.960 ;
    END
  END s5_axi_rdata_9
  PIN s5_axi_rready
    DIRECTION OUTPUT ;
    USE SIGNAL ;
    ANTENNAGATEAREA 0.434700 ;
    ANTENNADIFFAREA 0.775300 ;
    PORT
      LAYER met3 ;
        RECT 508.800 408.040 509.400 408.640 ;
    END
  END s5_axi_rready
  PIN s5_axi_rresp_0
    DIRECTION INPUT ;
    USE SIGNAL ;
    ANTENNAGATEAREA 0.647700 ;
    ANTENNADIFFAREA 0.434700 ;
    PORT
      LAYER met3 ;
        RECT 508.800 310.120 509.400 310.720 ;
    END
  END s5_axi_rresp_0
  PIN s5_axi_rresp_1
    DIRECTION INPUT ;
    USE SIGNAL ;
    ANTENNAGATEAREA 0.647700 ;
    ANTENNADIFFAREA 0.434700 ;
    PORT
      LAYER met3 ;
        RECT 508.800 164.600 509.400 165.200 ;
    END
  END s5_axi_rresp_1
  PIN s5_axi_rvalid
    DIRECTION INPUT ;
    USE SIGNAL ;
    ANTENNAGATEAREA 0.647700 ;
    ANTENNADIFFAREA 0.434700 ;
    PORT
      LAYER met3 ;
        RECT 508.800 330.520 509.400 331.120 ;
    END
  END s5_axi_rvalid
  PIN s5_axi_wdata_0
    DIRECTION OUTPUT ;
    USE SIGNAL ;
    ANTENNAGATEAREA 0.434700 ;
    ANTENNADIFFAREA 1.137600 ;
    PORT
      LAYER met3 ;
        RECT 0.000 104.760 0.600 105.360 ;
    END
  END s5_axi_wdata_0
  PIN s5_axi_wdata_1
    DIRECTION OUTPUT ;
    USE SIGNAL ;
    ANTENNAGATEAREA 0.434700 ;
    ANTENNADIFFAREA 1.137600 ;
    PORT
      LAYER met2 ;
        RECT 400.290 0.000 400.570 0.280 ;
    END
  END s5_axi_wdata_1
  PIN s5_axi_wdata_10
    DIRECTION OUTPUT ;
    USE SIGNAL ;
    ANTENNAGATEAREA 0.434700 ;
    ANTENNADIFFAREA 1.137600 ;
    PORT
      LAYER met2 ;
        RECT 189.610 519.840 189.890 520.120 ;
    END
  END s5_axi_wdata_10
  PIN s5_axi_wdata_11
    DIRECTION OUTPUT ;
    USE SIGNAL ;
    ANTENNAGATEAREA 0.434700 ;
    ANTENNADIFFAREA 1.137600 ;
    PORT
      LAYER met2 ;
        RECT 134.410 519.840 134.690 520.120 ;
    END
  END s5_axi_wdata_11
  PIN s5_axi_wdata_12
    DIRECTION OUTPUT ;
    USE SIGNAL ;
    ANTENNAGATEAREA 0.434700 ;
    ANTENNADIFFAREA 1.137600 ;
    PORT
      LAYER met3 ;
        RECT 0.000 88.440 0.600 89.040 ;
    END
  END s5_axi_wdata_12
  PIN s5_axi_wdata_13
    DIRECTION OUTPUT ;
    USE SIGNAL ;
    ANTENNAGATEAREA 0.434700 ;
    ANTENNADIFFAREA 1.137600 ;
    PORT
      LAYER met2 ;
        RECT 234.690 519.840 234.970 520.120 ;
    END
  END s5_axi_wdata_13
  PIN s5_axi_wdata_14
    DIRECTION OUTPUT ;
    USE SIGNAL ;
    ANTENNAGATEAREA 0.434700 ;
    ANTENNADIFFAREA 1.137600 ;
    PORT
      LAYER met2 ;
        RECT 365.330 519.840 365.610 520.120 ;
    END
  END s5_axi_wdata_14
  PIN s5_axi_wdata_15
    DIRECTION OUTPUT ;
    USE SIGNAL ;
    ANTENNAGATEAREA 0.434700 ;
    ANTENNADIFFAREA 1.137600 ;
    PORT
      LAYER met2 ;
        RECT 107.730 519.840 108.010 520.120 ;
    END
  END s5_axi_wdata_15
  PIN s5_axi_wdata_16
    DIRECTION OUTPUT ;
    USE SIGNAL ;
    ANTENNAGATEAREA 0.434700 ;
    ANTENNADIFFAREA 1.137600 ;
    PORT
      LAYER met3 ;
        RECT 0.000 405.320 0.600 405.920 ;
    END
  END s5_axi_wdata_16
  PIN s5_axi_wdata_17
    DIRECTION OUTPUT ;
    USE SIGNAL ;
    ANTENNAGATEAREA 0.434700 ;
    ANTENNADIFFAREA 1.137600 ;
    PORT
      LAYER met2 ;
        RECT 159.250 519.840 159.530 520.120 ;
    END
  END s5_axi_wdata_17
  PIN s5_axi_wdata_18
    DIRECTION OUTPUT ;
    USE SIGNAL ;
    ANTENNAGATEAREA 0.434700 ;
    ANTENNADIFFAREA 1.137600 ;
    PORT
      LAYER met2 ;
        RECT 460.090 0.000 460.370 0.280 ;
    END
  END s5_axi_wdata_18
  PIN s5_axi_wdata_19
    DIRECTION OUTPUT ;
    USE SIGNAL ;
    ANTENNAGATEAREA 0.434700 ;
    ANTENNADIFFAREA 1.137600 ;
    PORT
      LAYER met2 ;
        RECT 239.290 519.840 239.570 520.120 ;
    END
  END s5_axi_wdata_19
  PIN s5_axi_wdata_2
    DIRECTION OUTPUT ;
    USE SIGNAL ;
    ANTENNAGATEAREA 0.434700 ;
    ANTENNADIFFAREA 1.137600 ;
    PORT
      LAYER met2 ;
        RECT 197.890 519.840 198.170 520.120 ;
    END
  END s5_axi_wdata_2
  PIN s5_axi_wdata_20
    DIRECTION OUTPUT ;
    USE SIGNAL ;
    ANTENNAGATEAREA 0.434700 ;
    ANTENNADIFFAREA 1.137600 ;
    PORT
      LAYER met3 ;
        RECT 508.800 112.920 509.400 113.520 ;
    END
  END s5_axi_wdata_20
  PIN s5_axi_wdata_21
    DIRECTION OUTPUT ;
    USE SIGNAL ;
    ANTENNAGATEAREA 0.434700 ;
    ANTENNADIFFAREA 1.137600 ;
    PORT
      LAYER met2 ;
        RECT 81.050 519.840 81.330 520.120 ;
    END
  END s5_axi_wdata_21
  PIN s5_axi_wdata_22
    DIRECTION OUTPUT ;
    USE SIGNAL ;
    ANTENNAGATEAREA 0.434700 ;
    ANTENNADIFFAREA 1.137600 ;
    PORT
      LAYER met2 ;
        RECT 426.970 519.840 427.250 520.120 ;
    END
  END s5_axi_wdata_22
  PIN s5_axi_wdata_23
    DIRECTION OUTPUT ;
    USE SIGNAL ;
    ANTENNAGATEAREA 0.434700 ;
    ANTENNADIFFAREA 1.137600 ;
    PORT
      LAYER met3 ;
        RECT 0.000 394.440 0.600 395.040 ;
    END
  END s5_axi_wdata_23
  PIN s5_axi_wdata_24
    DIRECTION OUTPUT ;
    USE SIGNAL ;
    ANTENNAGATEAREA 0.434700 ;
    ANTENNADIFFAREA 1.137600 ;
    PORT
      LAYER met3 ;
        RECT 0.000 125.160 0.600 125.760 ;
    END
  END s5_axi_wdata_24
  PIN s5_axi_wdata_25
    DIRECTION OUTPUT ;
    USE SIGNAL ;
    ANTENNAGATEAREA 0.434700 ;
    ANTENNADIFFAREA 1.137600 ;
    PORT
      LAYER met2 ;
        RECT 64.490 519.840 64.770 520.120 ;
    END
  END s5_axi_wdata_25
  PIN s5_axi_wdata_26
    DIRECTION OUTPUT ;
    USE SIGNAL ;
    ANTENNAGATEAREA 0.434700 ;
    ANTENNADIFFAREA 1.137600 ;
    PORT
      LAYER met3 ;
        RECT 0.000 27.240 0.600 27.840 ;
    END
  END s5_axi_wdata_26
  PIN s5_axi_wdata_27
    DIRECTION OUTPUT ;
    USE SIGNAL ;
    ANTENNAGATEAREA 0.434700 ;
    ANTENNADIFFAREA 1.137600 ;
    PORT
      LAYER met2 ;
        RECT 118.770 519.840 119.050 520.120 ;
    END
  END s5_axi_wdata_27
  PIN s5_axi_wdata_28
    DIRECTION OUTPUT ;
    USE SIGNAL ;
    ANTENNAGATEAREA 0.434700 ;
    ANTENNADIFFAREA 1.137600 ;
    PORT
      LAYER met2 ;
        RECT 225.490 519.840 225.770 520.120 ;
    END
  END s5_axi_wdata_28
  PIN s5_axi_wdata_29
    DIRECTION OUTPUT ;
    USE SIGNAL ;
    ANTENNAGATEAREA 0.434700 ;
    ANTENNADIFFAREA 1.137600 ;
    PORT
      LAYER met2 ;
        RECT 452.730 0.000 453.010 0.280 ;
    END
  END s5_axi_wdata_29
  PIN s5_axi_wdata_3
    DIRECTION OUTPUT ;
    USE SIGNAL ;
    ANTENNAGATEAREA 0.434700 ;
    ANTENNADIFFAREA 1.137600 ;
    PORT
      LAYER met2 ;
        RECT 122.450 519.840 122.730 520.120 ;
    END
  END s5_axi_wdata_3
  PIN s5_axi_wdata_30
    DIRECTION OUTPUT ;
    USE SIGNAL ;
    ANTENNAGATEAREA 0.434700 ;
    ANTENNADIFFAREA 1.137600 ;
    PORT
      LAYER met2 ;
        RECT 487.690 0.000 487.970 0.280 ;
    END
  END s5_axi_wdata_30
  PIN s5_axi_wdata_31
    DIRECTION OUTPUT ;
    USE SIGNAL ;
    ANTENNAGATEAREA 0.434700 ;
    ANTENNADIFFAREA 1.137600 ;
    PORT
      LAYER met2 ;
        RECT 281.610 519.840 281.890 520.120 ;
    END
  END s5_axi_wdata_31
  PIN s5_axi_wdata_4
    DIRECTION OUTPUT ;
    USE SIGNAL ;
    ANTENNAGATEAREA 0.434700 ;
    ANTENNADIFFAREA 1.137600 ;
    PORT
      LAYER met3 ;
        RECT 0.000 74.840 0.600 75.440 ;
    END
  END s5_axi_wdata_4
  PIN s5_axi_wdata_5
    DIRECTION OUTPUT ;
    USE SIGNAL ;
    ANTENNAGATEAREA 0.434700 ;
    ANTENNADIFFAREA 1.137600 ;
    PORT
      LAYER met3 ;
        RECT 0.000 368.600 0.600 369.200 ;
    END
  END s5_axi_wdata_5
  PIN s5_axi_wdata_6
    DIRECTION OUTPUT ;
    USE SIGNAL ;
    ANTENNAGATEAREA 0.434700 ;
    ANTENNADIFFAREA 1.137600 ;
    PORT
      LAYER met2 ;
        RECT 461.010 0.000 461.290 0.280 ;
    END
  END s5_axi_wdata_6
  PIN s5_axi_wdata_7
    DIRECTION OUTPUT ;
    USE SIGNAL ;
    ANTENNAGATEAREA 0.434700 ;
    ANTENNADIFFAREA 1.137600 ;
    PORT
      LAYER met2 ;
        RECT 369.930 519.840 370.210 520.120 ;
    END
  END s5_axi_wdata_7
  PIN s5_axi_wdata_8
    DIRECTION OUTPUT ;
    USE SIGNAL ;
    ANTENNAGATEAREA 0.434700 ;
    ANTENNADIFFAREA 1.137600 ;
    PORT
      LAYER met2 ;
        RECT 431.570 0.000 431.850 0.280 ;
    END
  END s5_axi_wdata_8
  PIN s5_axi_wdata_9
    DIRECTION OUTPUT ;
    USE SIGNAL ;
    ANTENNAGATEAREA 0.434700 ;
    ANTENNADIFFAREA 1.137600 ;
    PORT
      LAYER met3 ;
        RECT 508.800 431.160 509.400 431.760 ;
    END
  END s5_axi_wdata_9
  PIN s5_axi_wready
    DIRECTION INPUT ;
    USE SIGNAL ;
    ANTENNAGATEAREA 0.647700 ;
    ANTENNADIFFAREA 0.434700 ;
    PORT
      LAYER met3 ;
        RECT 0.000 361.800 0.600 362.400 ;
    END
  END s5_axi_wready
  PIN s5_axi_wstrb_0
    DIRECTION OUTPUT ;
    USE SIGNAL ;
    ANTENNAGATEAREA 0.434700 ;
    ANTENNADIFFAREA 1.137600 ;
    PORT
      LAYER met2 ;
        RECT 260.450 519.840 260.730 520.120 ;
    END
  END s5_axi_wstrb_0
  PIN s5_axi_wstrb_1
    DIRECTION OUTPUT ;
    USE SIGNAL ;
    ANTENNAGATEAREA 0.434700 ;
    ANTENNADIFFAREA 1.137600 ;
    PORT
      LAYER met3 ;
        RECT 0.000 95.240 0.600 95.840 ;
    END
  END s5_axi_wstrb_1
  PIN s5_axi_wstrb_2
    DIRECTION OUTPUT ;
    USE SIGNAL ;
    ANTENNAGATEAREA 0.434700 ;
    ANTENNADIFFAREA 1.137600 ;
    PORT
      LAYER met2 ;
        RECT 419.610 519.840 419.890 520.120 ;
    END
  END s5_axi_wstrb_2
  PIN s5_axi_wstrb_3
    DIRECTION OUTPUT ;
    USE SIGNAL ;
    ANTENNAGATEAREA 0.434700 ;
    ANTENNADIFFAREA 1.137600 ;
    PORT
      LAYER met2 ;
        RECT 59.890 519.840 60.170 520.120 ;
    END
  END s5_axi_wstrb_3
  PIN s5_axi_wvalid
    DIRECTION OUTPUT ;
    USE SIGNAL ;
    ANTENNAGATEAREA 0.434700 ;
    ANTENNADIFFAREA 0.775300 ;
    PORT
      LAYER met3 ;
        RECT 508.800 473.320 509.400 473.920 ;
    END
  END s5_axi_wvalid
  PIN s6_axi_araddr_0
    DIRECTION OUTPUT ;
    USE SIGNAL ;
    ANTENNAGATEAREA 0.434700 ;
    ANTENNADIFFAREA 1.137600 ;
    PORT
      LAYER met2 ;
        RECT 494.130 0.000 494.410 0.280 ;
    END
  END s6_axi_araddr_0
  PIN s6_axi_araddr_1
    DIRECTION OUTPUT ;
    USE SIGNAL ;
    ANTENNAGATEAREA 0.434700 ;
    ANTENNADIFFAREA 1.137600 ;
    PORT
      LAYER met2 ;
        RECT 408.570 519.840 408.850 520.120 ;
    END
  END s6_axi_araddr_1
  PIN s6_axi_araddr_10
    DIRECTION OUTPUT ;
    USE SIGNAL ;
    ANTENNAGATEAREA 0.434700 ;
    ANTENNADIFFAREA 1.137600 ;
    PORT
      LAYER met2 ;
        RECT 206.170 519.840 206.450 520.120 ;
    END
  END s6_axi_araddr_10
  PIN s6_axi_araddr_11
    DIRECTION OUTPUT ;
    USE SIGNAL ;
    ANTENNAGATEAREA 0.434700 ;
    ANTENNADIFFAREA 1.137600 ;
    PORT
      LAYER met2 ;
        RECT 318.410 519.840 318.690 520.120 ;
    END
  END s6_axi_araddr_11
  PIN s6_axi_araddr_12
    DIRECTION OUTPUT ;
    USE SIGNAL ;
    ANTENNAGATEAREA 0.434700 ;
    ANTENNADIFFAREA 1.137600 ;
    PORT
      LAYER met2 ;
        RECT 85.650 519.840 85.930 520.120 ;
    END
  END s6_axi_araddr_12
  PIN s6_axi_araddr_13
    DIRECTION OUTPUT ;
    USE SIGNAL ;
    ANTENNAGATEAREA 0.434700 ;
    ANTENNADIFFAREA 1.137600 ;
    PORT
      LAYER met2 ;
        RECT 402.130 0.000 402.410 0.280 ;
    END
  END s6_axi_araddr_13
  PIN s6_axi_araddr_14
    DIRECTION OUTPUT ;
    USE SIGNAL ;
    ANTENNAGATEAREA 0.434700 ;
    ANTENNADIFFAREA 1.137600 ;
    PORT
      LAYER met2 ;
        RECT 370.850 0.000 371.130 0.280 ;
    END
  END s6_axi_araddr_14
  PIN s6_axi_araddr_15
    DIRECTION OUTPUT ;
    USE SIGNAL ;
    ANTENNAGATEAREA 0.434700 ;
    ANTENNADIFFAREA 1.137600 ;
    PORT
      LAYER met2 ;
        RECT 120.610 519.840 120.890 520.120 ;
    END
  END s6_axi_araddr_15
  PIN s6_axi_araddr_16
    DIRECTION OUTPUT ;
    USE SIGNAL ;
    ANTENNAGATEAREA 0.434700 ;
    ANTENNADIFFAREA 1.137600 ;
    PORT
      LAYER met2 ;
        RECT 173.050 519.840 173.330 520.120 ;
    END
  END s6_axi_araddr_16
  PIN s6_axi_araddr_17
    DIRECTION OUTPUT ;
    USE SIGNAL ;
    ANTENNAGATEAREA 0.434700 ;
    ANTENNADIFFAREA 1.137600 ;
    PORT
      LAYER met2 ;
        RECT 461.930 0.000 462.210 0.280 ;
    END
  END s6_axi_araddr_17
  PIN s6_axi_araddr_18
    DIRECTION OUTPUT ;
    USE SIGNAL ;
    ANTENNAGATEAREA 0.434700 ;
    ANTENNADIFFAREA 1.137600 ;
    PORT
      LAYER met2 ;
        RECT 369.930 0.000 370.210 0.280 ;
    END
  END s6_axi_araddr_18
  PIN s6_axi_araddr_19
    DIRECTION OUTPUT ;
    USE SIGNAL ;
    ANTENNAGATEAREA 0.434700 ;
    ANTENNADIFFAREA 1.137600 ;
    PORT
      LAYER met3 ;
        RECT 0.000 46.280 0.600 46.880 ;
    END
  END s6_axi_araddr_19
  PIN s6_axi_araddr_2
    DIRECTION OUTPUT ;
    USE SIGNAL ;
    ANTENNAGATEAREA 0.434700 ;
    ANTENNADIFFAREA 1.137600 ;
    PORT
      LAYER met3 ;
        RECT 0.000 53.080 0.600 53.680 ;
    END
  END s6_axi_araddr_2
  PIN s6_axi_araddr_20
    DIRECTION OUTPUT ;
    USE SIGNAL ;
    ANTENNAGATEAREA 0.434700 ;
    ANTENNADIFFAREA 1.137600 ;
    PORT
      LAYER met3 ;
        RECT 0.000 389.000 0.600 389.600 ;
    END
  END s6_axi_araddr_20
  PIN s6_axi_araddr_21
    DIRECTION OUTPUT ;
    USE SIGNAL ;
    ANTENNAGATEAREA 0.434700 ;
    ANTENNADIFFAREA 1.137600 ;
    PORT
      LAYER met2 ;
        RECT 186.850 519.840 187.130 520.120 ;
    END
  END s6_axi_araddr_21
  PIN s6_axi_araddr_22
    DIRECTION OUTPUT ;
    USE SIGNAL ;
    ANTENNAGATEAREA 0.434700 ;
    ANTENNADIFFAREA 1.137600 ;
    PORT
      LAYER met2 ;
        RECT 327.610 519.840 327.890 520.120 ;
    END
  END s6_axi_araddr_22
  PIN s6_axi_araddr_23
    DIRECTION OUTPUT ;
    USE SIGNAL ;
    ANTENNAGATEAREA 0.434700 ;
    ANTENNADIFFAREA 1.137600 ;
    PORT
      LAYER met3 ;
        RECT 0.000 97.960 0.600 98.560 ;
    END
  END s6_axi_araddr_23
  PIN s6_axi_araddr_24
    DIRECTION OUTPUT ;
    USE SIGNAL ;
    ANTENNAGATEAREA 0.434700 ;
    ANTENNADIFFAREA 1.137600 ;
    PORT
      LAYER met2 ;
        RECT 153.730 519.840 154.010 520.120 ;
    END
  END s6_axi_araddr_24
  PIN s6_axi_araddr_25
    DIRECTION OUTPUT ;
    USE SIGNAL ;
    ANTENNAGATEAREA 0.434700 ;
    ANTENNADIFFAREA 1.137600 ;
    PORT
      LAYER met2 ;
        RECT 47.010 519.840 47.290 520.120 ;
    END
  END s6_axi_araddr_25
  PIN s6_axi_araddr_26
    DIRECTION OUTPUT ;
    USE SIGNAL ;
    ANTENNAGATEAREA 0.434700 ;
    ANTENNADIFFAREA 1.137600 ;
    PORT
      LAYER met3 ;
        RECT 0.000 81.640 0.600 82.240 ;
    END
  END s6_axi_araddr_26
  PIN s6_axi_araddr_27
    DIRECTION OUTPUT ;
    USE SIGNAL ;
    ANTENNAGATEAREA 0.434700 ;
    ANTENNADIFFAREA 1.137600 ;
    PORT
      LAYER met2 ;
        RECT 396.610 519.840 396.890 520.120 ;
    END
  END s6_axi_araddr_27
  PIN s6_axi_araddr_28
    DIRECTION OUTPUT ;
    USE SIGNAL ;
    ANTENNAGATEAREA 0.434700 ;
    ANTENNADIFFAREA 1.137600 ;
    PORT
      LAYER met3 ;
        RECT 0.000 32.680 0.600 33.280 ;
    END
  END s6_axi_araddr_28
  PIN s6_axi_araddr_29
    DIRECTION OUTPUT ;
    USE SIGNAL ;
    ANTENNAGATEAREA 0.434700 ;
    ANTENNADIFFAREA 1.137600 ;
    PORT
      LAYER met2 ;
        RECT 98.530 519.840 98.810 520.120 ;
    END
  END s6_axi_araddr_29
  PIN s6_axi_araddr_3
    DIRECTION OUTPUT ;
    USE SIGNAL ;
    ANTENNAGATEAREA 0.434700 ;
    ANTENNADIFFAREA 1.137600 ;
    PORT
      LAYER met3 ;
        RECT 0.000 17.720 0.600 18.320 ;
    END
  END s6_axi_araddr_3
  PIN s6_axi_araddr_30
    DIRECTION OUTPUT ;
    USE SIGNAL ;
    ANTENNAGATEAREA 0.434700 ;
    ANTENNADIFFAREA 1.137600 ;
    PORT
      LAYER met2 ;
        RECT 70.930 519.840 71.210 520.120 ;
    END
  END s6_axi_araddr_30
  PIN s6_axi_araddr_31
    DIRECTION OUTPUT ;
    USE SIGNAL ;
    ANTENNAGATEAREA 0.434700 ;
    ANTENNADIFFAREA 1.137600 ;
    PORT
      LAYER met2 ;
        RECT 156.490 519.840 156.770 520.120 ;
    END
  END s6_axi_araddr_31
  PIN s6_axi_araddr_4
    DIRECTION OUTPUT ;
    USE SIGNAL ;
    ANTENNAGATEAREA 0.434700 ;
    ANTENNADIFFAREA 1.137600 ;
    PORT
      LAYER met2 ;
        RECT 311.050 519.840 311.330 520.120 ;
    END
  END s6_axi_araddr_4
  PIN s6_axi_araddr_5
    DIRECTION OUTPUT ;
    USE SIGNAL ;
    ANTENNAGATEAREA 0.434700 ;
    ANTENNADIFFAREA 1.137600 ;
    PORT
      LAYER met2 ;
        RECT 377.290 519.840 377.570 520.120 ;
    END
  END s6_axi_araddr_5
  PIN s6_axi_araddr_6
    DIRECTION OUTPUT ;
    USE SIGNAL ;
    ANTENNAGATEAREA 0.434700 ;
    ANTENNADIFFAREA 1.137600 ;
    PORT
      LAYER met2 ;
        RECT 403.970 0.000 404.250 0.280 ;
    END
  END s6_axi_araddr_6
  PIN s6_axi_araddr_7
    DIRECTION OUTPUT ;
    USE SIGNAL ;
    ANTENNAGATEAREA 0.434700 ;
    ANTENNADIFFAREA 1.137600 ;
    PORT
      LAYER met3 ;
        RECT 0.000 54.440 0.600 55.040 ;
    END
  END s6_axi_araddr_7
  PIN s6_axi_araddr_8
    DIRECTION OUTPUT ;
    USE SIGNAL ;
    ANTENNAGATEAREA 0.434700 ;
    ANTENNADIFFAREA 1.137600 ;
    PORT
      LAYER met2 ;
        RECT 425.130 0.000 425.410 0.280 ;
    END
  END s6_axi_araddr_8
  PIN s6_axi_araddr_9
    DIRECTION OUTPUT ;
    USE SIGNAL ;
    ANTENNAGATEAREA 0.434700 ;
    ANTENNADIFFAREA 1.137600 ;
    PORT
      LAYER met2 ;
        RECT 450.890 519.840 451.170 520.120 ;
    END
  END s6_axi_araddr_9
  PIN s6_axi_arready
    DIRECTION INPUT ;
    USE SIGNAL ;
    ANTENNAGATEAREA 0.647700 ;
    ANTENNADIFFAREA 0.434700 ;
    PORT
      LAYER met2 ;
        RECT 308.290 519.840 308.570 520.120 ;
    END
  END s6_axi_arready
  PIN s6_axi_arvalid
    DIRECTION OUTPUT ;
    USE SIGNAL ;
    ANTENNAGATEAREA 0.434700 ;
    ANTENNADIFFAREA 1.137600 ;
    PORT
      LAYER met2 ;
        RECT 217.210 519.840 217.490 520.120 ;
    END
  END s6_axi_arvalid
  PIN s6_axi_awaddr_0
    DIRECTION OUTPUT ;
    USE SIGNAL ;
    ANTENNAGATEAREA 0.434700 ;
    ANTENNADIFFAREA 1.137600 ;
    PORT
      LAYER met2 ;
        RECT 497.810 0.000 498.090 0.280 ;
    END
  END s6_axi_awaddr_0
  PIN s6_axi_awaddr_1
    DIRECTION OUTPUT ;
    USE SIGNAL ;
    ANTENNAGATEAREA 0.434700 ;
    ANTENNADIFFAREA 1.137600 ;
    PORT
      LAYER met2 ;
        RECT 404.890 0.000 405.170 0.280 ;
    END
  END s6_axi_awaddr_1
  PIN s6_axi_awaddr_10
    DIRECTION OUTPUT ;
    USE SIGNAL ;
    ANTENNAGATEAREA 0.434700 ;
    ANTENNADIFFAREA 1.137600 ;
    PORT
      LAYER met2 ;
        RECT 392.930 0.000 393.210 0.280 ;
    END
  END s6_axi_awaddr_10
  PIN s6_axi_awaddr_11
    DIRECTION OUTPUT ;
    USE SIGNAL ;
    ANTENNAGATEAREA 0.434700 ;
    ANTENNADIFFAREA 1.137600 ;
    PORT
      LAYER met2 ;
        RECT 462.850 0.000 463.130 0.280 ;
    END
  END s6_axi_awaddr_11
  PIN s6_axi_awaddr_12
    DIRECTION OUTPUT ;
    USE SIGNAL ;
    ANTENNAGATEAREA 0.434700 ;
    ANTENNADIFFAREA 1.137600 ;
    PORT
      LAYER met2 ;
        RECT 291.730 519.840 292.010 520.120 ;
    END
  END s6_axi_awaddr_12
  PIN s6_axi_awaddr_13
    DIRECTION OUTPUT ;
    USE SIGNAL ;
    ANTENNAGATEAREA 0.434700 ;
    ANTENNADIFFAREA 1.137600 ;
    PORT
      LAYER met3 ;
        RECT 508.800 126.520 509.400 127.120 ;
    END
  END s6_axi_awaddr_13
  PIN s6_axi_awaddr_14
    DIRECTION OUTPUT ;
    USE SIGNAL ;
    ANTENNAGATEAREA 0.434700 ;
    ANTENNADIFFAREA 1.137600 ;
    PORT
      LAYER met2 ;
        RECT 374.530 0.000 374.810 0.280 ;
    END
  END s6_axi_awaddr_14
  PIN s6_axi_awaddr_15
    DIRECTION OUTPUT ;
    USE SIGNAL ;
    ANTENNAGATEAREA 0.434700 ;
    ANTENNADIFFAREA 1.137600 ;
    PORT
      LAYER met2 ;
        RECT 106.810 519.840 107.090 520.120 ;
    END
  END s6_axi_awaddr_15
  PIN s6_axi_awaddr_16
    DIRECTION OUTPUT ;
    USE SIGNAL ;
    ANTENNAGATEAREA 0.434700 ;
    ANTENNADIFFAREA 1.137600 ;
    PORT
      LAYER met2 ;
        RECT 406.730 0.000 407.010 0.280 ;
    END
  END s6_axi_awaddr_16
  PIN s6_axi_awaddr_17
    DIRECTION OUTPUT ;
    USE SIGNAL ;
    ANTENNAGATEAREA 0.434700 ;
    ANTENNADIFFAREA 1.137600 ;
    PORT
      LAYER met2 ;
        RECT 356.130 519.840 356.410 520.120 ;
    END
  END s6_axi_awaddr_17
  PIN s6_axi_awaddr_18
    DIRECTION OUTPUT ;
    USE SIGNAL ;
    ANTENNAGATEAREA 0.434700 ;
    ANTENNADIFFAREA 1.137600 ;
    PORT
      LAYER met2 ;
        RECT 325.770 519.840 326.050 520.120 ;
    END
  END s6_axi_awaddr_18
  PIN s6_axi_awaddr_19
    DIRECTION OUTPUT ;
    USE SIGNAL ;
    ANTENNAGATEAREA 0.434700 ;
    ANTENNADIFFAREA 1.137600 ;
    PORT
      LAYER met3 ;
        RECT 508.800 454.280 509.400 454.880 ;
    END
  END s6_axi_awaddr_19
  PIN s6_axi_awaddr_2
    DIRECTION OUTPUT ;
    USE SIGNAL ;
    ANTENNAGATEAREA 0.434700 ;
    ANTENNADIFFAREA 1.137600 ;
    PORT
      LAYER met3 ;
        RECT 0.000 112.920 0.600 113.520 ;
    END
  END s6_axi_awaddr_2
  PIN s6_axi_awaddr_20
    DIRECTION OUTPUT ;
    USE SIGNAL ;
    ANTENNAGATEAREA 0.434700 ;
    ANTENNADIFFAREA 1.137600 ;
    PORT
      LAYER met3 ;
        RECT 0.000 111.560 0.600 112.160 ;
    END
  END s6_axi_awaddr_20
  PIN s6_axi_awaddr_21
    DIRECTION OUTPUT ;
    USE SIGNAL ;
    ANTENNAGATEAREA 0.434700 ;
    ANTENNADIFFAREA 1.137600 ;
    PORT
      LAYER met3 ;
        RECT 0.000 406.680 0.600 407.280 ;
    END
  END s6_axi_awaddr_21
  PIN s6_axi_awaddr_22
    DIRECTION OUTPUT ;
    USE SIGNAL ;
    ANTENNAGATEAREA 0.434700 ;
    ANTENNADIFFAREA 1.137600 ;
    PORT
      LAYER met2 ;
        RECT 463.770 0.000 464.050 0.280 ;
    END
  END s6_axi_awaddr_22
  PIN s6_axi_awaddr_23
    DIRECTION OUTPUT ;
    USE SIGNAL ;
    ANTENNAGATEAREA 0.434700 ;
    ANTENNADIFFAREA 1.137600 ;
    PORT
      LAYER met2 ;
        RECT 352.450 519.840 352.730 520.120 ;
    END
  END s6_axi_awaddr_23
  PIN s6_axi_awaddr_24
    DIRECTION OUTPUT ;
    USE SIGNAL ;
    ANTENNAGATEAREA 0.434700 ;
    ANTENNADIFFAREA 1.137600 ;
    PORT
      LAYER met2 ;
        RECT 172.130 519.840 172.410 520.120 ;
    END
  END s6_axi_awaddr_24
  PIN s6_axi_awaddr_25
    DIRECTION OUTPUT ;
    USE SIGNAL ;
    ANTENNAGATEAREA 0.434700 ;
    ANTENNADIFFAREA 1.137600 ;
    PORT
      LAYER met3 ;
        RECT 0.000 163.240 0.600 163.840 ;
    END
  END s6_axi_awaddr_25
  PIN s6_axi_awaddr_26
    DIRECTION OUTPUT ;
    USE SIGNAL ;
    ANTENNAGATEAREA 0.434700 ;
    ANTENNADIFFAREA 1.137600 ;
    PORT
      LAYER met2 ;
        RECT 203.410 519.840 203.690 520.120 ;
    END
  END s6_axi_awaddr_26
  PIN s6_axi_awaddr_27
    DIRECTION OUTPUT ;
    USE SIGNAL ;
    ANTENNAGATEAREA 0.434700 ;
    ANTENNADIFFAREA 1.137600 ;
    PORT
      LAYER met2 ;
        RECT 407.650 0.000 407.930 0.280 ;
    END
  END s6_axi_awaddr_27
  PIN s6_axi_awaddr_28
    DIRECTION OUTPUT ;
    USE SIGNAL ;
    ANTENNAGATEAREA 0.434700 ;
    ANTENNADIFFAREA 1.137600 ;
    PORT
      LAYER met2 ;
        RECT 383.730 0.000 384.010 0.280 ;
    END
  END s6_axi_awaddr_28
  PIN s6_axi_awaddr_29
    DIRECTION OUTPUT ;
    USE SIGNAL ;
    ANTENNAGATEAREA 0.434700 ;
    ANTENNADIFFAREA 1.137600 ;
    PORT
      LAYER met2 ;
        RECT 393.850 519.840 394.130 520.120 ;
    END
  END s6_axi_awaddr_29
  PIN s6_axi_awaddr_3
    DIRECTION OUTPUT ;
    USE SIGNAL ;
    ANTENNAGATEAREA 0.434700 ;
    ANTENNADIFFAREA 1.137600 ;
    PORT
      LAYER met3 ;
        RECT 0.000 70.760 0.600 71.360 ;
    END
  END s6_axi_awaddr_3
  PIN s6_axi_awaddr_30
    DIRECTION OUTPUT ;
    USE SIGNAL ;
    ANTENNAGATEAREA 0.434700 ;
    ANTENNADIFFAREA 1.137600 ;
    PORT
      LAYER met2 ;
        RECT 464.690 0.000 464.970 0.280 ;
    END
  END s6_axi_awaddr_30
  PIN s6_axi_awaddr_31
    DIRECTION OUTPUT ;
    USE SIGNAL ;
    ANTENNAGATEAREA 0.434700 ;
    ANTENNADIFFAREA 1.137600 ;
    PORT
      LAYER met2 ;
        RECT 263.210 519.840 263.490 520.120 ;
    END
  END s6_axi_awaddr_31
  PIN s6_axi_awaddr_4
    DIRECTION OUTPUT ;
    USE SIGNAL ;
    ANTENNAGATEAREA 0.434700 ;
    ANTENNADIFFAREA 1.137600 ;
    PORT
      LAYER met2 ;
        RECT 344.170 519.840 344.450 520.120 ;
    END
  END s6_axi_awaddr_4
  PIN s6_axi_awaddr_5
    DIRECTION OUTPUT ;
    USE SIGNAL ;
    ANTENNAGATEAREA 0.434700 ;
    ANTENNADIFFAREA 1.137600 ;
    PORT
      LAYER met2 ;
        RECT 387.410 0.000 387.690 0.280 ;
    END
  END s6_axi_awaddr_5
  PIN s6_axi_awaddr_6
    DIRECTION OUTPUT ;
    USE SIGNAL ;
    ANTENNAGATEAREA 0.434700 ;
    ANTENNADIFFAREA 1.137600 ;
    PORT
      LAYER met2 ;
        RECT 409.490 0.000 409.770 0.280 ;
    END
  END s6_axi_awaddr_6
  PIN s6_axi_awaddr_7
    DIRECTION OUTPUT ;
    USE SIGNAL ;
    ANTENNAGATEAREA 0.434700 ;
    ANTENNADIFFAREA 1.137600 ;
    PORT
      LAYER met3 ;
        RECT 0.000 40.840 0.600 41.440 ;
    END
  END s6_axi_awaddr_7
  PIN s6_axi_awaddr_8
    DIRECTION OUTPUT ;
    USE SIGNAL ;
    ANTENNAGATEAREA 0.434700 ;
    ANTENNADIFFAREA 1.137600 ;
    PORT
      LAYER met2 ;
        RECT 377.290 0.000 377.570 0.280 ;
    END
  END s6_axi_awaddr_8
  PIN s6_axi_awaddr_9
    DIRECTION OUTPUT ;
    USE SIGNAL ;
    ANTENNAGATEAREA 0.434700 ;
    ANTENNADIFFAREA 1.137600 ;
    PORT
      LAYER met3 ;
        RECT 508.800 465.160 509.400 465.760 ;
    END
  END s6_axi_awaddr_9
  PIN s6_axi_awready
    DIRECTION INPUT ;
    USE SIGNAL ;
    ANTENNAGATEAREA 0.647700 ;
    ANTENNADIFFAREA 0.434700 ;
    PORT
      LAYER met3 ;
        RECT 0.000 338.680 0.600 339.280 ;
    END
  END s6_axi_awready
  PIN s6_axi_awvalid
    DIRECTION OUTPUT ;
    USE SIGNAL ;
    ANTENNAGATEAREA 0.434700 ;
    ANTENNADIFFAREA 1.137600 ;
    PORT
      LAYER met3 ;
        RECT 0.000 141.480 0.600 142.080 ;
    END
  END s6_axi_awvalid
  PIN s6_axi_bready
    DIRECTION OUTPUT ;
    USE SIGNAL ;
    ANTENNAGATEAREA 0.434700 ;
    ANTENNADIFFAREA 1.137600 ;
    PORT
      LAYER met3 ;
        RECT 0.000 122.440 0.600 123.040 ;
    END
  END s6_axi_bready
  PIN s6_axi_bresp_0
    DIRECTION INPUT ;
    USE SIGNAL ;
    ANTENNAGATEAREA 0.647700 ;
    ANTENNADIFFAREA 0.434700 ;
    PORT
      LAYER met3 ;
        RECT 0.000 312.840 0.600 313.440 ;
    END
  END s6_axi_bresp_0
  PIN s6_axi_bresp_1
    DIRECTION INPUT ;
    USE SIGNAL ;
    ANTENNAGATEAREA 0.647700 ;
    ANTENNADIFFAREA 0.434700 ;
    PORT
      LAYER met3 ;
        RECT 0.000 314.200 0.600 314.800 ;
    END
  END s6_axi_bresp_1
  PIN s6_axi_bvalid
    DIRECTION INPUT ;
    USE SIGNAL ;
    ANTENNAGATEAREA 0.647700 ;
    ANTENNADIFFAREA 0.434700 ;
    PORT
      LAYER met3 ;
        RECT 0.000 334.600 0.600 335.200 ;
    END
  END s6_axi_bvalid
  PIN s6_axi_rdata_0
    DIRECTION INPUT ;
    USE SIGNAL ;
    ANTENNAGATEAREA 0.647700 ;
    ANTENNADIFFAREA 0.434700 ;
    PORT
      LAYER met3 ;
        RECT 508.800 189.080 509.400 189.680 ;
    END
  END s6_axi_rdata_0
  PIN s6_axi_rdata_1
    DIRECTION INPUT ;
    USE SIGNAL ;
    ANTENNAGATEAREA 0.647700 ;
    ANTENNADIFFAREA 0.434700 ;
    PORT
      LAYER met2 ;
        RECT 302.770 519.840 303.050 520.120 ;
    END
  END s6_axi_rdata_1
  PIN s6_axi_rdata_10
    DIRECTION INPUT ;
    USE SIGNAL ;
    ANTENNAGATEAREA 0.647700 ;
    ANTENNADIFFAREA 0.434700 ;
    PORT
      LAYER met3 ;
        RECT 508.800 321.000 509.400 321.600 ;
    END
  END s6_axi_rdata_10
  PIN s6_axi_rdata_11
    DIRECTION INPUT ;
    USE SIGNAL ;
    ANTENNAGATEAREA 0.647700 ;
    ANTENNADIFFAREA 0.434700 ;
    PORT
      LAYER met3 ;
        RECT 508.800 103.400 509.400 104.000 ;
    END
  END s6_axi_rdata_11
  PIN s6_axi_rdata_12
    DIRECTION INPUT ;
    USE SIGNAL ;
    ANTENNAGATEAREA 0.647700 ;
    ANTENNADIFFAREA 0.434700 ;
    PORT
      LAYER met3 ;
        RECT 508.800 91.160 509.400 91.760 ;
    END
  END s6_axi_rdata_12
  PIN s6_axi_rdata_13
    DIRECTION INPUT ;
    USE SIGNAL ;
    ANTENNAGATEAREA 0.647700 ;
    ANTENNADIFFAREA 0.434700 ;
    PORT
      LAYER met3 ;
        RECT 508.800 193.160 509.400 193.760 ;
    END
  END s6_axi_rdata_13
  PIN s6_axi_rdata_14
    DIRECTION INPUT ;
    USE SIGNAL ;
    ANTENNAGATEAREA 0.647700 ;
    ANTENNADIFFAREA 0.434700 ;
    PORT
      LAYER met3 ;
        RECT 508.800 323.720 509.400 324.320 ;
    END
  END s6_axi_rdata_14
  PIN s6_axi_rdata_15
    DIRECTION INPUT ;
    USE SIGNAL ;
    ANTENNAGATEAREA 0.647700 ;
    ANTENNADIFFAREA 0.434700 ;
    PORT
      LAYER met3 ;
        RECT 508.800 72.120 509.400 72.720 ;
    END
  END s6_axi_rdata_15
  PIN s6_axi_rdata_16
    DIRECTION INPUT ;
    USE SIGNAL ;
    ANTENNAGATEAREA 0.647700 ;
    ANTENNADIFFAREA 0.434700 ;
    PORT
      LAYER met3 ;
        RECT 508.800 159.160 509.400 159.760 ;
    END
  END s6_axi_rdata_16
  PIN s6_axi_rdata_17
    DIRECTION INPUT ;
    USE SIGNAL ;
    ANTENNAGATEAREA 0.647700 ;
    ANTENNADIFFAREA 0.434700 ;
    PORT
      LAYER met3 ;
        RECT 508.800 303.320 509.400 303.920 ;
    END
  END s6_axi_rdata_17
  PIN s6_axi_rdata_18
    DIRECTION INPUT ;
    USE SIGNAL ;
    ANTENNAGATEAREA 0.647700 ;
    ANTENNADIFFAREA 0.434700 ;
    PORT
      LAYER met3 ;
        RECT 508.800 190.440 509.400 191.040 ;
    END
  END s6_axi_rdata_18
  PIN s6_axi_rdata_19
    DIRECTION INPUT ;
    USE SIGNAL ;
    ANTENNAGATEAREA 0.647700 ;
    ANTENNADIFFAREA 0.434700 ;
    PORT
      LAYER met3 ;
        RECT 508.800 334.600 509.400 335.200 ;
    END
  END s6_axi_rdata_19
  PIN s6_axi_rdata_2
    DIRECTION INPUT ;
    USE SIGNAL ;
    ANTENNAGATEAREA 0.647700 ;
    ANTENNADIFFAREA 0.434700 ;
    PORT
      LAYER met3 ;
        RECT 508.800 209.480 509.400 210.080 ;
    END
  END s6_axi_rdata_2
  PIN s6_axi_rdata_20
    DIRECTION INPUT ;
    USE SIGNAL ;
    ANTENNAGATEAREA 0.647700 ;
    ANTENNADIFFAREA 0.434700 ;
    PORT
      LAYER met3 ;
        RECT 508.800 248.920 509.400 249.520 ;
    END
  END s6_axi_rdata_20
  PIN s6_axi_rdata_21
    DIRECTION INPUT ;
    USE SIGNAL ;
    ANTENNAGATEAREA 0.647700 ;
    ANTENNADIFFAREA 0.434700 ;
    PORT
      LAYER met3 ;
        RECT 508.800 367.240 509.400 367.840 ;
    END
  END s6_axi_rdata_21
  PIN s6_axi_rdata_22
    DIRECTION INPUT ;
    USE SIGNAL ;
    ANTENNAGATEAREA 0.647700 ;
    ANTENNADIFFAREA 0.434700 ;
    PORT
      LAYER met3 ;
        RECT 508.800 250.280 509.400 250.880 ;
    END
  END s6_axi_rdata_22
  PIN s6_axi_rdata_23
    DIRECTION INPUT ;
    USE SIGNAL ;
    ANTENNAGATEAREA 0.647700 ;
    ANTENNADIFFAREA 0.434700 ;
    PORT
      LAYER met3 ;
        RECT 508.800 66.680 509.400 67.280 ;
    END
  END s6_axi_rdata_23
  PIN s6_axi_rdata_24
    DIRECTION INPUT ;
    USE SIGNAL ;
    ANTENNAGATEAREA 0.647700 ;
    ANTENNADIFFAREA 0.434700 ;
    PORT
      LAYER met3 ;
        RECT 508.800 270.680 509.400 271.280 ;
    END
  END s6_axi_rdata_24
  PIN s6_axi_rdata_25
    DIRECTION INPUT ;
    USE SIGNAL ;
    ANTENNAGATEAREA 0.647700 ;
    ANTENNADIFFAREA 0.434700 ;
    PORT
      LAYER met3 ;
        RECT 508.800 482.840 509.400 483.440 ;
    END
  END s6_axi_rdata_25
  PIN s6_axi_rdata_26
    DIRECTION INPUT ;
    USE SIGNAL ;
    ANTENNAGATEAREA 0.647700 ;
    ANTENNADIFFAREA 0.434700 ;
    PORT
      LAYER met3 ;
        RECT 508.800 182.280 509.400 182.880 ;
    END
  END s6_axi_rdata_26
  PIN s6_axi_rdata_27
    DIRECTION INPUT ;
    USE SIGNAL ;
    ANTENNAGATEAREA 0.647700 ;
    ANTENNADIFFAREA 0.434700 ;
    PORT
      LAYER met3 ;
        RECT 508.800 212.200 509.400 212.800 ;
    END
  END s6_axi_rdata_27
  PIN s6_axi_rdata_28
    DIRECTION INPUT ;
    USE SIGNAL ;
    ANTENNAGATEAREA 0.647700 ;
    ANTENNADIFFAREA 0.434700 ;
    PORT
      LAYER met3 ;
        RECT 508.800 170.040 509.400 170.640 ;
    END
  END s6_axi_rdata_28
  PIN s6_axi_rdata_29
    DIRECTION INPUT ;
    USE SIGNAL ;
    ANTENNAGATEAREA 0.647700 ;
    ANTENNADIFFAREA 0.434700 ;
    PORT
      LAYER met3 ;
        RECT 508.800 273.400 509.400 274.000 ;
    END
  END s6_axi_rdata_29
  PIN s6_axi_rdata_3
    DIRECTION INPUT ;
    USE SIGNAL ;
    ANTENNAGATEAREA 0.647700 ;
    ANTENNADIFFAREA 0.434700 ;
    PORT
      LAYER met3 ;
        RECT 508.800 337.320 509.400 337.920 ;
    END
  END s6_axi_rdata_3
  PIN s6_axi_rdata_30
    DIRECTION INPUT ;
    USE SIGNAL ;
    ANTENNAGATEAREA 0.647700 ;
    ANTENNADIFFAREA 0.434700 ;
    PORT
      LAYER met3 ;
        RECT 508.800 104.760 509.400 105.360 ;
    END
  END s6_axi_rdata_30
  PIN s6_axi_rdata_31
    DIRECTION INPUT ;
    USE SIGNAL ;
    ANTENNAGATEAREA 0.647700 ;
    ANTENNADIFFAREA 0.434700 ;
    PORT
      LAYER met3 ;
        RECT 508.800 447.480 509.400 448.080 ;
    END
  END s6_axi_rdata_31
  PIN s6_axi_rdata_4
    DIRECTION INPUT ;
    USE SIGNAL ;
    ANTENNAGATEAREA 0.647700 ;
    ANTENNADIFFAREA 0.434700 ;
    PORT
      LAYER met3 ;
        RECT 508.800 414.840 509.400 415.440 ;
    END
  END s6_axi_rdata_4
  PIN s6_axi_rdata_5
    DIRECTION INPUT ;
    USE SIGNAL ;
    ANTENNAGATEAREA 0.647700 ;
    ANTENNADIFFAREA 0.434700 ;
    PORT
      LAYER met3 ;
        RECT 508.800 251.640 509.400 252.240 ;
    END
  END s6_axi_rdata_5
  PIN s6_axi_rdata_6
    DIRECTION INPUT ;
    USE SIGNAL ;
    ANTENNAGATEAREA 0.647700 ;
    ANTENNADIFFAREA 0.434700 ;
    PORT
      LAYER met3 ;
        RECT 508.800 405.320 509.400 405.920 ;
    END
  END s6_axi_rdata_6
  PIN s6_axi_rdata_7
    DIRECTION INPUT ;
    USE SIGNAL ;
    ANTENNAGATEAREA 0.647700 ;
    ANTENNADIFFAREA 0.434700 ;
    PORT
      LAYER met3 ;
        RECT 508.800 469.240 509.400 469.840 ;
    END
  END s6_axi_rdata_7
  PIN s6_axi_rdata_8
    DIRECTION INPUT ;
    USE SIGNAL ;
    ANTENNAGATEAREA 0.647700 ;
    ANTENNADIFFAREA 0.434700 ;
    PORT
      LAYER met3 ;
        RECT 508.800 295.160 509.400 295.760 ;
    END
  END s6_axi_rdata_8
  PIN s6_axi_rdata_9
    DIRECTION INPUT ;
    USE SIGNAL ;
    ANTENNAGATEAREA 0.647700 ;
    ANTENNADIFFAREA 0.434700 ;
    PORT
      LAYER met3 ;
        RECT 508.800 57.160 509.400 57.760 ;
    END
  END s6_axi_rdata_9
  PIN s6_axi_rready
    DIRECTION OUTPUT ;
    USE SIGNAL ;
    ANTENNAGATEAREA 0.434700 ;
    ANTENNADIFFAREA 1.137600 ;
    PORT
      LAYER met3 ;
        RECT 0.000 191.800 0.600 192.400 ;
    END
  END s6_axi_rready
  PIN s6_axi_rresp_0
    DIRECTION INPUT ;
    USE SIGNAL ;
    ANTENNAGATEAREA 0.647700 ;
    ANTENNADIFFAREA 0.434700 ;
    PORT
      LAYER met3 ;
        RECT 508.800 501.880 509.400 502.480 ;
    END
  END s6_axi_rresp_0
  PIN s6_axi_rresp_1
    DIRECTION INPUT ;
    USE SIGNAL ;
    ANTENNAGATEAREA 0.647700 ;
    ANTENNADIFFAREA 0.434700 ;
    PORT
      LAYER met3 ;
        RECT 508.800 96.600 509.400 97.200 ;
    END
  END s6_axi_rresp_1
  PIN s6_axi_rvalid
    DIRECTION INPUT ;
    USE SIGNAL ;
    ANTENNAGATEAREA 0.647700 ;
    ANTENNADIFFAREA 0.434700 ;
    PORT
      LAYER met3 ;
        RECT 508.800 488.280 509.400 488.880 ;
    END
  END s6_axi_rvalid
  PIN s6_axi_wdata_0
    DIRECTION OUTPUT ;
    USE SIGNAL ;
    ANTENNAGATEAREA 0.434700 ;
    ANTENNADIFFAREA 1.137600 ;
    PORT
      LAYER met3 ;
        RECT 0.000 131.960 0.600 132.560 ;
    END
  END s6_axi_wdata_0
  PIN s6_axi_wdata_1
    DIRECTION OUTPUT ;
    USE SIGNAL ;
    ANTENNAGATEAREA 0.434700 ;
    ANTENNADIFFAREA 1.137600 ;
    PORT
      LAYER met2 ;
        RECT 465.610 0.000 465.890 0.280 ;
    END
  END s6_axi_wdata_1
  PIN s6_axi_wdata_10
    DIRECTION OUTPUT ;
    USE SIGNAL ;
    ANTENNAGATEAREA 0.434700 ;
    ANTENNADIFFAREA 1.137600 ;
    PORT
      LAYER met2 ;
        RECT 195.130 519.840 195.410 520.120 ;
    END
  END s6_axi_wdata_10
  PIN s6_axi_wdata_11
    DIRECTION OUTPUT ;
    USE SIGNAL ;
    ANTENNAGATEAREA 0.434700 ;
    ANTENNADIFFAREA 1.137600 ;
    PORT
      LAYER met2 ;
        RECT 131.650 519.840 131.930 520.120 ;
    END
  END s6_axi_wdata_11
  PIN s6_axi_wdata_12
    DIRECTION OUTPUT ;
    USE SIGNAL ;
    ANTENNAGATEAREA 0.434700 ;
    ANTENNADIFFAREA 1.137600 ;
    PORT
      LAYER met3 ;
        RECT 0.000 89.800 0.600 90.400 ;
    END
  END s6_axi_wdata_12
  PIN s6_axi_wdata_13
    DIRECTION OUTPUT ;
    USE SIGNAL ;
    ANTENNAGATEAREA 0.434700 ;
    ANTENNADIFFAREA 1.137600 ;
    PORT
      LAYER met2 ;
        RECT 227.330 519.840 227.610 520.120 ;
    END
  END s6_axi_wdata_13
  PIN s6_axi_wdata_14
    DIRECTION OUTPUT ;
    USE SIGNAL ;
    ANTENNAGATEAREA 0.434700 ;
    ANTENNADIFFAREA 1.137600 ;
    PORT
      LAYER met2 ;
        RECT 373.610 519.840 373.890 520.120 ;
    END
  END s6_axi_wdata_14
  PIN s6_axi_wdata_15
    DIRECTION OUTPUT ;
    USE SIGNAL ;
    ANTENNAGATEAREA 0.434700 ;
    ANTENNADIFFAREA 1.137600 ;
    PORT
      LAYER met2 ;
        RECT 113.250 519.840 113.530 520.120 ;
    END
  END s6_axi_wdata_15
  PIN s6_axi_wdata_16
    DIRECTION OUTPUT ;
    USE SIGNAL ;
    ANTENNAGATEAREA 0.434700 ;
    ANTENNADIFFAREA 1.137600 ;
    PORT
      LAYER met3 ;
        RECT 0.000 399.880 0.600 400.480 ;
    END
  END s6_axi_wdata_16
  PIN s6_axi_wdata_17
    DIRECTION OUTPUT ;
    USE SIGNAL ;
    ANTENNAGATEAREA 0.434700 ;
    ANTENNADIFFAREA 1.137600 ;
    PORT
      LAYER met2 ;
        RECT 148.210 519.840 148.490 520.120 ;
    END
  END s6_axi_wdata_17
  PIN s6_axi_wdata_18
    DIRECTION OUTPUT ;
    USE SIGNAL ;
    ANTENNAGATEAREA 0.434700 ;
    ANTENNADIFFAREA 1.137600 ;
    PORT
      LAYER met2 ;
        RECT 424.210 0.000 424.490 0.280 ;
    END
  END s6_axi_wdata_18
  PIN s6_axi_wdata_19
    DIRECTION OUTPUT ;
    USE SIGNAL ;
    ANTENNAGATEAREA 0.434700 ;
    ANTENNADIFFAREA 1.137600 ;
    PORT
      LAYER met2 ;
        RECT 240.210 519.840 240.490 520.120 ;
    END
  END s6_axi_wdata_19
  PIN s6_axi_wdata_2
    DIRECTION OUTPUT ;
    USE SIGNAL ;
    ANTENNAGATEAREA 0.434700 ;
    ANTENNADIFFAREA 1.137600 ;
    PORT
      LAYER met2 ;
        RECT 208.930 519.840 209.210 520.120 ;
    END
  END s6_axi_wdata_2
  PIN s6_axi_wdata_20
    DIRECTION OUTPUT ;
    USE SIGNAL ;
    ANTENNAGATEAREA 0.434700 ;
    ANTENNADIFFAREA 1.137600 ;
    PORT
      LAYER met3 ;
        RECT 508.800 111.560 509.400 112.160 ;
    END
  END s6_axi_wdata_20
  PIN s6_axi_wdata_21
    DIRECTION OUTPUT ;
    USE SIGNAL ;
    ANTENNAGATEAREA 0.434700 ;
    ANTENNADIFFAREA 1.137600 ;
    PORT
      LAYER met2 ;
        RECT 93.010 519.840 93.290 520.120 ;
    END
  END s6_axi_wdata_21
  PIN s6_axi_wdata_22
    DIRECTION OUTPUT ;
    USE SIGNAL ;
    ANTENNAGATEAREA 0.434700 ;
    ANTENNADIFFAREA 1.137600 ;
    PORT
      LAYER met2 ;
        RECT 427.890 519.840 428.170 520.120 ;
    END
  END s6_axi_wdata_22
  PIN s6_axi_wdata_23
    DIRECTION OUTPUT ;
    USE SIGNAL ;
    ANTENNAGATEAREA 0.434700 ;
    ANTENNADIFFAREA 1.137600 ;
    PORT
      LAYER met3 ;
        RECT 0.000 395.800 0.600 396.400 ;
    END
  END s6_axi_wdata_23
  PIN s6_axi_wdata_24
    DIRECTION OUTPUT ;
    USE SIGNAL ;
    ANTENNAGATEAREA 0.434700 ;
    ANTENNADIFFAREA 1.137600 ;
    PORT
      LAYER met3 ;
        RECT 0.000 126.520 0.600 127.120 ;
    END
  END s6_axi_wdata_24
  PIN s6_axi_wdata_25
    DIRECTION OUTPUT ;
    USE SIGNAL ;
    ANTENNAGATEAREA 0.434700 ;
    ANTENNADIFFAREA 1.137600 ;
    PORT
      LAYER met2 ;
        RECT 52.530 519.840 52.810 520.120 ;
    END
  END s6_axi_wdata_25
  PIN s6_axi_wdata_26
    DIRECTION OUTPUT ;
    USE SIGNAL ;
    ANTENNAGATEAREA 0.434700 ;
    ANTENNADIFFAREA 1.137600 ;
    PORT
      LAYER met3 ;
        RECT 0.000 25.880 0.600 26.480 ;
    END
  END s6_axi_wdata_26
  PIN s6_axi_wdata_27
    DIRECTION OUTPUT ;
    USE SIGNAL ;
    ANTENNAGATEAREA 0.434700 ;
    ANTENNADIFFAREA 1.137600 ;
    PORT
      LAYER met2 ;
        RECT 105.890 519.840 106.170 520.120 ;
    END
  END s6_axi_wdata_27
  PIN s6_axi_wdata_28
    DIRECTION OUTPUT ;
    USE SIGNAL ;
    ANTENNAGATEAREA 0.434700 ;
    ANTENNADIFFAREA 1.137600 ;
    PORT
      LAYER met2 ;
        RECT 222.730 519.840 223.010 520.120 ;
    END
  END s6_axi_wdata_28
  PIN s6_axi_wdata_29
    DIRECTION OUTPUT ;
    USE SIGNAL ;
    ANTENNAGATEAREA 0.434700 ;
    ANTENNADIFFAREA 1.137600 ;
    PORT
      LAYER met2 ;
        RECT 450.890 0.000 451.170 0.280 ;
    END
  END s6_axi_wdata_29
  PIN s6_axi_wdata_3
    DIRECTION OUTPUT ;
    USE SIGNAL ;
    ANTENNAGATEAREA 0.434700 ;
    ANTENNADIFFAREA 1.137600 ;
    PORT
      LAYER met2 ;
        RECT 130.730 519.840 131.010 520.120 ;
    END
  END s6_axi_wdata_3
  PIN s6_axi_wdata_30
    DIRECTION OUTPUT ;
    USE SIGNAL ;
    ANTENNAGATEAREA 0.434700 ;
    ANTENNADIFFAREA 1.137600 ;
    PORT
      LAYER met2 ;
        RECT 495.050 0.000 495.330 0.280 ;
    END
  END s6_axi_wdata_30
  PIN s6_axi_wdata_31
    DIRECTION OUTPUT ;
    USE SIGNAL ;
    ANTENNAGATEAREA 0.434700 ;
    ANTENNADIFFAREA 1.137600 ;
    PORT
      LAYER met2 ;
        RECT 275.170 519.840 275.450 520.120 ;
    END
  END s6_axi_wdata_31
  PIN s6_axi_wdata_4
    DIRECTION OUTPUT ;
    USE SIGNAL ;
    ANTENNAGATEAREA 0.434700 ;
    ANTENNADIFFAREA 1.137600 ;
    PORT
      LAYER met3 ;
        RECT 0.000 62.600 0.600 63.200 ;
    END
  END s6_axi_wdata_4
  PIN s6_axi_wdata_5
    DIRECTION OUTPUT ;
    USE SIGNAL ;
    ANTENNAGATEAREA 0.434700 ;
    ANTENNADIFFAREA 1.137600 ;
    PORT
      LAYER met3 ;
        RECT 0.000 369.960 0.600 370.560 ;
    END
  END s6_axi_wdata_5
  PIN s6_axi_wdata_6
    DIRECTION OUTPUT ;
    USE SIGNAL ;
    ANTENNAGATEAREA 0.434700 ;
    ANTENNADIFFAREA 1.137600 ;
    PORT
      LAYER met2 ;
        RECT 411.330 0.000 411.610 0.280 ;
    END
  END s6_axi_wdata_6
  PIN s6_axi_wdata_7
    DIRECTION OUTPUT ;
    USE SIGNAL ;
    ANTENNAGATEAREA 0.434700 ;
    ANTENNADIFFAREA 1.137600 ;
    PORT
      LAYER met2 ;
        RECT 370.850 519.840 371.130 520.120 ;
    END
  END s6_axi_wdata_7
  PIN s6_axi_wdata_8
    DIRECTION OUTPUT ;
    USE SIGNAL ;
    ANTENNAGATEAREA 0.434700 ;
    ANTENNADIFFAREA 1.137600 ;
    PORT
      LAYER met2 ;
        RECT 419.610 0.000 419.890 0.280 ;
    END
  END s6_axi_wdata_8
  PIN s6_axi_wdata_9
    DIRECTION OUTPUT ;
    USE SIGNAL ;
    ANTENNAGATEAREA 0.434700 ;
    ANTENNADIFFAREA 1.137600 ;
    PORT
      LAYER met3 ;
        RECT 508.800 467.880 509.400 468.480 ;
    END
  END s6_axi_wdata_9
  PIN s6_axi_wready
    DIRECTION INPUT ;
    USE SIGNAL ;
    ANTENNAGATEAREA 0.647700 ;
    ANTENNADIFFAREA 0.434700 ;
    PORT
      LAYER met3 ;
        RECT 0.000 327.800 0.600 328.400 ;
    END
  END s6_axi_wready
  PIN s6_axi_wstrb_0
    DIRECTION OUTPUT ;
    USE SIGNAL ;
    ANTENNAGATEAREA 0.434700 ;
    ANTENNADIFFAREA 1.137600 ;
    PORT
      LAYER met2 ;
        RECT 259.530 519.840 259.810 520.120 ;
    END
  END s6_axi_wstrb_0
  PIN s6_axi_wstrb_1
    DIRECTION OUTPUT ;
    USE SIGNAL ;
    ANTENNAGATEAREA 0.434700 ;
    ANTENNADIFFAREA 1.137600 ;
    PORT
      LAYER met3 ;
        RECT 0.000 92.520 0.600 93.120 ;
    END
  END s6_axi_wstrb_1
  PIN s6_axi_wstrb_2
    DIRECTION OUTPUT ;
    USE SIGNAL ;
    ANTENNAGATEAREA 0.434700 ;
    ANTENNADIFFAREA 1.137600 ;
    PORT
      LAYER met2 ;
        RECT 421.450 519.840 421.730 520.120 ;
    END
  END s6_axi_wstrb_2
  PIN s6_axi_wstrb_3
    DIRECTION OUTPUT ;
    USE SIGNAL ;
    ANTENNAGATEAREA 0.434700 ;
    ANTENNADIFFAREA 1.137600 ;
    PORT
      LAYER met2 ;
        RECT 61.730 519.840 62.010 520.120 ;
    END
  END s6_axi_wstrb_3
  PIN s6_axi_wvalid
    DIRECTION OUTPUT ;
    USE SIGNAL ;
    ANTENNAGATEAREA 0.434700 ;
    ANTENNADIFFAREA 1.137600 ;
    PORT
      LAYER met3 ;
        RECT 0.000 151.000 0.600 151.600 ;
    END
  END s6_axi_wvalid
  PIN s7_axi_araddr_0
    DIRECTION OUTPUT ;
    USE SIGNAL ;
    ANTENNAGATEAREA 0.434700 ;
    ANTENNADIFFAREA 1.137600 ;
    PORT
      LAYER met2 ;
        RECT 397.530 0.000 397.810 0.280 ;
    END
  END s7_axi_araddr_0
  PIN s7_axi_araddr_1
    DIRECTION OUTPUT ;
    USE SIGNAL ;
    ANTENNAGATEAREA 0.434700 ;
    ANTENNADIFFAREA 1.137600 ;
    PORT
      LAYER met2 ;
        RECT 405.810 519.840 406.090 520.120 ;
    END
  END s7_axi_araddr_1
  PIN s7_axi_araddr_10
    DIRECTION OUTPUT ;
    USE SIGNAL ;
    ANTENNAGATEAREA 0.434700 ;
    ANTENNADIFFAREA 1.137600 ;
    PORT
      LAYER met2 ;
        RECT 199.730 519.840 200.010 520.120 ;
    END
  END s7_axi_araddr_10
  PIN s7_axi_araddr_11
    DIRECTION OUTPUT ;
    USE SIGNAL ;
    ANTENNAGATEAREA 0.434700 ;
    ANTENNADIFFAREA 1.137600 ;
    PORT
      LAYER met2 ;
        RECT 316.570 519.840 316.850 520.120 ;
    END
  END s7_axi_araddr_11
  PIN s7_axi_araddr_12
    DIRECTION OUTPUT ;
    USE SIGNAL ;
    ANTENNAGATEAREA 0.434700 ;
    ANTENNADIFFAREA 1.137600 ;
    PORT
      LAYER met2 ;
        RECT 84.730 519.840 85.010 520.120 ;
    END
  END s7_axi_araddr_12
  PIN s7_axi_araddr_13
    DIRECTION OUTPUT ;
    USE SIGNAL ;
    ANTENNAGATEAREA 0.434700 ;
    ANTENNADIFFAREA 1.137600 ;
    PORT
      LAYER met2 ;
        RECT 467.450 0.000 467.730 0.280 ;
    END
  END s7_axi_araddr_13
  PIN s7_axi_araddr_14
    DIRECTION OUTPUT ;
    USE SIGNAL ;
    ANTENNAGATEAREA 0.434700 ;
    ANTENNADIFFAREA 1.137600 ;
    PORT
      LAYER met2 ;
        RECT 436.170 0.000 436.450 0.280 ;
    END
  END s7_axi_araddr_14
  PIN s7_axi_araddr_15
    DIRECTION OUTPUT ;
    USE SIGNAL ;
    ANTENNAGATEAREA 0.434700 ;
    ANTENNADIFFAREA 1.137600 ;
    PORT
      LAYER met2 ;
        RECT 124.290 519.840 124.570 520.120 ;
    END
  END s7_axi_araddr_15
  PIN s7_axi_araddr_16
    DIRECTION OUTPUT ;
    USE SIGNAL ;
    ANTENNAGATEAREA 0.434700 ;
    ANTENNADIFFAREA 1.137600 ;
    PORT
      LAYER met2 ;
        RECT 169.370 519.840 169.650 520.120 ;
    END
  END s7_axi_araddr_16
  PIN s7_axi_araddr_17
    DIRECTION OUTPUT ;
    USE SIGNAL ;
    ANTENNAGATEAREA 0.434700 ;
    ANTENNADIFFAREA 1.137600 ;
    PORT
      LAYER met2 ;
        RECT 399.370 0.000 399.650 0.280 ;
    END
  END s7_axi_araddr_17
  PIN s7_axi_araddr_18
    DIRECTION OUTPUT ;
    USE SIGNAL ;
    ANTENNAGATEAREA 0.434700 ;
    ANTENNADIFFAREA 1.137600 ;
    PORT
      LAYER met2 ;
        RECT 441.690 0.000 441.970 0.280 ;
    END
  END s7_axi_araddr_18
  PIN s7_axi_araddr_19
    DIRECTION OUTPUT ;
    USE SIGNAL ;
    ANTENNAGATEAREA 0.434700 ;
    ANTENNADIFFAREA 1.137600 ;
    PORT
      LAYER met3 ;
        RECT 0.000 59.880 0.600 60.480 ;
    END
  END s7_axi_araddr_19
  PIN s7_axi_araddr_2
    DIRECTION OUTPUT ;
    USE SIGNAL ;
    ANTENNAGATEAREA 0.434700 ;
    ANTENNADIFFAREA 1.137600 ;
    PORT
      LAYER met3 ;
        RECT 0.000 47.640 0.600 48.240 ;
    END
  END s7_axi_araddr_2
  PIN s7_axi_araddr_20
    DIRECTION OUTPUT ;
    USE SIGNAL ;
    ANTENNAGATEAREA 0.434700 ;
    ANTENNADIFFAREA 1.137600 ;
    PORT
      LAYER met3 ;
        RECT 0.000 390.360 0.600 390.960 ;
    END
  END s7_axi_araddr_20
  PIN s7_axi_araddr_21
    DIRECTION OUTPUT ;
    USE SIGNAL ;
    ANTENNAGATEAREA 0.434700 ;
    ANTENNADIFFAREA 1.137600 ;
    PORT
      LAYER met2 ;
        RECT 188.690 519.840 188.970 520.120 ;
    END
  END s7_axi_araddr_21
  PIN s7_axi_araddr_22
    DIRECTION OUTPUT ;
    USE SIGNAL ;
    ANTENNAGATEAREA 0.434700 ;
    ANTENNADIFFAREA 1.137600 ;
    PORT
      LAYER met2 ;
        RECT 333.130 519.840 333.410 520.120 ;
    END
  END s7_axi_araddr_22
  PIN s7_axi_araddr_23
    DIRECTION OUTPUT ;
    USE SIGNAL ;
    ANTENNAGATEAREA 0.434700 ;
    ANTENNADIFFAREA 1.137600 ;
    PORT
      LAYER met3 ;
        RECT 0.000 99.320 0.600 99.920 ;
    END
  END s7_axi_araddr_23
  PIN s7_axi_araddr_24
    DIRECTION OUTPUT ;
    USE SIGNAL ;
    ANTENNAGATEAREA 0.434700 ;
    ANTENNADIFFAREA 1.137600 ;
    PORT
      LAYER met2 ;
        RECT 158.330 519.840 158.610 520.120 ;
    END
  END s7_axi_araddr_24
  PIN s7_axi_araddr_25
    DIRECTION OUTPUT ;
    USE SIGNAL ;
    ANTENNAGATEAREA 0.434700 ;
    ANTENNADIFFAREA 1.137600 ;
    PORT
      LAYER met2 ;
        RECT 45.170 519.840 45.450 520.120 ;
    END
  END s7_axi_araddr_25
  PIN s7_axi_araddr_26
    DIRECTION OUTPUT ;
    USE SIGNAL ;
    ANTENNAGATEAREA 0.434700 ;
    ANTENNADIFFAREA 1.137600 ;
    PORT
      LAYER met3 ;
        RECT 0.000 137.400 0.600 138.000 ;
    END
  END s7_axi_araddr_26
  PIN s7_axi_araddr_27
    DIRECTION OUTPUT ;
    USE SIGNAL ;
    ANTENNAGATEAREA 0.434700 ;
    ANTENNADIFFAREA 1.137600 ;
    PORT
      LAYER met2 ;
        RECT 397.530 519.840 397.810 520.120 ;
    END
  END s7_axi_araddr_27
  PIN s7_axi_araddr_28
    DIRECTION OUTPUT ;
    USE SIGNAL ;
    ANTENNAGATEAREA 0.434700 ;
    ANTENNADIFFAREA 1.137600 ;
    PORT
      LAYER met3 ;
        RECT 0.000 49.000 0.600 49.600 ;
    END
  END s7_axi_araddr_28
  PIN s7_axi_araddr_29
    DIRECTION OUTPUT ;
    USE SIGNAL ;
    ANTENNAGATEAREA 0.434700 ;
    ANTENNADIFFAREA 1.137600 ;
    PORT
      LAYER met2 ;
        RECT 94.850 519.840 95.130 520.120 ;
    END
  END s7_axi_araddr_29
  PIN s7_axi_araddr_3
    DIRECTION OUTPUT ;
    USE SIGNAL ;
    ANTENNAGATEAREA 0.434700 ;
    ANTENNADIFFAREA 1.137600 ;
    PORT
      LAYER met3 ;
        RECT 0.000 19.080 0.600 19.680 ;
    END
  END s7_axi_araddr_3
  PIN s7_axi_araddr_30
    DIRECTION OUTPUT ;
    USE SIGNAL ;
    ANTENNAGATEAREA 0.434700 ;
    ANTENNADIFFAREA 1.137600 ;
    PORT
      LAYER met2 ;
        RECT 72.770 519.840 73.050 520.120 ;
    END
  END s7_axi_araddr_30
  PIN s7_axi_araddr_31
    DIRECTION OUTPUT ;
    USE SIGNAL ;
    ANTENNAGATEAREA 0.434700 ;
    ANTENNADIFFAREA 1.137600 ;
    PORT
      LAYER met2 ;
        RECT 147.290 519.840 147.570 520.120 ;
    END
  END s7_axi_araddr_31
  PIN s7_axi_araddr_4
    DIRECTION OUTPUT ;
    USE SIGNAL ;
    ANTENNAGATEAREA 0.434700 ;
    ANTENNADIFFAREA 1.137600 ;
    PORT
      LAYER met2 ;
        RECT 319.330 519.840 319.610 520.120 ;
    END
  END s7_axi_araddr_4
  PIN s7_axi_araddr_5
    DIRECTION OUTPUT ;
    USE SIGNAL ;
    ANTENNAGATEAREA 0.434700 ;
    ANTENNADIFFAREA 1.137600 ;
    PORT
      LAYER met2 ;
        RECT 379.130 519.840 379.410 520.120 ;
    END
  END s7_axi_araddr_5
  PIN s7_axi_araddr_6
    DIRECTION OUTPUT ;
    USE SIGNAL ;
    ANTENNAGATEAREA 0.434700 ;
    ANTENNADIFFAREA 1.137600 ;
    PORT
      LAYER met2 ;
        RECT 488.610 0.000 488.890 0.280 ;
    END
  END s7_axi_araddr_6
  PIN s7_axi_araddr_7
    DIRECTION OUTPUT ;
    USE SIGNAL ;
    ANTENNAGATEAREA 0.434700 ;
    ANTENNADIFFAREA 1.137600 ;
    PORT
      LAYER met3 ;
        RECT 0.000 43.560 0.600 44.160 ;
    END
  END s7_axi_araddr_7
  PIN s7_axi_araddr_8
    DIRECTION OUTPUT ;
    USE SIGNAL ;
    ANTENNAGATEAREA 0.434700 ;
    ANTENNADIFFAREA 1.137600 ;
    PORT
      LAYER met2 ;
        RECT 468.370 0.000 468.650 0.280 ;
    END
  END s7_axi_araddr_8
  PIN s7_axi_araddr_9
    DIRECTION OUTPUT ;
    USE SIGNAL ;
    ANTENNAGATEAREA 0.434700 ;
    ANTENNADIFFAREA 1.137600 ;
    PORT
      LAYER met2 ;
        RECT 452.730 519.840 453.010 520.120 ;
    END
  END s7_axi_araddr_9
  PIN s7_axi_arready
    DIRECTION INPUT ;
    USE SIGNAL ;
    ANTENNAGATEAREA 0.647700 ;
    ANTENNADIFFAREA 0.434700 ;
    PORT
      LAYER met2 ;
        RECT 307.370 519.840 307.650 520.120 ;
    END
  END s7_axi_arready
  PIN s7_axi_arvalid
    DIRECTION OUTPUT ;
    USE SIGNAL ;
    ANTENNAGATEAREA 0.434700 ;
    ANTENNADIFFAREA 0.775300 ;
    PORT
      LAYER met3 ;
        RECT 508.800 420.280 509.400 420.880 ;
    END
  END s7_axi_arvalid
  PIN s7_axi_awaddr_0
    DIRECTION OUTPUT ;
    USE SIGNAL ;
    ANTENNAGATEAREA 0.434700 ;
    ANTENNADIFFAREA 1.137600 ;
    PORT
      LAYER met2 ;
        RECT 435.250 0.000 435.530 0.280 ;
    END
  END s7_axi_awaddr_0
  PIN s7_axi_awaddr_1
    DIRECTION OUTPUT ;
    USE SIGNAL ;
    ANTENNAGATEAREA 0.434700 ;
    ANTENNADIFFAREA 1.137600 ;
    PORT
      LAYER met2 ;
        RECT 442.610 0.000 442.890 0.280 ;
    END
  END s7_axi_awaddr_1
  PIN s7_axi_awaddr_10
    DIRECTION OUTPUT ;
    USE SIGNAL ;
    ANTENNAGATEAREA 0.434700 ;
    ANTENNADIFFAREA 1.137600 ;
    PORT
      LAYER met2 ;
        RECT 469.290 0.000 469.570 0.280 ;
    END
  END s7_axi_awaddr_10
  PIN s7_axi_awaddr_11
    DIRECTION OUTPUT ;
    USE SIGNAL ;
    ANTENNAGATEAREA 0.434700 ;
    ANTENNADIFFAREA 1.137600 ;
    PORT
      LAYER met2 ;
        RECT 489.530 0.000 489.810 0.280 ;
    END
  END s7_axi_awaddr_11
  PIN s7_axi_awaddr_12
    DIRECTION OUTPUT ;
    USE SIGNAL ;
    ANTENNAGATEAREA 0.434700 ;
    ANTENNADIFFAREA 1.137600 ;
    PORT
      LAYER met2 ;
        RECT 290.810 519.840 291.090 520.120 ;
    END
  END s7_axi_awaddr_12
  PIN s7_axi_awaddr_13
    DIRECTION OUTPUT ;
    USE SIGNAL ;
    ANTENNAGATEAREA 0.434700 ;
    ANTENNADIFFAREA 1.137600 ;
    PORT
      LAYER met3 ;
        RECT 508.800 125.160 509.400 125.760 ;
    END
  END s7_axi_awaddr_13
  PIN s7_axi_awaddr_14
    DIRECTION OUTPUT ;
    USE SIGNAL ;
    ANTENNAGATEAREA 0.434700 ;
    ANTENNADIFFAREA 1.137600 ;
    PORT
      LAYER met2 ;
        RECT 428.810 0.000 429.090 0.280 ;
    END
  END s7_axi_awaddr_14
  PIN s7_axi_awaddr_15
    DIRECTION OUTPUT ;
    USE SIGNAL ;
    ANTENNAGATEAREA 0.434700 ;
    ANTENNADIFFAREA 1.137600 ;
    PORT
      LAYER met2 ;
        RECT 104.970 519.840 105.250 520.120 ;
    END
  END s7_axi_awaddr_15
  PIN s7_axi_awaddr_16
    DIRECTION OUTPUT ;
    USE SIGNAL ;
    ANTENNAGATEAREA 0.434700 ;
    ANTENNADIFFAREA 1.137600 ;
    PORT
      LAYER met2 ;
        RECT 470.210 0.000 470.490 0.280 ;
    END
  END s7_axi_awaddr_16
  PIN s7_axi_awaddr_17
    DIRECTION OUTPUT ;
    USE SIGNAL ;
    ANTENNAGATEAREA 0.434700 ;
    ANTENNADIFFAREA 1.137600 ;
    PORT
      LAYER met2 ;
        RECT 358.890 519.840 359.170 520.120 ;
    END
  END s7_axi_awaddr_17
  PIN s7_axi_awaddr_18
    DIRECTION OUTPUT ;
    USE SIGNAL ;
    ANTENNAGATEAREA 0.434700 ;
    ANTENNADIFFAREA 1.137600 ;
    PORT
      LAYER met2 ;
        RECT 338.650 519.840 338.930 520.120 ;
    END
  END s7_axi_awaddr_18
  PIN s7_axi_awaddr_19
    DIRECTION OUTPUT ;
    USE SIGNAL ;
    ANTENNAGATEAREA 0.434700 ;
    ANTENNADIFFAREA 1.137600 ;
    PORT
      LAYER met3 ;
        RECT 508.800 443.400 509.400 444.000 ;
    END
  END s7_axi_awaddr_19
  PIN s7_axi_awaddr_2
    DIRECTION OUTPUT ;
    USE SIGNAL ;
    ANTENNAGATEAREA 0.434700 ;
    ANTENNADIFFAREA 1.137600 ;
    PORT
      LAYER met3 ;
        RECT 0.000 114.280 0.600 114.880 ;
    END
  END s7_axi_awaddr_2
  PIN s7_axi_awaddr_20
    DIRECTION OUTPUT ;
    USE SIGNAL ;
    ANTENNAGATEAREA 0.434700 ;
    ANTENNADIFFAREA 1.137600 ;
    PORT
      LAYER met3 ;
        RECT 0.000 108.840 0.600 109.440 ;
    END
  END s7_axi_awaddr_20
  PIN s7_axi_awaddr_21
    DIRECTION OUTPUT ;
    USE SIGNAL ;
    ANTENNAGATEAREA 0.434700 ;
    ANTENNADIFFAREA 1.137600 ;
    PORT
      LAYER met3 ;
        RECT 0.000 408.040 0.600 408.640 ;
    END
  END s7_axi_awaddr_21
  PIN s7_axi_awaddr_22
    DIRECTION OUTPUT ;
    USE SIGNAL ;
    ANTENNAGATEAREA 0.434700 ;
    ANTENNADIFFAREA 1.137600 ;
    PORT
      LAYER met2 ;
        RECT 443.530 0.000 443.810 0.280 ;
    END
  END s7_axi_awaddr_22
  PIN s7_axi_awaddr_23
    DIRECTION OUTPUT ;
    USE SIGNAL ;
    ANTENNAGATEAREA 0.434700 ;
    ANTENNADIFFAREA 1.137600 ;
    PORT
      LAYER met2 ;
        RECT 346.930 519.840 347.210 520.120 ;
    END
  END s7_axi_awaddr_23
  PIN s7_axi_awaddr_24
    DIRECTION OUTPUT ;
    USE SIGNAL ;
    ANTENNAGATEAREA 0.434700 ;
    ANTENNADIFFAREA 1.137600 ;
    PORT
      LAYER met2 ;
        RECT 176.730 519.840 177.010 520.120 ;
    END
  END s7_axi_awaddr_24
  PIN s7_axi_awaddr_25
    DIRECTION OUTPUT ;
    USE SIGNAL ;
    ANTENNAGATEAREA 0.434700 ;
    ANTENNADIFFAREA 1.137600 ;
    PORT
      LAYER met3 ;
        RECT 0.000 164.600 0.600 165.200 ;
    END
  END s7_axi_awaddr_25
  PIN s7_axi_awaddr_26
    DIRECTION OUTPUT ;
    USE SIGNAL ;
    ANTENNAGATEAREA 0.434700 ;
    ANTENNADIFFAREA 1.137600 ;
    PORT
      LAYER met2 ;
        RECT 198.810 519.840 199.090 520.120 ;
    END
  END s7_axi_awaddr_26
  PIN s7_axi_awaddr_27
    DIRECTION OUTPUT ;
    USE SIGNAL ;
    ANTENNAGATEAREA 0.434700 ;
    ANTENNADIFFAREA 1.137600 ;
    PORT
      LAYER met2 ;
        RECT 408.570 0.000 408.850 0.280 ;
    END
  END s7_axi_awaddr_27
  PIN s7_axi_awaddr_28
    DIRECTION OUTPUT ;
    USE SIGNAL ;
    ANTENNAGATEAREA 0.434700 ;
    ANTENNADIFFAREA 1.137600 ;
    PORT
      LAYER met2 ;
        RECT 471.130 0.000 471.410 0.280 ;
    END
  END s7_axi_awaddr_28
  PIN s7_axi_awaddr_29
    DIRECTION OUTPUT ;
    USE SIGNAL ;
    ANTENNAGATEAREA 0.434700 ;
    ANTENNADIFFAREA 1.137600 ;
    PORT
      LAYER met2 ;
        RECT 389.250 519.840 389.530 520.120 ;
    END
  END s7_axi_awaddr_29
  PIN s7_axi_awaddr_3
    DIRECTION OUTPUT ;
    USE SIGNAL ;
    ANTENNAGATEAREA 0.434700 ;
    ANTENNADIFFAREA 1.137600 ;
    PORT
      LAYER met3 ;
        RECT 0.000 66.680 0.600 67.280 ;
    END
  END s7_axi_awaddr_3
  PIN s7_axi_awaddr_30
    DIRECTION OUTPUT ;
    USE SIGNAL ;
    ANTENNAGATEAREA 0.434700 ;
    ANTENNADIFFAREA 1.137600 ;
    PORT
      LAYER met2 ;
        RECT 393.850 0.000 394.130 0.280 ;
    END
  END s7_axi_awaddr_30
  PIN s7_axi_awaddr_31
    DIRECTION OUTPUT ;
    USE SIGNAL ;
    ANTENNAGATEAREA 0.434700 ;
    ANTENNADIFFAREA 1.137600 ;
    PORT
      LAYER met2 ;
        RECT 267.810 519.840 268.090 520.120 ;
    END
  END s7_axi_awaddr_31
  PIN s7_axi_awaddr_4
    DIRECTION OUTPUT ;
    USE SIGNAL ;
    ANTENNAGATEAREA 0.434700 ;
    ANTENNADIFFAREA 1.137600 ;
    PORT
      LAYER met2 ;
        RECT 345.090 519.840 345.370 520.120 ;
    END
  END s7_axi_awaddr_4
  PIN s7_axi_awaddr_5
    DIRECTION OUTPUT ;
    USE SIGNAL ;
    ANTENNAGATEAREA 0.434700 ;
    ANTENNADIFFAREA 1.137600 ;
    PORT
      LAYER met2 ;
        RECT 426.970 0.000 427.250 0.280 ;
    END
  END s7_axi_awaddr_5
  PIN s7_axi_awaddr_6
    DIRECTION OUTPUT ;
    USE SIGNAL ;
    ANTENNAGATEAREA 0.434700 ;
    ANTENNADIFFAREA 1.137600 ;
    PORT
      LAYER met2 ;
        RECT 386.490 0.000 386.770 0.280 ;
    END
  END s7_axi_awaddr_6
  PIN s7_axi_awaddr_7
    DIRECTION OUTPUT ;
    USE SIGNAL ;
    ANTENNAGATEAREA 0.434700 ;
    ANTENNADIFFAREA 1.137600 ;
    PORT
      LAYER met3 ;
        RECT 0.000 42.200 0.600 42.800 ;
    END
  END s7_axi_awaddr_7
  PIN s7_axi_awaddr_8
    DIRECTION OUTPUT ;
    USE SIGNAL ;
    ANTENNAGATEAREA 0.434700 ;
    ANTENNADIFFAREA 1.137600 ;
    PORT
      LAYER met2 ;
        RECT 490.450 0.000 490.730 0.280 ;
    END
  END s7_axi_awaddr_8
  PIN s7_axi_awaddr_9
    DIRECTION OUTPUT ;
    USE SIGNAL ;
    ANTENNAGATEAREA 0.434700 ;
    ANTENNADIFFAREA 1.137600 ;
    PORT
      LAYER met3 ;
        RECT 508.800 455.640 509.400 456.240 ;
    END
  END s7_axi_awaddr_9
  PIN s7_axi_awready
    DIRECTION INPUT ;
    USE SIGNAL ;
    ANTENNAGATEAREA 0.647700 ;
    ANTENNADIFFAREA 0.434700 ;
    PORT
      LAYER met3 ;
        RECT 0.000 325.080 0.600 325.680 ;
    END
  END s7_axi_awready
  PIN s7_axi_awvalid
    DIRECTION OUTPUT ;
    USE SIGNAL ;
    ANTENNAGATEAREA 0.434700 ;
    ANTENNADIFFAREA 0.775300 ;
    PORT
      LAYER met3 ;
        RECT 508.800 451.560 509.400 452.160 ;
    END
  END s7_axi_awvalid
  PIN s7_axi_bready
    DIRECTION OUTPUT ;
    USE SIGNAL ;
    ANTENNAGATEAREA 0.434700 ;
    ANTENNADIFFAREA 0.775300 ;
    PORT
      LAYER met3 ;
        RECT 508.800 423.000 509.400 423.600 ;
    END
  END s7_axi_bready
  PIN s7_axi_bresp_0
    DIRECTION INPUT ;
    USE SIGNAL ;
    ANTENNAGATEAREA 0.647700 ;
    ANTENNADIFFAREA 0.434700 ;
    PORT
      LAYER met3 ;
        RECT 0.000 316.920 0.600 317.520 ;
    END
  END s7_axi_bresp_0
  PIN s7_axi_bresp_1
    DIRECTION INPUT ;
    USE SIGNAL ;
    ANTENNAGATEAREA 0.647700 ;
    ANTENNADIFFAREA 0.434700 ;
    PORT
      LAYER met3 ;
        RECT 0.000 315.560 0.600 316.160 ;
    END
  END s7_axi_bresp_1
  PIN s7_axi_bvalid
    DIRECTION INPUT ;
    USE SIGNAL ;
    ANTENNAGATEAREA 0.647700 ;
    ANTENNADIFFAREA 0.434700 ;
    PORT
      LAYER met3 ;
        RECT 0.000 341.400 0.600 342.000 ;
    END
  END s7_axi_bvalid
  PIN s7_axi_rdata_0
    DIRECTION INPUT ;
    USE SIGNAL ;
    ANTENNAGATEAREA 0.647700 ;
    ANTENNADIFFAREA 0.434700 ;
    PORT
      LAYER met3 ;
        RECT 508.800 187.720 509.400 188.320 ;
    END
  END s7_axi_rdata_0
  PIN s7_axi_rdata_1
    DIRECTION INPUT ;
    USE SIGNAL ;
    ANTENNAGATEAREA 0.647700 ;
    ANTENNADIFFAREA 0.434700 ;
    PORT
      LAYER met2 ;
        RECT 301.850 519.840 302.130 520.120 ;
    END
  END s7_axi_rdata_1
  PIN s7_axi_rdata_10
    DIRECTION INPUT ;
    USE SIGNAL ;
    ANTENNAGATEAREA 0.647700 ;
    ANTENNADIFFAREA 0.434700 ;
    PORT
      LAYER met3 ;
        RECT 508.800 280.200 509.400 280.800 ;
    END
  END s7_axi_rdata_10
  PIN s7_axi_rdata_11
    DIRECTION INPUT ;
    USE SIGNAL ;
    ANTENNAGATEAREA 0.647700 ;
    ANTENNADIFFAREA 0.434700 ;
    PORT
      LAYER met3 ;
        RECT 508.800 167.320 509.400 167.920 ;
    END
  END s7_axi_rdata_11
  PIN s7_axi_rdata_12
    DIRECTION INPUT ;
    USE SIGNAL ;
    ANTENNAGATEAREA 0.647700 ;
    ANTENNADIFFAREA 0.434700 ;
    PORT
      LAYER met3 ;
        RECT 508.800 171.400 509.400 172.000 ;
    END
  END s7_axi_rdata_12
  PIN s7_axi_rdata_13
    DIRECTION INPUT ;
    USE SIGNAL ;
    ANTENNAGATEAREA 0.647700 ;
    ANTENNADIFFAREA 0.434700 ;
    PORT
      LAYER met3 ;
        RECT 508.800 191.800 509.400 192.400 ;
    END
  END s7_axi_rdata_13
  PIN s7_axi_rdata_14
    DIRECTION INPUT ;
    USE SIGNAL ;
    ANTENNAGATEAREA 0.647700 ;
    ANTENNADIFFAREA 0.434700 ;
    PORT
      LAYER met3 ;
        RECT 508.800 296.520 509.400 297.120 ;
    END
  END s7_axi_rdata_14
  PIN s7_axi_rdata_15
    DIRECTION INPUT ;
    USE SIGNAL ;
    ANTENNAGATEAREA 0.647700 ;
    ANTENNADIFFAREA 0.434700 ;
    PORT
      LAYER met3 ;
        RECT 508.800 73.480 509.400 74.080 ;
    END
  END s7_axi_rdata_15
  PIN s7_axi_rdata_16
    DIRECTION INPUT ;
    USE SIGNAL ;
    ANTENNAGATEAREA 0.647700 ;
    ANTENNADIFFAREA 0.434700 ;
    PORT
      LAYER met3 ;
        RECT 508.800 163.240 509.400 163.840 ;
    END
  END s7_axi_rdata_16
  PIN s7_axi_rdata_17
    DIRECTION INPUT ;
    USE SIGNAL ;
    ANTENNAGATEAREA 0.647700 ;
    ANTENNADIFFAREA 0.434700 ;
    PORT
      LAYER met3 ;
        RECT 508.800 306.040 509.400 306.640 ;
    END
  END s7_axi_rdata_17
  PIN s7_axi_rdata_18
    DIRECTION INPUT ;
    USE SIGNAL ;
    ANTENNAGATEAREA 0.647700 ;
    ANTENNADIFFAREA 0.434700 ;
    PORT
      LAYER met3 ;
        RECT 508.800 194.520 509.400 195.120 ;
    END
  END s7_axi_rdata_18
  PIN s7_axi_rdata_19
    DIRECTION INPUT ;
    USE SIGNAL ;
    ANTENNAGATEAREA 0.647700 ;
    ANTENNADIFFAREA 0.434700 ;
    PORT
      LAYER met3 ;
        RECT 508.800 284.280 509.400 284.880 ;
    END
  END s7_axi_rdata_19
  PIN s7_axi_rdata_2
    DIRECTION INPUT ;
    USE SIGNAL ;
    ANTENNAGATEAREA 0.647700 ;
    ANTENNADIFFAREA 0.434700 ;
    PORT
      LAYER met3 ;
        RECT 508.800 68.040 509.400 68.640 ;
    END
  END s7_axi_rdata_2
  PIN s7_axi_rdata_20
    DIRECTION INPUT ;
    USE SIGNAL ;
    ANTENNAGATEAREA 0.647700 ;
    ANTENNADIFFAREA 0.434700 ;
    PORT
      LAYER met3 ;
        RECT 508.800 247.560 509.400 248.160 ;
    END
  END s7_axi_rdata_20
  PIN s7_axi_rdata_21
    DIRECTION INPUT ;
    USE SIGNAL ;
    ANTENNAGATEAREA 0.647700 ;
    ANTENNADIFFAREA 0.434700 ;
    PORT
      LAYER met3 ;
        RECT 508.800 344.120 509.400 344.720 ;
    END
  END s7_axi_rdata_21
  PIN s7_axi_rdata_22
    DIRECTION INPUT ;
    USE SIGNAL ;
    ANTENNAGATEAREA 0.647700 ;
    ANTENNADIFFAREA 0.434700 ;
    PORT
      LAYER met3 ;
        RECT 508.800 239.400 509.400 240.000 ;
    END
  END s7_axi_rdata_22
  PIN s7_axi_rdata_23
    DIRECTION INPUT ;
    USE SIGNAL ;
    ANTENNAGATEAREA 0.647700 ;
    ANTENNADIFFAREA 0.434700 ;
    PORT
      LAYER met3 ;
        RECT 508.800 210.840 509.400 211.440 ;
    END
  END s7_axi_rdata_23
  PIN s7_axi_rdata_24
    DIRECTION INPUT ;
    USE SIGNAL ;
    ANTENNAGATEAREA 0.647700 ;
    ANTENNADIFFAREA 0.434700 ;
    PORT
      LAYER met3 ;
        RECT 508.800 269.320 509.400 269.920 ;
    END
  END s7_axi_rdata_24
  PIN s7_axi_rdata_25
    DIRECTION INPUT ;
    USE SIGNAL ;
    ANTENNAGATEAREA 0.647700 ;
    ANTENNADIFFAREA 0.434700 ;
    PORT
      LAYER met3 ;
        RECT 508.800 340.040 509.400 340.640 ;
    END
  END s7_axi_rdata_25
  PIN s7_axi_rdata_26
    DIRECTION INPUT ;
    USE SIGNAL ;
    ANTENNAGATEAREA 0.647700 ;
    ANTENNADIFFAREA 0.434700 ;
    PORT
      LAYER met3 ;
        RECT 508.800 180.920 509.400 181.520 ;
    END
  END s7_axi_rdata_26
  PIN s7_axi_rdata_27
    DIRECTION INPUT ;
    USE SIGNAL ;
    ANTENNAGATEAREA 0.647700 ;
    ANTENNADIFFAREA 0.434700 ;
    PORT
      LAYER met3 ;
        RECT 508.800 214.920 509.400 215.520 ;
    END
  END s7_axi_rdata_27
  PIN s7_axi_rdata_28
    DIRECTION INPUT ;
    USE SIGNAL ;
    ANTENNAGATEAREA 0.647700 ;
    ANTENNADIFFAREA 0.434700 ;
    PORT
      LAYER met3 ;
        RECT 508.800 92.520 509.400 93.120 ;
    END
  END s7_axi_rdata_28
  PIN s7_axi_rdata_29
    DIRECTION INPUT ;
    USE SIGNAL ;
    ANTENNAGATEAREA 0.647700 ;
    ANTENNADIFFAREA 0.434700 ;
    PORT
      LAYER met3 ;
        RECT 508.800 274.760 509.400 275.360 ;
    END
  END s7_axi_rdata_29
  PIN s7_axi_rdata_3
    DIRECTION INPUT ;
    USE SIGNAL ;
    ANTENNAGATEAREA 0.647700 ;
    ANTENNADIFFAREA 0.434700 ;
    PORT
      LAYER met3 ;
        RECT 508.800 356.360 509.400 356.960 ;
    END
  END s7_axi_rdata_3
  PIN s7_axi_rdata_30
    DIRECTION INPUT ;
    USE SIGNAL ;
    ANTENNAGATEAREA 0.647700 ;
    ANTENNADIFFAREA 0.434700 ;
    PORT
      LAYER met3 ;
        RECT 508.800 165.960 509.400 166.560 ;
    END
  END s7_axi_rdata_30
  PIN s7_axi_rdata_31
    DIRECTION INPUT ;
    USE SIGNAL ;
    ANTENNAGATEAREA 0.647700 ;
    ANTENNADIFFAREA 0.434700 ;
    PORT
      LAYER met3 ;
        RECT 508.800 335.960 509.400 336.560 ;
    END
  END s7_axi_rdata_31
  PIN s7_axi_rdata_4
    DIRECTION INPUT ;
    USE SIGNAL ;
    ANTENNAGATEAREA 0.647700 ;
    ANTENNADIFFAREA 0.434700 ;
    PORT
      LAYER met3 ;
        RECT 508.800 288.360 509.400 288.960 ;
    END
  END s7_axi_rdata_4
  PIN s7_axi_rdata_5
    DIRECTION INPUT ;
    USE SIGNAL ;
    ANTENNAGATEAREA 0.647700 ;
    ANTENNADIFFAREA 0.434700 ;
    PORT
      LAYER met3 ;
        RECT 508.800 253.000 509.400 253.600 ;
    END
  END s7_axi_rdata_5
  PIN s7_axi_rdata_6
    DIRECTION INPUT ;
    USE SIGNAL ;
    ANTENNAGATEAREA 0.647700 ;
    ANTENNADIFFAREA 0.434700 ;
    PORT
      LAYER met3 ;
        RECT 508.800 346.840 509.400 347.440 ;
    END
  END s7_axi_rdata_6
  PIN s7_axi_rdata_7
    DIRECTION INPUT ;
    USE SIGNAL ;
    ANTENNAGATEAREA 0.647700 ;
    ANTENNADIFFAREA 0.434700 ;
    PORT
      LAYER met3 ;
        RECT 508.800 481.480 509.400 482.080 ;
    END
  END s7_axi_rdata_7
  PIN s7_axi_rdata_8
    DIRECTION INPUT ;
    USE SIGNAL ;
    ANTENNAGATEAREA 0.647700 ;
    ANTENNADIFFAREA 0.434700 ;
    PORT
      LAYER met3 ;
        RECT 508.800 319.640 509.400 320.240 ;
    END
  END s7_axi_rdata_8
  PIN s7_axi_rdata_9
    DIRECTION INPUT ;
    USE SIGNAL ;
    ANTENNAGATEAREA 0.647700 ;
    ANTENNADIFFAREA 0.434700 ;
    PORT
      LAYER met3 ;
        RECT 508.800 55.800 509.400 56.400 ;
    END
  END s7_axi_rdata_9
  PIN s7_axi_rready
    DIRECTION OUTPUT ;
    USE SIGNAL ;
    ANTENNAGATEAREA 0.434700 ;
    ANTENNADIFFAREA 0.775300 ;
    PORT
      LAYER met3 ;
        RECT 508.800 463.800 509.400 464.400 ;
    END
  END s7_axi_rready
  PIN s7_axi_rresp_0
    DIRECTION INPUT ;
    USE SIGNAL ;
    ANTENNAGATEAREA 0.647700 ;
    ANTENNADIFFAREA 0.434700 ;
    PORT
      LAYER met3 ;
        RECT 508.800 508.680 509.400 509.280 ;
    END
  END s7_axi_rresp_0
  PIN s7_axi_rresp_1
    DIRECTION INPUT ;
    USE SIGNAL ;
    ANTENNAGATEAREA 0.647700 ;
    ANTENNADIFFAREA 0.434700 ;
    PORT
      LAYER met3 ;
        RECT 508.800 95.240 509.400 95.840 ;
    END
  END s7_axi_rresp_1
  PIN s7_axi_rvalid
    DIRECTION INPUT ;
    USE SIGNAL ;
    ANTENNAGATEAREA 0.647700 ;
    ANTENNADIFFAREA 0.434700 ;
    PORT
      LAYER met3 ;
        RECT 508.800 478.760 509.400 479.360 ;
    END
  END s7_axi_rvalid
  PIN s7_axi_wdata_0
    DIRECTION OUTPUT ;
    USE SIGNAL ;
    ANTENNAGATEAREA 0.434700 ;
    ANTENNADIFFAREA 1.137600 ;
    PORT
      LAYER met3 ;
        RECT 0.000 103.400 0.600 104.000 ;
    END
  END s7_axi_wdata_0
  PIN s7_axi_wdata_1
    DIRECTION OUTPUT ;
    USE SIGNAL ;
    ANTENNAGATEAREA 0.434700 ;
    ANTENNADIFFAREA 1.137600 ;
    PORT
      LAYER met2 ;
        RECT 472.050 0.000 472.330 0.280 ;
    END
  END s7_axi_wdata_1
  PIN s7_axi_wdata_10
    DIRECTION OUTPUT ;
    USE SIGNAL ;
    ANTENNAGATEAREA 0.434700 ;
    ANTENNADIFFAREA 1.137600 ;
    PORT
      LAYER met2 ;
        RECT 194.210 519.840 194.490 520.120 ;
    END
  END s7_axi_wdata_10
  PIN s7_axi_wdata_11
    DIRECTION OUTPUT ;
    USE SIGNAL ;
    ANTENNAGATEAREA 0.434700 ;
    ANTENNADIFFAREA 1.137600 ;
    PORT
      LAYER met2 ;
        RECT 129.810 519.840 130.090 520.120 ;
    END
  END s7_axi_wdata_11
  PIN s7_axi_wdata_12
    DIRECTION OUTPUT ;
    USE SIGNAL ;
    ANTENNAGATEAREA 0.434700 ;
    ANTENNADIFFAREA 1.137600 ;
    PORT
      LAYER met3 ;
        RECT 0.000 87.080 0.600 87.680 ;
    END
  END s7_axi_wdata_12
  PIN s7_axi_wdata_13
    DIRECTION OUTPUT ;
    USE SIGNAL ;
    ANTENNAGATEAREA 0.434700 ;
    ANTENNADIFFAREA 1.137600 ;
    PORT
      LAYER met2 ;
        RECT 231.930 519.840 232.210 520.120 ;
    END
  END s7_axi_wdata_13
  PIN s7_axi_wdata_14
    DIRECTION OUTPUT ;
    USE SIGNAL ;
    ANTENNAGATEAREA 0.434700 ;
    ANTENNADIFFAREA 1.137600 ;
    PORT
      LAYER met2 ;
        RECT 364.410 519.840 364.690 520.120 ;
    END
  END s7_axi_wdata_14
  PIN s7_axi_wdata_15
    DIRECTION OUTPUT ;
    USE SIGNAL ;
    ANTENNAGATEAREA 0.434700 ;
    ANTENNADIFFAREA 1.137600 ;
    PORT
      LAYER met2 ;
        RECT 111.410 519.840 111.690 520.120 ;
    END
  END s7_axi_wdata_15
  PIN s7_axi_wdata_16
    DIRECTION OUTPUT ;
    USE SIGNAL ;
    ANTENNAGATEAREA 0.434700 ;
    ANTENNADIFFAREA 1.137600 ;
    PORT
      LAYER met3 ;
        RECT 0.000 376.760 0.600 377.360 ;
    END
  END s7_axi_wdata_16
  PIN s7_axi_wdata_17
    DIRECTION OUTPUT ;
    USE SIGNAL ;
    ANTENNAGATEAREA 0.434700 ;
    ANTENNADIFFAREA 1.137600 ;
    PORT
      LAYER met2 ;
        RECT 166.610 519.840 166.890 520.120 ;
    END
  END s7_axi_wdata_17
  PIN s7_axi_wdata_18
    DIRECTION OUTPUT ;
    USE SIGNAL ;
    ANTENNAGATEAREA 0.434700 ;
    ANTENNADIFFAREA 1.137600 ;
    PORT
      LAYER met2 ;
        RECT 434.330 0.000 434.610 0.280 ;
    END
  END s7_axi_wdata_18
  PIN s7_axi_wdata_19
    DIRECTION OUTPUT ;
    USE SIGNAL ;
    ANTENNAGATEAREA 0.434700 ;
    ANTENNADIFFAREA 1.137600 ;
    PORT
      LAYER met2 ;
        RECT 237.450 519.840 237.730 520.120 ;
    END
  END s7_axi_wdata_19
  PIN s7_axi_wdata_2
    DIRECTION OUTPUT ;
    USE SIGNAL ;
    ANTENNAGATEAREA 0.434700 ;
    ANTENNADIFFAREA 1.137600 ;
    PORT
      LAYER met2 ;
        RECT 209.850 519.840 210.130 520.120 ;
    END
  END s7_axi_wdata_2
  PIN s7_axi_wdata_20
    DIRECTION OUTPUT ;
    USE SIGNAL ;
    ANTENNAGATEAREA 0.434700 ;
    ANTENNADIFFAREA 1.137600 ;
    PORT
      LAYER met3 ;
        RECT 508.800 108.840 509.400 109.440 ;
    END
  END s7_axi_wdata_20
  PIN s7_axi_wdata_21
    DIRECTION OUTPUT ;
    USE SIGNAL ;
    ANTENNAGATEAREA 0.434700 ;
    ANTENNADIFFAREA 1.137600 ;
    PORT
      LAYER met2 ;
        RECT 93.930 519.840 94.210 520.120 ;
    END
  END s7_axi_wdata_21
  PIN s7_axi_wdata_22
    DIRECTION OUTPUT ;
    USE SIGNAL ;
    ANTENNAGATEAREA 0.434700 ;
    ANTENNADIFFAREA 1.137600 ;
    PORT
      LAYER met2 ;
        RECT 426.050 519.840 426.330 520.120 ;
    END
  END s7_axi_wdata_22
  PIN s7_axi_wdata_23
    DIRECTION OUTPUT ;
    USE SIGNAL ;
    ANTENNAGATEAREA 0.434700 ;
    ANTENNADIFFAREA 1.137600 ;
    PORT
      LAYER met3 ;
        RECT 0.000 397.160 0.600 397.760 ;
    END
  END s7_axi_wdata_23
  PIN s7_axi_wdata_24
    DIRECTION OUTPUT ;
    USE SIGNAL ;
    ANTENNAGATEAREA 0.434700 ;
    ANTENNADIFFAREA 1.137600 ;
    PORT
      LAYER met3 ;
        RECT 0.000 123.800 0.600 124.400 ;
    END
  END s7_axi_wdata_24
  PIN s7_axi_wdata_25
    DIRECTION OUTPUT ;
    USE SIGNAL ;
    ANTENNAGATEAREA 0.434700 ;
    ANTENNADIFFAREA 1.137600 ;
    PORT
      LAYER met2 ;
        RECT 56.210 519.840 56.490 520.120 ;
    END
  END s7_axi_wdata_25
  PIN s7_axi_wdata_26
    DIRECTION OUTPUT ;
    USE SIGNAL ;
    ANTENNAGATEAREA 0.434700 ;
    ANTENNADIFFAREA 1.137600 ;
    PORT
      LAYER met3 ;
        RECT 0.000 23.160 0.600 23.760 ;
    END
  END s7_axi_wdata_26
  PIN s7_axi_wdata_27
    DIRECTION OUTPUT ;
    USE SIGNAL ;
    ANTENNAGATEAREA 0.434700 ;
    ANTENNADIFFAREA 1.137600 ;
    PORT
      LAYER met2 ;
        RECT 138.090 519.840 138.370 520.120 ;
    END
  END s7_axi_wdata_27
  PIN s7_axi_wdata_28
    DIRECTION OUTPUT ;
    USE SIGNAL ;
    ANTENNAGATEAREA 0.434700 ;
    ANTENNADIFFAREA 1.137600 ;
    PORT
      LAYER met2 ;
        RECT 220.890 519.840 221.170 520.120 ;
    END
  END s7_axi_wdata_28
  PIN s7_axi_wdata_29
    DIRECTION OUTPUT ;
    USE SIGNAL ;
    ANTENNAGATEAREA 0.434700 ;
    ANTENNADIFFAREA 1.137600 ;
    PORT
      LAYER met2 ;
        RECT 449.970 0.000 450.250 0.280 ;
    END
  END s7_axi_wdata_29
  PIN s7_axi_wdata_3
    DIRECTION OUTPUT ;
    USE SIGNAL ;
    ANTENNAGATEAREA 0.434700 ;
    ANTENNADIFFAREA 1.137600 ;
    PORT
      LAYER met2 ;
        RECT 127.050 519.840 127.330 520.120 ;
    END
  END s7_axi_wdata_3
  PIN s7_axi_wdata_30
    DIRECTION OUTPUT ;
    USE SIGNAL ;
    ANTENNAGATEAREA 0.434700 ;
    ANTENNADIFFAREA 1.137600 ;
    PORT
      LAYER met2 ;
        RECT 396.610 0.000 396.890 0.280 ;
    END
  END s7_axi_wdata_30
  PIN s7_axi_wdata_31
    DIRECTION OUTPUT ;
    USE SIGNAL ;
    ANTENNAGATEAREA 0.434700 ;
    ANTENNADIFFAREA 1.137600 ;
    PORT
      LAYER met2 ;
        RECT 274.250 519.840 274.530 520.120 ;
    END
  END s7_axi_wdata_31
  PIN s7_axi_wdata_4
    DIRECTION OUTPUT ;
    USE SIGNAL ;
    ANTENNAGATEAREA 0.434700 ;
    ANTENNADIFFAREA 1.137600 ;
    PORT
      LAYER met3 ;
        RECT 0.000 61.240 0.600 61.840 ;
    END
  END s7_axi_wdata_4
  PIN s7_axi_wdata_5
    DIRECTION OUTPUT ;
    USE SIGNAL ;
    ANTENNAGATEAREA 0.434700 ;
    ANTENNADIFFAREA 1.137600 ;
    PORT
      LAYER met3 ;
        RECT 0.000 371.320 0.600 371.920 ;
    END
  END s7_axi_wdata_5
  PIN s7_axi_wdata_6
    DIRECTION OUTPUT ;
    USE SIGNAL ;
    ANTENNAGATEAREA 0.434700 ;
    ANTENNADIFFAREA 1.137600 ;
    PORT
      LAYER met2 ;
        RECT 472.970 0.000 473.250 0.280 ;
    END
  END s7_axi_wdata_6
  PIN s7_axi_wdata_7
    DIRECTION OUTPUT ;
    USE SIGNAL ;
    ANTENNAGATEAREA 0.434700 ;
    ANTENNADIFFAREA 1.137600 ;
    PORT
      LAYER met2 ;
        RECT 371.770 519.840 372.050 520.120 ;
    END
  END s7_axi_wdata_7
  PIN s7_axi_wdata_8
    DIRECTION OUTPUT ;
    USE SIGNAL ;
    ANTENNAGATEAREA 0.434700 ;
    ANTENNADIFFAREA 1.137600 ;
    PORT
      LAYER met2 ;
        RECT 416.850 0.000 417.130 0.280 ;
    END
  END s7_axi_wdata_8
  PIN s7_axi_wdata_9
    DIRECTION OUTPUT ;
    USE SIGNAL ;
    ANTENNAGATEAREA 0.434700 ;
    ANTENNADIFFAREA 1.137600 ;
    PORT
      LAYER met3 ;
        RECT 508.800 406.680 509.400 407.280 ;
    END
  END s7_axi_wdata_9
  PIN s7_axi_wready
    DIRECTION INPUT ;
    USE SIGNAL ;
    ANTENNAGATEAREA 0.647700 ;
    ANTENNADIFFAREA 0.434700 ;
    PORT
      LAYER met3 ;
        RECT 0.000 340.040 0.600 340.640 ;
    END
  END s7_axi_wready
  PIN s7_axi_wstrb_0
    DIRECTION OUTPUT ;
    USE SIGNAL ;
    ANTENNAGATEAREA 0.434700 ;
    ANTENNADIFFAREA 1.137600 ;
    PORT
      LAYER met3 ;
        RECT 508.800 397.160 509.400 397.760 ;
    END
  END s7_axi_wstrb_0
  PIN s7_axi_wstrb_1
    DIRECTION OUTPUT ;
    USE SIGNAL ;
    ANTENNAGATEAREA 0.434700 ;
    ANTENNADIFFAREA 1.137600 ;
    PORT
      LAYER met3 ;
        RECT 0.000 134.680 0.600 135.280 ;
    END
  END s7_axi_wstrb_1
  PIN s7_axi_wstrb_2
    DIRECTION OUTPUT ;
    USE SIGNAL ;
    ANTENNAGATEAREA 0.434700 ;
    ANTENNADIFFAREA 1.137600 ;
    PORT
      LAYER met2 ;
        RECT 415.930 519.840 416.210 520.120 ;
    END
  END s7_axi_wstrb_2
  PIN s7_axi_wstrb_3
    DIRECTION OUTPUT ;
    USE SIGNAL ;
    ANTENNAGATEAREA 0.434700 ;
    ANTENNADIFFAREA 1.137600 ;
    PORT
      LAYER met2 ;
        RECT 53.450 519.840 53.730 520.120 ;
    END
  END s7_axi_wstrb_3
  PIN s7_axi_wvalid
    DIRECTION OUTPUT ;
    USE SIGNAL ;
    ANTENNAGATEAREA 0.434700 ;
    ANTENNADIFFAREA 0.775300 ;
    PORT
      LAYER met3 ;
        RECT 508.800 432.520 509.400 433.120 ;
    END
  END s7_axi_wvalid
  OBS
      LAYER nwell ;
        RECT 5.330 10.795 503.890 508.830 ;
      LAYER li1 ;
        RECT 5.520 10.795 503.700 508.725 ;
      LAYER met1 ;
        RECT 5.130 5.820 504.550 512.340 ;
      LAYER met2 ;
        RECT 5.160 519.560 43.970 519.840 ;
        RECT 44.810 519.560 44.890 519.840 ;
        RECT 45.730 519.560 45.810 519.840 ;
        RECT 46.650 519.560 46.730 519.840 ;
        RECT 47.570 519.560 47.650 519.840 ;
        RECT 48.490 519.560 48.570 519.840 ;
        RECT 49.410 519.560 49.490 519.840 ;
        RECT 50.330 519.560 50.410 519.840 ;
        RECT 51.250 519.560 51.330 519.840 ;
        RECT 52.170 519.560 52.250 519.840 ;
        RECT 53.090 519.560 53.170 519.840 ;
        RECT 54.010 519.560 54.090 519.840 ;
        RECT 54.930 519.560 55.010 519.840 ;
        RECT 55.850 519.560 55.930 519.840 ;
        RECT 56.770 519.560 56.850 519.840 ;
        RECT 57.690 519.560 57.770 519.840 ;
        RECT 58.610 519.560 58.690 519.840 ;
        RECT 59.530 519.560 59.610 519.840 ;
        RECT 60.450 519.560 60.530 519.840 ;
        RECT 61.370 519.560 61.450 519.840 ;
        RECT 62.290 519.560 62.370 519.840 ;
        RECT 63.210 519.560 63.290 519.840 ;
        RECT 64.130 519.560 64.210 519.840 ;
        RECT 65.050 519.560 65.130 519.840 ;
        RECT 65.970 519.560 66.050 519.840 ;
        RECT 66.890 519.560 66.970 519.840 ;
        RECT 67.810 519.560 67.890 519.840 ;
        RECT 68.730 519.560 68.810 519.840 ;
        RECT 69.650 519.560 69.730 519.840 ;
        RECT 70.570 519.560 70.650 519.840 ;
        RECT 71.490 519.560 71.570 519.840 ;
        RECT 72.410 519.560 72.490 519.840 ;
        RECT 73.330 519.560 73.410 519.840 ;
        RECT 74.250 519.560 74.330 519.840 ;
        RECT 75.170 519.560 75.250 519.840 ;
        RECT 76.090 519.560 76.170 519.840 ;
        RECT 77.010 519.560 77.090 519.840 ;
        RECT 77.930 519.560 78.010 519.840 ;
        RECT 78.850 519.560 78.930 519.840 ;
        RECT 79.770 519.560 79.850 519.840 ;
        RECT 80.690 519.560 80.770 519.840 ;
        RECT 81.610 519.560 81.690 519.840 ;
        RECT 82.530 519.560 82.610 519.840 ;
        RECT 83.450 519.560 83.530 519.840 ;
        RECT 84.370 519.560 84.450 519.840 ;
        RECT 85.290 519.560 85.370 519.840 ;
        RECT 86.210 519.560 86.290 519.840 ;
        RECT 87.130 519.560 87.210 519.840 ;
        RECT 88.050 519.560 88.130 519.840 ;
        RECT 88.970 519.560 89.050 519.840 ;
        RECT 89.890 519.560 89.970 519.840 ;
        RECT 90.810 519.560 90.890 519.840 ;
        RECT 91.730 519.560 91.810 519.840 ;
        RECT 92.650 519.560 92.730 519.840 ;
        RECT 93.570 519.560 93.650 519.840 ;
        RECT 94.490 519.560 94.570 519.840 ;
        RECT 95.410 519.560 95.490 519.840 ;
        RECT 96.330 519.560 96.410 519.840 ;
        RECT 97.250 519.560 97.330 519.840 ;
        RECT 98.170 519.560 98.250 519.840 ;
        RECT 99.090 519.560 99.170 519.840 ;
        RECT 100.010 519.560 100.090 519.840 ;
        RECT 100.930 519.560 101.010 519.840 ;
        RECT 101.850 519.560 101.930 519.840 ;
        RECT 102.770 519.560 102.850 519.840 ;
        RECT 103.690 519.560 103.770 519.840 ;
        RECT 104.610 519.560 104.690 519.840 ;
        RECT 105.530 519.560 105.610 519.840 ;
        RECT 106.450 519.560 106.530 519.840 ;
        RECT 107.370 519.560 107.450 519.840 ;
        RECT 108.290 519.560 108.370 519.840 ;
        RECT 109.210 519.560 109.290 519.840 ;
        RECT 110.130 519.560 110.210 519.840 ;
        RECT 111.050 519.560 111.130 519.840 ;
        RECT 111.970 519.560 112.050 519.840 ;
        RECT 112.890 519.560 112.970 519.840 ;
        RECT 113.810 519.560 113.890 519.840 ;
        RECT 114.730 519.560 114.810 519.840 ;
        RECT 115.650 519.560 115.730 519.840 ;
        RECT 116.570 519.560 116.650 519.840 ;
        RECT 117.490 519.560 117.570 519.840 ;
        RECT 118.410 519.560 118.490 519.840 ;
        RECT 119.330 519.560 119.410 519.840 ;
        RECT 120.250 519.560 120.330 519.840 ;
        RECT 121.170 519.560 121.250 519.840 ;
        RECT 122.090 519.560 122.170 519.840 ;
        RECT 123.010 519.560 123.090 519.840 ;
        RECT 123.930 519.560 124.010 519.840 ;
        RECT 124.850 519.560 124.930 519.840 ;
        RECT 125.770 519.560 125.850 519.840 ;
        RECT 126.690 519.560 126.770 519.840 ;
        RECT 127.610 519.560 127.690 519.840 ;
        RECT 128.530 519.560 128.610 519.840 ;
        RECT 129.450 519.560 129.530 519.840 ;
        RECT 130.370 519.560 130.450 519.840 ;
        RECT 131.290 519.560 131.370 519.840 ;
        RECT 132.210 519.560 132.290 519.840 ;
        RECT 133.130 519.560 133.210 519.840 ;
        RECT 134.050 519.560 134.130 519.840 ;
        RECT 134.970 519.560 135.050 519.840 ;
        RECT 135.890 519.560 135.970 519.840 ;
        RECT 136.810 519.560 136.890 519.840 ;
        RECT 137.730 519.560 137.810 519.840 ;
        RECT 138.650 519.560 138.730 519.840 ;
        RECT 139.570 519.560 139.650 519.840 ;
        RECT 140.490 519.560 140.570 519.840 ;
        RECT 141.410 519.560 141.490 519.840 ;
        RECT 142.330 519.560 142.410 519.840 ;
        RECT 143.250 519.560 143.330 519.840 ;
        RECT 144.170 519.560 144.250 519.840 ;
        RECT 145.090 519.560 145.170 519.840 ;
        RECT 146.010 519.560 146.090 519.840 ;
        RECT 146.930 519.560 147.010 519.840 ;
        RECT 147.850 519.560 147.930 519.840 ;
        RECT 148.770 519.560 148.850 519.840 ;
        RECT 149.690 519.560 149.770 519.840 ;
        RECT 150.610 519.560 150.690 519.840 ;
        RECT 151.530 519.560 151.610 519.840 ;
        RECT 152.450 519.560 152.530 519.840 ;
        RECT 153.370 519.560 153.450 519.840 ;
        RECT 154.290 519.560 154.370 519.840 ;
        RECT 155.210 519.560 155.290 519.840 ;
        RECT 156.130 519.560 156.210 519.840 ;
        RECT 157.050 519.560 157.130 519.840 ;
        RECT 157.970 519.560 158.050 519.840 ;
        RECT 158.890 519.560 158.970 519.840 ;
        RECT 159.810 519.560 159.890 519.840 ;
        RECT 160.730 519.560 160.810 519.840 ;
        RECT 161.650 519.560 161.730 519.840 ;
        RECT 162.570 519.560 162.650 519.840 ;
        RECT 163.490 519.560 163.570 519.840 ;
        RECT 164.410 519.560 164.490 519.840 ;
        RECT 165.330 519.560 165.410 519.840 ;
        RECT 166.250 519.560 166.330 519.840 ;
        RECT 167.170 519.560 167.250 519.840 ;
        RECT 168.090 519.560 168.170 519.840 ;
        RECT 169.010 519.560 169.090 519.840 ;
        RECT 169.930 519.560 170.010 519.840 ;
        RECT 170.850 519.560 170.930 519.840 ;
        RECT 171.770 519.560 171.850 519.840 ;
        RECT 172.690 519.560 172.770 519.840 ;
        RECT 173.610 519.560 173.690 519.840 ;
        RECT 174.530 519.560 174.610 519.840 ;
        RECT 175.450 519.560 175.530 519.840 ;
        RECT 176.370 519.560 176.450 519.840 ;
        RECT 177.290 519.560 177.370 519.840 ;
        RECT 178.210 519.560 178.290 519.840 ;
        RECT 179.130 519.560 179.210 519.840 ;
        RECT 180.050 519.560 180.130 519.840 ;
        RECT 180.970 519.560 181.050 519.840 ;
        RECT 181.890 519.560 181.970 519.840 ;
        RECT 182.810 519.560 182.890 519.840 ;
        RECT 183.730 519.560 183.810 519.840 ;
        RECT 184.650 519.560 184.730 519.840 ;
        RECT 185.570 519.560 185.650 519.840 ;
        RECT 186.490 519.560 186.570 519.840 ;
        RECT 187.410 519.560 187.490 519.840 ;
        RECT 188.330 519.560 188.410 519.840 ;
        RECT 189.250 519.560 189.330 519.840 ;
        RECT 190.170 519.560 190.250 519.840 ;
        RECT 191.090 519.560 191.170 519.840 ;
        RECT 192.010 519.560 192.090 519.840 ;
        RECT 192.930 519.560 193.010 519.840 ;
        RECT 193.850 519.560 193.930 519.840 ;
        RECT 194.770 519.560 194.850 519.840 ;
        RECT 195.690 519.560 195.770 519.840 ;
        RECT 196.610 519.560 196.690 519.840 ;
        RECT 197.530 519.560 197.610 519.840 ;
        RECT 198.450 519.560 198.530 519.840 ;
        RECT 199.370 519.560 199.450 519.840 ;
        RECT 200.290 519.560 200.370 519.840 ;
        RECT 201.210 519.560 201.290 519.840 ;
        RECT 202.130 519.560 202.210 519.840 ;
        RECT 203.050 519.560 203.130 519.840 ;
        RECT 203.970 519.560 204.050 519.840 ;
        RECT 204.890 519.560 204.970 519.840 ;
        RECT 205.810 519.560 205.890 519.840 ;
        RECT 206.730 519.560 206.810 519.840 ;
        RECT 207.650 519.560 207.730 519.840 ;
        RECT 208.570 519.560 208.650 519.840 ;
        RECT 209.490 519.560 209.570 519.840 ;
        RECT 210.410 519.560 210.490 519.840 ;
        RECT 211.330 519.560 211.410 519.840 ;
        RECT 212.250 519.560 212.330 519.840 ;
        RECT 213.170 519.560 213.250 519.840 ;
        RECT 214.090 519.560 214.170 519.840 ;
        RECT 215.010 519.560 215.090 519.840 ;
        RECT 215.930 519.560 216.010 519.840 ;
        RECT 216.850 519.560 216.930 519.840 ;
        RECT 217.770 519.560 217.850 519.840 ;
        RECT 218.690 519.560 218.770 519.840 ;
        RECT 219.610 519.560 219.690 519.840 ;
        RECT 220.530 519.560 220.610 519.840 ;
        RECT 221.450 519.560 221.530 519.840 ;
        RECT 222.370 519.560 222.450 519.840 ;
        RECT 223.290 519.560 223.370 519.840 ;
        RECT 224.210 519.560 224.290 519.840 ;
        RECT 225.130 519.560 225.210 519.840 ;
        RECT 226.050 519.560 226.130 519.840 ;
        RECT 226.970 519.560 227.050 519.840 ;
        RECT 227.890 519.560 227.970 519.840 ;
        RECT 228.810 519.560 228.890 519.840 ;
        RECT 229.730 519.560 229.810 519.840 ;
        RECT 230.650 519.560 230.730 519.840 ;
        RECT 231.570 519.560 231.650 519.840 ;
        RECT 232.490 519.560 232.570 519.840 ;
        RECT 233.410 519.560 233.490 519.840 ;
        RECT 234.330 519.560 234.410 519.840 ;
        RECT 235.250 519.560 235.330 519.840 ;
        RECT 236.170 519.560 236.250 519.840 ;
        RECT 237.090 519.560 237.170 519.840 ;
        RECT 238.010 519.560 238.090 519.840 ;
        RECT 238.930 519.560 239.010 519.840 ;
        RECT 239.850 519.560 239.930 519.840 ;
        RECT 240.770 519.560 240.850 519.840 ;
        RECT 241.690 519.560 241.770 519.840 ;
        RECT 242.610 519.560 242.690 519.840 ;
        RECT 243.530 519.560 243.610 519.840 ;
        RECT 244.450 519.560 244.530 519.840 ;
        RECT 245.370 519.560 245.450 519.840 ;
        RECT 246.290 519.560 246.370 519.840 ;
        RECT 247.210 519.560 247.290 519.840 ;
        RECT 248.130 519.560 248.210 519.840 ;
        RECT 249.050 519.560 249.130 519.840 ;
        RECT 249.970 519.560 250.050 519.840 ;
        RECT 250.890 519.560 250.970 519.840 ;
        RECT 251.810 519.560 251.890 519.840 ;
        RECT 252.730 519.560 252.810 519.840 ;
        RECT 253.650 519.560 253.730 519.840 ;
        RECT 254.570 519.560 254.650 519.840 ;
        RECT 255.490 519.560 255.570 519.840 ;
        RECT 256.410 519.560 256.490 519.840 ;
        RECT 257.330 519.560 257.410 519.840 ;
        RECT 258.250 519.560 258.330 519.840 ;
        RECT 259.170 519.560 259.250 519.840 ;
        RECT 260.090 519.560 260.170 519.840 ;
        RECT 261.010 519.560 261.090 519.840 ;
        RECT 261.930 519.560 262.010 519.840 ;
        RECT 262.850 519.560 262.930 519.840 ;
        RECT 263.770 519.560 263.850 519.840 ;
        RECT 264.690 519.560 264.770 519.840 ;
        RECT 265.610 519.560 265.690 519.840 ;
        RECT 266.530 519.560 266.610 519.840 ;
        RECT 267.450 519.560 267.530 519.840 ;
        RECT 268.370 519.560 268.450 519.840 ;
        RECT 269.290 519.560 269.370 519.840 ;
        RECT 270.210 519.560 270.290 519.840 ;
        RECT 271.130 519.560 271.210 519.840 ;
        RECT 272.050 519.560 272.130 519.840 ;
        RECT 272.970 519.560 273.050 519.840 ;
        RECT 273.890 519.560 273.970 519.840 ;
        RECT 274.810 519.560 274.890 519.840 ;
        RECT 275.730 519.560 275.810 519.840 ;
        RECT 276.650 519.560 276.730 519.840 ;
        RECT 277.570 519.560 277.650 519.840 ;
        RECT 278.490 519.560 278.570 519.840 ;
        RECT 279.410 519.560 279.490 519.840 ;
        RECT 280.330 519.560 280.410 519.840 ;
        RECT 281.250 519.560 281.330 519.840 ;
        RECT 282.170 519.560 282.250 519.840 ;
        RECT 283.090 519.560 283.170 519.840 ;
        RECT 284.010 519.560 284.090 519.840 ;
        RECT 284.930 519.560 285.010 519.840 ;
        RECT 285.850 519.560 285.930 519.840 ;
        RECT 286.770 519.560 286.850 519.840 ;
        RECT 287.690 519.560 287.770 519.840 ;
        RECT 288.610 519.560 288.690 519.840 ;
        RECT 289.530 519.560 289.610 519.840 ;
        RECT 290.450 519.560 290.530 519.840 ;
        RECT 291.370 519.560 291.450 519.840 ;
        RECT 292.290 519.560 292.370 519.840 ;
        RECT 293.210 519.560 293.290 519.840 ;
        RECT 294.130 519.560 294.210 519.840 ;
        RECT 295.050 519.560 295.130 519.840 ;
        RECT 295.970 519.560 296.050 519.840 ;
        RECT 296.890 519.560 296.970 519.840 ;
        RECT 297.810 519.560 297.890 519.840 ;
        RECT 298.730 519.560 298.810 519.840 ;
        RECT 299.650 519.560 299.730 519.840 ;
        RECT 300.570 519.560 300.650 519.840 ;
        RECT 301.490 519.560 301.570 519.840 ;
        RECT 302.410 519.560 302.490 519.840 ;
        RECT 303.330 519.560 303.410 519.840 ;
        RECT 304.250 519.560 304.330 519.840 ;
        RECT 305.170 519.560 305.250 519.840 ;
        RECT 306.090 519.560 306.170 519.840 ;
        RECT 307.010 519.560 307.090 519.840 ;
        RECT 307.930 519.560 308.010 519.840 ;
        RECT 308.850 519.560 308.930 519.840 ;
        RECT 309.770 519.560 309.850 519.840 ;
        RECT 310.690 519.560 310.770 519.840 ;
        RECT 311.610 519.560 311.690 519.840 ;
        RECT 312.530 519.560 312.610 519.840 ;
        RECT 313.450 519.560 313.530 519.840 ;
        RECT 314.370 519.560 314.450 519.840 ;
        RECT 315.290 519.560 315.370 519.840 ;
        RECT 316.210 519.560 316.290 519.840 ;
        RECT 317.130 519.560 317.210 519.840 ;
        RECT 318.050 519.560 318.130 519.840 ;
        RECT 318.970 519.560 319.050 519.840 ;
        RECT 319.890 519.560 319.970 519.840 ;
        RECT 320.810 519.560 320.890 519.840 ;
        RECT 321.730 519.560 321.810 519.840 ;
        RECT 322.650 519.560 322.730 519.840 ;
        RECT 323.570 519.560 324.570 519.840 ;
        RECT 325.410 519.560 325.490 519.840 ;
        RECT 326.330 519.560 326.410 519.840 ;
        RECT 327.250 519.560 327.330 519.840 ;
        RECT 328.170 519.560 328.250 519.840 ;
        RECT 329.090 519.560 329.170 519.840 ;
        RECT 330.010 519.560 330.090 519.840 ;
        RECT 330.930 519.560 331.010 519.840 ;
        RECT 331.850 519.560 331.930 519.840 ;
        RECT 332.770 519.560 332.850 519.840 ;
        RECT 333.690 519.560 333.770 519.840 ;
        RECT 334.610 519.560 334.690 519.840 ;
        RECT 335.530 519.560 335.610 519.840 ;
        RECT 336.450 519.560 336.530 519.840 ;
        RECT 337.370 519.560 337.450 519.840 ;
        RECT 338.290 519.560 338.370 519.840 ;
        RECT 339.210 519.560 339.290 519.840 ;
        RECT 340.130 519.560 340.210 519.840 ;
        RECT 341.050 519.560 341.130 519.840 ;
        RECT 341.970 519.560 342.050 519.840 ;
        RECT 342.890 519.560 342.970 519.840 ;
        RECT 343.810 519.560 343.890 519.840 ;
        RECT 344.730 519.560 344.810 519.840 ;
        RECT 345.650 519.560 345.730 519.840 ;
        RECT 346.570 519.560 346.650 519.840 ;
        RECT 347.490 519.560 347.570 519.840 ;
        RECT 348.410 519.560 348.490 519.840 ;
        RECT 349.330 519.560 349.410 519.840 ;
        RECT 350.250 519.560 350.330 519.840 ;
        RECT 351.170 519.560 351.250 519.840 ;
        RECT 352.090 519.560 352.170 519.840 ;
        RECT 353.010 519.560 353.090 519.840 ;
        RECT 353.930 519.560 354.010 519.840 ;
        RECT 354.850 519.560 354.930 519.840 ;
        RECT 355.770 519.560 355.850 519.840 ;
        RECT 356.690 519.560 356.770 519.840 ;
        RECT 357.610 519.560 357.690 519.840 ;
        RECT 358.530 519.560 358.610 519.840 ;
        RECT 359.450 519.560 359.530 519.840 ;
        RECT 360.370 519.560 360.450 519.840 ;
        RECT 361.290 519.560 361.370 519.840 ;
        RECT 362.210 519.560 362.290 519.840 ;
        RECT 363.130 519.560 363.210 519.840 ;
        RECT 364.050 519.560 364.130 519.840 ;
        RECT 364.970 519.560 365.050 519.840 ;
        RECT 365.890 519.560 365.970 519.840 ;
        RECT 366.810 519.560 366.890 519.840 ;
        RECT 367.730 519.560 367.810 519.840 ;
        RECT 368.650 519.560 368.730 519.840 ;
        RECT 369.570 519.560 369.650 519.840 ;
        RECT 370.490 519.560 370.570 519.840 ;
        RECT 371.410 519.560 371.490 519.840 ;
        RECT 372.330 519.560 372.410 519.840 ;
        RECT 373.250 519.560 373.330 519.840 ;
        RECT 374.170 519.560 374.250 519.840 ;
        RECT 375.090 519.560 375.170 519.840 ;
        RECT 376.010 519.560 377.010 519.840 ;
        RECT 377.850 519.560 377.930 519.840 ;
        RECT 378.770 519.560 378.850 519.840 ;
        RECT 379.690 519.560 379.770 519.840 ;
        RECT 380.610 519.560 380.690 519.840 ;
        RECT 381.530 519.560 381.610 519.840 ;
        RECT 382.450 519.560 382.530 519.840 ;
        RECT 383.370 519.560 383.450 519.840 ;
        RECT 384.290 519.560 386.210 519.840 ;
        RECT 387.050 519.560 387.130 519.840 ;
        RECT 387.970 519.560 388.050 519.840 ;
        RECT 388.890 519.560 388.970 519.840 ;
        RECT 389.810 519.560 389.890 519.840 ;
        RECT 390.730 519.560 390.810 519.840 ;
        RECT 391.650 519.560 391.730 519.840 ;
        RECT 392.570 519.560 392.650 519.840 ;
        RECT 393.490 519.560 393.570 519.840 ;
        RECT 394.410 519.560 394.490 519.840 ;
        RECT 395.330 519.560 395.410 519.840 ;
        RECT 396.250 519.560 396.330 519.840 ;
        RECT 397.170 519.560 397.250 519.840 ;
        RECT 398.090 519.560 398.170 519.840 ;
        RECT 399.010 519.560 399.090 519.840 ;
        RECT 399.930 519.560 400.010 519.840 ;
        RECT 400.850 519.560 401.850 519.840 ;
        RECT 402.690 519.560 402.770 519.840 ;
        RECT 403.610 519.560 403.690 519.840 ;
        RECT 404.530 519.560 404.610 519.840 ;
        RECT 405.450 519.560 405.530 519.840 ;
        RECT 406.370 519.560 406.450 519.840 ;
        RECT 407.290 519.560 407.370 519.840 ;
        RECT 408.210 519.560 408.290 519.840 ;
        RECT 409.130 519.560 414.730 519.840 ;
        RECT 415.570 519.560 415.650 519.840 ;
        RECT 416.490 519.560 416.570 519.840 ;
        RECT 417.410 519.560 417.490 519.840 ;
        RECT 418.330 519.560 418.410 519.840 ;
        RECT 419.250 519.560 419.330 519.840 ;
        RECT 420.170 519.560 420.250 519.840 ;
        RECT 421.090 519.560 421.170 519.840 ;
        RECT 422.010 519.560 422.090 519.840 ;
        RECT 422.930 519.560 423.010 519.840 ;
        RECT 423.850 519.560 423.930 519.840 ;
        RECT 424.770 519.560 424.850 519.840 ;
        RECT 425.690 519.560 425.770 519.840 ;
        RECT 426.610 519.560 426.690 519.840 ;
        RECT 427.530 519.560 427.610 519.840 ;
        RECT 428.450 519.560 428.530 519.840 ;
        RECT 429.370 519.560 449.690 519.840 ;
        RECT 450.530 519.560 450.610 519.840 ;
        RECT 451.450 519.560 451.530 519.840 ;
        RECT 452.370 519.560 452.450 519.840 ;
        RECT 453.290 519.560 453.370 519.840 ;
        RECT 454.210 519.560 454.290 519.840 ;
        RECT 455.130 519.560 455.210 519.840 ;
        RECT 456.050 519.560 456.130 519.840 ;
        RECT 456.970 519.560 504.530 519.840 ;
        RECT 5.160 0.560 504.530 519.560 ;
        RECT 5.250 0.280 5.330 0.560 ;
        RECT 6.170 0.280 6.250 0.560 ;
        RECT 7.090 0.280 7.170 0.560 ;
        RECT 8.010 0.280 8.090 0.560 ;
        RECT 8.930 0.280 9.010 0.560 ;
        RECT 9.850 0.280 9.930 0.560 ;
        RECT 10.770 0.280 10.850 0.560 ;
        RECT 11.690 0.280 11.770 0.560 ;
        RECT 12.610 0.280 12.690 0.560 ;
        RECT 13.530 0.280 13.610 0.560 ;
        RECT 14.450 0.280 14.530 0.560 ;
        RECT 15.370 0.280 15.450 0.560 ;
        RECT 16.290 0.280 16.370 0.560 ;
        RECT 17.210 0.280 17.290 0.560 ;
        RECT 18.130 0.280 18.210 0.560 ;
        RECT 19.050 0.280 19.130 0.560 ;
        RECT 19.970 0.280 20.050 0.560 ;
        RECT 20.890 0.280 20.970 0.560 ;
        RECT 21.810 0.280 21.890 0.560 ;
        RECT 22.730 0.280 22.810 0.560 ;
        RECT 23.650 0.280 23.730 0.560 ;
        RECT 24.570 0.280 24.650 0.560 ;
        RECT 25.490 0.280 25.570 0.560 ;
        RECT 26.410 0.280 26.490 0.560 ;
        RECT 27.330 0.280 27.410 0.560 ;
        RECT 28.250 0.280 28.330 0.560 ;
        RECT 29.170 0.280 29.250 0.560 ;
        RECT 30.090 0.280 30.170 0.560 ;
        RECT 31.010 0.280 31.090 0.560 ;
        RECT 31.930 0.280 32.010 0.560 ;
        RECT 32.850 0.280 32.930 0.560 ;
        RECT 33.770 0.280 33.850 0.560 ;
        RECT 34.690 0.280 34.770 0.560 ;
        RECT 35.610 0.280 35.690 0.560 ;
        RECT 36.530 0.280 36.610 0.560 ;
        RECT 37.450 0.280 37.530 0.560 ;
        RECT 38.370 0.280 38.450 0.560 ;
        RECT 39.290 0.280 39.370 0.560 ;
        RECT 40.210 0.280 40.290 0.560 ;
        RECT 41.130 0.280 41.210 0.560 ;
        RECT 42.050 0.280 42.130 0.560 ;
        RECT 42.970 0.280 43.050 0.560 ;
        RECT 43.890 0.280 43.970 0.560 ;
        RECT 44.810 0.280 44.890 0.560 ;
        RECT 45.730 0.280 45.810 0.560 ;
        RECT 46.650 0.280 46.730 0.560 ;
        RECT 47.570 0.280 47.650 0.560 ;
        RECT 48.490 0.280 48.570 0.560 ;
        RECT 49.410 0.280 49.490 0.560 ;
        RECT 50.330 0.280 50.410 0.560 ;
        RECT 51.250 0.280 51.330 0.560 ;
        RECT 52.170 0.280 52.250 0.560 ;
        RECT 53.090 0.280 53.170 0.560 ;
        RECT 54.010 0.280 54.090 0.560 ;
        RECT 54.930 0.280 55.010 0.560 ;
        RECT 55.850 0.280 55.930 0.560 ;
        RECT 56.770 0.280 56.850 0.560 ;
        RECT 57.690 0.280 57.770 0.560 ;
        RECT 58.610 0.280 58.690 0.560 ;
        RECT 59.530 0.280 59.610 0.560 ;
        RECT 60.450 0.280 60.530 0.560 ;
        RECT 61.370 0.280 61.450 0.560 ;
        RECT 62.290 0.280 62.370 0.560 ;
        RECT 63.210 0.280 63.290 0.560 ;
        RECT 64.130 0.280 64.210 0.560 ;
        RECT 65.050 0.280 65.130 0.560 ;
        RECT 65.970 0.280 66.050 0.560 ;
        RECT 66.890 0.280 66.970 0.560 ;
        RECT 67.810 0.280 67.890 0.560 ;
        RECT 68.730 0.280 68.810 0.560 ;
        RECT 69.650 0.280 69.730 0.560 ;
        RECT 70.570 0.280 70.650 0.560 ;
        RECT 71.490 0.280 71.570 0.560 ;
        RECT 72.410 0.280 72.490 0.560 ;
        RECT 73.330 0.280 73.410 0.560 ;
        RECT 74.250 0.280 74.330 0.560 ;
        RECT 75.170 0.280 75.250 0.560 ;
        RECT 76.090 0.280 76.170 0.560 ;
        RECT 77.010 0.280 77.090 0.560 ;
        RECT 77.930 0.280 78.010 0.560 ;
        RECT 78.850 0.280 78.930 0.560 ;
        RECT 79.770 0.280 79.850 0.560 ;
        RECT 80.690 0.280 80.770 0.560 ;
        RECT 81.610 0.280 81.690 0.560 ;
        RECT 82.530 0.280 82.610 0.560 ;
        RECT 83.450 0.280 83.530 0.560 ;
        RECT 84.370 0.280 84.450 0.560 ;
        RECT 85.290 0.280 85.370 0.560 ;
        RECT 86.210 0.280 86.290 0.560 ;
        RECT 87.130 0.280 87.210 0.560 ;
        RECT 88.050 0.280 88.130 0.560 ;
        RECT 88.970 0.280 89.050 0.560 ;
        RECT 89.890 0.280 89.970 0.560 ;
        RECT 90.810 0.280 90.890 0.560 ;
        RECT 91.730 0.280 91.810 0.560 ;
        RECT 92.650 0.280 92.730 0.560 ;
        RECT 93.570 0.280 93.650 0.560 ;
        RECT 94.490 0.280 94.570 0.560 ;
        RECT 95.410 0.280 95.490 0.560 ;
        RECT 96.330 0.280 96.410 0.560 ;
        RECT 97.250 0.280 97.330 0.560 ;
        RECT 98.170 0.280 98.250 0.560 ;
        RECT 99.090 0.280 99.170 0.560 ;
        RECT 100.010 0.280 100.090 0.560 ;
        RECT 100.930 0.280 101.010 0.560 ;
        RECT 101.850 0.280 101.930 0.560 ;
        RECT 102.770 0.280 102.850 0.560 ;
        RECT 103.690 0.280 103.770 0.560 ;
        RECT 104.610 0.280 104.690 0.560 ;
        RECT 105.530 0.280 105.610 0.560 ;
        RECT 106.450 0.280 106.530 0.560 ;
        RECT 107.370 0.280 107.450 0.560 ;
        RECT 108.290 0.280 108.370 0.560 ;
        RECT 109.210 0.280 109.290 0.560 ;
        RECT 110.130 0.280 110.210 0.560 ;
        RECT 111.050 0.280 111.130 0.560 ;
        RECT 111.970 0.280 112.050 0.560 ;
        RECT 112.890 0.280 112.970 0.560 ;
        RECT 113.810 0.280 113.890 0.560 ;
        RECT 114.730 0.280 114.810 0.560 ;
        RECT 115.650 0.280 115.730 0.560 ;
        RECT 116.570 0.280 116.650 0.560 ;
        RECT 117.490 0.280 117.570 0.560 ;
        RECT 118.410 0.280 118.490 0.560 ;
        RECT 119.330 0.280 119.410 0.560 ;
        RECT 120.250 0.280 120.330 0.560 ;
        RECT 121.170 0.280 121.250 0.560 ;
        RECT 122.090 0.280 122.170 0.560 ;
        RECT 123.010 0.280 123.090 0.560 ;
        RECT 123.930 0.280 124.010 0.560 ;
        RECT 124.850 0.280 124.930 0.560 ;
        RECT 125.770 0.280 125.850 0.560 ;
        RECT 126.690 0.280 126.770 0.560 ;
        RECT 127.610 0.280 127.690 0.560 ;
        RECT 128.530 0.280 128.610 0.560 ;
        RECT 129.450 0.280 129.530 0.560 ;
        RECT 130.370 0.280 130.450 0.560 ;
        RECT 131.290 0.280 131.370 0.560 ;
        RECT 132.210 0.280 132.290 0.560 ;
        RECT 133.130 0.280 133.210 0.560 ;
        RECT 134.050 0.280 134.130 0.560 ;
        RECT 134.970 0.280 135.050 0.560 ;
        RECT 135.890 0.280 135.970 0.560 ;
        RECT 136.810 0.280 136.890 0.560 ;
        RECT 137.730 0.280 137.810 0.560 ;
        RECT 138.650 0.280 138.730 0.560 ;
        RECT 139.570 0.280 139.650 0.560 ;
        RECT 140.490 0.280 140.570 0.560 ;
        RECT 141.410 0.280 141.490 0.560 ;
        RECT 142.330 0.280 142.410 0.560 ;
        RECT 143.250 0.280 143.330 0.560 ;
        RECT 144.170 0.280 144.250 0.560 ;
        RECT 145.090 0.280 145.170 0.560 ;
        RECT 146.010 0.280 146.090 0.560 ;
        RECT 146.930 0.280 147.010 0.560 ;
        RECT 147.850 0.280 147.930 0.560 ;
        RECT 148.770 0.280 148.850 0.560 ;
        RECT 149.690 0.280 149.770 0.560 ;
        RECT 150.610 0.280 150.690 0.560 ;
        RECT 151.530 0.280 151.610 0.560 ;
        RECT 152.450 0.280 152.530 0.560 ;
        RECT 153.370 0.280 153.450 0.560 ;
        RECT 154.290 0.280 154.370 0.560 ;
        RECT 155.210 0.280 155.290 0.560 ;
        RECT 156.130 0.280 156.210 0.560 ;
        RECT 157.050 0.280 157.130 0.560 ;
        RECT 157.970 0.280 158.050 0.560 ;
        RECT 158.890 0.280 158.970 0.560 ;
        RECT 159.810 0.280 159.890 0.560 ;
        RECT 160.730 0.280 160.810 0.560 ;
        RECT 161.650 0.280 161.730 0.560 ;
        RECT 162.570 0.280 162.650 0.560 ;
        RECT 163.490 0.280 163.570 0.560 ;
        RECT 164.410 0.280 164.490 0.560 ;
        RECT 165.330 0.280 165.410 0.560 ;
        RECT 166.250 0.280 166.330 0.560 ;
        RECT 167.170 0.280 167.250 0.560 ;
        RECT 168.090 0.280 168.170 0.560 ;
        RECT 169.010 0.280 169.090 0.560 ;
        RECT 169.930 0.280 170.010 0.560 ;
        RECT 170.850 0.280 170.930 0.560 ;
        RECT 171.770 0.280 171.850 0.560 ;
        RECT 172.690 0.280 172.770 0.560 ;
        RECT 173.610 0.280 173.690 0.560 ;
        RECT 174.530 0.280 174.610 0.560 ;
        RECT 175.450 0.280 175.530 0.560 ;
        RECT 176.370 0.280 176.450 0.560 ;
        RECT 177.290 0.280 177.370 0.560 ;
        RECT 178.210 0.280 178.290 0.560 ;
        RECT 179.130 0.280 179.210 0.560 ;
        RECT 180.050 0.280 180.130 0.560 ;
        RECT 180.970 0.280 181.050 0.560 ;
        RECT 181.890 0.280 181.970 0.560 ;
        RECT 182.810 0.280 182.890 0.560 ;
        RECT 183.730 0.280 183.810 0.560 ;
        RECT 184.650 0.280 184.730 0.560 ;
        RECT 185.570 0.280 185.650 0.560 ;
        RECT 186.490 0.280 186.570 0.560 ;
        RECT 187.410 0.280 187.490 0.560 ;
        RECT 188.330 0.280 188.410 0.560 ;
        RECT 189.250 0.280 189.330 0.560 ;
        RECT 190.170 0.280 190.250 0.560 ;
        RECT 191.090 0.280 191.170 0.560 ;
        RECT 192.010 0.280 192.090 0.560 ;
        RECT 192.930 0.280 193.010 0.560 ;
        RECT 193.850 0.280 193.930 0.560 ;
        RECT 194.770 0.280 194.850 0.560 ;
        RECT 195.690 0.280 195.770 0.560 ;
        RECT 196.610 0.280 196.690 0.560 ;
        RECT 197.530 0.280 197.610 0.560 ;
        RECT 198.450 0.280 198.530 0.560 ;
        RECT 199.370 0.280 199.450 0.560 ;
        RECT 200.290 0.280 200.370 0.560 ;
        RECT 201.210 0.280 201.290 0.560 ;
        RECT 202.130 0.280 202.210 0.560 ;
        RECT 203.050 0.280 203.130 0.560 ;
        RECT 203.970 0.280 204.050 0.560 ;
        RECT 204.890 0.280 204.970 0.560 ;
        RECT 205.810 0.280 205.890 0.560 ;
        RECT 206.730 0.280 206.810 0.560 ;
        RECT 207.650 0.280 207.730 0.560 ;
        RECT 208.570 0.280 208.650 0.560 ;
        RECT 209.490 0.280 209.570 0.560 ;
        RECT 210.410 0.280 210.490 0.560 ;
        RECT 211.330 0.280 211.410 0.560 ;
        RECT 212.250 0.280 212.330 0.560 ;
        RECT 213.170 0.280 213.250 0.560 ;
        RECT 214.090 0.280 214.170 0.560 ;
        RECT 215.010 0.280 215.090 0.560 ;
        RECT 215.930 0.280 216.010 0.560 ;
        RECT 216.850 0.280 216.930 0.560 ;
        RECT 217.770 0.280 217.850 0.560 ;
        RECT 218.690 0.280 218.770 0.560 ;
        RECT 219.610 0.280 219.690 0.560 ;
        RECT 220.530 0.280 220.610 0.560 ;
        RECT 221.450 0.280 221.530 0.560 ;
        RECT 222.370 0.280 222.450 0.560 ;
        RECT 223.290 0.280 223.370 0.560 ;
        RECT 224.210 0.280 224.290 0.560 ;
        RECT 225.130 0.280 225.210 0.560 ;
        RECT 226.050 0.280 226.130 0.560 ;
        RECT 226.970 0.280 227.050 0.560 ;
        RECT 227.890 0.280 227.970 0.560 ;
        RECT 228.810 0.280 228.890 0.560 ;
        RECT 229.730 0.280 229.810 0.560 ;
        RECT 230.650 0.280 230.730 0.560 ;
        RECT 231.570 0.280 231.650 0.560 ;
        RECT 232.490 0.280 232.570 0.560 ;
        RECT 233.410 0.280 233.490 0.560 ;
        RECT 234.330 0.280 234.410 0.560 ;
        RECT 235.250 0.280 235.330 0.560 ;
        RECT 236.170 0.280 236.250 0.560 ;
        RECT 237.090 0.280 237.170 0.560 ;
        RECT 238.010 0.280 238.090 0.560 ;
        RECT 238.930 0.280 239.010 0.560 ;
        RECT 239.850 0.280 239.930 0.560 ;
        RECT 240.770 0.280 240.850 0.560 ;
        RECT 241.690 0.280 241.770 0.560 ;
        RECT 242.610 0.280 242.690 0.560 ;
        RECT 243.530 0.280 243.610 0.560 ;
        RECT 244.450 0.280 244.530 0.560 ;
        RECT 245.370 0.280 245.450 0.560 ;
        RECT 246.290 0.280 246.370 0.560 ;
        RECT 247.210 0.280 247.290 0.560 ;
        RECT 248.130 0.280 248.210 0.560 ;
        RECT 249.050 0.280 249.130 0.560 ;
        RECT 249.970 0.280 250.050 0.560 ;
        RECT 250.890 0.280 250.970 0.560 ;
        RECT 251.810 0.280 251.890 0.560 ;
        RECT 252.730 0.280 252.810 0.560 ;
        RECT 253.650 0.280 253.730 0.560 ;
        RECT 254.570 0.280 254.650 0.560 ;
        RECT 255.490 0.280 255.570 0.560 ;
        RECT 256.410 0.280 256.490 0.560 ;
        RECT 257.330 0.280 257.410 0.560 ;
        RECT 258.250 0.280 258.330 0.560 ;
        RECT 259.170 0.280 259.250 0.560 ;
        RECT 260.090 0.280 260.170 0.560 ;
        RECT 261.010 0.280 261.090 0.560 ;
        RECT 261.930 0.280 262.010 0.560 ;
        RECT 262.850 0.280 262.930 0.560 ;
        RECT 263.770 0.280 263.850 0.560 ;
        RECT 264.690 0.280 264.770 0.560 ;
        RECT 265.610 0.280 265.690 0.560 ;
        RECT 266.530 0.280 266.610 0.560 ;
        RECT 267.450 0.280 267.530 0.560 ;
        RECT 268.370 0.280 268.450 0.560 ;
        RECT 269.290 0.280 269.370 0.560 ;
        RECT 270.210 0.280 270.290 0.560 ;
        RECT 271.130 0.280 271.210 0.560 ;
        RECT 272.050 0.280 272.130 0.560 ;
        RECT 272.970 0.280 273.050 0.560 ;
        RECT 273.890 0.280 273.970 0.560 ;
        RECT 274.810 0.280 274.890 0.560 ;
        RECT 275.730 0.280 275.810 0.560 ;
        RECT 276.650 0.280 276.730 0.560 ;
        RECT 277.570 0.280 277.650 0.560 ;
        RECT 278.490 0.280 278.570 0.560 ;
        RECT 279.410 0.280 279.490 0.560 ;
        RECT 280.330 0.280 280.410 0.560 ;
        RECT 281.250 0.280 281.330 0.560 ;
        RECT 282.170 0.280 282.250 0.560 ;
        RECT 283.090 0.280 283.170 0.560 ;
        RECT 284.010 0.280 284.090 0.560 ;
        RECT 284.930 0.280 285.010 0.560 ;
        RECT 285.850 0.280 285.930 0.560 ;
        RECT 286.770 0.280 286.850 0.560 ;
        RECT 287.690 0.280 287.770 0.560 ;
        RECT 288.610 0.280 288.690 0.560 ;
        RECT 289.530 0.280 289.610 0.560 ;
        RECT 290.450 0.280 290.530 0.560 ;
        RECT 291.370 0.280 291.450 0.560 ;
        RECT 292.290 0.280 292.370 0.560 ;
        RECT 293.210 0.280 293.290 0.560 ;
        RECT 294.130 0.280 294.210 0.560 ;
        RECT 295.050 0.280 295.130 0.560 ;
        RECT 295.970 0.280 296.050 0.560 ;
        RECT 296.890 0.280 296.970 0.560 ;
        RECT 297.810 0.280 297.890 0.560 ;
        RECT 298.730 0.280 298.810 0.560 ;
        RECT 299.650 0.280 299.730 0.560 ;
        RECT 300.570 0.280 300.650 0.560 ;
        RECT 301.490 0.280 301.570 0.560 ;
        RECT 302.410 0.280 302.490 0.560 ;
        RECT 303.330 0.280 303.410 0.560 ;
        RECT 304.250 0.280 304.330 0.560 ;
        RECT 305.170 0.280 305.250 0.560 ;
        RECT 306.090 0.280 306.170 0.560 ;
        RECT 307.010 0.280 307.090 0.560 ;
        RECT 307.930 0.280 308.010 0.560 ;
        RECT 308.850 0.280 308.930 0.560 ;
        RECT 309.770 0.280 309.850 0.560 ;
        RECT 310.690 0.280 310.770 0.560 ;
        RECT 311.610 0.280 311.690 0.560 ;
        RECT 312.530 0.280 312.610 0.560 ;
        RECT 313.450 0.280 313.530 0.560 ;
        RECT 314.370 0.280 314.450 0.560 ;
        RECT 315.290 0.280 315.370 0.560 ;
        RECT 316.210 0.280 316.290 0.560 ;
        RECT 317.130 0.280 317.210 0.560 ;
        RECT 318.050 0.280 318.130 0.560 ;
        RECT 318.970 0.280 319.050 0.560 ;
        RECT 319.890 0.280 319.970 0.560 ;
        RECT 320.810 0.280 320.890 0.560 ;
        RECT 321.730 0.280 321.810 0.560 ;
        RECT 322.650 0.280 322.730 0.560 ;
        RECT 323.570 0.280 323.650 0.560 ;
        RECT 324.490 0.280 324.570 0.560 ;
        RECT 325.410 0.280 325.490 0.560 ;
        RECT 326.330 0.280 326.410 0.560 ;
        RECT 327.250 0.280 327.330 0.560 ;
        RECT 328.170 0.280 328.250 0.560 ;
        RECT 329.090 0.280 329.170 0.560 ;
        RECT 330.010 0.280 330.090 0.560 ;
        RECT 330.930 0.280 331.010 0.560 ;
        RECT 331.850 0.280 331.930 0.560 ;
        RECT 332.770 0.280 332.850 0.560 ;
        RECT 333.690 0.280 333.770 0.560 ;
        RECT 334.610 0.280 334.690 0.560 ;
        RECT 335.530 0.280 335.610 0.560 ;
        RECT 336.450 0.280 336.530 0.560 ;
        RECT 337.370 0.280 337.450 0.560 ;
        RECT 338.290 0.280 338.370 0.560 ;
        RECT 339.210 0.280 339.290 0.560 ;
        RECT 340.130 0.280 340.210 0.560 ;
        RECT 341.050 0.280 341.130 0.560 ;
        RECT 341.970 0.280 342.050 0.560 ;
        RECT 342.890 0.280 342.970 0.560 ;
        RECT 343.810 0.280 343.890 0.560 ;
        RECT 344.730 0.280 344.810 0.560 ;
        RECT 345.650 0.280 345.730 0.560 ;
        RECT 346.570 0.280 346.650 0.560 ;
        RECT 347.490 0.280 347.570 0.560 ;
        RECT 348.410 0.280 348.490 0.560 ;
        RECT 349.330 0.280 349.410 0.560 ;
        RECT 350.250 0.280 350.330 0.560 ;
        RECT 351.170 0.280 351.250 0.560 ;
        RECT 352.090 0.280 352.170 0.560 ;
        RECT 353.010 0.280 353.090 0.560 ;
        RECT 353.930 0.280 354.010 0.560 ;
        RECT 354.850 0.280 354.930 0.560 ;
        RECT 355.770 0.280 355.850 0.560 ;
        RECT 356.690 0.280 356.770 0.560 ;
        RECT 357.610 0.280 357.690 0.560 ;
        RECT 358.530 0.280 358.610 0.560 ;
        RECT 359.450 0.280 359.530 0.560 ;
        RECT 360.370 0.280 360.450 0.560 ;
        RECT 361.290 0.280 361.370 0.560 ;
        RECT 362.210 0.280 362.290 0.560 ;
        RECT 363.130 0.280 363.210 0.560 ;
        RECT 364.050 0.280 364.130 0.560 ;
        RECT 364.970 0.280 365.050 0.560 ;
        RECT 365.890 0.280 365.970 0.560 ;
        RECT 366.810 0.280 366.890 0.560 ;
        RECT 367.730 0.280 367.810 0.560 ;
        RECT 368.650 0.280 368.730 0.560 ;
        RECT 369.570 0.280 369.650 0.560 ;
        RECT 370.490 0.280 370.570 0.560 ;
        RECT 371.410 0.280 371.490 0.560 ;
        RECT 372.330 0.280 372.410 0.560 ;
        RECT 373.250 0.280 373.330 0.560 ;
        RECT 374.170 0.280 374.250 0.560 ;
        RECT 375.090 0.280 375.170 0.560 ;
        RECT 376.010 0.280 376.090 0.560 ;
        RECT 376.930 0.280 377.010 0.560 ;
        RECT 377.850 0.280 377.930 0.560 ;
        RECT 378.770 0.280 378.850 0.560 ;
        RECT 379.690 0.280 379.770 0.560 ;
        RECT 380.610 0.280 380.690 0.560 ;
        RECT 381.530 0.280 381.610 0.560 ;
        RECT 382.450 0.280 382.530 0.560 ;
        RECT 383.370 0.280 383.450 0.560 ;
        RECT 384.290 0.280 384.370 0.560 ;
        RECT 385.210 0.280 385.290 0.560 ;
        RECT 386.130 0.280 386.210 0.560 ;
        RECT 387.050 0.280 387.130 0.560 ;
        RECT 387.970 0.280 388.050 0.560 ;
        RECT 388.890 0.280 388.970 0.560 ;
        RECT 389.810 0.280 389.890 0.560 ;
        RECT 390.730 0.280 390.810 0.560 ;
        RECT 391.650 0.280 391.730 0.560 ;
        RECT 392.570 0.280 392.650 0.560 ;
        RECT 393.490 0.280 393.570 0.560 ;
        RECT 394.410 0.280 394.490 0.560 ;
        RECT 395.330 0.280 395.410 0.560 ;
        RECT 396.250 0.280 396.330 0.560 ;
        RECT 397.170 0.280 397.250 0.560 ;
        RECT 398.090 0.280 398.170 0.560 ;
        RECT 399.010 0.280 399.090 0.560 ;
        RECT 399.930 0.280 400.010 0.560 ;
        RECT 400.850 0.280 400.930 0.560 ;
        RECT 401.770 0.280 401.850 0.560 ;
        RECT 402.690 0.280 402.770 0.560 ;
        RECT 403.610 0.280 403.690 0.560 ;
        RECT 404.530 0.280 404.610 0.560 ;
        RECT 405.450 0.280 405.530 0.560 ;
        RECT 406.370 0.280 406.450 0.560 ;
        RECT 407.290 0.280 407.370 0.560 ;
        RECT 408.210 0.280 408.290 0.560 ;
        RECT 409.130 0.280 409.210 0.560 ;
        RECT 410.050 0.280 410.130 0.560 ;
        RECT 410.970 0.280 411.050 0.560 ;
        RECT 411.890 0.280 411.970 0.560 ;
        RECT 412.810 0.280 412.890 0.560 ;
        RECT 413.730 0.280 413.810 0.560 ;
        RECT 414.650 0.280 414.730 0.560 ;
        RECT 415.570 0.280 415.650 0.560 ;
        RECT 416.490 0.280 416.570 0.560 ;
        RECT 417.410 0.280 417.490 0.560 ;
        RECT 418.330 0.280 418.410 0.560 ;
        RECT 419.250 0.280 419.330 0.560 ;
        RECT 420.170 0.280 420.250 0.560 ;
        RECT 421.090 0.280 421.170 0.560 ;
        RECT 422.010 0.280 422.090 0.560 ;
        RECT 422.930 0.280 423.010 0.560 ;
        RECT 423.850 0.280 423.930 0.560 ;
        RECT 424.770 0.280 424.850 0.560 ;
        RECT 425.690 0.280 425.770 0.560 ;
        RECT 426.610 0.280 426.690 0.560 ;
        RECT 427.530 0.280 427.610 0.560 ;
        RECT 428.450 0.280 428.530 0.560 ;
        RECT 429.370 0.280 429.450 0.560 ;
        RECT 430.290 0.280 430.370 0.560 ;
        RECT 431.210 0.280 431.290 0.560 ;
        RECT 432.130 0.280 432.210 0.560 ;
        RECT 433.050 0.280 433.130 0.560 ;
        RECT 433.970 0.280 434.050 0.560 ;
        RECT 434.890 0.280 434.970 0.560 ;
        RECT 435.810 0.280 435.890 0.560 ;
        RECT 436.730 0.280 436.810 0.560 ;
        RECT 437.650 0.280 437.730 0.560 ;
        RECT 438.570 0.280 438.650 0.560 ;
        RECT 439.490 0.280 439.570 0.560 ;
        RECT 440.410 0.280 440.490 0.560 ;
        RECT 441.330 0.280 441.410 0.560 ;
        RECT 442.250 0.280 442.330 0.560 ;
        RECT 443.170 0.280 443.250 0.560 ;
        RECT 444.090 0.280 444.170 0.560 ;
        RECT 445.010 0.280 445.090 0.560 ;
        RECT 445.930 0.280 446.010 0.560 ;
        RECT 446.850 0.280 446.930 0.560 ;
        RECT 447.770 0.280 447.850 0.560 ;
        RECT 448.690 0.280 448.770 0.560 ;
        RECT 449.610 0.280 449.690 0.560 ;
        RECT 450.530 0.280 450.610 0.560 ;
        RECT 451.450 0.280 451.530 0.560 ;
        RECT 452.370 0.280 452.450 0.560 ;
        RECT 453.290 0.280 453.370 0.560 ;
        RECT 454.210 0.280 454.290 0.560 ;
        RECT 455.130 0.280 455.210 0.560 ;
        RECT 456.050 0.280 456.130 0.560 ;
        RECT 456.970 0.280 457.050 0.560 ;
        RECT 457.890 0.280 457.970 0.560 ;
        RECT 458.810 0.280 458.890 0.560 ;
        RECT 459.730 0.280 459.810 0.560 ;
        RECT 460.650 0.280 460.730 0.560 ;
        RECT 461.570 0.280 461.650 0.560 ;
        RECT 462.490 0.280 462.570 0.560 ;
        RECT 463.410 0.280 463.490 0.560 ;
        RECT 464.330 0.280 464.410 0.560 ;
        RECT 465.250 0.280 465.330 0.560 ;
        RECT 466.170 0.280 466.250 0.560 ;
        RECT 467.090 0.280 467.170 0.560 ;
        RECT 468.010 0.280 468.090 0.560 ;
        RECT 468.930 0.280 469.010 0.560 ;
        RECT 469.850 0.280 469.930 0.560 ;
        RECT 470.770 0.280 470.850 0.560 ;
        RECT 471.690 0.280 471.770 0.560 ;
        RECT 472.610 0.280 472.690 0.560 ;
        RECT 473.530 0.280 473.610 0.560 ;
        RECT 474.450 0.280 474.530 0.560 ;
        RECT 475.370 0.280 475.450 0.560 ;
        RECT 476.290 0.280 476.370 0.560 ;
        RECT 477.210 0.280 477.290 0.560 ;
        RECT 478.130 0.280 478.210 0.560 ;
        RECT 479.050 0.280 479.130 0.560 ;
        RECT 479.970 0.280 480.050 0.560 ;
        RECT 480.890 0.280 480.970 0.560 ;
        RECT 481.810 0.280 481.890 0.560 ;
        RECT 482.730 0.280 482.810 0.560 ;
        RECT 483.650 0.280 483.730 0.560 ;
        RECT 484.570 0.280 484.650 0.560 ;
        RECT 485.490 0.280 485.570 0.560 ;
        RECT 486.410 0.280 486.490 0.560 ;
        RECT 487.330 0.280 487.410 0.560 ;
        RECT 488.250 0.280 488.330 0.560 ;
        RECT 489.170 0.280 489.250 0.560 ;
        RECT 490.090 0.280 490.170 0.560 ;
        RECT 491.010 0.280 491.090 0.560 ;
        RECT 491.930 0.280 492.010 0.560 ;
        RECT 492.850 0.280 492.930 0.560 ;
        RECT 493.770 0.280 493.850 0.560 ;
        RECT 494.690 0.280 494.770 0.560 ;
        RECT 495.610 0.280 495.690 0.560 ;
        RECT 496.530 0.280 496.610 0.560 ;
        RECT 497.450 0.280 497.530 0.560 ;
        RECT 498.370 0.280 498.450 0.560 ;
        RECT 499.290 0.280 504.530 0.560 ;
      LAYER met3 ;
        RECT 0.600 511.040 508.800 511.185 ;
        RECT 0.600 417.200 508.400 511.040 ;
        RECT 1.000 298.840 508.400 417.200 ;
        RECT 0.600 293.440 508.400 298.840 ;
        RECT 1.000 282.520 508.400 293.440 ;
        RECT 0.600 245.840 508.400 282.520 ;
        RECT 1.000 243.080 508.400 245.840 ;
        RECT 0.600 205.040 508.400 243.080 ;
        RECT 1.000 199.560 508.400 205.040 ;
        RECT 0.600 192.800 508.400 199.560 ;
        RECT 1.000 190.040 508.400 192.800 ;
        RECT 0.600 165.600 508.400 190.040 ;
        RECT 1.000 150.600 508.400 165.600 ;
        RECT 0.600 146.560 508.400 150.600 ;
        RECT 1.000 145.160 508.400 146.560 ;
        RECT 0.600 143.840 508.400 145.160 ;
        RECT 1.000 51.320 508.400 143.840 ;
        RECT 1.000 14.600 508.800 51.320 ;
        RECT 0.600 5.615 508.800 14.600 ;
      LAYER met4 ;
        RECT 74.815 509.280 495.585 511.185 ;
        RECT 74.815 11.310 174.240 509.280 ;
        RECT 176.640 11.310 177.540 509.280 ;
        RECT 179.940 11.310 327.840 509.280 ;
        RECT 330.240 11.310 331.140 509.280 ;
        RECT 333.540 11.310 481.440 509.280 ;
        RECT 483.840 11.310 484.740 509.280 ;
        RECT 487.140 11.310 495.585 509.280 ;
      LAYER met5 ;
        RECT 461.500 11.100 470.460 12.700 ;
  END
END axi4_crossbar
END LIBRARY

